###############################################################
#  Generated by:      Cadence Innovus 20.13-s083_1
#  OS:                Linux x86_64(Host ID caddy15)
#  Generated on:      Mon Jun 14 11:36:20 2021
#  Design:            user_proj_example
#  Command:           write_lef_abstract -specifyTopLayer 6 -PGPinLayers {5 6} -noCutObs -stripePin results/user_proj_example.lef
###############################################################

VERSION 5.8 ;

BUSBITCHARS "[]" ;
DIVIDERCHAR "/" ;

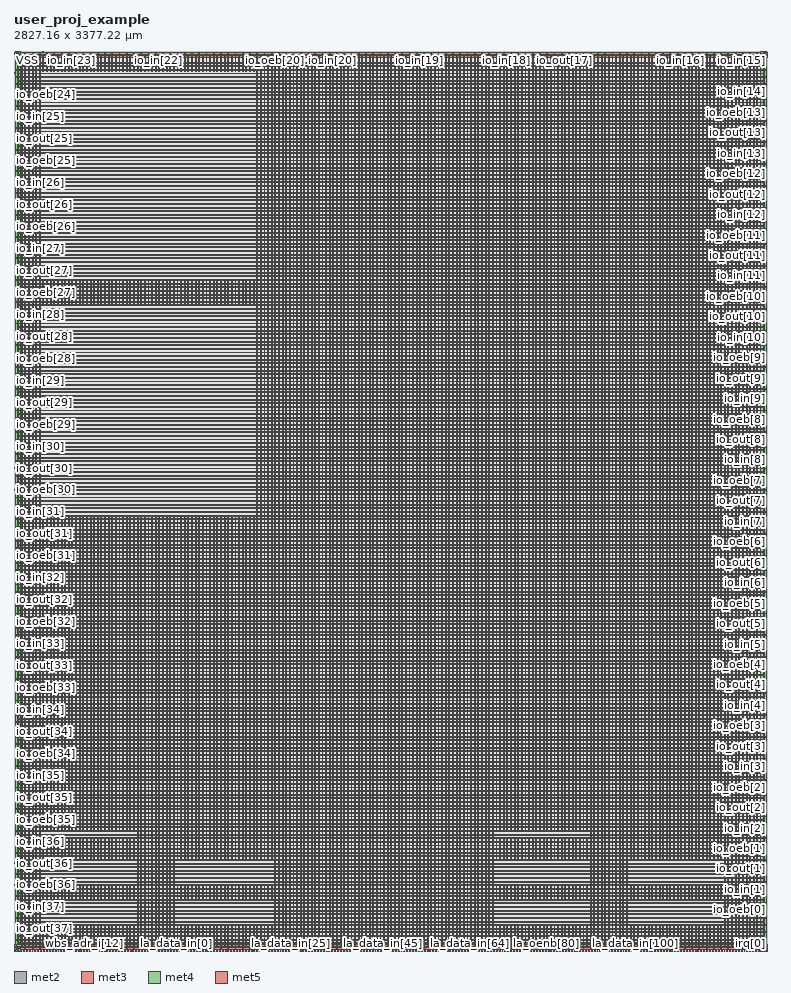
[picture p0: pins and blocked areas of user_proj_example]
MACRO user_proj_example
  CLASS BLOCK ;
  SIZE 2827.160000 BY 3377.220000 ;
  FOREIGN user_proj_example 0.000000 0.000000 ;
  ORIGIN 0 0 ;
  SYMMETRY X Y R90 ;
  PIN wb_clk_i
    DIRECTION INPUT ;
    USE SIGNAL ;
    ANTENNAPARTIALMETALAREA 4.2672 LAYER met2  ;
    ANTENNAPARTIALMETALSIDEAREA 21.175 LAYER met2  ;
    ANTENNAPARTIALCUTAREA 0.04 LAYER via2  ;
    ANTENNAPARTIALMETALAREA 9.3648 LAYER met3  ;
    ANTENNAPARTIALMETALSIDEAREA 50.416 LAYER met3  ;
    ANTENNAMODEL OXIDE1 ;
    ANTENNAGATEAREA 1.152 LAYER met3  ;
    ANTENNAMAXAREACAR 8.78331 LAYER met3  ;
    ANTENNAMAXSIDEAREACAR 45.1719 LAYER met3  ;
    ANTENNAMAXCUTCAR 0.0793403 LAYER via3  ;
    PORT
      LAYER met2 ;
        RECT 0.160000 0.000000 0.300000 0.485000 ;
    END
  END wb_clk_i
  PIN wb_rst_i
    DIRECTION INPUT ;
    USE SIGNAL ;
    ANTENNAPARTIALMETALAREA 4.4911 LAYER met2  ;
    ANTENNAPARTIALMETALSIDEAREA 22.3475 LAYER met2  ;
    ANTENNAMODEL OXIDE1 ;
    ANTENNAGATEAREA 1.33 LAYER met2  ;
    ANTENNAMAXAREACAR 6.34038 LAYER met2  ;
    ANTENNAMAXSIDEAREACAR 30.9594 LAYER met2  ;
    ANTENNAMAXCUTCAR 0.0386466 LAYER via2  ;
    PORT
      LAYER met2 ;
        RECT 6.140000 0.000000 6.280000 0.485000 ;
    END
  END wb_rst_i
  PIN wbs_stb_i
    DIRECTION INPUT ;
    USE SIGNAL ;
    PORT
      LAYER met2 ;
        RECT 23.160000 0.000000 23.300000 0.485000 ;
    END
  END wbs_stb_i
  PIN wbs_cyc_i
    DIRECTION INPUT ;
    USE SIGNAL ;
    PORT
      LAYER met2 ;
        RECT 17.640000 0.000000 17.780000 0.485000 ;
    END
  END wbs_cyc_i
  PIN wbs_we_i
    DIRECTION INPUT ;
    USE SIGNAL ;
    PORT
      LAYER met2 ;
        RECT 29.140000 0.000000 29.280000 0.485000 ;
    END
  END wbs_we_i
  PIN wbs_sel_i[3]
    DIRECTION INPUT ;
    USE SIGNAL ;
    PORT
      LAYER met2 ;
        RECT 121.140000 0.000000 121.280000 0.485000 ;
    END
  END wbs_sel_i[3]
  PIN wbs_sel_i[2]
    DIRECTION INPUT ;
    USE SIGNAL ;
    PORT
      LAYER met2 ;
        RECT 98.140000 0.000000 98.280000 0.485000 ;
    END
  END wbs_sel_i[2]
  PIN wbs_sel_i[1]
    DIRECTION INPUT ;
    USE SIGNAL ;
    PORT
      LAYER met2 ;
        RECT 75.140000 0.000000 75.280000 0.485000 ;
    END
  END wbs_sel_i[1]
  PIN wbs_sel_i[0]
    DIRECTION INPUT ;
    USE SIGNAL ;
    PORT
      LAYER met2 ;
        RECT 52.140000 0.000000 52.280000 0.485000 ;
    END
  END wbs_sel_i[0]
  PIN wbs_dat_i[31]
    DIRECTION INPUT ;
    USE SIGNAL ;
    PORT
      LAYER met2 ;
        RECT 597.700000 0.000000 597.840000 0.485000 ;
    END
  END wbs_dat_i[31]
  PIN wbs_dat_i[30]
    DIRECTION INPUT ;
    USE SIGNAL ;
    PORT
      LAYER met2 ;
        RECT 580.680000 0.000000 580.820000 0.485000 ;
    END
  END wbs_dat_i[30]
  PIN wbs_dat_i[29]
    DIRECTION INPUT ;
    USE SIGNAL ;
    PORT
      LAYER met2 ;
        RECT 563.660000 0.000000 563.800000 0.485000 ;
    END
  END wbs_dat_i[29]
  PIN wbs_dat_i[28]
    DIRECTION INPUT ;
    USE SIGNAL ;
    PORT
      LAYER met2 ;
        RECT 546.180000 0.000000 546.320000 0.485000 ;
    END
  END wbs_dat_i[28]
  PIN wbs_dat_i[27]
    DIRECTION INPUT ;
    USE SIGNAL ;
    PORT
      LAYER met2 ;
        RECT 529.160000 0.000000 529.300000 0.485000 ;
    END
  END wbs_dat_i[27]
  PIN wbs_dat_i[26]
    DIRECTION INPUT ;
    USE SIGNAL ;
    PORT
      LAYER met2 ;
        RECT 511.680000 0.000000 511.820000 0.485000 ;
    END
  END wbs_dat_i[26]
  PIN wbs_dat_i[25]
    DIRECTION INPUT ;
    USE SIGNAL ;
    PORT
      LAYER met2 ;
        RECT 494.660000 0.000000 494.800000 0.485000 ;
    END
  END wbs_dat_i[25]
  PIN wbs_dat_i[24]
    DIRECTION INPUT ;
    USE SIGNAL ;
    PORT
      LAYER met2 ;
        RECT 477.180000 0.000000 477.320000 0.485000 ;
    END
  END wbs_dat_i[24]
  PIN wbs_dat_i[23]
    DIRECTION INPUT ;
    USE SIGNAL ;
    PORT
      LAYER met2 ;
        RECT 460.160000 0.000000 460.300000 0.485000 ;
    END
  END wbs_dat_i[23]
  PIN wbs_dat_i[22]
    DIRECTION INPUT ;
    USE SIGNAL ;
    PORT
      LAYER met2 ;
        RECT 442.680000 0.000000 442.820000 0.485000 ;
    END
  END wbs_dat_i[22]
  PIN wbs_dat_i[21]
    DIRECTION INPUT ;
    USE SIGNAL ;
    PORT
      LAYER met2 ;
        RECT 425.660000 0.000000 425.800000 0.485000 ;
    END
  END wbs_dat_i[21]
  PIN wbs_dat_i[20]
    DIRECTION INPUT ;
    USE SIGNAL ;
    PORT
      LAYER met2 ;
        RECT 408.180000 0.000000 408.320000 0.485000 ;
    END
  END wbs_dat_i[20]
  PIN wbs_dat_i[19]
    DIRECTION INPUT ;
    USE SIGNAL ;
    PORT
      LAYER met2 ;
        RECT 391.160000 0.000000 391.300000 0.485000 ;
    END
  END wbs_dat_i[19]
  PIN wbs_dat_i[18]
    DIRECTION INPUT ;
    USE SIGNAL ;
    PORT
      LAYER met2 ;
        RECT 373.680000 0.000000 373.820000 0.485000 ;
    END
  END wbs_dat_i[18]
  PIN wbs_dat_i[17]
    DIRECTION INPUT ;
    USE SIGNAL ;
    PORT
      LAYER met2 ;
        RECT 356.660000 0.000000 356.800000 0.485000 ;
    END
  END wbs_dat_i[17]
  PIN wbs_dat_i[16]
    DIRECTION INPUT ;
    USE SIGNAL ;
    PORT
      LAYER met2 ;
        RECT 339.180000 0.000000 339.320000 0.485000 ;
    END
  END wbs_dat_i[16]
  PIN wbs_dat_i[15]
    DIRECTION INPUT ;
    USE SIGNAL ;
    PORT
      LAYER met2 ;
        RECT 322.160000 0.000000 322.300000 0.485000 ;
    END
  END wbs_dat_i[15]
  PIN wbs_dat_i[14]
    DIRECTION INPUT ;
    USE SIGNAL ;
    PORT
      LAYER met2 ;
        RECT 304.680000 0.000000 304.820000 0.485000 ;
    END
  END wbs_dat_i[14]
  PIN wbs_dat_i[13]
    DIRECTION INPUT ;
    USE SIGNAL ;
    PORT
      LAYER met2 ;
        RECT 287.660000 0.000000 287.800000 0.485000 ;
    END
  END wbs_dat_i[13]
  PIN wbs_dat_i[12]
    DIRECTION INPUT ;
    USE SIGNAL ;
    PORT
      LAYER met2 ;
        RECT 270.640000 0.000000 270.780000 0.485000 ;
    END
  END wbs_dat_i[12]
  PIN wbs_dat_i[11]
    DIRECTION INPUT ;
    USE SIGNAL ;
    PORT
      LAYER met2 ;
        RECT 253.160000 0.000000 253.300000 0.485000 ;
    END
  END wbs_dat_i[11]
  PIN wbs_dat_i[10]
    DIRECTION INPUT ;
    USE SIGNAL ;
    PORT
      LAYER met2 ;
        RECT 236.140000 0.000000 236.280000 0.485000 ;
    END
  END wbs_dat_i[10]
  PIN wbs_dat_i[9]
    DIRECTION INPUT ;
    USE SIGNAL ;
    PORT
      LAYER met2 ;
        RECT 218.660000 0.000000 218.800000 0.485000 ;
    END
  END wbs_dat_i[9]
  PIN wbs_dat_i[8]
    DIRECTION INPUT ;
    USE SIGNAL ;
    PORT
      LAYER met2 ;
        RECT 201.640000 0.000000 201.780000 0.485000 ;
    END
  END wbs_dat_i[8]
  PIN wbs_dat_i[7]
    DIRECTION INPUT ;
    USE SIGNAL ;
    PORT
      LAYER met2 ;
        RECT 184.160000 0.000000 184.300000 0.485000 ;
    END
  END wbs_dat_i[7]
  PIN wbs_dat_i[6]
    DIRECTION INPUT ;
    USE SIGNAL ;
    PORT
      LAYER met2 ;
        RECT 167.140000 0.000000 167.280000 0.485000 ;
    END
  END wbs_dat_i[6]
  PIN wbs_dat_i[5]
    DIRECTION INPUT ;
    USE SIGNAL ;
    PORT
      LAYER met2 ;
        RECT 149.660000 0.000000 149.800000 0.485000 ;
    END
  END wbs_dat_i[5]
  PIN wbs_dat_i[4]
    DIRECTION INPUT ;
    USE SIGNAL ;
    PORT
      LAYER met2 ;
        RECT 132.640000 0.000000 132.780000 0.485000 ;
    END
  END wbs_dat_i[4]
  PIN wbs_dat_i[3]
    DIRECTION INPUT ;
    USE SIGNAL ;
    PORT
      LAYER met2 ;
        RECT 109.640000 0.000000 109.780000 0.485000 ;
    END
  END wbs_dat_i[3]
  PIN wbs_dat_i[2]
    DIRECTION INPUT ;
    USE SIGNAL ;
    PORT
      LAYER met2 ;
        RECT 86.640000 0.000000 86.780000 0.485000 ;
    END
  END wbs_dat_i[2]
  PIN wbs_dat_i[1]
    DIRECTION INPUT ;
    USE SIGNAL ;
    PORT
      LAYER met2 ;
        RECT 63.640000 0.000000 63.780000 0.485000 ;
    END
  END wbs_dat_i[1]
  PIN wbs_dat_i[0]
    DIRECTION INPUT ;
    USE SIGNAL ;
    PORT
      LAYER met2 ;
        RECT 40.640000 0.000000 40.780000 0.485000 ;
    END
  END wbs_dat_i[0]
  PIN wbs_adr_i[31]
    DIRECTION INPUT ;
    USE SIGNAL ;
    PORT
      LAYER met2 ;
        RECT 592.180000 0.000000 592.320000 0.485000 ;
    END
  END wbs_adr_i[31]
  PIN wbs_adr_i[30]
    DIRECTION INPUT ;
    USE SIGNAL ;
    PORT
      LAYER met2 ;
        RECT 574.700000 0.000000 574.840000 0.485000 ;
    END
  END wbs_adr_i[30]
  PIN wbs_adr_i[29]
    DIRECTION INPUT ;
    USE SIGNAL ;
    PORT
      LAYER met2 ;
        RECT 557.680000 0.000000 557.820000 0.485000 ;
    END
  END wbs_adr_i[29]
  PIN wbs_adr_i[28]
    DIRECTION INPUT ;
    USE SIGNAL ;
    PORT
      LAYER met2 ;
        RECT 540.660000 0.000000 540.800000 0.485000 ;
    END
  END wbs_adr_i[28]
  PIN wbs_adr_i[27]
    DIRECTION INPUT ;
    USE SIGNAL ;
    PORT
      LAYER met2 ;
        RECT 523.180000 0.000000 523.320000 0.485000 ;
    END
  END wbs_adr_i[27]
  PIN wbs_adr_i[26]
    DIRECTION INPUT ;
    USE SIGNAL ;
    PORT
      LAYER met2 ;
        RECT 506.160000 0.000000 506.300000 0.485000 ;
    END
  END wbs_adr_i[26]
  PIN wbs_adr_i[25]
    DIRECTION INPUT ;
    USE SIGNAL ;
    PORT
      LAYER met2 ;
        RECT 488.680000 0.000000 488.820000 0.485000 ;
    END
  END wbs_adr_i[25]
  PIN wbs_adr_i[24]
    DIRECTION INPUT ;
    USE SIGNAL ;
    PORT
      LAYER met2 ;
        RECT 471.660000 0.000000 471.800000 0.485000 ;
    END
  END wbs_adr_i[24]
  PIN wbs_adr_i[23]
    DIRECTION INPUT ;
    USE SIGNAL ;
    PORT
      LAYER met2 ;
        RECT 454.180000 0.000000 454.320000 0.485000 ;
    END
  END wbs_adr_i[23]
  PIN wbs_adr_i[22]
    DIRECTION INPUT ;
    USE SIGNAL ;
    PORT
      LAYER met2 ;
        RECT 437.160000 0.000000 437.300000 0.485000 ;
    END
  END wbs_adr_i[22]
  PIN wbs_adr_i[21]
    DIRECTION INPUT ;
    USE SIGNAL ;
    PORT
      LAYER met2 ;
        RECT 419.680000 0.000000 419.820000 0.485000 ;
    END
  END wbs_adr_i[21]
  PIN wbs_adr_i[20]
    DIRECTION INPUT ;
    USE SIGNAL ;
    PORT
      LAYER met2 ;
        RECT 402.660000 0.000000 402.800000 0.485000 ;
    END
  END wbs_adr_i[20]
  PIN wbs_adr_i[19]
    DIRECTION INPUT ;
    USE SIGNAL ;
    PORT
      LAYER met2 ;
        RECT 385.180000 0.000000 385.320000 0.485000 ;
    END
  END wbs_adr_i[19]
  PIN wbs_adr_i[18]
    DIRECTION INPUT ;
    USE SIGNAL ;
    PORT
      LAYER met2 ;
        RECT 368.160000 0.000000 368.300000 0.485000 ;
    END
  END wbs_adr_i[18]
  PIN wbs_adr_i[17]
    DIRECTION INPUT ;
    USE SIGNAL ;
    PORT
      LAYER met2 ;
        RECT 350.680000 0.000000 350.820000 0.485000 ;
    END
  END wbs_adr_i[17]
  PIN wbs_adr_i[16]
    DIRECTION INPUT ;
    USE SIGNAL ;
    PORT
      LAYER met2 ;
        RECT 333.660000 0.000000 333.800000 0.485000 ;
    END
  END wbs_adr_i[16]
  PIN wbs_adr_i[15]
    DIRECTION INPUT ;
    USE SIGNAL ;
    PORT
      LAYER met2 ;
        RECT 316.180000 0.000000 316.320000 0.485000 ;
    END
  END wbs_adr_i[15]
  PIN wbs_adr_i[14]
    DIRECTION INPUT ;
    USE SIGNAL ;
    PORT
      LAYER met2 ;
        RECT 299.160000 0.000000 299.300000 0.485000 ;
    END
  END wbs_adr_i[14]
  PIN wbs_adr_i[13]
    DIRECTION INPUT ;
    USE SIGNAL ;
    PORT
      LAYER met2 ;
        RECT 282.140000 0.000000 282.280000 0.485000 ;
    END
  END wbs_adr_i[13]
  PIN wbs_adr_i[12]
    DIRECTION INPUT ;
    USE SIGNAL ;
    PORT
      LAYER met2 ;
        RECT 264.660000 0.000000 264.800000 0.485000 ;
    END
  END wbs_adr_i[12]
  PIN wbs_adr_i[11]
    DIRECTION INPUT ;
    USE SIGNAL ;
    PORT
      LAYER met2 ;
        RECT 247.640000 0.000000 247.780000 0.485000 ;
    END
  END wbs_adr_i[11]
  PIN wbs_adr_i[10]
    DIRECTION INPUT ;
    USE SIGNAL ;
    PORT
      LAYER met2 ;
        RECT 230.160000 0.000000 230.300000 0.485000 ;
    END
  END wbs_adr_i[10]
  PIN wbs_adr_i[9]
    DIRECTION INPUT ;
    USE SIGNAL ;
    PORT
      LAYER met2 ;
        RECT 213.140000 0.000000 213.280000 0.485000 ;
    END
  END wbs_adr_i[9]
  PIN wbs_adr_i[8]
    DIRECTION INPUT ;
    USE SIGNAL ;
    PORT
      LAYER met2 ;
        RECT 195.660000 0.000000 195.800000 0.485000 ;
    END
  END wbs_adr_i[8]
  PIN wbs_adr_i[7]
    DIRECTION INPUT ;
    USE SIGNAL ;
    PORT
      LAYER met2 ;
        RECT 178.640000 0.000000 178.780000 0.485000 ;
    END
  END wbs_adr_i[7]
  PIN wbs_adr_i[6]
    DIRECTION INPUT ;
    USE SIGNAL ;
    PORT
      LAYER met2 ;
        RECT 161.160000 0.000000 161.300000 0.485000 ;
    END
  END wbs_adr_i[6]
  PIN wbs_adr_i[5]
    DIRECTION INPUT ;
    USE SIGNAL ;
    PORT
      LAYER met2 ;
        RECT 144.140000 0.000000 144.280000 0.485000 ;
    END
  END wbs_adr_i[5]
  PIN wbs_adr_i[4]
    DIRECTION INPUT ;
    USE SIGNAL ;
    PORT
      LAYER met2 ;
        RECT 126.660000 0.000000 126.800000 0.485000 ;
    END
  END wbs_adr_i[4]
  PIN wbs_adr_i[3]
    DIRECTION INPUT ;
    USE SIGNAL ;
    PORT
      LAYER met2 ;
        RECT 103.660000 0.000000 103.800000 0.485000 ;
    END
  END wbs_adr_i[3]
  PIN wbs_adr_i[2]
    DIRECTION INPUT ;
    USE SIGNAL ;
    PORT
      LAYER met2 ;
        RECT 80.660000 0.000000 80.800000 0.485000 ;
    END
  END wbs_adr_i[2]
  PIN wbs_adr_i[1]
    DIRECTION INPUT ;
    USE SIGNAL ;
    PORT
      LAYER met2 ;
        RECT 57.660000 0.000000 57.800000 0.485000 ;
    END
  END wbs_adr_i[1]
  PIN wbs_adr_i[0]
    DIRECTION INPUT ;
    USE SIGNAL ;
    PORT
      LAYER met2 ;
        RECT 34.660000 0.000000 34.800000 0.485000 ;
    END
  END wbs_adr_i[0]
  PIN wbs_ack_o
    DIRECTION OUTPUT ;
    USE SIGNAL ;
    PORT
      LAYER met2 ;
        RECT 11.660000 0.000000 11.800000 0.485000 ;
    END
  END wbs_ack_o
  PIN wbs_dat_o[31]
    DIRECTION OUTPUT ;
    USE SIGNAL ;
    PORT
      LAYER met2 ;
        RECT 603.680000 0.000000 603.820000 0.485000 ;
    END
  END wbs_dat_o[31]
  PIN wbs_dat_o[30]
    DIRECTION OUTPUT ;
    USE SIGNAL ;
    PORT
      LAYER met2 ;
        RECT 586.200000 0.000000 586.340000 0.485000 ;
    END
  END wbs_dat_o[30]
  PIN wbs_dat_o[29]
    DIRECTION OUTPUT ;
    USE SIGNAL ;
    PORT
      LAYER met2 ;
        RECT 569.180000 0.000000 569.320000 0.485000 ;
    END
  END wbs_dat_o[29]
  PIN wbs_dat_o[28]
    DIRECTION OUTPUT ;
    USE SIGNAL ;
    PORT
      LAYER met2 ;
        RECT 552.160000 0.000000 552.300000 0.485000 ;
    END
  END wbs_dat_o[28]
  PIN wbs_dat_o[27]
    DIRECTION OUTPUT ;
    USE SIGNAL ;
    PORT
      LAYER met2 ;
        RECT 534.680000 0.000000 534.820000 0.485000 ;
    END
  END wbs_dat_o[27]
  PIN wbs_dat_o[26]
    DIRECTION OUTPUT ;
    USE SIGNAL ;
    PORT
      LAYER met2 ;
        RECT 517.660000 0.000000 517.800000 0.485000 ;
    END
  END wbs_dat_o[26]
  PIN wbs_dat_o[25]
    DIRECTION OUTPUT ;
    USE SIGNAL ;
    PORT
      LAYER met2 ;
        RECT 500.180000 0.000000 500.320000 0.485000 ;
    END
  END wbs_dat_o[25]
  PIN wbs_dat_o[24]
    DIRECTION OUTPUT ;
    USE SIGNAL ;
    PORT
      LAYER met2 ;
        RECT 483.160000 0.000000 483.300000 0.485000 ;
    END
  END wbs_dat_o[24]
  PIN wbs_dat_o[23]
    DIRECTION OUTPUT ;
    USE SIGNAL ;
    PORT
      LAYER met2 ;
        RECT 465.680000 0.000000 465.820000 0.485000 ;
    END
  END wbs_dat_o[23]
  PIN wbs_dat_o[22]
    DIRECTION OUTPUT ;
    USE SIGNAL ;
    PORT
      LAYER met2 ;
        RECT 448.660000 0.000000 448.800000 0.485000 ;
    END
  END wbs_dat_o[22]
  PIN wbs_dat_o[21]
    DIRECTION OUTPUT ;
    USE SIGNAL ;
    PORT
      LAYER met2 ;
        RECT 431.180000 0.000000 431.320000 0.485000 ;
    END
  END wbs_dat_o[21]
  PIN wbs_dat_o[20]
    DIRECTION OUTPUT ;
    USE SIGNAL ;
    PORT
      LAYER met2 ;
        RECT 414.160000 0.000000 414.300000 0.485000 ;
    END
  END wbs_dat_o[20]
  PIN wbs_dat_o[19]
    DIRECTION OUTPUT ;
    USE SIGNAL ;
    PORT
      LAYER met2 ;
        RECT 396.680000 0.000000 396.820000 0.485000 ;
    END
  END wbs_dat_o[19]
  PIN wbs_dat_o[18]
    DIRECTION OUTPUT ;
    USE SIGNAL ;
    PORT
      LAYER met2 ;
        RECT 379.660000 0.000000 379.800000 0.485000 ;
    END
  END wbs_dat_o[18]
  PIN wbs_dat_o[17]
    DIRECTION OUTPUT ;
    USE SIGNAL ;
    PORT
      LAYER met2 ;
        RECT 362.180000 0.000000 362.320000 0.485000 ;
    END
  END wbs_dat_o[17]
  PIN wbs_dat_o[16]
    DIRECTION OUTPUT ;
    USE SIGNAL ;
    PORT
      LAYER met2 ;
        RECT 345.160000 0.000000 345.300000 0.485000 ;
    END
  END wbs_dat_o[16]
  PIN wbs_dat_o[15]
    DIRECTION OUTPUT ;
    USE SIGNAL ;
    PORT
      LAYER met2 ;
        RECT 327.680000 0.000000 327.820000 0.485000 ;
    END
  END wbs_dat_o[15]
  PIN wbs_dat_o[14]
    DIRECTION OUTPUT ;
    USE SIGNAL ;
    PORT
      LAYER met2 ;
        RECT 310.660000 0.000000 310.800000 0.485000 ;
    END
  END wbs_dat_o[14]
  PIN wbs_dat_o[13]
    DIRECTION OUTPUT ;
    USE SIGNAL ;
    PORT
      LAYER met2 ;
        RECT 293.180000 0.000000 293.320000 0.485000 ;
    END
  END wbs_dat_o[13]
  PIN wbs_dat_o[12]
    DIRECTION OUTPUT ;
    USE SIGNAL ;
    PORT
      LAYER met2 ;
        RECT 276.160000 0.000000 276.300000 0.485000 ;
    END
  END wbs_dat_o[12]
  PIN wbs_dat_o[11]
    DIRECTION OUTPUT ;
    USE SIGNAL ;
    PORT
      LAYER met2 ;
        RECT 259.140000 0.000000 259.280000 0.485000 ;
    END
  END wbs_dat_o[11]
  PIN wbs_dat_o[10]
    DIRECTION OUTPUT ;
    USE SIGNAL ;
    PORT
      LAYER met2 ;
        RECT 241.660000 0.000000 241.800000 0.485000 ;
    END
  END wbs_dat_o[10]
  PIN wbs_dat_o[9]
    DIRECTION OUTPUT ;
    USE SIGNAL ;
    PORT
      LAYER met2 ;
        RECT 224.640000 0.000000 224.780000 0.485000 ;
    END
  END wbs_dat_o[9]
  PIN wbs_dat_o[8]
    DIRECTION OUTPUT ;
    USE SIGNAL ;
    PORT
      LAYER met2 ;
        RECT 207.160000 0.000000 207.300000 0.485000 ;
    END
  END wbs_dat_o[8]
  PIN wbs_dat_o[7]
    DIRECTION OUTPUT ;
    USE SIGNAL ;
    PORT
      LAYER met2 ;
        RECT 190.140000 0.000000 190.280000 0.485000 ;
    END
  END wbs_dat_o[7]
  PIN wbs_dat_o[6]
    DIRECTION OUTPUT ;
    USE SIGNAL ;
    PORT
      LAYER met2 ;
        RECT 172.660000 0.000000 172.800000 0.485000 ;
    END
  END wbs_dat_o[6]
  PIN wbs_dat_o[5]
    DIRECTION OUTPUT ;
    USE SIGNAL ;
    PORT
      LAYER met2 ;
        RECT 155.640000 0.000000 155.780000 0.485000 ;
    END
  END wbs_dat_o[5]
  PIN wbs_dat_o[4]
    DIRECTION OUTPUT ;
    USE SIGNAL ;
    PORT
      LAYER met2 ;
        RECT 138.160000 0.000000 138.300000 0.485000 ;
    END
  END wbs_dat_o[4]
  PIN wbs_dat_o[3]
    DIRECTION OUTPUT ;
    USE SIGNAL ;
    PORT
      LAYER met2 ;
        RECT 115.160000 0.000000 115.300000 0.485000 ;
    END
  END wbs_dat_o[3]
  PIN wbs_dat_o[2]
    DIRECTION OUTPUT ;
    USE SIGNAL ;
    PORT
      LAYER met2 ;
        RECT 92.160000 0.000000 92.300000 0.485000 ;
    END
  END wbs_dat_o[2]
  PIN wbs_dat_o[1]
    DIRECTION OUTPUT ;
    USE SIGNAL ;
    PORT
      LAYER met2 ;
        RECT 69.160000 0.000000 69.300000 0.485000 ;
    END
  END wbs_dat_o[1]
  PIN wbs_dat_o[0]
    DIRECTION OUTPUT ;
    USE SIGNAL ;
    PORT
      LAYER met2 ;
        RECT 46.160000 0.000000 46.300000 0.485000 ;
    END
  END wbs_dat_o[0]
  PIN la_data_in[127]
    DIRECTION INPUT ;
    USE SIGNAL ;
    PORT
      LAYER met2 ;
        RECT 2798.340000 0.000000 2798.480000 0.485000 ;
    END
  END la_data_in[127]
  PIN la_data_in[126]
    DIRECTION INPUT ;
    USE SIGNAL ;
    PORT
      LAYER met2 ;
        RECT 2781.320000 0.000000 2781.460000 0.485000 ;
    END
  END la_data_in[126]
  PIN la_data_in[125]
    DIRECTION INPUT ;
    USE SIGNAL ;
    PORT
      LAYER met2 ;
        RECT 2763.840000 0.000000 2763.980000 0.485000 ;
    END
  END la_data_in[125]
  PIN la_data_in[124]
    DIRECTION INPUT ;
    USE SIGNAL ;
    PORT
      LAYER met2 ;
        RECT 2746.820000 0.000000 2746.960000 0.485000 ;
    END
  END la_data_in[124]
  PIN la_data_in[123]
    DIRECTION INPUT ;
    USE SIGNAL ;
    PORT
      LAYER met2 ;
        RECT 2729.340000 0.000000 2729.480000 0.485000 ;
    END
  END la_data_in[123]
  PIN la_data_in[122]
    DIRECTION INPUT ;
    USE SIGNAL ;
    PORT
      LAYER met2 ;
        RECT 2712.320000 0.000000 2712.460000 0.485000 ;
    END
  END la_data_in[122]
  PIN la_data_in[121]
    DIRECTION INPUT ;
    USE SIGNAL ;
    PORT
      LAYER met2 ;
        RECT 2694.840000 0.000000 2694.980000 0.485000 ;
    END
  END la_data_in[121]
  PIN la_data_in[120]
    DIRECTION INPUT ;
    USE SIGNAL ;
    PORT
      LAYER met2 ;
        RECT 2677.820000 0.000000 2677.960000 0.485000 ;
    END
  END la_data_in[120]
  PIN la_data_in[119]
    DIRECTION INPUT ;
    USE SIGNAL ;
    PORT
      LAYER met2 ;
        RECT 2660.340000 0.000000 2660.480000 0.485000 ;
    END
  END la_data_in[119]
  PIN la_data_in[118]
    DIRECTION INPUT ;
    USE SIGNAL ;
    PORT
      LAYER met2 ;
        RECT 2643.320000 0.000000 2643.460000 0.485000 ;
    END
  END la_data_in[118]
  PIN la_data_in[117]
    DIRECTION INPUT ;
    USE SIGNAL ;
    PORT
      LAYER met2 ;
        RECT 2625.840000 0.000000 2625.980000 0.485000 ;
    END
  END la_data_in[117]
  PIN la_data_in[116]
    DIRECTION INPUT ;
    USE SIGNAL ;
    PORT
      LAYER met2 ;
        RECT 2608.820000 0.000000 2608.960000 0.485000 ;
    END
  END la_data_in[116]
  PIN la_data_in[115]
    DIRECTION INPUT ;
    USE SIGNAL ;
    PORT
      LAYER met2 ;
        RECT 2591.340000 0.000000 2591.480000 0.485000 ;
    END
  END la_data_in[115]
  PIN la_data_in[114]
    DIRECTION INPUT ;
    USE SIGNAL ;
    PORT
      LAYER met2 ;
        RECT 2574.320000 0.000000 2574.460000 0.485000 ;
    END
  END la_data_in[114]
  PIN la_data_in[113]
    DIRECTION INPUT ;
    USE SIGNAL ;
    PORT
      LAYER met2 ;
        RECT 2556.840000 0.000000 2556.980000 0.485000 ;
    END
  END la_data_in[113]
  PIN la_data_in[112]
    DIRECTION INPUT ;
    USE SIGNAL ;
    PORT
      LAYER met2 ;
        RECT 2539.820000 0.000000 2539.960000 0.485000 ;
    END
  END la_data_in[112]
  PIN la_data_in[111]
    DIRECTION INPUT ;
    USE SIGNAL ;
    PORT
      LAYER met2 ;
        RECT 2522.800000 0.000000 2522.940000 0.485000 ;
    END
  END la_data_in[111]
  PIN la_data_in[110]
    DIRECTION INPUT ;
    USE SIGNAL ;
    PORT
      LAYER met2 ;
        RECT 2505.320000 0.000000 2505.460000 0.485000 ;
    END
  END la_data_in[110]
  PIN la_data_in[109]
    DIRECTION INPUT ;
    USE SIGNAL ;
    PORT
      LAYER met2 ;
        RECT 2488.300000 0.000000 2488.440000 0.485000 ;
    END
  END la_data_in[109]
  PIN la_data_in[108]
    DIRECTION INPUT ;
    USE SIGNAL ;
    PORT
      LAYER met2 ;
        RECT 2470.820000 0.000000 2470.960000 0.485000 ;
    END
  END la_data_in[108]
  PIN la_data_in[107]
    DIRECTION INPUT ;
    USE SIGNAL ;
    PORT
      LAYER met2 ;
        RECT 2453.800000 0.000000 2453.940000 0.485000 ;
    END
  END la_data_in[107]
  PIN la_data_in[106]
    DIRECTION INPUT ;
    USE SIGNAL ;
    PORT
      LAYER met2 ;
        RECT 2436.320000 0.000000 2436.460000 0.485000 ;
    END
  END la_data_in[106]
  PIN la_data_in[105]
    DIRECTION INPUT ;
    USE SIGNAL ;
    PORT
      LAYER met2 ;
        RECT 2419.300000 0.000000 2419.440000 0.485000 ;
    END
  END la_data_in[105]
  PIN la_data_in[104]
    DIRECTION INPUT ;
    USE SIGNAL ;
    PORT
      LAYER met2 ;
        RECT 2401.820000 0.000000 2401.960000 0.485000 ;
    END
  END la_data_in[104]
  PIN la_data_in[103]
    DIRECTION INPUT ;
    USE SIGNAL ;
    PORT
      LAYER met2 ;
        RECT 2384.800000 0.000000 2384.940000 0.485000 ;
    END
  END la_data_in[103]
  PIN la_data_in[102]
    DIRECTION INPUT ;
    USE SIGNAL ;
    PORT
      LAYER met2 ;
        RECT 2367.320000 0.000000 2367.460000 0.485000 ;
    END
  END la_data_in[102]
  PIN la_data_in[101]
    DIRECTION INPUT ;
    USE SIGNAL ;
    PORT
      LAYER met2 ;
        RECT 2350.300000 0.000000 2350.440000 0.485000 ;
    END
  END la_data_in[101]
  PIN la_data_in[100]
    DIRECTION INPUT ;
    USE SIGNAL ;
    PORT
      LAYER met2 ;
        RECT 2332.820000 0.000000 2332.960000 0.485000 ;
    END
  END la_data_in[100]
  PIN la_data_in[99]
    DIRECTION INPUT ;
    USE SIGNAL ;
    PORT
      LAYER met2 ;
        RECT 2315.800000 0.000000 2315.940000 0.485000 ;
    END
  END la_data_in[99]
  PIN la_data_in[98]
    DIRECTION INPUT ;
    USE SIGNAL ;
    PORT
      LAYER met2 ;
        RECT 2298.320000 0.000000 2298.460000 0.485000 ;
    END
  END la_data_in[98]
  PIN la_data_in[97]
    DIRECTION INPUT ;
    USE SIGNAL ;
    PORT
      LAYER met2 ;
        RECT 2281.300000 0.000000 2281.440000 0.485000 ;
    END
  END la_data_in[97]
  PIN la_data_in[96]
    DIRECTION INPUT ;
    USE SIGNAL ;
    PORT
      LAYER met2 ;
        RECT 2263.820000 0.000000 2263.960000 0.485000 ;
    END
  END la_data_in[96]
  PIN la_data_in[95]
    DIRECTION INPUT ;
    USE SIGNAL ;
    PORT
      LAYER met2 ;
        RECT 2246.800000 0.000000 2246.940000 0.485000 ;
    END
  END la_data_in[95]
  PIN la_data_in[94]
    DIRECTION INPUT ;
    USE SIGNAL ;
    PORT
      LAYER met2 ;
        RECT 2229.780000 0.000000 2229.920000 0.485000 ;
    END
  END la_data_in[94]
  PIN la_data_in[93]
    DIRECTION INPUT ;
    USE SIGNAL ;
    PORT
      LAYER met2 ;
        RECT 2212.300000 0.000000 2212.440000 0.485000 ;
    END
  END la_data_in[93]
  PIN la_data_in[92]
    DIRECTION INPUT ;
    USE SIGNAL ;
    PORT
      LAYER met2 ;
        RECT 2195.280000 0.000000 2195.420000 0.485000 ;
    END
  END la_data_in[92]
  PIN la_data_in[91]
    DIRECTION INPUT ;
    USE SIGNAL ;
    PORT
      LAYER met2 ;
        RECT 2177.800000 0.000000 2177.940000 0.485000 ;
    END
  END la_data_in[91]
  PIN la_data_in[90]
    DIRECTION INPUT ;
    USE SIGNAL ;
    PORT
      LAYER met2 ;
        RECT 2160.780000 0.000000 2160.920000 0.485000 ;
    END
  END la_data_in[90]
  PIN la_data_in[89]
    DIRECTION INPUT ;
    USE SIGNAL ;
    PORT
      LAYER met2 ;
        RECT 2143.300000 0.000000 2143.440000 0.485000 ;
    END
  END la_data_in[89]
  PIN la_data_in[88]
    DIRECTION INPUT ;
    USE SIGNAL ;
    PORT
      LAYER met2 ;
        RECT 2126.280000 0.000000 2126.420000 0.485000 ;
    END
  END la_data_in[88]
  PIN la_data_in[87]
    DIRECTION INPUT ;
    USE SIGNAL ;
    PORT
      LAYER met2 ;
        RECT 2108.800000 0.000000 2108.940000 0.485000 ;
    END
  END la_data_in[87]
  PIN la_data_in[86]
    DIRECTION INPUT ;
    USE SIGNAL ;
    PORT
      LAYER met2 ;
        RECT 2091.780000 0.000000 2091.920000 0.485000 ;
    END
  END la_data_in[86]
  PIN la_data_in[85]
    DIRECTION INPUT ;
    USE SIGNAL ;
    PORT
      LAYER met2 ;
        RECT 2074.300000 0.000000 2074.440000 0.485000 ;
    END
  END la_data_in[85]
  PIN la_data_in[84]
    DIRECTION INPUT ;
    USE SIGNAL ;
    PORT
      LAYER met2 ;
        RECT 2057.280000 0.000000 2057.420000 0.485000 ;
    END
  END la_data_in[84]
  PIN la_data_in[83]
    DIRECTION INPUT ;
    USE SIGNAL ;
    PORT
      LAYER met2 ;
        RECT 2039.800000 0.000000 2039.940000 0.485000 ;
    END
  END la_data_in[83]
  PIN la_data_in[82]
    DIRECTION INPUT ;
    USE SIGNAL ;
    PORT
      LAYER met2 ;
        RECT 2022.780000 0.000000 2022.920000 0.485000 ;
    END
  END la_data_in[82]
  PIN la_data_in[81]
    DIRECTION INPUT ;
    USE SIGNAL ;
    PORT
      LAYER met2 ;
        RECT 2005.300000 0.000000 2005.440000 0.485000 ;
    END
  END la_data_in[81]
  PIN la_data_in[80]
    DIRECTION INPUT ;
    USE SIGNAL ;
    PORT
      LAYER met2 ;
        RECT 1988.280000 0.000000 1988.420000 0.485000 ;
    END
  END la_data_in[80]
  PIN la_data_in[79]
    DIRECTION INPUT ;
    USE SIGNAL ;
    PORT
      LAYER met2 ;
        RECT 1971.260000 0.000000 1971.400000 0.485000 ;
    END
  END la_data_in[79]
  PIN la_data_in[78]
    DIRECTION INPUT ;
    USE SIGNAL ;
    PORT
      LAYER met2 ;
        RECT 1953.780000 0.000000 1953.920000 0.485000 ;
    END
  END la_data_in[78]
  PIN la_data_in[77]
    DIRECTION INPUT ;
    USE SIGNAL ;
    PORT
      LAYER met2 ;
        RECT 1936.760000 0.000000 1936.900000 0.485000 ;
    END
  END la_data_in[77]
  PIN la_data_in[76]
    DIRECTION INPUT ;
    USE SIGNAL ;
    PORT
      LAYER met2 ;
        RECT 1919.280000 0.000000 1919.420000 0.485000 ;
    END
  END la_data_in[76]
  PIN la_data_in[75]
    DIRECTION INPUT ;
    USE SIGNAL ;
    PORT
      LAYER met2 ;
        RECT 1902.260000 0.000000 1902.400000 0.485000 ;
    END
  END la_data_in[75]
  PIN la_data_in[74]
    DIRECTION INPUT ;
    USE SIGNAL ;
    PORT
      LAYER met2 ;
        RECT 1884.780000 0.000000 1884.920000 0.485000 ;
    END
  END la_data_in[74]
  PIN la_data_in[73]
    DIRECTION INPUT ;
    USE SIGNAL ;
    PORT
      LAYER met2 ;
        RECT 1867.760000 0.000000 1867.900000 0.485000 ;
    END
  END la_data_in[73]
  PIN la_data_in[72]
    DIRECTION INPUT ;
    USE SIGNAL ;
    PORT
      LAYER met2 ;
        RECT 1850.280000 0.000000 1850.420000 0.485000 ;
    END
  END la_data_in[72]
  PIN la_data_in[71]
    DIRECTION INPUT ;
    USE SIGNAL ;
    PORT
      LAYER met2 ;
        RECT 1833.260000 0.000000 1833.400000 0.485000 ;
    END
  END la_data_in[71]
  PIN la_data_in[70]
    DIRECTION INPUT ;
    USE SIGNAL ;
    PORT
      LAYER met2 ;
        RECT 1815.780000 0.000000 1815.920000 0.485000 ;
    END
  END la_data_in[70]
  PIN la_data_in[69]
    DIRECTION INPUT ;
    USE SIGNAL ;
    PORT
      LAYER met2 ;
        RECT 1798.760000 0.000000 1798.900000 0.485000 ;
    END
  END la_data_in[69]
  PIN la_data_in[68]
    DIRECTION INPUT ;
    USE SIGNAL ;
    PORT
      LAYER met2 ;
        RECT 1781.280000 0.000000 1781.420000 0.485000 ;
    END
  END la_data_in[68]
  PIN la_data_in[67]
    DIRECTION INPUT ;
    USE SIGNAL ;
    PORT
      LAYER met2 ;
        RECT 1764.260000 0.000000 1764.400000 0.485000 ;
    END
  END la_data_in[67]
  PIN la_data_in[66]
    DIRECTION INPUT ;
    USE SIGNAL ;
    PORT
      LAYER met2 ;
        RECT 1746.780000 0.000000 1746.920000 0.485000 ;
    END
  END la_data_in[66]
  PIN la_data_in[65]
    DIRECTION INPUT ;
    USE SIGNAL ;
    PORT
      LAYER met2 ;
        RECT 1729.760000 0.000000 1729.900000 0.485000 ;
    END
  END la_data_in[65]
  PIN la_data_in[64]
    DIRECTION INPUT ;
    USE SIGNAL ;
    PORT
      LAYER met2 ;
        RECT 1712.280000 0.000000 1712.420000 0.485000 ;
    END
  END la_data_in[64]
  PIN la_data_in[63]
    DIRECTION INPUT ;
    USE SIGNAL ;
    PORT
      LAYER met2 ;
        RECT 1695.260000 0.000000 1695.400000 0.485000 ;
    END
  END la_data_in[63]
  PIN la_data_in[62]
    DIRECTION INPUT ;
    USE SIGNAL ;
    PORT
      LAYER met2 ;
        RECT 1678.240000 0.000000 1678.380000 0.485000 ;
    END
  END la_data_in[62]
  PIN la_data_in[61]
    DIRECTION INPUT ;
    USE SIGNAL ;
    PORT
      LAYER met2 ;
        RECT 1660.760000 0.000000 1660.900000 0.485000 ;
    END
  END la_data_in[61]
  PIN la_data_in[60]
    DIRECTION INPUT ;
    USE SIGNAL ;
    PORT
      LAYER met2 ;
        RECT 1643.740000 0.000000 1643.880000 0.485000 ;
    END
  END la_data_in[60]
  PIN la_data_in[59]
    DIRECTION INPUT ;
    USE SIGNAL ;
    PORT
      LAYER met2 ;
        RECT 1626.260000 0.000000 1626.400000 0.485000 ;
    END
  END la_data_in[59]
  PIN la_data_in[58]
    DIRECTION INPUT ;
    USE SIGNAL ;
    PORT
      LAYER met2 ;
        RECT 1609.240000 0.000000 1609.380000 0.485000 ;
    END
  END la_data_in[58]
  PIN la_data_in[57]
    DIRECTION INPUT ;
    USE SIGNAL ;
    PORT
      LAYER met2 ;
        RECT 1591.760000 0.000000 1591.900000 0.485000 ;
    END
  END la_data_in[57]
  PIN la_data_in[56]
    DIRECTION INPUT ;
    USE SIGNAL ;
    PORT
      LAYER met2 ;
        RECT 1574.740000 0.000000 1574.880000 0.485000 ;
    END
  END la_data_in[56]
  PIN la_data_in[55]
    DIRECTION INPUT ;
    USE SIGNAL ;
    PORT
      LAYER met2 ;
        RECT 1557.260000 0.000000 1557.400000 0.485000 ;
    END
  END la_data_in[55]
  PIN la_data_in[54]
    DIRECTION INPUT ;
    USE SIGNAL ;
    PORT
      LAYER met2 ;
        RECT 1540.240000 0.000000 1540.380000 0.485000 ;
    END
  END la_data_in[54]
  PIN la_data_in[53]
    DIRECTION INPUT ;
    USE SIGNAL ;
    PORT
      LAYER met2 ;
        RECT 1522.760000 0.000000 1522.900000 0.485000 ;
    END
  END la_data_in[53]
  PIN la_data_in[52]
    DIRECTION INPUT ;
    USE SIGNAL ;
    PORT
      LAYER met2 ;
        RECT 1505.740000 0.000000 1505.880000 0.485000 ;
    END
  END la_data_in[52]
  PIN la_data_in[51]
    DIRECTION INPUT ;
    USE SIGNAL ;
    PORT
      LAYER met2 ;
        RECT 1488.260000 0.000000 1488.400000 0.485000 ;
    END
  END la_data_in[51]
  PIN la_data_in[50]
    DIRECTION INPUT ;
    USE SIGNAL ;
    PORT
      LAYER met2 ;
        RECT 1471.240000 0.000000 1471.380000 0.485000 ;
    END
  END la_data_in[50]
  PIN la_data_in[49]
    DIRECTION INPUT ;
    USE SIGNAL ;
    PORT
      LAYER met2 ;
        RECT 1453.760000 0.000000 1453.900000 0.485000 ;
    END
  END la_data_in[49]
  PIN la_data_in[48]
    DIRECTION INPUT ;
    USE SIGNAL ;
    PORT
      LAYER met2 ;
        RECT 1436.740000 0.000000 1436.880000 0.485000 ;
    END
  END la_data_in[48]
  PIN la_data_in[47]
    DIRECTION INPUT ;
    USE SIGNAL ;
    PORT
      LAYER met2 ;
        RECT 1419.260000 0.000000 1419.400000 0.485000 ;
    END
  END la_data_in[47]
  PIN la_data_in[46]
    DIRECTION INPUT ;
    USE SIGNAL ;
    PORT
      LAYER met2 ;
        RECT 1402.240000 0.000000 1402.380000 0.485000 ;
    END
  END la_data_in[46]
  PIN la_data_in[45]
    DIRECTION INPUT ;
    USE SIGNAL ;
    PORT
      LAYER met2 ;
        RECT 1385.220000 0.000000 1385.360000 0.485000 ;
    END
  END la_data_in[45]
  PIN la_data_in[44]
    DIRECTION INPUT ;
    USE SIGNAL ;
    PORT
      LAYER met2 ;
        RECT 1367.740000 0.000000 1367.880000 0.485000 ;
    END
  END la_data_in[44]
  PIN la_data_in[43]
    DIRECTION INPUT ;
    USE SIGNAL ;
    PORT
      LAYER met2 ;
        RECT 1350.720000 0.000000 1350.860000 0.485000 ;
    END
  END la_data_in[43]
  PIN la_data_in[42]
    DIRECTION INPUT ;
    USE SIGNAL ;
    PORT
      LAYER met2 ;
        RECT 1333.240000 0.000000 1333.380000 0.485000 ;
    END
  END la_data_in[42]
  PIN la_data_in[41]
    DIRECTION INPUT ;
    USE SIGNAL ;
    PORT
      LAYER met2 ;
        RECT 1316.220000 0.000000 1316.360000 0.485000 ;
    END
  END la_data_in[41]
  PIN la_data_in[40]
    DIRECTION INPUT ;
    USE SIGNAL ;
    PORT
      LAYER met2 ;
        RECT 1298.740000 0.000000 1298.880000 0.485000 ;
    END
  END la_data_in[40]
  PIN la_data_in[39]
    DIRECTION INPUT ;
    USE SIGNAL ;
    PORT
      LAYER met2 ;
        RECT 1281.720000 0.000000 1281.860000 0.485000 ;
    END
  END la_data_in[39]
  PIN la_data_in[38]
    DIRECTION INPUT ;
    USE SIGNAL ;
    PORT
      LAYER met2 ;
        RECT 1264.240000 0.000000 1264.380000 0.485000 ;
    END
  END la_data_in[38]
  PIN la_data_in[37]
    DIRECTION INPUT ;
    USE SIGNAL ;
    PORT
      LAYER met2 ;
        RECT 1247.220000 0.000000 1247.360000 0.485000 ;
    END
  END la_data_in[37]
  PIN la_data_in[36]
    DIRECTION INPUT ;
    USE SIGNAL ;
    PORT
      LAYER met2 ;
        RECT 1229.740000 0.000000 1229.880000 0.485000 ;
    END
  END la_data_in[36]
  PIN la_data_in[35]
    DIRECTION INPUT ;
    USE SIGNAL ;
    PORT
      LAYER met2 ;
        RECT 1212.720000 0.000000 1212.860000 0.485000 ;
    END
  END la_data_in[35]
  PIN la_data_in[34]
    DIRECTION INPUT ;
    USE SIGNAL ;
    PORT
      LAYER met2 ;
        RECT 1195.240000 0.000000 1195.380000 0.485000 ;
    END
  END la_data_in[34]
  PIN la_data_in[33]
    DIRECTION INPUT ;
    USE SIGNAL ;
    PORT
      LAYER met2 ;
        RECT 1178.220000 0.000000 1178.360000 0.485000 ;
    END
  END la_data_in[33]
  PIN la_data_in[32]
    DIRECTION INPUT ;
    USE SIGNAL ;
    PORT
      LAYER met2 ;
        RECT 1160.740000 0.000000 1160.880000 0.485000 ;
    END
  END la_data_in[32]
  PIN la_data_in[31]
    DIRECTION INPUT ;
    USE SIGNAL ;
    PORT
      LAYER met2 ;
        RECT 1143.720000 0.000000 1143.860000 0.485000 ;
    END
  END la_data_in[31]
  PIN la_data_in[30]
    DIRECTION INPUT ;
    USE SIGNAL ;
    PORT
      LAYER met2 ;
        RECT 1126.700000 0.000000 1126.840000 0.485000 ;
    END
  END la_data_in[30]
  PIN la_data_in[29]
    DIRECTION INPUT ;
    USE SIGNAL ;
    PORT
      LAYER met2 ;
        RECT 1109.220000 0.000000 1109.360000 0.485000 ;
    END
  END la_data_in[29]
  PIN la_data_in[28]
    DIRECTION INPUT ;
    USE SIGNAL ;
    PORT
      LAYER met2 ;
        RECT 1092.200000 0.000000 1092.340000 0.485000 ;
    END
  END la_data_in[28]
  PIN la_data_in[27]
    DIRECTION INPUT ;
    USE SIGNAL ;
    PORT
      LAYER met2 ;
        RECT 1074.720000 0.000000 1074.860000 0.485000 ;
    END
  END la_data_in[27]
  PIN la_data_in[26]
    DIRECTION INPUT ;
    USE SIGNAL ;
    PORT
      LAYER met2 ;
        RECT 1057.700000 0.000000 1057.840000 0.485000 ;
    END
  END la_data_in[26]
  PIN la_data_in[25]
    DIRECTION INPUT ;
    USE SIGNAL ;
    PORT
      LAYER met2 ;
        RECT 1040.220000 0.000000 1040.360000 0.485000 ;
    END
  END la_data_in[25]
  PIN la_data_in[24]
    DIRECTION INPUT ;
    USE SIGNAL ;
    PORT
      LAYER met2 ;
        RECT 1023.200000 0.000000 1023.340000 0.485000 ;
    END
  END la_data_in[24]
  PIN la_data_in[23]
    DIRECTION INPUT ;
    USE SIGNAL ;
    PORT
      LAYER met2 ;
        RECT 1005.720000 0.000000 1005.860000 0.485000 ;
    END
  END la_data_in[23]
  PIN la_data_in[22]
    DIRECTION INPUT ;
    USE SIGNAL ;
    PORT
      LAYER met2 ;
        RECT 988.700000 0.000000 988.840000 0.485000 ;
    END
  END la_data_in[22]
  PIN la_data_in[21]
    DIRECTION INPUT ;
    USE SIGNAL ;
    PORT
      LAYER met2 ;
        RECT 971.220000 0.000000 971.360000 0.485000 ;
    END
  END la_data_in[21]
  PIN la_data_in[20]
    DIRECTION INPUT ;
    USE SIGNAL ;
    PORT
      LAYER met2 ;
        RECT 954.200000 0.000000 954.340000 0.485000 ;
    END
  END la_data_in[20]
  PIN la_data_in[19]
    DIRECTION INPUT ;
    USE SIGNAL ;
    PORT
      LAYER met2 ;
        RECT 936.720000 0.000000 936.860000 0.485000 ;
    END
  END la_data_in[19]
  PIN la_data_in[18]
    DIRECTION INPUT ;
    USE SIGNAL ;
    PORT
      LAYER met2 ;
        RECT 919.700000 0.000000 919.840000 0.485000 ;
    END
  END la_data_in[18]
  PIN la_data_in[17]
    DIRECTION INPUT ;
    USE SIGNAL ;
    PORT
      LAYER met2 ;
        RECT 902.220000 0.000000 902.360000 0.485000 ;
    END
  END la_data_in[17]
  PIN la_data_in[16]
    DIRECTION INPUT ;
    USE SIGNAL ;
    PORT
      LAYER met2 ;
        RECT 885.200000 0.000000 885.340000 0.485000 ;
    END
  END la_data_in[16]
  PIN la_data_in[15]
    DIRECTION INPUT ;
    USE SIGNAL ;
    PORT
      LAYER met2 ;
        RECT 867.720000 0.000000 867.860000 0.485000 ;
    END
  END la_data_in[15]
  PIN la_data_in[14]
    DIRECTION INPUT ;
    USE SIGNAL ;
    PORT
      LAYER met2 ;
        RECT 850.700000 0.000000 850.840000 0.485000 ;
    END
  END la_data_in[14]
  PIN la_data_in[13]
    DIRECTION INPUT ;
    USE SIGNAL ;
    PORT
      LAYER met2 ;
        RECT 833.680000 0.000000 833.820000 0.485000 ;
    END
  END la_data_in[13]
  PIN la_data_in[12]
    DIRECTION INPUT ;
    USE SIGNAL ;
    PORT
      LAYER met2 ;
        RECT 816.200000 0.000000 816.340000 0.485000 ;
    END
  END la_data_in[12]
  PIN la_data_in[11]
    DIRECTION INPUT ;
    USE SIGNAL ;
    PORT
      LAYER met2 ;
        RECT 799.180000 0.000000 799.320000 0.485000 ;
    END
  END la_data_in[11]
  PIN la_data_in[10]
    DIRECTION INPUT ;
    USE SIGNAL ;
    PORT
      LAYER met2 ;
        RECT 781.700000 0.000000 781.840000 0.485000 ;
    END
  END la_data_in[10]
  PIN la_data_in[9]
    DIRECTION INPUT ;
    USE SIGNAL ;
    PORT
      LAYER met2 ;
        RECT 764.680000 0.000000 764.820000 0.485000 ;
    END
  END la_data_in[9]
  PIN la_data_in[8]
    DIRECTION INPUT ;
    USE SIGNAL ;
    PORT
      LAYER met2 ;
        RECT 747.200000 0.000000 747.340000 0.485000 ;
    END
  END la_data_in[8]
  PIN la_data_in[7]
    DIRECTION INPUT ;
    USE SIGNAL ;
    PORT
      LAYER met2 ;
        RECT 730.180000 0.000000 730.320000 0.485000 ;
    END
  END la_data_in[7]
  PIN la_data_in[6]
    DIRECTION INPUT ;
    USE SIGNAL ;
    PORT
      LAYER met2 ;
        RECT 712.700000 0.000000 712.840000 0.485000 ;
    END
  END la_data_in[6]
  PIN la_data_in[5]
    DIRECTION INPUT ;
    USE SIGNAL ;
    PORT
      LAYER met2 ;
        RECT 695.680000 0.000000 695.820000 0.485000 ;
    END
  END la_data_in[5]
  PIN la_data_in[4]
    DIRECTION INPUT ;
    USE SIGNAL ;
    PORT
      LAYER met2 ;
        RECT 678.200000 0.000000 678.340000 0.485000 ;
    END
  END la_data_in[4]
  PIN la_data_in[3]
    DIRECTION INPUT ;
    USE SIGNAL ;
    PORT
      LAYER met2 ;
        RECT 661.180000 0.000000 661.320000 0.485000 ;
    END
  END la_data_in[3]
  PIN la_data_in[2]
    DIRECTION INPUT ;
    USE SIGNAL ;
    PORT
      LAYER met2 ;
        RECT 643.700000 0.000000 643.840000 0.485000 ;
    END
  END la_data_in[2]
  PIN la_data_in[1]
    DIRECTION INPUT ;
    USE SIGNAL ;
    PORT
      LAYER met2 ;
        RECT 626.680000 0.000000 626.820000 0.485000 ;
    END
  END la_data_in[1]
  PIN la_data_in[0]
    DIRECTION INPUT ;
    USE SIGNAL ;
    PORT
      LAYER met2 ;
        RECT 609.200000 0.000000 609.340000 0.485000 ;
    END
  END la_data_in[0]
  PIN la_data_out[127]
    DIRECTION OUTPUT ;
    USE SIGNAL ;
    PORT
      LAYER met2 ;
        RECT 2804.320000 0.000000 2804.460000 0.485000 ;
    END
  END la_data_out[127]
  PIN la_data_out[126]
    DIRECTION OUTPUT ;
    USE SIGNAL ;
    PORT
      LAYER met2 ;
        RECT 2786.840000 0.000000 2786.980000 0.485000 ;
    END
  END la_data_out[126]
  PIN la_data_out[125]
    DIRECTION OUTPUT ;
    USE SIGNAL ;
    PORT
      LAYER met2 ;
        RECT 2769.820000 0.000000 2769.960000 0.485000 ;
    END
  END la_data_out[125]
  PIN la_data_out[124]
    DIRECTION OUTPUT ;
    USE SIGNAL ;
    PORT
      LAYER met2 ;
        RECT 2752.340000 0.000000 2752.480000 0.485000 ;
    END
  END la_data_out[124]
  PIN la_data_out[123]
    DIRECTION OUTPUT ;
    USE SIGNAL ;
    PORT
      LAYER met2 ;
        RECT 2735.320000 0.000000 2735.460000 0.485000 ;
    END
  END la_data_out[123]
  PIN la_data_out[122]
    DIRECTION OUTPUT ;
    USE SIGNAL ;
    PORT
      LAYER met2 ;
        RECT 2717.840000 0.000000 2717.980000 0.485000 ;
    END
  END la_data_out[122]
  PIN la_data_out[121]
    DIRECTION OUTPUT ;
    USE SIGNAL ;
    PORT
      LAYER met2 ;
        RECT 2700.820000 0.000000 2700.960000 0.485000 ;
    END
  END la_data_out[121]
  PIN la_data_out[120]
    DIRECTION OUTPUT ;
    USE SIGNAL ;
    PORT
      LAYER met2 ;
        RECT 2683.340000 0.000000 2683.480000 0.485000 ;
    END
  END la_data_out[120]
  PIN la_data_out[119]
    DIRECTION OUTPUT ;
    USE SIGNAL ;
    PORT
      LAYER met2 ;
        RECT 2666.320000 0.000000 2666.460000 0.485000 ;
    END
  END la_data_out[119]
  PIN la_data_out[118]
    DIRECTION OUTPUT ;
    USE SIGNAL ;
    PORT
      LAYER met2 ;
        RECT 2648.840000 0.000000 2648.980000 0.485000 ;
    END
  END la_data_out[118]
  PIN la_data_out[117]
    DIRECTION OUTPUT ;
    USE SIGNAL ;
    PORT
      LAYER met2 ;
        RECT 2631.820000 0.000000 2631.960000 0.485000 ;
    END
  END la_data_out[117]
  PIN la_data_out[116]
    DIRECTION OUTPUT ;
    USE SIGNAL ;
    PORT
      LAYER met2 ;
        RECT 2614.340000 0.000000 2614.480000 0.485000 ;
    END
  END la_data_out[116]
  PIN la_data_out[115]
    DIRECTION OUTPUT ;
    USE SIGNAL ;
    PORT
      LAYER met2 ;
        RECT 2597.320000 0.000000 2597.460000 0.485000 ;
    END
  END la_data_out[115]
  PIN la_data_out[114]
    DIRECTION OUTPUT ;
    USE SIGNAL ;
    PORT
      LAYER met2 ;
        RECT 2579.840000 0.000000 2579.980000 0.485000 ;
    END
  END la_data_out[114]
  PIN la_data_out[113]
    DIRECTION OUTPUT ;
    USE SIGNAL ;
    PORT
      LAYER met2 ;
        RECT 2562.820000 0.000000 2562.960000 0.485000 ;
    END
  END la_data_out[113]
  PIN la_data_out[112]
    DIRECTION OUTPUT ;
    USE SIGNAL ;
    PORT
      LAYER met2 ;
        RECT 2545.340000 0.000000 2545.480000 0.485000 ;
    END
  END la_data_out[112]
  PIN la_data_out[111]
    DIRECTION OUTPUT ;
    USE SIGNAL ;
    PORT
      LAYER met2 ;
        RECT 2528.320000 0.000000 2528.460000 0.485000 ;
    END
  END la_data_out[111]
  PIN la_data_out[110]
    DIRECTION OUTPUT ;
    USE SIGNAL ;
    PORT
      LAYER met2 ;
        RECT 2511.300000 0.000000 2511.440000 0.485000 ;
    END
  END la_data_out[110]
  PIN la_data_out[109]
    DIRECTION OUTPUT ;
    USE SIGNAL ;
    PORT
      LAYER met2 ;
        RECT 2493.820000 0.000000 2493.960000 0.485000 ;
    END
  END la_data_out[109]
  PIN la_data_out[108]
    DIRECTION OUTPUT ;
    USE SIGNAL ;
    PORT
      LAYER met2 ;
        RECT 2476.800000 0.000000 2476.940000 0.485000 ;
    END
  END la_data_out[108]
  PIN la_data_out[107]
    DIRECTION OUTPUT ;
    USE SIGNAL ;
    PORT
      LAYER met2 ;
        RECT 2459.320000 0.000000 2459.460000 0.485000 ;
    END
  END la_data_out[107]
  PIN la_data_out[106]
    DIRECTION OUTPUT ;
    USE SIGNAL ;
    PORT
      LAYER met2 ;
        RECT 2442.300000 0.000000 2442.440000 0.485000 ;
    END
  END la_data_out[106]
  PIN la_data_out[105]
    DIRECTION OUTPUT ;
    USE SIGNAL ;
    PORT
      LAYER met2 ;
        RECT 2424.820000 0.000000 2424.960000 0.485000 ;
    END
  END la_data_out[105]
  PIN la_data_out[104]
    DIRECTION OUTPUT ;
    USE SIGNAL ;
    PORT
      LAYER met2 ;
        RECT 2407.800000 0.000000 2407.940000 0.485000 ;
    END
  END la_data_out[104]
  PIN la_data_out[103]
    DIRECTION OUTPUT ;
    USE SIGNAL ;
    PORT
      LAYER met2 ;
        RECT 2390.320000 0.000000 2390.460000 0.485000 ;
    END
  END la_data_out[103]
  PIN la_data_out[102]
    DIRECTION OUTPUT ;
    USE SIGNAL ;
    PORT
      LAYER met2 ;
        RECT 2373.300000 0.000000 2373.440000 0.485000 ;
    END
  END la_data_out[102]
  PIN la_data_out[101]
    DIRECTION OUTPUT ;
    USE SIGNAL ;
    PORT
      LAYER met2 ;
        RECT 2355.820000 0.000000 2355.960000 0.485000 ;
    END
  END la_data_out[101]
  PIN la_data_out[100]
    DIRECTION OUTPUT ;
    USE SIGNAL ;
    PORT
      LAYER met2 ;
        RECT 2338.800000 0.000000 2338.940000 0.485000 ;
    END
  END la_data_out[100]
  PIN la_data_out[99]
    DIRECTION OUTPUT ;
    USE SIGNAL ;
    PORT
      LAYER met2 ;
        RECT 2321.320000 0.000000 2321.460000 0.485000 ;
    END
  END la_data_out[99]
  PIN la_data_out[98]
    DIRECTION OUTPUT ;
    USE SIGNAL ;
    PORT
      LAYER met2 ;
        RECT 2304.300000 0.000000 2304.440000 0.485000 ;
    END
  END la_data_out[98]
  PIN la_data_out[97]
    DIRECTION OUTPUT ;
    USE SIGNAL ;
    PORT
      LAYER met2 ;
        RECT 2286.820000 0.000000 2286.960000 0.485000 ;
    END
  END la_data_out[97]
  PIN la_data_out[96]
    DIRECTION OUTPUT ;
    USE SIGNAL ;
    PORT
      LAYER met2 ;
        RECT 2269.800000 0.000000 2269.940000 0.485000 ;
    END
  END la_data_out[96]
  PIN la_data_out[95]
    DIRECTION OUTPUT ;
    USE SIGNAL ;
    PORT
      LAYER met2 ;
        RECT 2252.780000 0.000000 2252.920000 0.485000 ;
    END
  END la_data_out[95]
  PIN la_data_out[94]
    DIRECTION OUTPUT ;
    USE SIGNAL ;
    PORT
      LAYER met2 ;
        RECT 2235.300000 0.000000 2235.440000 0.485000 ;
    END
  END la_data_out[94]
  PIN la_data_out[93]
    DIRECTION OUTPUT ;
    USE SIGNAL ;
    PORT
      LAYER met2 ;
        RECT 2218.280000 0.000000 2218.420000 0.485000 ;
    END
  END la_data_out[93]
  PIN la_data_out[92]
    DIRECTION OUTPUT ;
    USE SIGNAL ;
    PORT
      LAYER met2 ;
        RECT 2200.800000 0.000000 2200.940000 0.485000 ;
    END
  END la_data_out[92]
  PIN la_data_out[91]
    DIRECTION OUTPUT ;
    USE SIGNAL ;
    PORT
      LAYER met2 ;
        RECT 2183.780000 0.000000 2183.920000 0.485000 ;
    END
  END la_data_out[91]
  PIN la_data_out[90]
    DIRECTION OUTPUT ;
    USE SIGNAL ;
    PORT
      LAYER met2 ;
        RECT 2166.300000 0.000000 2166.440000 0.485000 ;
    END
  END la_data_out[90]
  PIN la_data_out[89]
    DIRECTION OUTPUT ;
    USE SIGNAL ;
    PORT
      LAYER met2 ;
        RECT 2149.280000 0.000000 2149.420000 0.485000 ;
    END
  END la_data_out[89]
  PIN la_data_out[88]
    DIRECTION OUTPUT ;
    USE SIGNAL ;
    PORT
      LAYER met2 ;
        RECT 2131.800000 0.000000 2131.940000 0.485000 ;
    END
  END la_data_out[88]
  PIN la_data_out[87]
    DIRECTION OUTPUT ;
    USE SIGNAL ;
    PORT
      LAYER met2 ;
        RECT 2114.780000 0.000000 2114.920000 0.485000 ;
    END
  END la_data_out[87]
  PIN la_data_out[86]
    DIRECTION OUTPUT ;
    USE SIGNAL ;
    PORT
      LAYER met2 ;
        RECT 2097.300000 0.000000 2097.440000 0.485000 ;
    END
  END la_data_out[86]
  PIN la_data_out[85]
    DIRECTION OUTPUT ;
    USE SIGNAL ;
    PORT
      LAYER met2 ;
        RECT 2080.280000 0.000000 2080.420000 0.485000 ;
    END
  END la_data_out[85]
  PIN la_data_out[84]
    DIRECTION OUTPUT ;
    USE SIGNAL ;
    PORT
      LAYER met2 ;
        RECT 2062.800000 0.000000 2062.940000 0.485000 ;
    END
  END la_data_out[84]
  PIN la_data_out[83]
    DIRECTION OUTPUT ;
    USE SIGNAL ;
    PORT
      LAYER met2 ;
        RECT 2045.780000 0.000000 2045.920000 0.485000 ;
    END
  END la_data_out[83]
  PIN la_data_out[82]
    DIRECTION OUTPUT ;
    USE SIGNAL ;
    PORT
      LAYER met2 ;
        RECT 2028.300000 0.000000 2028.440000 0.485000 ;
    END
  END la_data_out[82]
  PIN la_data_out[81]
    DIRECTION OUTPUT ;
    USE SIGNAL ;
    PORT
      LAYER met2 ;
        RECT 2011.280000 0.000000 2011.420000 0.485000 ;
    END
  END la_data_out[81]
  PIN la_data_out[80]
    DIRECTION OUTPUT ;
    USE SIGNAL ;
    PORT
      LAYER met2 ;
        RECT 1993.800000 0.000000 1993.940000 0.485000 ;
    END
  END la_data_out[80]
  PIN la_data_out[79]
    DIRECTION OUTPUT ;
    USE SIGNAL ;
    PORT
      LAYER met2 ;
        RECT 1976.780000 0.000000 1976.920000 0.485000 ;
    END
  END la_data_out[79]
  PIN la_data_out[78]
    DIRECTION OUTPUT ;
    USE SIGNAL ;
    PORT
      LAYER met2 ;
        RECT 1959.760000 0.000000 1959.900000 0.485000 ;
    END
  END la_data_out[78]
  PIN la_data_out[77]
    DIRECTION OUTPUT ;
    USE SIGNAL ;
    PORT
      LAYER met2 ;
        RECT 1942.280000 0.000000 1942.420000 0.485000 ;
    END
  END la_data_out[77]
  PIN la_data_out[76]
    DIRECTION OUTPUT ;
    USE SIGNAL ;
    PORT
      LAYER met2 ;
        RECT 1925.260000 0.000000 1925.400000 0.485000 ;
    END
  END la_data_out[76]
  PIN la_data_out[75]
    DIRECTION OUTPUT ;
    USE SIGNAL ;
    PORT
      LAYER met2 ;
        RECT 1907.780000 0.000000 1907.920000 0.485000 ;
    END
  END la_data_out[75]
  PIN la_data_out[74]
    DIRECTION OUTPUT ;
    USE SIGNAL ;
    PORT
      LAYER met2 ;
        RECT 1890.760000 0.000000 1890.900000 0.485000 ;
    END
  END la_data_out[74]
  PIN la_data_out[73]
    DIRECTION OUTPUT ;
    USE SIGNAL ;
    PORT
      LAYER met2 ;
        RECT 1873.280000 0.000000 1873.420000 0.485000 ;
    END
  END la_data_out[73]
  PIN la_data_out[72]
    DIRECTION OUTPUT ;
    USE SIGNAL ;
    PORT
      LAYER met2 ;
        RECT 1856.260000 0.000000 1856.400000 0.485000 ;
    END
  END la_data_out[72]
  PIN la_data_out[71]
    DIRECTION OUTPUT ;
    USE SIGNAL ;
    PORT
      LAYER met2 ;
        RECT 1838.780000 0.000000 1838.920000 0.485000 ;
    END
  END la_data_out[71]
  PIN la_data_out[70]
    DIRECTION OUTPUT ;
    USE SIGNAL ;
    PORT
      LAYER met2 ;
        RECT 1821.760000 0.000000 1821.900000 0.485000 ;
    END
  END la_data_out[70]
  PIN la_data_out[69]
    DIRECTION OUTPUT ;
    USE SIGNAL ;
    PORT
      LAYER met2 ;
        RECT 1804.280000 0.000000 1804.420000 0.485000 ;
    END
  END la_data_out[69]
  PIN la_data_out[68]
    DIRECTION OUTPUT ;
    USE SIGNAL ;
    PORT
      LAYER met2 ;
        RECT 1787.260000 0.000000 1787.400000 0.485000 ;
    END
  END la_data_out[68]
  PIN la_data_out[67]
    DIRECTION OUTPUT ;
    USE SIGNAL ;
    PORT
      LAYER met2 ;
        RECT 1769.780000 0.000000 1769.920000 0.485000 ;
    END
  END la_data_out[67]
  PIN la_data_out[66]
    DIRECTION OUTPUT ;
    USE SIGNAL ;
    PORT
      LAYER met2 ;
        RECT 1752.760000 0.000000 1752.900000 0.485000 ;
    END
  END la_data_out[66]
  PIN la_data_out[65]
    DIRECTION OUTPUT ;
    USE SIGNAL ;
    PORT
      LAYER met2 ;
        RECT 1735.280000 0.000000 1735.420000 0.485000 ;
    END
  END la_data_out[65]
  PIN la_data_out[64]
    DIRECTION OUTPUT ;
    USE SIGNAL ;
    PORT
      LAYER met2 ;
        RECT 1718.260000 0.000000 1718.400000 0.485000 ;
    END
  END la_data_out[64]
  PIN la_data_out[63]
    DIRECTION OUTPUT ;
    USE SIGNAL ;
    PORT
      LAYER met2 ;
        RECT 1700.780000 0.000000 1700.920000 0.485000 ;
    END
  END la_data_out[63]
  PIN la_data_out[62]
    DIRECTION OUTPUT ;
    USE SIGNAL ;
    PORT
      LAYER met2 ;
        RECT 1683.760000 0.000000 1683.900000 0.485000 ;
    END
  END la_data_out[62]
  PIN la_data_out[61]
    DIRECTION OUTPUT ;
    USE SIGNAL ;
    PORT
      LAYER met2 ;
        RECT 1666.740000 0.000000 1666.880000 0.485000 ;
    END
  END la_data_out[61]
  PIN la_data_out[60]
    DIRECTION OUTPUT ;
    USE SIGNAL ;
    PORT
      LAYER met2 ;
        RECT 1649.260000 0.000000 1649.400000 0.485000 ;
    END
  END la_data_out[60]
  PIN la_data_out[59]
    DIRECTION OUTPUT ;
    USE SIGNAL ;
    PORT
      LAYER met2 ;
        RECT 1632.240000 0.000000 1632.380000 0.485000 ;
    END
  END la_data_out[59]
  PIN la_data_out[58]
    DIRECTION OUTPUT ;
    USE SIGNAL ;
    PORT
      LAYER met2 ;
        RECT 1614.760000 0.000000 1614.900000 0.485000 ;
    END
  END la_data_out[58]
  PIN la_data_out[57]
    DIRECTION OUTPUT ;
    USE SIGNAL ;
    PORT
      LAYER met2 ;
        RECT 1597.740000 0.000000 1597.880000 0.485000 ;
    END
  END la_data_out[57]
  PIN la_data_out[56]
    DIRECTION OUTPUT ;
    USE SIGNAL ;
    PORT
      LAYER met2 ;
        RECT 1580.260000 0.000000 1580.400000 0.485000 ;
    END
  END la_data_out[56]
  PIN la_data_out[55]
    DIRECTION OUTPUT ;
    USE SIGNAL ;
    PORT
      LAYER met2 ;
        RECT 1563.240000 0.000000 1563.380000 0.485000 ;
    END
  END la_data_out[55]
  PIN la_data_out[54]
    DIRECTION OUTPUT ;
    USE SIGNAL ;
    PORT
      LAYER met2 ;
        RECT 1545.760000 0.000000 1545.900000 0.485000 ;
    END
  END la_data_out[54]
  PIN la_data_out[53]
    DIRECTION OUTPUT ;
    USE SIGNAL ;
    PORT
      LAYER met2 ;
        RECT 1528.740000 0.000000 1528.880000 0.485000 ;
    END
  END la_data_out[53]
  PIN la_data_out[52]
    DIRECTION OUTPUT ;
    USE SIGNAL ;
    PORT
      LAYER met2 ;
        RECT 1511.260000 0.000000 1511.400000 0.485000 ;
    END
  END la_data_out[52]
  PIN la_data_out[51]
    DIRECTION OUTPUT ;
    USE SIGNAL ;
    PORT
      LAYER met2 ;
        RECT 1494.240000 0.000000 1494.380000 0.485000 ;
    END
  END la_data_out[51]
  PIN la_data_out[50]
    DIRECTION OUTPUT ;
    USE SIGNAL ;
    PORT
      LAYER met2 ;
        RECT 1476.760000 0.000000 1476.900000 0.485000 ;
    END
  END la_data_out[50]
  PIN la_data_out[49]
    DIRECTION OUTPUT ;
    USE SIGNAL ;
    PORT
      LAYER met2 ;
        RECT 1459.740000 0.000000 1459.880000 0.485000 ;
    END
  END la_data_out[49]
  PIN la_data_out[48]
    DIRECTION OUTPUT ;
    USE SIGNAL ;
    PORT
      LAYER met2 ;
        RECT 1442.260000 0.000000 1442.400000 0.485000 ;
    END
  END la_data_out[48]
  PIN la_data_out[47]
    DIRECTION OUTPUT ;
    USE SIGNAL ;
    PORT
      LAYER met2 ;
        RECT 1425.240000 0.000000 1425.380000 0.485000 ;
    END
  END la_data_out[47]
  PIN la_data_out[46]
    DIRECTION OUTPUT ;
    USE SIGNAL ;
    PORT
      LAYER met2 ;
        RECT 1408.220000 0.000000 1408.360000 0.485000 ;
    END
  END la_data_out[46]
  PIN la_data_out[45]
    DIRECTION OUTPUT ;
    USE SIGNAL ;
    PORT
      LAYER met2 ;
        RECT 1390.740000 0.000000 1390.880000 0.485000 ;
    END
  END la_data_out[45]
  PIN la_data_out[44]
    DIRECTION OUTPUT ;
    USE SIGNAL ;
    PORT
      LAYER met2 ;
        RECT 1373.720000 0.000000 1373.860000 0.485000 ;
    END
  END la_data_out[44]
  PIN la_data_out[43]
    DIRECTION OUTPUT ;
    USE SIGNAL ;
    PORT
      LAYER met2 ;
        RECT 1356.240000 0.000000 1356.380000 0.485000 ;
    END
  END la_data_out[43]
  PIN la_data_out[42]
    DIRECTION OUTPUT ;
    USE SIGNAL ;
    PORT
      LAYER met2 ;
        RECT 1339.220000 0.000000 1339.360000 0.485000 ;
    END
  END la_data_out[42]
  PIN la_data_out[41]
    DIRECTION OUTPUT ;
    USE SIGNAL ;
    PORT
      LAYER met2 ;
        RECT 1321.740000 0.000000 1321.880000 0.485000 ;
    END
  END la_data_out[41]
  PIN la_data_out[40]
    DIRECTION OUTPUT ;
    USE SIGNAL ;
    PORT
      LAYER met2 ;
        RECT 1304.720000 0.000000 1304.860000 0.485000 ;
    END
  END la_data_out[40]
  PIN la_data_out[39]
    DIRECTION OUTPUT ;
    USE SIGNAL ;
    PORT
      LAYER met2 ;
        RECT 1287.240000 0.000000 1287.380000 0.485000 ;
    END
  END la_data_out[39]
  PIN la_data_out[38]
    DIRECTION OUTPUT ;
    USE SIGNAL ;
    PORT
      LAYER met2 ;
        RECT 1270.220000 0.000000 1270.360000 0.485000 ;
    END
  END la_data_out[38]
  PIN la_data_out[37]
    DIRECTION OUTPUT ;
    USE SIGNAL ;
    PORT
      LAYER met2 ;
        RECT 1252.740000 0.000000 1252.880000 0.485000 ;
    END
  END la_data_out[37]
  PIN la_data_out[36]
    DIRECTION OUTPUT ;
    USE SIGNAL ;
    PORT
      LAYER met2 ;
        RECT 1235.720000 0.000000 1235.860000 0.485000 ;
    END
  END la_data_out[36]
  PIN la_data_out[35]
    DIRECTION OUTPUT ;
    USE SIGNAL ;
    PORT
      LAYER met2 ;
        RECT 1218.240000 0.000000 1218.380000 0.485000 ;
    END
  END la_data_out[35]
  PIN la_data_out[34]
    DIRECTION OUTPUT ;
    USE SIGNAL ;
    PORT
      LAYER met2 ;
        RECT 1201.220000 0.000000 1201.360000 0.485000 ;
    END
  END la_data_out[34]
  PIN la_data_out[33]
    DIRECTION OUTPUT ;
    USE SIGNAL ;
    PORT
      LAYER met2 ;
        RECT 1183.740000 0.000000 1183.880000 0.485000 ;
    END
  END la_data_out[33]
  PIN la_data_out[32]
    DIRECTION OUTPUT ;
    USE SIGNAL ;
    PORT
      LAYER met2 ;
        RECT 1166.720000 0.000000 1166.860000 0.485000 ;
    END
  END la_data_out[32]
  PIN la_data_out[31]
    DIRECTION OUTPUT ;
    USE SIGNAL ;
    PORT
      LAYER met2 ;
        RECT 1149.240000 0.000000 1149.380000 0.485000 ;
    END
  END la_data_out[31]
  PIN la_data_out[30]
    DIRECTION OUTPUT ;
    USE SIGNAL ;
    PORT
      LAYER met2 ;
        RECT 1132.220000 0.000000 1132.360000 0.485000 ;
    END
  END la_data_out[30]
  PIN la_data_out[29]
    DIRECTION OUTPUT ;
    USE SIGNAL ;
    PORT
      LAYER met2 ;
        RECT 1115.200000 0.000000 1115.340000 0.485000 ;
    END
  END la_data_out[29]
  PIN la_data_out[28]
    DIRECTION OUTPUT ;
    USE SIGNAL ;
    PORT
      LAYER met2 ;
        RECT 1097.720000 0.000000 1097.860000 0.485000 ;
    END
  END la_data_out[28]
  PIN la_data_out[27]
    DIRECTION OUTPUT ;
    USE SIGNAL ;
    PORT
      LAYER met2 ;
        RECT 1080.700000 0.000000 1080.840000 0.485000 ;
    END
  END la_data_out[27]
  PIN la_data_out[26]
    DIRECTION OUTPUT ;
    USE SIGNAL ;
    PORT
      LAYER met2 ;
        RECT 1063.220000 0.000000 1063.360000 0.485000 ;
    END
  END la_data_out[26]
  PIN la_data_out[25]
    DIRECTION OUTPUT ;
    USE SIGNAL ;
    PORT
      LAYER met2 ;
        RECT 1046.200000 0.000000 1046.340000 0.485000 ;
    END
  END la_data_out[25]
  PIN la_data_out[24]
    DIRECTION OUTPUT ;
    USE SIGNAL ;
    PORT
      LAYER met2 ;
        RECT 1028.720000 0.000000 1028.860000 0.485000 ;
    END
  END la_data_out[24]
  PIN la_data_out[23]
    DIRECTION OUTPUT ;
    USE SIGNAL ;
    PORT
      LAYER met2 ;
        RECT 1011.700000 0.000000 1011.840000 0.485000 ;
    END
  END la_data_out[23]
  PIN la_data_out[22]
    DIRECTION OUTPUT ;
    USE SIGNAL ;
    PORT
      LAYER met2 ;
        RECT 994.220000 0.000000 994.360000 0.485000 ;
    END
  END la_data_out[22]
  PIN la_data_out[21]
    DIRECTION OUTPUT ;
    USE SIGNAL ;
    PORT
      LAYER met2 ;
        RECT 977.200000 0.000000 977.340000 0.485000 ;
    END
  END la_data_out[21]
  PIN la_data_out[20]
    DIRECTION OUTPUT ;
    USE SIGNAL ;
    PORT
      LAYER met2 ;
        RECT 959.720000 0.000000 959.860000 0.485000 ;
    END
  END la_data_out[20]
  PIN la_data_out[19]
    DIRECTION OUTPUT ;
    USE SIGNAL ;
    PORT
      LAYER met2 ;
        RECT 942.700000 0.000000 942.840000 0.485000 ;
    END
  END la_data_out[19]
  PIN la_data_out[18]
    DIRECTION OUTPUT ;
    USE SIGNAL ;
    PORT
      LAYER met2 ;
        RECT 925.220000 0.000000 925.360000 0.485000 ;
    END
  END la_data_out[18]
  PIN la_data_out[17]
    DIRECTION OUTPUT ;
    USE SIGNAL ;
    PORT
      LAYER met2 ;
        RECT 908.200000 0.000000 908.340000 0.485000 ;
    END
  END la_data_out[17]
  PIN la_data_out[16]
    DIRECTION OUTPUT ;
    USE SIGNAL ;
    PORT
      LAYER met2 ;
        RECT 890.720000 0.000000 890.860000 0.485000 ;
    END
  END la_data_out[16]
  PIN la_data_out[15]
    DIRECTION OUTPUT ;
    USE SIGNAL ;
    PORT
      LAYER met2 ;
        RECT 873.700000 0.000000 873.840000 0.485000 ;
    END
  END la_data_out[15]
  PIN la_data_out[14]
    DIRECTION OUTPUT ;
    USE SIGNAL ;
    PORT
      LAYER met2 ;
        RECT 856.220000 0.000000 856.360000 0.485000 ;
    END
  END la_data_out[14]
  PIN la_data_out[13]
    DIRECTION OUTPUT ;
    USE SIGNAL ;
    PORT
      LAYER met2 ;
        RECT 839.200000 0.000000 839.340000 0.485000 ;
    END
  END la_data_out[13]
  PIN la_data_out[12]
    DIRECTION OUTPUT ;
    USE SIGNAL ;
    PORT
      LAYER met2 ;
        RECT 822.180000 0.000000 822.320000 0.485000 ;
    END
  END la_data_out[12]
  PIN la_data_out[11]
    DIRECTION OUTPUT ;
    USE SIGNAL ;
    PORT
      LAYER met2 ;
        RECT 804.700000 0.000000 804.840000 0.485000 ;
    END
  END la_data_out[11]
  PIN la_data_out[10]
    DIRECTION OUTPUT ;
    USE SIGNAL ;
    PORT
      LAYER met2 ;
        RECT 787.680000 0.000000 787.820000 0.485000 ;
    END
  END la_data_out[10]
  PIN la_data_out[9]
    DIRECTION OUTPUT ;
    USE SIGNAL ;
    PORT
      LAYER met2 ;
        RECT 770.200000 0.000000 770.340000 0.485000 ;
    END
  END la_data_out[9]
  PIN la_data_out[8]
    DIRECTION OUTPUT ;
    USE SIGNAL ;
    PORT
      LAYER met2 ;
        RECT 753.180000 0.000000 753.320000 0.485000 ;
    END
  END la_data_out[8]
  PIN la_data_out[7]
    DIRECTION OUTPUT ;
    USE SIGNAL ;
    PORT
      LAYER met2 ;
        RECT 735.700000 0.000000 735.840000 0.485000 ;
    END
  END la_data_out[7]
  PIN la_data_out[6]
    DIRECTION OUTPUT ;
    USE SIGNAL ;
    PORT
      LAYER met2 ;
        RECT 718.680000 0.000000 718.820000 0.485000 ;
    END
  END la_data_out[6]
  PIN la_data_out[5]
    DIRECTION OUTPUT ;
    USE SIGNAL ;
    PORT
      LAYER met2 ;
        RECT 701.200000 0.000000 701.340000 0.485000 ;
    END
  END la_data_out[5]
  PIN la_data_out[4]
    DIRECTION OUTPUT ;
    USE SIGNAL ;
    PORT
      LAYER met2 ;
        RECT 684.180000 0.000000 684.320000 0.485000 ;
    END
  END la_data_out[4]
  PIN la_data_out[3]
    DIRECTION OUTPUT ;
    USE SIGNAL ;
    PORT
      LAYER met2 ;
        RECT 666.700000 0.000000 666.840000 0.485000 ;
    END
  END la_data_out[3]
  PIN la_data_out[2]
    DIRECTION OUTPUT ;
    USE SIGNAL ;
    PORT
      LAYER met2 ;
        RECT 649.680000 0.000000 649.820000 0.485000 ;
    END
  END la_data_out[2]
  PIN la_data_out[1]
    DIRECTION OUTPUT ;
    USE SIGNAL ;
    PORT
      LAYER met2 ;
        RECT 632.200000 0.000000 632.340000 0.485000 ;
    END
  END la_data_out[1]
  PIN la_data_out[0]
    DIRECTION OUTPUT ;
    USE SIGNAL ;
    PORT
      LAYER met2 ;
        RECT 615.180000 0.000000 615.320000 0.485000 ;
    END
  END la_data_out[0]
  PIN la_oenb[127]
    DIRECTION INPUT ;
    USE SIGNAL ;
    PORT
      LAYER met2 ;
        RECT 2809.840000 0.000000 2809.980000 0.485000 ;
    END
  END la_oenb[127]
  PIN la_oenb[126]
    DIRECTION INPUT ;
    USE SIGNAL ;
    PORT
      LAYER met2 ;
        RECT 2792.820000 0.000000 2792.960000 0.485000 ;
    END
  END la_oenb[126]
  PIN la_oenb[125]
    DIRECTION INPUT ;
    USE SIGNAL ;
    PORT
      LAYER met2 ;
        RECT 2775.340000 0.000000 2775.480000 0.485000 ;
    END
  END la_oenb[125]
  PIN la_oenb[124]
    DIRECTION INPUT ;
    USE SIGNAL ;
    PORT
      LAYER met2 ;
        RECT 2758.320000 0.000000 2758.460000 0.485000 ;
    END
  END la_oenb[124]
  PIN la_oenb[123]
    DIRECTION INPUT ;
    USE SIGNAL ;
    PORT
      LAYER met2 ;
        RECT 2740.840000 0.000000 2740.980000 0.485000 ;
    END
  END la_oenb[123]
  PIN la_oenb[122]
    DIRECTION INPUT ;
    USE SIGNAL ;
    PORT
      LAYER met2 ;
        RECT 2723.820000 0.000000 2723.960000 0.485000 ;
    END
  END la_oenb[122]
  PIN la_oenb[121]
    DIRECTION INPUT ;
    USE SIGNAL ;
    PORT
      LAYER met2 ;
        RECT 2706.340000 0.000000 2706.480000 0.485000 ;
    END
  END la_oenb[121]
  PIN la_oenb[120]
    DIRECTION INPUT ;
    USE SIGNAL ;
    PORT
      LAYER met2 ;
        RECT 2689.320000 0.000000 2689.460000 0.485000 ;
    END
  END la_oenb[120]
  PIN la_oenb[119]
    DIRECTION INPUT ;
    USE SIGNAL ;
    PORT
      LAYER met2 ;
        RECT 2671.840000 0.000000 2671.980000 0.485000 ;
    END
  END la_oenb[119]
  PIN la_oenb[118]
    DIRECTION INPUT ;
    USE SIGNAL ;
    PORT
      LAYER met2 ;
        RECT 2654.820000 0.000000 2654.960000 0.485000 ;
    END
  END la_oenb[118]
  PIN la_oenb[117]
    DIRECTION INPUT ;
    USE SIGNAL ;
    PORT
      LAYER met2 ;
        RECT 2637.340000 0.000000 2637.480000 0.485000 ;
    END
  END la_oenb[117]
  PIN la_oenb[116]
    DIRECTION INPUT ;
    USE SIGNAL ;
    PORT
      LAYER met2 ;
        RECT 2620.320000 0.000000 2620.460000 0.485000 ;
    END
  END la_oenb[116]
  PIN la_oenb[115]
    DIRECTION INPUT ;
    USE SIGNAL ;
    PORT
      LAYER met2 ;
        RECT 2602.840000 0.000000 2602.980000 0.485000 ;
    END
  END la_oenb[115]
  PIN la_oenb[114]
    DIRECTION INPUT ;
    USE SIGNAL ;
    PORT
      LAYER met2 ;
        RECT 2585.820000 0.000000 2585.960000 0.485000 ;
    END
  END la_oenb[114]
  PIN la_oenb[113]
    DIRECTION INPUT ;
    USE SIGNAL ;
    PORT
      LAYER met2 ;
        RECT 2568.340000 0.000000 2568.480000 0.485000 ;
    END
  END la_oenb[113]
  PIN la_oenb[112]
    DIRECTION INPUT ;
    USE SIGNAL ;
    PORT
      LAYER met2 ;
        RECT 2551.320000 0.000000 2551.460000 0.485000 ;
    END
  END la_oenb[112]
  PIN la_oenb[111]
    DIRECTION INPUT ;
    USE SIGNAL ;
    PORT
      LAYER met2 ;
        RECT 2534.300000 0.000000 2534.440000 0.485000 ;
    END
  END la_oenb[111]
  PIN la_oenb[110]
    DIRECTION INPUT ;
    USE SIGNAL ;
    PORT
      LAYER met2 ;
        RECT 2516.820000 0.000000 2516.960000 0.485000 ;
    END
  END la_oenb[110]
  PIN la_oenb[109]
    DIRECTION INPUT ;
    USE SIGNAL ;
    PORT
      LAYER met2 ;
        RECT 2499.800000 0.000000 2499.940000 0.485000 ;
    END
  END la_oenb[109]
  PIN la_oenb[108]
    DIRECTION INPUT ;
    USE SIGNAL ;
    PORT
      LAYER met2 ;
        RECT 2482.320000 0.000000 2482.460000 0.485000 ;
    END
  END la_oenb[108]
  PIN la_oenb[107]
    DIRECTION INPUT ;
    USE SIGNAL ;
    PORT
      LAYER met2 ;
        RECT 2465.300000 0.000000 2465.440000 0.485000 ;
    END
  END la_oenb[107]
  PIN la_oenb[106]
    DIRECTION INPUT ;
    USE SIGNAL ;
    PORT
      LAYER met2 ;
        RECT 2447.820000 0.000000 2447.960000 0.485000 ;
    END
  END la_oenb[106]
  PIN la_oenb[105]
    DIRECTION INPUT ;
    USE SIGNAL ;
    PORT
      LAYER met2 ;
        RECT 2430.800000 0.000000 2430.940000 0.485000 ;
    END
  END la_oenb[105]
  PIN la_oenb[104]
    DIRECTION INPUT ;
    USE SIGNAL ;
    PORT
      LAYER met2 ;
        RECT 2413.320000 0.000000 2413.460000 0.485000 ;
    END
  END la_oenb[104]
  PIN la_oenb[103]
    DIRECTION INPUT ;
    USE SIGNAL ;
    PORT
      LAYER met2 ;
        RECT 2396.300000 0.000000 2396.440000 0.485000 ;
    END
  END la_oenb[103]
  PIN la_oenb[102]
    DIRECTION INPUT ;
    USE SIGNAL ;
    PORT
      LAYER met2 ;
        RECT 2378.820000 0.000000 2378.960000 0.485000 ;
    END
  END la_oenb[102]
  PIN la_oenb[101]
    DIRECTION INPUT ;
    USE SIGNAL ;
    PORT
      LAYER met2 ;
        RECT 2361.800000 0.000000 2361.940000 0.485000 ;
    END
  END la_oenb[101]
  PIN la_oenb[100]
    DIRECTION INPUT ;
    USE SIGNAL ;
    PORT
      LAYER met2 ;
        RECT 2344.320000 0.000000 2344.460000 0.485000 ;
    END
  END la_oenb[100]
  PIN la_oenb[99]
    DIRECTION INPUT ;
    USE SIGNAL ;
    PORT
      LAYER met2 ;
        RECT 2327.300000 0.000000 2327.440000 0.485000 ;
    END
  END la_oenb[99]
  PIN la_oenb[98]
    DIRECTION INPUT ;
    USE SIGNAL ;
    PORT
      LAYER met2 ;
        RECT 2309.820000 0.000000 2309.960000 0.485000 ;
    END
  END la_oenb[98]
  PIN la_oenb[97]
    DIRECTION INPUT ;
    USE SIGNAL ;
    PORT
      LAYER met2 ;
        RECT 2292.800000 0.000000 2292.940000 0.485000 ;
    END
  END la_oenb[97]
  PIN la_oenb[96]
    DIRECTION INPUT ;
    USE SIGNAL ;
    PORT
      LAYER met2 ;
        RECT 2275.320000 0.000000 2275.460000 0.485000 ;
    END
  END la_oenb[96]
  PIN la_oenb[95]
    DIRECTION INPUT ;
    USE SIGNAL ;
    PORT
      LAYER met2 ;
        RECT 2258.300000 0.000000 2258.440000 0.485000 ;
    END
  END la_oenb[95]
  PIN la_oenb[94]
    DIRECTION INPUT ;
    USE SIGNAL ;
    PORT
      LAYER met2 ;
        RECT 2241.280000 0.000000 2241.420000 0.485000 ;
    END
  END la_oenb[94]
  PIN la_oenb[93]
    DIRECTION INPUT ;
    USE SIGNAL ;
    PORT
      LAYER met2 ;
        RECT 2223.800000 0.000000 2223.940000 0.485000 ;
    END
  END la_oenb[93]
  PIN la_oenb[92]
    DIRECTION INPUT ;
    USE SIGNAL ;
    PORT
      LAYER met2 ;
        RECT 2206.780000 0.000000 2206.920000 0.485000 ;
    END
  END la_oenb[92]
  PIN la_oenb[91]
    DIRECTION INPUT ;
    USE SIGNAL ;
    PORT
      LAYER met2 ;
        RECT 2189.300000 0.000000 2189.440000 0.485000 ;
    END
  END la_oenb[91]
  PIN la_oenb[90]
    DIRECTION INPUT ;
    USE SIGNAL ;
    PORT
      LAYER met2 ;
        RECT 2172.280000 0.000000 2172.420000 0.485000 ;
    END
  END la_oenb[90]
  PIN la_oenb[89]
    DIRECTION INPUT ;
    USE SIGNAL ;
    PORT
      LAYER met2 ;
        RECT 2154.800000 0.000000 2154.940000 0.485000 ;
    END
  END la_oenb[89]
  PIN la_oenb[88]
    DIRECTION INPUT ;
    USE SIGNAL ;
    PORT
      LAYER met2 ;
        RECT 2137.780000 0.000000 2137.920000 0.485000 ;
    END
  END la_oenb[88]
  PIN la_oenb[87]
    DIRECTION INPUT ;
    USE SIGNAL ;
    PORT
      LAYER met2 ;
        RECT 2120.300000 0.000000 2120.440000 0.485000 ;
    END
  END la_oenb[87]
  PIN la_oenb[86]
    DIRECTION INPUT ;
    USE SIGNAL ;
    PORT
      LAYER met2 ;
        RECT 2103.280000 0.000000 2103.420000 0.485000 ;
    END
  END la_oenb[86]
  PIN la_oenb[85]
    DIRECTION INPUT ;
    USE SIGNAL ;
    PORT
      LAYER met2 ;
        RECT 2085.800000 0.000000 2085.940000 0.485000 ;
    END
  END la_oenb[85]
  PIN la_oenb[84]
    DIRECTION INPUT ;
    USE SIGNAL ;
    PORT
      LAYER met2 ;
        RECT 2068.780000 0.000000 2068.920000 0.485000 ;
    END
  END la_oenb[84]
  PIN la_oenb[83]
    DIRECTION INPUT ;
    USE SIGNAL ;
    PORT
      LAYER met2 ;
        RECT 2051.300000 0.000000 2051.440000 0.485000 ;
    END
  END la_oenb[83]
  PIN la_oenb[82]
    DIRECTION INPUT ;
    USE SIGNAL ;
    PORT
      LAYER met2 ;
        RECT 2034.280000 0.000000 2034.420000 0.485000 ;
    END
  END la_oenb[82]
  PIN la_oenb[81]
    DIRECTION INPUT ;
    USE SIGNAL ;
    PORT
      LAYER met2 ;
        RECT 2016.800000 0.000000 2016.940000 0.485000 ;
    END
  END la_oenb[81]
  PIN la_oenb[80]
    DIRECTION INPUT ;
    USE SIGNAL ;
    PORT
      LAYER met2 ;
        RECT 1999.780000 0.000000 1999.920000 0.485000 ;
    END
  END la_oenb[80]
  PIN la_oenb[79]
    DIRECTION INPUT ;
    USE SIGNAL ;
    PORT
      LAYER met2 ;
        RECT 1982.300000 0.000000 1982.440000 0.485000 ;
    END
  END la_oenb[79]
  PIN la_oenb[78]
    DIRECTION INPUT ;
    USE SIGNAL ;
    PORT
      LAYER met2 ;
        RECT 1965.280000 0.000000 1965.420000 0.485000 ;
    END
  END la_oenb[78]
  PIN la_oenb[77]
    DIRECTION INPUT ;
    USE SIGNAL ;
    PORT
      LAYER met2 ;
        RECT 1948.260000 0.000000 1948.400000 0.485000 ;
    END
  END la_oenb[77]
  PIN la_oenb[76]
    DIRECTION INPUT ;
    USE SIGNAL ;
    PORT
      LAYER met2 ;
        RECT 1930.780000 0.000000 1930.920000 0.485000 ;
    END
  END la_oenb[76]
  PIN la_oenb[75]
    DIRECTION INPUT ;
    USE SIGNAL ;
    PORT
      LAYER met2 ;
        RECT 1913.760000 0.000000 1913.900000 0.485000 ;
    END
  END la_oenb[75]
  PIN la_oenb[74]
    DIRECTION INPUT ;
    USE SIGNAL ;
    PORT
      LAYER met2 ;
        RECT 1896.280000 0.000000 1896.420000 0.485000 ;
    END
  END la_oenb[74]
  PIN la_oenb[73]
    DIRECTION INPUT ;
    USE SIGNAL ;
    PORT
      LAYER met2 ;
        RECT 1879.260000 0.000000 1879.400000 0.485000 ;
    END
  END la_oenb[73]
  PIN la_oenb[72]
    DIRECTION INPUT ;
    USE SIGNAL ;
    PORT
      LAYER met2 ;
        RECT 1861.780000 0.000000 1861.920000 0.485000 ;
    END
  END la_oenb[72]
  PIN la_oenb[71]
    DIRECTION INPUT ;
    USE SIGNAL ;
    PORT
      LAYER met2 ;
        RECT 1844.760000 0.000000 1844.900000 0.485000 ;
    END
  END la_oenb[71]
  PIN la_oenb[70]
    DIRECTION INPUT ;
    USE SIGNAL ;
    PORT
      LAYER met2 ;
        RECT 1827.280000 0.000000 1827.420000 0.485000 ;
    END
  END la_oenb[70]
  PIN la_oenb[69]
    DIRECTION INPUT ;
    USE SIGNAL ;
    PORT
      LAYER met2 ;
        RECT 1810.260000 0.000000 1810.400000 0.485000 ;
    END
  END la_oenb[69]
  PIN la_oenb[68]
    DIRECTION INPUT ;
    USE SIGNAL ;
    PORT
      LAYER met2 ;
        RECT 1792.780000 0.000000 1792.920000 0.485000 ;
    END
  END la_oenb[68]
  PIN la_oenb[67]
    DIRECTION INPUT ;
    USE SIGNAL ;
    PORT
      LAYER met2 ;
        RECT 1775.760000 0.000000 1775.900000 0.485000 ;
    END
  END la_oenb[67]
  PIN la_oenb[66]
    DIRECTION INPUT ;
    USE SIGNAL ;
    PORT
      LAYER met2 ;
        RECT 1758.280000 0.000000 1758.420000 0.485000 ;
    END
  END la_oenb[66]
  PIN la_oenb[65]
    DIRECTION INPUT ;
    USE SIGNAL ;
    PORT
      LAYER met2 ;
        RECT 1741.260000 0.000000 1741.400000 0.485000 ;
    END
  END la_oenb[65]
  PIN la_oenb[64]
    DIRECTION INPUT ;
    USE SIGNAL ;
    PORT
      LAYER met2 ;
        RECT 1723.780000 0.000000 1723.920000 0.485000 ;
    END
  END la_oenb[64]
  PIN la_oenb[63]
    DIRECTION INPUT ;
    USE SIGNAL ;
    PORT
      LAYER met2 ;
        RECT 1706.760000 0.000000 1706.900000 0.485000 ;
    END
  END la_oenb[63]
  PIN la_oenb[62]
    DIRECTION INPUT ;
    USE SIGNAL ;
    PORT
      LAYER met2 ;
        RECT 1689.740000 0.000000 1689.880000 0.485000 ;
    END
  END la_oenb[62]
  PIN la_oenb[61]
    DIRECTION INPUT ;
    USE SIGNAL ;
    PORT
      LAYER met2 ;
        RECT 1672.260000 0.000000 1672.400000 0.485000 ;
    END
  END la_oenb[61]
  PIN la_oenb[60]
    DIRECTION INPUT ;
    USE SIGNAL ;
    PORT
      LAYER met2 ;
        RECT 1655.240000 0.000000 1655.380000 0.485000 ;
    END
  END la_oenb[60]
  PIN la_oenb[59]
    DIRECTION INPUT ;
    USE SIGNAL ;
    PORT
      LAYER met2 ;
        RECT 1637.760000 0.000000 1637.900000 0.485000 ;
    END
  END la_oenb[59]
  PIN la_oenb[58]
    DIRECTION INPUT ;
    USE SIGNAL ;
    PORT
      LAYER met2 ;
        RECT 1620.740000 0.000000 1620.880000 0.485000 ;
    END
  END la_oenb[58]
  PIN la_oenb[57]
    DIRECTION INPUT ;
    USE SIGNAL ;
    PORT
      LAYER met2 ;
        RECT 1603.260000 0.000000 1603.400000 0.485000 ;
    END
  END la_oenb[57]
  PIN la_oenb[56]
    DIRECTION INPUT ;
    USE SIGNAL ;
    PORT
      LAYER met2 ;
        RECT 1586.240000 0.000000 1586.380000 0.485000 ;
    END
  END la_oenb[56]
  PIN la_oenb[55]
    DIRECTION INPUT ;
    USE SIGNAL ;
    PORT
      LAYER met2 ;
        RECT 1568.760000 0.000000 1568.900000 0.485000 ;
    END
  END la_oenb[55]
  PIN la_oenb[54]
    DIRECTION INPUT ;
    USE SIGNAL ;
    PORT
      LAYER met2 ;
        RECT 1551.740000 0.000000 1551.880000 0.485000 ;
    END
  END la_oenb[54]
  PIN la_oenb[53]
    DIRECTION INPUT ;
    USE SIGNAL ;
    PORT
      LAYER met2 ;
        RECT 1534.260000 0.000000 1534.400000 0.485000 ;
    END
  END la_oenb[53]
  PIN la_oenb[52]
    DIRECTION INPUT ;
    USE SIGNAL ;
    PORT
      LAYER met2 ;
        RECT 1517.240000 0.000000 1517.380000 0.485000 ;
    END
  END la_oenb[52]
  PIN la_oenb[51]
    DIRECTION INPUT ;
    USE SIGNAL ;
    PORT
      LAYER met2 ;
        RECT 1499.760000 0.000000 1499.900000 0.485000 ;
    END
  END la_oenb[51]
  PIN la_oenb[50]
    DIRECTION INPUT ;
    USE SIGNAL ;
    PORT
      LAYER met2 ;
        RECT 1482.740000 0.000000 1482.880000 0.485000 ;
    END
  END la_oenb[50]
  PIN la_oenb[49]
    DIRECTION INPUT ;
    USE SIGNAL ;
    PORT
      LAYER met2 ;
        RECT 1465.260000 0.000000 1465.400000 0.485000 ;
    END
  END la_oenb[49]
  PIN la_oenb[48]
    DIRECTION INPUT ;
    USE SIGNAL ;
    PORT
      LAYER met2 ;
        RECT 1448.240000 0.000000 1448.380000 0.485000 ;
    END
  END la_oenb[48]
  PIN la_oenb[47]
    DIRECTION INPUT ;
    USE SIGNAL ;
    PORT
      LAYER met2 ;
        RECT 1430.760000 0.000000 1430.900000 0.485000 ;
    END
  END la_oenb[47]
  PIN la_oenb[46]
    DIRECTION INPUT ;
    USE SIGNAL ;
    PORT
      LAYER met2 ;
        RECT 1413.740000 0.000000 1413.880000 0.485000 ;
    END
  END la_oenb[46]
  PIN la_oenb[45]
    DIRECTION INPUT ;
    USE SIGNAL ;
    PORT
      LAYER met2 ;
        RECT 1396.720000 0.000000 1396.860000 0.485000 ;
    END
  END la_oenb[45]
  PIN la_oenb[44]
    DIRECTION INPUT ;
    USE SIGNAL ;
    PORT
      LAYER met2 ;
        RECT 1379.240000 0.000000 1379.380000 0.485000 ;
    END
  END la_oenb[44]
  PIN la_oenb[43]
    DIRECTION INPUT ;
    USE SIGNAL ;
    PORT
      LAYER met2 ;
        RECT 1362.220000 0.000000 1362.360000 0.485000 ;
    END
  END la_oenb[43]
  PIN la_oenb[42]
    DIRECTION INPUT ;
    USE SIGNAL ;
    PORT
      LAYER met2 ;
        RECT 1344.740000 0.000000 1344.880000 0.485000 ;
    END
  END la_oenb[42]
  PIN la_oenb[41]
    DIRECTION INPUT ;
    USE SIGNAL ;
    PORT
      LAYER met2 ;
        RECT 1327.720000 0.000000 1327.860000 0.485000 ;
    END
  END la_oenb[41]
  PIN la_oenb[40]
    DIRECTION INPUT ;
    USE SIGNAL ;
    PORT
      LAYER met2 ;
        RECT 1310.240000 0.000000 1310.380000 0.485000 ;
    END
  END la_oenb[40]
  PIN la_oenb[39]
    DIRECTION INPUT ;
    USE SIGNAL ;
    PORT
      LAYER met2 ;
        RECT 1293.220000 0.000000 1293.360000 0.485000 ;
    END
  END la_oenb[39]
  PIN la_oenb[38]
    DIRECTION INPUT ;
    USE SIGNAL ;
    PORT
      LAYER met2 ;
        RECT 1275.740000 0.000000 1275.880000 0.485000 ;
    END
  END la_oenb[38]
  PIN la_oenb[37]
    DIRECTION INPUT ;
    USE SIGNAL ;
    PORT
      LAYER met2 ;
        RECT 1258.720000 0.000000 1258.860000 0.485000 ;
    END
  END la_oenb[37]
  PIN la_oenb[36]
    DIRECTION INPUT ;
    USE SIGNAL ;
    PORT
      LAYER met2 ;
        RECT 1241.240000 0.000000 1241.380000 0.485000 ;
    END
  END la_oenb[36]
  PIN la_oenb[35]
    DIRECTION INPUT ;
    USE SIGNAL ;
    PORT
      LAYER met2 ;
        RECT 1224.220000 0.000000 1224.360000 0.485000 ;
    END
  END la_oenb[35]
  PIN la_oenb[34]
    DIRECTION INPUT ;
    USE SIGNAL ;
    PORT
      LAYER met2 ;
        RECT 1206.740000 0.000000 1206.880000 0.485000 ;
    END
  END la_oenb[34]
  PIN la_oenb[33]
    DIRECTION INPUT ;
    USE SIGNAL ;
    PORT
      LAYER met2 ;
        RECT 1189.720000 0.000000 1189.860000 0.485000 ;
    END
  END la_oenb[33]
  PIN la_oenb[32]
    DIRECTION INPUT ;
    USE SIGNAL ;
    PORT
      LAYER met2 ;
        RECT 1172.240000 0.000000 1172.380000 0.485000 ;
    END
  END la_oenb[32]
  PIN la_oenb[31]
    DIRECTION INPUT ;
    USE SIGNAL ;
    PORT
      LAYER met2 ;
        RECT 1155.220000 0.000000 1155.360000 0.485000 ;
    END
  END la_oenb[31]
  PIN la_oenb[30]
    DIRECTION INPUT ;
    USE SIGNAL ;
    PORT
      LAYER met2 ;
        RECT 1137.740000 0.000000 1137.880000 0.485000 ;
    END
  END la_oenb[30]
  PIN la_oenb[29]
    DIRECTION INPUT ;
    USE SIGNAL ;
    PORT
      LAYER met2 ;
        RECT 1120.720000 0.000000 1120.860000 0.485000 ;
    END
  END la_oenb[29]
  PIN la_oenb[28]
    DIRECTION INPUT ;
    USE SIGNAL ;
    PORT
      LAYER met2 ;
        RECT 1103.700000 0.000000 1103.840000 0.485000 ;
    END
  END la_oenb[28]
  PIN la_oenb[27]
    DIRECTION INPUT ;
    USE SIGNAL ;
    PORT
      LAYER met2 ;
        RECT 1086.220000 0.000000 1086.360000 0.485000 ;
    END
  END la_oenb[27]
  PIN la_oenb[26]
    DIRECTION INPUT ;
    USE SIGNAL ;
    PORT
      LAYER met2 ;
        RECT 1069.200000 0.000000 1069.340000 0.485000 ;
    END
  END la_oenb[26]
  PIN la_oenb[25]
    DIRECTION INPUT ;
    USE SIGNAL ;
    PORT
      LAYER met2 ;
        RECT 1051.720000 0.000000 1051.860000 0.485000 ;
    END
  END la_oenb[25]
  PIN la_oenb[24]
    DIRECTION INPUT ;
    USE SIGNAL ;
    PORT
      LAYER met2 ;
        RECT 1034.700000 0.000000 1034.840000 0.485000 ;
    END
  END la_oenb[24]
  PIN la_oenb[23]
    DIRECTION INPUT ;
    USE SIGNAL ;
    PORT
      LAYER met2 ;
        RECT 1017.220000 0.000000 1017.360000 0.485000 ;
    END
  END la_oenb[23]
  PIN la_oenb[22]
    DIRECTION INPUT ;
    USE SIGNAL ;
    PORT
      LAYER met2 ;
        RECT 1000.200000 0.000000 1000.340000 0.485000 ;
    END
  END la_oenb[22]
  PIN la_oenb[21]
    DIRECTION INPUT ;
    USE SIGNAL ;
    PORT
      LAYER met2 ;
        RECT 982.720000 0.000000 982.860000 0.485000 ;
    END
  END la_oenb[21]
  PIN la_oenb[20]
    DIRECTION INPUT ;
    USE SIGNAL ;
    PORT
      LAYER met2 ;
        RECT 965.700000 0.000000 965.840000 0.485000 ;
    END
  END la_oenb[20]
  PIN la_oenb[19]
    DIRECTION INPUT ;
    USE SIGNAL ;
    PORT
      LAYER met2 ;
        RECT 948.220000 0.000000 948.360000 0.485000 ;
    END
  END la_oenb[19]
  PIN la_oenb[18]
    DIRECTION INPUT ;
    USE SIGNAL ;
    PORT
      LAYER met2 ;
        RECT 931.200000 0.000000 931.340000 0.485000 ;
    END
  END la_oenb[18]
  PIN la_oenb[17]
    DIRECTION INPUT ;
    USE SIGNAL ;
    PORT
      LAYER met2 ;
        RECT 913.720000 0.000000 913.860000 0.485000 ;
    END
  END la_oenb[17]
  PIN la_oenb[16]
    DIRECTION INPUT ;
    USE SIGNAL ;
    PORT
      LAYER met2 ;
        RECT 896.700000 0.000000 896.840000 0.485000 ;
    END
  END la_oenb[16]
  PIN la_oenb[15]
    DIRECTION INPUT ;
    USE SIGNAL ;
    PORT
      LAYER met2 ;
        RECT 879.220000 0.000000 879.360000 0.485000 ;
    END
  END la_oenb[15]
  PIN la_oenb[14]
    DIRECTION INPUT ;
    USE SIGNAL ;
    PORT
      LAYER met2 ;
        RECT 862.200000 0.000000 862.340000 0.485000 ;
    END
  END la_oenb[14]
  PIN la_oenb[13]
    DIRECTION INPUT ;
    USE SIGNAL ;
    PORT
      LAYER met2 ;
        RECT 845.180000 0.000000 845.320000 0.485000 ;
    END
  END la_oenb[13]
  PIN la_oenb[12]
    DIRECTION INPUT ;
    USE SIGNAL ;
    PORT
      LAYER met2 ;
        RECT 827.700000 0.000000 827.840000 0.485000 ;
    END
  END la_oenb[12]
  PIN la_oenb[11]
    DIRECTION INPUT ;
    USE SIGNAL ;
    PORT
      LAYER met2 ;
        RECT 810.680000 0.000000 810.820000 0.485000 ;
    END
  END la_oenb[11]
  PIN la_oenb[10]
    DIRECTION INPUT ;
    USE SIGNAL ;
    PORT
      LAYER met2 ;
        RECT 793.200000 0.000000 793.340000 0.485000 ;
    END
  END la_oenb[10]
  PIN la_oenb[9]
    DIRECTION INPUT ;
    USE SIGNAL ;
    PORT
      LAYER met2 ;
        RECT 776.180000 0.000000 776.320000 0.485000 ;
    END
  END la_oenb[9]
  PIN la_oenb[8]
    DIRECTION INPUT ;
    USE SIGNAL ;
    PORT
      LAYER met2 ;
        RECT 758.700000 0.000000 758.840000 0.485000 ;
    END
  END la_oenb[8]
  PIN la_oenb[7]
    DIRECTION INPUT ;
    USE SIGNAL ;
    PORT
      LAYER met2 ;
        RECT 741.680000 0.000000 741.820000 0.485000 ;
    END
  END la_oenb[7]
  PIN la_oenb[6]
    DIRECTION INPUT ;
    USE SIGNAL ;
    PORT
      LAYER met2 ;
        RECT 724.200000 0.000000 724.340000 0.485000 ;
    END
  END la_oenb[6]
  PIN la_oenb[5]
    DIRECTION INPUT ;
    USE SIGNAL ;
    PORT
      LAYER met2 ;
        RECT 707.180000 0.000000 707.320000 0.485000 ;
    END
  END la_oenb[5]
  PIN la_oenb[4]
    DIRECTION INPUT ;
    USE SIGNAL ;
    PORT
      LAYER met2 ;
        RECT 689.700000 0.000000 689.840000 0.485000 ;
    END
  END la_oenb[4]
  PIN la_oenb[3]
    DIRECTION INPUT ;
    USE SIGNAL ;
    PORT
      LAYER met2 ;
        RECT 672.680000 0.000000 672.820000 0.485000 ;
    END
  END la_oenb[3]
  PIN la_oenb[2]
    DIRECTION INPUT ;
    USE SIGNAL ;
    PORT
      LAYER met2 ;
        RECT 655.200000 0.000000 655.340000 0.485000 ;
    END
  END la_oenb[2]
  PIN la_oenb[1]
    DIRECTION INPUT ;
    USE SIGNAL ;
    PORT
      LAYER met2 ;
        RECT 638.180000 0.000000 638.320000 0.485000 ;
    END
  END la_oenb[1]
  PIN la_oenb[0]
    DIRECTION INPUT ;
    USE SIGNAL ;
    PORT
      LAYER met2 ;
        RECT 620.700000 0.000000 620.840000 0.485000 ;
    END
  END la_oenb[0]
  PIN io_in[37]
    DIRECTION INPUT ;
    USE SIGNAL ;
    PORT
      LAYER met3 ;
        RECT 0.000000 165.220000 0.800000 165.520000 ;
    END
  END io_in[37]
  PIN io_in[36]
    DIRECTION INPUT ;
    USE SIGNAL ;
    PORT
      LAYER met3 ;
        RECT 0.000000 412.270000 0.800000 412.570000 ;
    END
  END io_in[36]
  PIN io_in[35]
    DIRECTION INPUT ;
    USE SIGNAL ;
    PORT
      LAYER met3 ;
        RECT 0.000000 659.320000 0.800000 659.620000 ;
    END
  END io_in[35]
  PIN io_in[34]
    DIRECTION INPUT ;
    USE SIGNAL ;
    PORT
      LAYER met3 ;
        RECT 0.000000 906.370000 0.800000 906.670000 ;
    END
  END io_in[34]
  PIN io_in[33]
    DIRECTION INPUT ;
    USE SIGNAL ;
    ANTENNAPARTIALMETALAREA 56.3854 LAYER met3  ;
    ANTENNAPARTIALMETALSIDEAREA 301.184 LAYER met3  ;
    ANTENNAPARTIALCUTAREA 0.04 LAYER via3  ;
    ANTENNAPARTIALMETALAREA 0.3258 LAYER met4  ;
    ANTENNAPARTIALMETALSIDEAREA 2.208 LAYER met4  ;
    ANTENNAMODEL OXIDE1 ;
    ANTENNAGATEAREA 0.665 LAYER met4  ;
    ANTENNAMAXAREACAR 9.72083 LAYER met4  ;
    ANTENNAMAXSIDEAREACAR 50.4977 LAYER met4  ;
    ANTENNAMAXCUTCAR 0.197594 LAYER via4  ;
    PORT
      LAYER met3 ;
        RECT 0.000000 1153.420000 0.800000 1153.720000 ;
    END
  END io_in[33]
  PIN io_in[32]
    DIRECTION INPUT ;
    USE SIGNAL ;
    ANTENNAPARTIALMETALAREA 30.5104 LAYER met3  ;
    ANTENNAPARTIALMETALSIDEAREA 163.184 LAYER met3  ;
    ANTENNAPARTIALCUTAREA 0.04 LAYER via3  ;
    ANTENNAPARTIALMETALAREA 9.6348 LAYER met4  ;
    ANTENNAPARTIALMETALSIDEAREA 51.856 LAYER met4  ;
    ANTENNAMODEL OXIDE1 ;
    ANTENNAGATEAREA 0.665 LAYER met4  ;
    ANTENNAMAXAREACAR 25.7449 LAYER met4  ;
    ANTENNAMAXSIDEAREACAR 133.716 LAYER met4  ;
    ANTENNAMAXCUTCAR 0.197594 LAYER via4  ;
    PORT
      LAYER met3 ;
        RECT 0.000000 1400.470000 0.800000 1400.770000 ;
    END
  END io_in[32]
  PIN io_in[31]
    DIRECTION INPUT ;
    USE SIGNAL ;
    ANTENNAPARTIALMETALAREA 0.1644 LAYER met3  ;
    ANTENNAPARTIALMETALSIDEAREA 0.872 LAYER met3  ;
    ANTENNAMODEL OXIDE1 ;
    ANTENNAGATEAREA 0.665 LAYER met3  ;
    ANTENNAMAXAREACAR 9.38925 LAYER met3  ;
    ANTENNAMAXSIDEAREACAR 44.618 LAYER met3  ;
    ANTENNAMAXCUTCAR 0.137444 LAYER via3  ;
    PORT
      LAYER met3 ;
        RECT 0.000000 1647.520000 0.800000 1647.820000 ;
    END
  END io_in[31]
  PIN io_in[30]
    DIRECTION INPUT ;
    USE SIGNAL ;
    ANTENNAPARTIALMETALAREA 3.8904 LAYER met3  ;
    ANTENNAPARTIALMETALSIDEAREA 20.744 LAYER met3  ;
    ANTENNAMODEL OXIDE1 ;
    ANTENNAGATEAREA 0.665 LAYER met3  ;
    ANTENNAMAXAREACAR 70.4998 LAYER met3  ;
    ANTENNAMAXSIDEAREACAR 350.823 LAYER met3  ;
    ANTENNAMAXCUTCAR 0.137444 LAYER via3  ;
    PORT
      LAYER met3 ;
        RECT 0.000000 1894.570000 0.800000 1894.870000 ;
    END
  END io_in[30]
  PIN io_in[29]
    DIRECTION INPUT ;
    USE SIGNAL ;
    ANTENNAPARTIALMETALAREA 35.5474 LAYER met3  ;
    ANTENNAPARTIALMETALSIDEAREA 190.048 LAYER met3  ;
    ANTENNAPARTIALCUTAREA 0.04 LAYER via3  ;
    ANTENNAPARTIALMETALAREA 0.6516 LAYER met4  ;
    ANTENNAPARTIALMETALSIDEAREA 4.416 LAYER met4  ;
    ANTENNAMODEL OXIDE1 ;
    ANTENNAGATEAREA 0.1965 LAYER met4  ;
    ANTENNAMAXAREACAR 59.2377 LAYER met4  ;
    ANTENNAMAXSIDEAREACAR 311.791 LAYER met4  ;
    ANTENNAMAXCUTCAR 0.668702 LAYER via4  ;
    PORT
      LAYER met3 ;
        RECT 0.000000 2141.620000 0.800000 2141.920000 ;
    END
  END io_in[29]
  PIN io_in[28]
    DIRECTION INPUT ;
    USE SIGNAL ;
    ANTENNAPARTIALMETALAREA 18.5926 LAYER met3  ;
    ANTENNAPARTIALMETALSIDEAREA 99.152 LAYER met3  ;
    ANTENNAPARTIALCUTAREA 0.04 LAYER via3  ;
    ANTENNAPARTIALMETALAREA 63.5506 LAYER met4  ;
    ANTENNAPARTIALMETALSIDEAREA 335.752 LAYER met4  ;
    ANTENNAPARTIALCUTAREA 0.64 LAYER via4  ;
    ANTENNAPARTIALMETALAREA 18.352 LAYER met5  ;
    ANTENNAPARTIALMETALSIDEAREA 31.368 LAYER met5  ;
    ANTENNAMODEL OXIDE1 ;
    ANTENNAGATEAREA 0.1965 LAYER met5  ;
    ANTENNAMAXAREACAR 222.163 LAYER met5  ;
    ANTENNAMAXSIDEAREACAR 824.321 LAYER met5  ;
    PORT
      LAYER met3 ;
        RECT 0.000000 2388.670000 0.800000 2388.970000 ;
    END
  END io_in[28]
  PIN io_in[27]
    DIRECTION INPUT ;
    USE SIGNAL ;
    ANTENNAPARTIALMETALAREA 6.0984 LAYER met3  ;
    ANTENNAPARTIALMETALSIDEAREA 32.52 LAYER met3  ;
    ANTENNAMODEL OXIDE1 ;
    ANTENNAGATEAREA 0.665 LAYER met3  ;
    ANTENNAMAXAREACAR 48.6715 LAYER met3  ;
    ANTENNAMAXSIDEAREACAR 243.725 LAYER met3  ;
    ANTENNAMAXCUTCAR 0.137444 LAYER via3  ;
    PORT
      LAYER met3 ;
        RECT 0.000000 2635.720000 0.800000 2636.020000 ;
    END
  END io_in[27]
  PIN io_in[26]
    DIRECTION INPUT ;
    USE SIGNAL ;
    ANTENNAPARTIALMETALAREA 0.6954 LAYER met3  ;
    ANTENNAPARTIALMETALSIDEAREA 4.152 LAYER met3  ;
    ANTENNAPARTIALCUTAREA 0.04 LAYER via3  ;
    ANTENNAPARTIALMETALAREA 5.9748 LAYER met4  ;
    ANTENNAPARTIALMETALSIDEAREA 32.336 LAYER met4  ;
    ANTENNAMODEL OXIDE1 ;
    ANTENNAGATEAREA 0.665 LAYER met4  ;
    ANTENNAMAXAREACAR 11.8817 LAYER met4  ;
    ANTENNAMAXSIDEAREACAR 61.2301 LAYER met4  ;
    ANTENNAMAXCUTCAR 0.197594 LAYER via4  ;
    PORT
      LAYER met3 ;
        RECT 0.000000 2882.770000 0.800000 2883.070000 ;
    END
  END io_in[26]
  PIN io_in[25]
    DIRECTION INPUT ;
    USE SIGNAL ;
    ANTENNAPARTIALMETALAREA 0.4194 LAYER met3  ;
    ANTENNAPARTIALMETALSIDEAREA 2.68 LAYER met3  ;
    ANTENNAPARTIALCUTAREA 0.04 LAYER via3  ;
    ANTENNAPARTIALMETALAREA 3.9618 LAYER met4  ;
    ANTENNAPARTIALMETALSIDEAREA 21.6 LAYER met4  ;
    ANTENNAMODEL OXIDE1 ;
    ANTENNAGATEAREA 0.665 LAYER met4  ;
    ANTENNAMAXAREACAR 21.9816 LAYER met4  ;
    ANTENNAMAXSIDEAREACAR 111.075 LAYER met4  ;
    ANTENNAMAXCUTCAR 0.197594 LAYER via4  ;
    PORT
      LAYER met3 ;
        RECT 0.000000 3129.820000 0.800000 3130.120000 ;
    END
  END io_in[25]
  PIN io_in[24]
    DIRECTION INPUT ;
    USE SIGNAL ;
    ANTENNAPARTIALMETALAREA 0.1644 LAYER met3  ;
    ANTENNAPARTIALMETALSIDEAREA 0.872 LAYER met3  ;
    ANTENNAMODEL OXIDE1 ;
    ANTENNAGATEAREA 0.665 LAYER met3  ;
    ANTENNAMAXAREACAR 19.3049 LAYER met3  ;
    ANTENNAMAXSIDEAREACAR 92.803 LAYER met3  ;
    ANTENNAMAXCUTCAR 0.137444 LAYER via3  ;
    PORT
      LAYER met3 ;
        RECT 0.000000 3376.870000 0.800000 3377.170000 ;
    END
  END io_in[24]
  PIN io_in[23]
    DIRECTION INPUT ;
    USE SIGNAL ;
    PORT
      LAYER met2 ;
        RECT 217.280000 3376.735000 217.420000 3377.220000 ;
    END
  END io_in[23]
  PIN io_in[22]
    DIRECTION INPUT ;
    USE SIGNAL ;
    PORT
      LAYER met2 ;
        RECT 543.420000 3376.735000 543.560000 3377.220000 ;
    END
  END io_in[22]
  PIN io_in[21]
    DIRECTION INPUT ;
    USE SIGNAL ;
    PORT
      LAYER met2 ;
        RECT 869.560000 3376.735000 869.700000 3377.220000 ;
    END
  END io_in[21]
  PIN io_in[20]
    DIRECTION INPUT ;
    USE SIGNAL ;
    PORT
      LAYER met2 ;
        RECT 1195.700000 3376.735000 1195.840000 3377.220000 ;
    END
  END io_in[20]
  PIN io_in[19]
    DIRECTION INPUT ;
    USE SIGNAL ;
    PORT
      LAYER met2 ;
        RECT 1521.840000 3376.735000 1521.980000 3377.220000 ;
    END
  END io_in[19]
  PIN io_in[18]
    DIRECTION INPUT ;
    USE SIGNAL ;
    PORT
      LAYER met2 ;
        RECT 1847.980000 3376.735000 1848.120000 3377.220000 ;
    END
  END io_in[18]
  PIN io_in[17]
    DIRECTION INPUT ;
    USE SIGNAL ;
    PORT
      LAYER met2 ;
        RECT 2174.120000 3376.735000 2174.260000 3377.220000 ;
    END
  END io_in[17]
  PIN io_in[16]
    DIRECTION INPUT ;
    USE SIGNAL ;
    PORT
      LAYER met2 ;
        RECT 2500.260000 3376.735000 2500.400000 3377.220000 ;
    END
  END io_in[16]
  PIN io_in[15]
    DIRECTION INPUT ;
    USE SIGNAL ;
    PORT
      LAYER met2 ;
        RECT 2826.860000 3376.735000 2827.000000 3377.220000 ;
    END
  END io_in[15]
  PIN io_in[14]
    DIRECTION INPUT ;
    USE SIGNAL ;
    PORT
      LAYER met3 ;
        RECT 2826.360000 3223.760000 2827.160000 3224.060000 ;
    END
  END io_in[14]
  PIN io_in[13]
    DIRECTION INPUT ;
    USE SIGNAL ;
    PORT
      LAYER met3 ;
        RECT 2826.360000 2993.790000 2827.160000 2994.090000 ;
    END
  END io_in[13]
  PIN io_in[12]
    DIRECTION INPUT ;
    USE SIGNAL ;
    PORT
      LAYER met3 ;
        RECT 2826.360000 2763.210000 2827.160000 2763.510000 ;
    END
  END io_in[12]
  PIN io_in[11]
    DIRECTION INPUT ;
    USE SIGNAL ;
    PORT
      LAYER met3 ;
        RECT 2826.360000 2533.240000 2827.160000 2533.540000 ;
    END
  END io_in[11]
  PIN io_in[10]
    DIRECTION INPUT ;
    USE SIGNAL ;
    PORT
      LAYER met3 ;
        RECT 2826.360000 2302.660000 2827.160000 2302.960000 ;
    END
  END io_in[10]
  PIN io_in[9]
    DIRECTION INPUT ;
    USE SIGNAL ;
    PORT
      LAYER met3 ;
        RECT 2826.360000 2072.690000 2827.160000 2072.990000 ;
    END
  END io_in[9]
  PIN io_in[8]
    DIRECTION INPUT ;
    USE SIGNAL ;
    ANTENNAPARTIALMETALAREA 37.9546 LAYER met3  ;
    ANTENNAPARTIALMETALSIDEAREA 202.416 LAYER met3  ;
    ANTENNAPARTIALCUTAREA 0.04 LAYER via3  ;
    ANTENNAPARTIALMETALAREA 13.7668 LAYER met4  ;
    ANTENNAPARTIALMETALSIDEAREA 69.768 LAYER met4  ;
    ANTENNAPARTIALCUTAREA 0.64 LAYER via4  ;
    ANTENNADIFFAREA 0.4347 LAYER met5  ;
    ANTENNAPARTIALMETALAREA 835.664 LAYER met5  ;
    ANTENNAPARTIALMETALSIDEAREA 1261.18 LAYER met5  ;
    ANTENNAMODEL OXIDE1 ;
    ANTENNAGATEAREA 1.0997 LAYER met5  ;
    ANTENNAMAXAREACAR 807.839 LAYER met5  ;
    ANTENNAMAXSIDEAREACAR 1389.36 LAYER met5  ;
    PORT
      LAYER met3 ;
        RECT 2826.360000 1842.720000 2827.160000 1843.020000 ;
    END
  END io_in[8]
  PIN io_in[7]
    DIRECTION INPUT ;
    USE SIGNAL ;
    PORT
      LAYER met3 ;
        RECT 2826.360000 1612.140000 2827.160000 1612.440000 ;
    END
  END io_in[7]
  PIN io_in[6]
    DIRECTION INPUT ;
    USE SIGNAL ;
    ANTENNAPARTIALMETALAREA 0.5926 LAYER met3  ;
    ANTENNAPARTIALMETALSIDEAREA 3.152 LAYER met3  ;
    ANTENNAPARTIALCUTAREA 0.04 LAYER via3  ;
    ANTENNAPARTIALMETALAREA 70.7986 LAYER met4  ;
    ANTENNAPARTIALMETALSIDEAREA 374.408 LAYER met4  ;
    ANTENNAPARTIALCUTAREA 0.64 LAYER via4  ;
    ANTENNADIFFAREA 0.4347 LAYER met5  ;
    ANTENNAPARTIALMETALAREA 450.032 LAYER met5  ;
    ANTENNAPARTIALMETALSIDEAREA 682.728 LAYER met5  ;
    ANTENNAMODEL OXIDE1 ;
    ANTENNAGATEAREA 1.0997 LAYER met5  ;
    ANTENNAMAXAREACAR 425.361 LAYER met5  ;
    ANTENNAMAXSIDEAREACAR 692.634 LAYER met5  ;
    PORT
      LAYER met3 ;
        RECT 2826.360000 1382.170000 2827.160000 1382.470000 ;
    END
  END io_in[6]
  PIN io_in[5]
    DIRECTION INPUT ;
    USE SIGNAL ;
    ANTENNAPARTIALMETALAREA 58.4764 LAYER met3  ;
    ANTENNAPARTIALMETALSIDEAREA 312.336 LAYER met3  ;
    ANTENNAPARTIALCUTAREA 0.04 LAYER via3  ;
    ANTENNAPARTIALMETALAREA 21.8964 LAYER met4  ;
    ANTENNAPARTIALMETALSIDEAREA 118.192 LAYER met4  ;
    ANTENNAMODEL OXIDE1 ;
    ANTENNAGATEAREA 0.665 LAYER met4  ;
    ANTENNAMAXAREACAR 48.578 LAYER met4  ;
    ANTENNAMAXSIDEAREACAR 257.26 LAYER met4  ;
    ANTENNAMAXCUTCAR 0.197594 LAYER via4  ;
    PORT
      LAYER met3 ;
        RECT 2826.360000 1151.590000 2827.160000 1151.890000 ;
    END
  END io_in[5]
  PIN io_in[4]
    DIRECTION INPUT ;
    USE SIGNAL ;
    ANTENNAPARTIALMETALAREA 0.8334 LAYER met3  ;
    ANTENNAPARTIALMETALSIDEAREA 4.888 LAYER met3  ;
    ANTENNAPARTIALCUTAREA 0.04 LAYER via3  ;
    ANTENNAPARTIALMETALAREA 3.9618 LAYER met4  ;
    ANTENNAPARTIALMETALSIDEAREA 21.6 LAYER met4  ;
    ANTENNAMODEL OXIDE1 ;
    ANTENNAGATEAREA 0.665 LAYER met4  ;
    ANTENNAMAXAREACAR 39.8258 LAYER met4  ;
    ANTENNAMAXSIDEAREACAR 200.296 LAYER met4  ;
    ANTENNAMAXCUTCAR 0.197594 LAYER via4  ;
    PORT
      LAYER met3 ;
        RECT 2826.360000 921.620000 2827.160000 921.920000 ;
    END
  END io_in[4]
  PIN io_in[3]
    DIRECTION INPUT ;
    USE SIGNAL ;
    ANTENNAPARTIALMETALAREA 0.3946 LAYER met3  ;
    ANTENNAPARTIALMETALSIDEAREA 2.096 LAYER met3  ;
    ANTENNAPARTIALCUTAREA 0.04 LAYER via3  ;
    ANTENNAPARTIALMETALAREA 246.257 LAYER met4  ;
    ANTENNAPARTIALMETALSIDEAREA 1310.18 LAYER met4  ;
    ANTENNAPARTIALCUTAREA 0.64 LAYER via4  ;
    ANTENNADIFFAREA 0.4347 LAYER met5  ;
    ANTENNAPARTIALMETALAREA 130.624 LAYER met5  ;
    ANTENNAPARTIALMETALSIDEAREA 199.776 LAYER met5  ;
    ANTENNAMODEL OXIDE1 ;
    ANTENNAGATEAREA 0.5607 LAYER met5  ;
    ANTENNAMAXAREACAR 251.457 LAYER met5  ;
    ANTENNAMAXSIDEAREACAR 430.304 LAYER met5  ;
    PORT
      LAYER met3 ;
        RECT 2826.360000 691.650000 2827.160000 691.950000 ;
    END
  END io_in[3]
  PIN io_in[2]
    DIRECTION INPUT ;
    USE SIGNAL ;
    ANTENNAPARTIALMETALAREA 24.9904 LAYER met3  ;
    ANTENNAPARTIALMETALSIDEAREA 133.744 LAYER met3  ;
    ANTENNAPARTIALCUTAREA 0.04 LAYER via3  ;
    ANTENNAPARTIALMETALAREA 14.9998 LAYER met4  ;
    ANTENNAPARTIALMETALSIDEAREA 76.344 LAYER met4  ;
    ANTENNAPARTIALCUTAREA 0.64 LAYER via4  ;
    ANTENNADIFFAREA 0.4347 LAYER met5  ;
    ANTENNAPARTIALMETALAREA 252.4 LAYER met5  ;
    ANTENNAPARTIALMETALSIDEAREA 382.44 LAYER met5  ;
    ANTENNAMODEL OXIDE1 ;
    ANTENNAGATEAREA 1.0997 LAYER met5  ;
    ANTENNAMAXAREACAR 256.638 LAYER met5  ;
    ANTENNAMAXSIDEAREACAR 479.166 LAYER met5  ;
    PORT
      LAYER met3 ;
        RECT 2826.360000 461.070000 2827.160000 461.370000 ;
    END
  END io_in[2]
  PIN io_in[1]
    DIRECTION INPUT ;
    USE SIGNAL ;
    ANTENNAPARTIALMETALAREA 0.4404 LAYER met3  ;
    ANTENNAPARTIALMETALSIDEAREA 2.344 LAYER met3  ;
    ANTENNAMODEL OXIDE1 ;
    ANTENNAGATEAREA 1.33 LAYER met3  ;
    ANTENNAMAXAREACAR 49.1781 LAYER met3  ;
    ANTENNAMAXSIDEAREACAR 245.18 LAYER met3  ;
    ANTENNAMAXCUTCAR 0.0687218 LAYER via3  ;
    PORT
      LAYER met3 ;
        RECT 2826.360000 231.100000 2827.160000 231.400000 ;
    END
  END io_in[1]
  PIN io_in[0]
    DIRECTION INPUT ;
    USE SIGNAL ;
    ANTENNAPARTIALMETALAREA 8.8584 LAYER met3  ;
    ANTENNAPARTIALMETALSIDEAREA 47.24 LAYER met3  ;
    ANTENNAMODEL OXIDE1 ;
    ANTENNAGATEAREA 1.152 LAYER met3  ;
    ANTENNAMAXAREACAR 13.9067 LAYER met3  ;
    ANTENNAMAXSIDEAREACAR 70.1962 LAYER met3  ;
    ANTENNAMAXCUTCAR 0.0793403 LAYER via3  ;
    PORT
      LAYER met3 ;
        RECT 2826.360000 0.520000 2827.160000 0.820000 ;
    END
  END io_in[0]
  PIN io_out[37]
    DIRECTION OUTPUT ;
    USE SIGNAL ;
    PORT
      LAYER met3 ;
        RECT 0.000000 82.870000 0.800000 83.170000 ;
    END
  END io_out[37]
  PIN io_out[36]
    DIRECTION OUTPUT ;
    USE SIGNAL ;
    PORT
      LAYER met3 ;
        RECT 0.000000 329.920000 0.800000 330.220000 ;
    END
  END io_out[36]
  PIN io_out[35]
    DIRECTION OUTPUT ;
    USE SIGNAL ;
    PORT
      LAYER met3 ;
        RECT 0.000000 576.970000 0.800000 577.270000 ;
    END
  END io_out[35]
  PIN io_out[34]
    DIRECTION OUTPUT ;
    USE SIGNAL ;
    PORT
      LAYER met3 ;
        RECT 0.000000 824.020000 0.800000 824.320000 ;
    END
  END io_out[34]
  PIN io_out[33]
    DIRECTION OUTPUT ;
    USE SIGNAL ;
    ANTENNADIFFAREA 0.714 LAYER met3  ;
    ANTENNAPARTIALMETALAREA 66.7002 LAYER met3  ;
    ANTENNAPARTIALMETALSIDEAREA 356.2 LAYER met3  ;
    PORT
      LAYER met3 ;
        RECT 0.000000 1071.070000 0.800000 1071.370000 ;
    END
  END io_out[33]
  PIN io_out[32]
    DIRECTION OUTPUT ;
    USE SIGNAL ;
    ANTENNAPARTIALMETALAREA 77.9314 LAYER met3  ;
    ANTENNAPARTIALMETALSIDEAREA 416.096 LAYER met3  ;
    ANTENNAPARTIALCUTAREA 0.04 LAYER via3  ;
    ANTENNADIFFAREA 0.714 LAYER met4  ;
    ANTENNAPARTIALMETALAREA 2.1318 LAYER met4  ;
    ANTENNAPARTIALMETALSIDEAREA 11.84 LAYER met4  ;
    PORT
      LAYER met3 ;
        RECT 0.000000 1318.120000 0.800000 1318.420000 ;
    END
  END io_out[32]
  PIN io_out[31]
    DIRECTION OUTPUT ;
    USE SIGNAL ;
    ANTENNADIFFAREA 0.714 LAYER met3  ;
    ANTENNAPARTIALMETALAREA 11.8944 LAYER met3  ;
    ANTENNAPARTIALMETALSIDEAREA 63.432 LAYER met3  ;
    PORT
      LAYER met3 ;
        RECT 0.000000 1565.170000 0.800000 1565.470000 ;
    END
  END io_out[31]
  PIN io_out[30]
    DIRECTION OUTPUT ;
    USE SIGNAL ;
    ANTENNADIFFAREA 0.714 LAYER met3  ;
    ANTENNAPARTIALMETALAREA 4.7184 LAYER met3  ;
    ANTENNAPARTIALMETALSIDEAREA 25.16 LAYER met3  ;
    PORT
      LAYER met3 ;
        RECT 0.000000 1812.220000 0.800000 1812.520000 ;
    END
  END io_out[30]
  PIN io_out[29]
    DIRECTION OUTPUT ;
    USE SIGNAL ;
    PORT
      LAYER met3 ;
        RECT 0.000000 2059.270000 0.800000 2059.570000 ;
    END
  END io_out[29]
  PIN io_out[28]
    DIRECTION OUTPUT ;
    USE SIGNAL ;
    PORT
      LAYER met3 ;
        RECT 0.000000 2306.320000 0.800000 2306.620000 ;
    END
  END io_out[28]
  PIN io_out[27]
    DIRECTION OUTPUT ;
    USE SIGNAL ;
    PORT
      LAYER met3 ;
        RECT 0.000000 2553.370000 0.800000 2553.670000 ;
    END
  END io_out[27]
  PIN io_out[26]
    DIRECTION OUTPUT ;
    USE SIGNAL ;
    ANTENNADIFFAREA 0.714 LAYER met3  ;
    ANTENNAPARTIALMETALAREA 0.9924 LAYER met3  ;
    ANTENNAPARTIALMETALSIDEAREA 5.288 LAYER met3  ;
    PORT
      LAYER met3 ;
        RECT 0.000000 2800.420000 0.800000 2800.720000 ;
    END
  END io_out[26]
  PIN io_out[25]
    DIRECTION OUTPUT ;
    USE SIGNAL ;
    ANTENNADIFFAREA 0.43675 LAYER met3  ;
    ANTENNAPARTIALMETALAREA 8.1684 LAYER met3  ;
    ANTENNAPARTIALMETALSIDEAREA 43.56 LAYER met3  ;
    PORT
      LAYER met3 ;
        RECT 0.000000 3047.470000 0.800000 3047.770000 ;
    END
  END io_out[25]
  PIN io_out[24]
    DIRECTION OUTPUT ;
    USE SIGNAL ;
    ANTENNADIFFAREA 0.43675 LAYER met3  ;
    ANTENNAPARTIALMETALAREA 9.1344 LAYER met3  ;
    ANTENNAPARTIALMETALSIDEAREA 48.712 LAYER met3  ;
    PORT
      LAYER met3 ;
        RECT 0.000000 3294.520000 0.800000 3294.820000 ;
    END
  END io_out[24]
  PIN io_out[23]
    DIRECTION OUTPUT ;
    USE SIGNAL ;
    ANTENNADIFFAREA 0.714 LAYER met2  ;
    ANTENNAPARTIALMETALAREA 10.8959 LAYER met2  ;
    ANTENNAPARTIALMETALSIDEAREA 54.2535 LAYER met2  ;
    PORT
      LAYER met2 ;
        RECT 108.720000 3376.735000 108.860000 3377.220000 ;
    END
  END io_out[23]
  PIN io_out[22]
    DIRECTION OUTPUT ;
    USE SIGNAL ;
    ANTENNADIFFAREA 0.714 LAYER met2  ;
    ANTENNAPARTIALMETALAREA 60.7331 LAYER met2  ;
    ANTENNAPARTIALMETALSIDEAREA 303.439 LAYER met2  ;
    PORT
      LAYER met2 ;
        RECT 434.860000 3376.735000 435.000000 3377.220000 ;
    END
  END io_out[22]
  PIN io_out[21]
    DIRECTION OUTPUT ;
    USE SIGNAL ;
    ANTENNADIFFAREA 0.714 LAYER met2  ;
    ANTENNAPARTIALMETALAREA 133.295 LAYER met2  ;
    ANTENNAPARTIALMETALSIDEAREA 666.249 LAYER met2  ;
    PORT
      LAYER met2 ;
        RECT 761.000000 3376.735000 761.140000 3377.220000 ;
    END
  END io_out[21]
  PIN io_out[20]
    DIRECTION OUTPUT ;
    USE SIGNAL ;
    ANTENNAPARTIALMETALAREA 130.785 LAYER met2  ;
    ANTENNAPARTIALMETALSIDEAREA 653.765 LAYER met2  ;
    ANTENNAPARTIALCUTAREA 0.04 LAYER via2  ;
    ANTENNAPARTIALMETALAREA 13.165 LAYER met3  ;
    ANTENNAPARTIALMETALSIDEAREA 70.68 LAYER met3  ;
    ANTENNAPARTIALCUTAREA 0.04 LAYER via3  ;
    ANTENNADIFFAREA 0.714 LAYER met4  ;
    ANTENNAPARTIALMETALAREA 68.6808 LAYER met4  ;
    ANTENNAPARTIALMETALSIDEAREA 366.768 LAYER met4  ;
    PORT
      LAYER met2 ;
        RECT 1087.140000 3376.735000 1087.280000 3377.220000 ;
    END
  END io_out[20]
  PIN io_out[19]
    DIRECTION OUTPUT ;
    USE SIGNAL ;
    ANTENNAPARTIALMETALAREA 61.2696 LAYER met2  ;
    ANTENNAPARTIALMETALSIDEAREA 306.187 LAYER met2  ;
    ANTENNAPARTIALCUTAREA 0.04 LAYER via2  ;
    ANTENNAPARTIALMETALAREA 5.851 LAYER met3  ;
    ANTENNAPARTIALMETALSIDEAREA 31.672 LAYER met3  ;
    ANTENNAPARTIALCUTAREA 0.04 LAYER via3  ;
    ANTENNADIFFAREA 0.714 LAYER met4  ;
    ANTENNAPARTIALMETALAREA 225.496 LAYER met4  ;
    ANTENNAPARTIALMETALSIDEAREA 1203.58 LAYER met4  ;
    PORT
      LAYER met2 ;
        RECT 1413.280000 3376.735000 1413.420000 3377.220000 ;
    END
  END io_out[19]
  PIN io_out[18]
    DIRECTION OUTPUT ;
    USE SIGNAL ;
    ANTENNAPARTIALMETALAREA 48.8276 LAYER met2  ;
    ANTENNAPARTIALMETALSIDEAREA 243.859 LAYER met2  ;
    ANTENNAPARTIALCUTAREA 0.04 LAYER via2  ;
    ANTENNAPARTIALMETALAREA 0.952 LAYER met3  ;
    ANTENNAPARTIALMETALSIDEAREA 5.544 LAYER met3  ;
    ANTENNAPARTIALCUTAREA 0.04 LAYER via3  ;
    ANTENNADIFFAREA 0.714 LAYER met4  ;
    ANTENNAPARTIALMETALAREA 201.162 LAYER met4  ;
    ANTENNAPARTIALMETALSIDEAREA 1075.22 LAYER met4  ;
    PORT
      LAYER met2 ;
        RECT 1739.420000 3376.735000 1739.560000 3377.220000 ;
    END
  END io_out[18]
  PIN io_out[17]
    DIRECTION OUTPUT ;
    USE SIGNAL ;
    ANTENNADIFFAREA 0.714 LAYER met2  ;
    ANTENNAPARTIALMETALAREA 32.1943 LAYER met2  ;
    ANTENNAPARTIALMETALSIDEAREA 160.864 LAYER met2  ;
    PORT
      LAYER met2 ;
        RECT 2065.560000 3376.735000 2065.700000 3377.220000 ;
    END
  END io_out[17]
  PIN io_out[16]
    DIRECTION OUTPUT ;
    USE SIGNAL ;
    ANTENNAPARTIALMETALAREA 145.368 LAYER met2  ;
    ANTENNAPARTIALMETALSIDEAREA 726.677 LAYER met2  ;
    ANTENNAPARTIALCUTAREA 0.04 LAYER via2  ;
    ANTENNAPARTIALMETALAREA 18.478 LAYER met3  ;
    ANTENNAPARTIALMETALSIDEAREA 99.016 LAYER met3  ;
    ANTENNAPARTIALCUTAREA 0.04 LAYER via3  ;
    ANTENNADIFFAREA 0.891 LAYER met4  ;
    ANTENNAPARTIALMETALAREA 148.834 LAYER met4  ;
    ANTENNAPARTIALMETALSIDEAREA 795.664 LAYER met4  ;
    PORT
      LAYER met2 ;
        RECT 2391.700000 3376.735000 2391.840000 3377.220000 ;
    END
  END io_out[16]
  PIN io_out[15]
    DIRECTION OUTPUT ;
    USE SIGNAL ;
    ANTENNADIFFAREA 0.714 LAYER met2  ;
    ANTENNAPARTIALMETALAREA 206.627 LAYER met2  ;
    ANTENNAPARTIALMETALSIDEAREA 1032.91 LAYER met2  ;
    PORT
      LAYER met2 ;
        RECT 2717.840000 3376.735000 2717.980000 3377.220000 ;
    END
  END io_out[15]
  PIN io_out[14]
    DIRECTION OUTPUT ;
    USE SIGNAL ;
    ANTENNADIFFAREA 0.891 LAYER met3  ;
    ANTENNAPARTIALMETALAREA 22.3344 LAYER met3  ;
    ANTENNAPARTIALMETALSIDEAREA 119.112 LAYER met3  ;
    PORT
      LAYER met3 ;
        RECT 2826.360000 3300.620000 2827.160000 3300.920000 ;
    END
  END io_out[14]
  PIN io_out[13]
    DIRECTION OUTPUT ;
    USE SIGNAL ;
    ANTENNADIFFAREA 0.714 LAYER met3  ;
    ANTENNAPARTIALMETALAREA 8.8584 LAYER met3  ;
    ANTENNAPARTIALMETALSIDEAREA 47.24 LAYER met3  ;
    PORT
      LAYER met3 ;
        RECT 2826.360000 3070.040000 2827.160000 3070.340000 ;
    END
  END io_out[13]
  PIN io_out[12]
    DIRECTION OUTPUT ;
    USE SIGNAL ;
    ANTENNADIFFAREA 0.714 LAYER met3  ;
    ANTENNAPARTIALMETALAREA 11.7564 LAYER met3  ;
    ANTENNAPARTIALMETALSIDEAREA 62.696 LAYER met3  ;
    PORT
      LAYER met3 ;
        RECT 2826.360000 2840.070000 2827.160000 2840.370000 ;
    END
  END io_out[12]
  PIN io_out[11]
    DIRECTION OUTPUT ;
    USE SIGNAL ;
    ANTENNADIFFAREA 0.714 LAYER met3  ;
    ANTENNAPARTIALMETALAREA 0.7464 LAYER met3  ;
    ANTENNAPARTIALMETALSIDEAREA 3.976 LAYER met3  ;
    PORT
      LAYER met3 ;
        RECT 2826.360000 2610.100000 2827.160000 2610.400000 ;
    END
  END io_out[11]
  PIN io_out[10]
    DIRECTION OUTPUT ;
    USE SIGNAL ;
    ANTENNADIFFAREA 0.714 LAYER met3  ;
    ANTENNAPARTIALMETALAREA 0.9924 LAYER met3  ;
    ANTENNAPARTIALMETALSIDEAREA 5.288 LAYER met3  ;
    PORT
      LAYER met3 ;
        RECT 2826.360000 2379.520000 2827.160000 2379.820000 ;
    END
  END io_out[10]
  PIN io_out[9]
    DIRECTION OUTPUT ;
    USE SIGNAL ;
    ANTENNAPARTIALMETALAREA 74.7832 LAYER met3  ;
    ANTENNAPARTIALMETALSIDEAREA 399.776 LAYER met3  ;
    ANTENNAPARTIALCUTAREA 0.04 LAYER via3  ;
    ANTENNAPARTIALMETALAREA 14.3398 LAYER met4  ;
    ANTENNAPARTIALMETALSIDEAREA 72.824 LAYER met4  ;
    ANTENNAPARTIALCUTAREA 0.64 LAYER via4  ;
    ANTENNADIFFAREA 0.4455 LAYER met5  ;
    ANTENNAPARTIALMETALAREA 46.72 LAYER met5  ;
    ANTENNAPARTIALMETALSIDEAREA 73.92 LAYER met5  ;
    PORT
      LAYER met3 ;
        RECT 2826.360000 2149.550000 2827.160000 2149.850000 ;
    END
  END io_out[9]
  PIN io_out[8]
    DIRECTION OUTPUT ;
    USE SIGNAL ;
    PORT
      LAYER met3 ;
        RECT 2826.360000 1918.970000 2827.160000 1919.270000 ;
    END
  END io_out[8]
  PIN io_out[7]
    DIRECTION OUTPUT ;
    USE SIGNAL ;
    PORT
      LAYER met3 ;
        RECT 2826.360000 1689.000000 2827.160000 1689.300000 ;
    END
  END io_out[7]
  PIN io_out[6]
    DIRECTION OUTPUT ;
    USE SIGNAL ;
    PORT
      LAYER met3 ;
        RECT 2826.360000 1459.030000 2827.160000 1459.330000 ;
    END
  END io_out[6]
  PIN io_out[5]
    DIRECTION OUTPUT ;
    USE SIGNAL ;
    PORT
      LAYER met3 ;
        RECT 2826.360000 1228.450000 2827.160000 1228.750000 ;
    END
  END io_out[5]
  PIN io_out[4]
    DIRECTION OUTPUT ;
    USE SIGNAL ;
    PORT
      LAYER met3 ;
        RECT 2826.360000 998.480000 2827.160000 998.780000 ;
    END
  END io_out[4]
  PIN io_out[3]
    DIRECTION OUTPUT ;
    USE SIGNAL ;
    PORT
      LAYER met3 ;
        RECT 2826.360000 767.900000 2827.160000 768.200000 ;
    END
  END io_out[3]
  PIN io_out[2]
    DIRECTION OUTPUT ;
    USE SIGNAL ;
    PORT
      LAYER met3 ;
        RECT 2826.360000 537.930000 2827.160000 538.230000 ;
    END
  END io_out[2]
  PIN io_out[1]
    DIRECTION OUTPUT ;
    USE SIGNAL ;
    PORT
      LAYER met3 ;
        RECT 2826.360000 307.960000 2827.160000 308.260000 ;
    END
  END io_out[1]
  PIN io_out[0]
    DIRECTION OUTPUT ;
    USE SIGNAL ;
    PORT
      LAYER met3 ;
        RECT 2826.360000 77.380000 2827.160000 77.680000 ;
    END
  END io_out[0]
  PIN io_oeb[37]
    DIRECTION OUTPUT ;
    USE SIGNAL ;
    PORT
      LAYER met3 ;
        RECT 0.000000 0.520000 0.800000 0.820000 ;
    END
  END io_oeb[37]
  PIN io_oeb[36]
    DIRECTION OUTPUT ;
    USE SIGNAL ;
    PORT
      LAYER met3 ;
        RECT 0.000000 247.570000 0.800000 247.870000 ;
    END
  END io_oeb[36]
  PIN io_oeb[35]
    DIRECTION OUTPUT ;
    USE SIGNAL ;
    PORT
      LAYER met3 ;
        RECT 0.000000 494.620000 0.800000 494.920000 ;
    END
  END io_oeb[35]
  PIN io_oeb[34]
    DIRECTION OUTPUT ;
    USE SIGNAL ;
    PORT
      LAYER met3 ;
        RECT 0.000000 741.670000 0.800000 741.970000 ;
    END
  END io_oeb[34]
  PIN io_oeb[33]
    DIRECTION OUTPUT ;
    USE SIGNAL ;
    ANTENNADIFFAREA 0.714 LAYER met3  ;
    ANTENNAPARTIALMETALAREA 35.5776 LAYER met3  ;
    ANTENNAPARTIALMETALSIDEAREA 191.168 LAYER met3  ;
    PORT
      LAYER met3 ;
        RECT 0.000000 988.720000 0.800000 989.020000 ;
    END
  END io_oeb[33]
  PIN io_oeb[32]
    DIRECTION OUTPUT ;
    USE SIGNAL ;
    ANTENNADIFFAREA 0.714 LAYER met3  ;
    ANTENNAPARTIALMETALAREA 35.6526 LAYER met3  ;
    ANTENNAPARTIALMETALSIDEAREA 191.568 LAYER met3  ;
    PORT
      LAYER met3 ;
        RECT 0.000000 1235.770000 0.800000 1236.070000 ;
    END
  END io_oeb[32]
  PIN io_oeb[31]
    DIRECTION OUTPUT ;
    USE SIGNAL ;
    ANTENNAPARTIALMETALAREA 0.9784 LAYER met3  ;
    ANTENNAPARTIALMETALSIDEAREA 5.68 LAYER met3  ;
    ANTENNAPARTIALCUTAREA 0.04 LAYER via3  ;
    ANTENNAPARTIALMETALAREA 4.2028 LAYER met4  ;
    ANTENNAPARTIALMETALSIDEAREA 18.76 LAYER met4  ;
    ANTENNAPARTIALCUTAREA 0.64 LAYER via4  ;
    ANTENNADIFFAREA 0.714 LAYER met5  ;
    ANTENNAPARTIALMETALAREA 251.296 LAYER met5  ;
    ANTENNAPARTIALMETALSIDEAREA 380.784 LAYER met5  ;
    PORT
      LAYER met3 ;
        RECT 0.000000 1482.820000 0.800000 1483.120000 ;
    END
  END io_oeb[31]
  PIN io_oeb[30]
    DIRECTION OUTPUT ;
    USE SIGNAL ;
    ANTENNADIFFAREA 0.714 LAYER met3  ;
    ANTENNAPARTIALMETALAREA 15.3444 LAYER met3  ;
    ANTENNAPARTIALMETALSIDEAREA 81.832 LAYER met3  ;
    PORT
      LAYER met3 ;
        RECT 0.000000 1729.870000 0.800000 1730.170000 ;
    END
  END io_oeb[30]
  PIN io_oeb[29]
    DIRECTION OUTPUT ;
    USE SIGNAL ;
    ANTENNADIFFAREA 0.714 LAYER met3  ;
    ANTENNAPARTIALMETALAREA 1.4868 LAYER met3  ;
    ANTENNAPARTIALMETALSIDEAREA 8.4 LAYER met3  ;
    PORT
      LAYER met3 ;
        RECT 0.000000 1976.920000 0.800000 1977.220000 ;
    END
  END io_oeb[29]
  PIN io_oeb[28]
    DIRECTION OUTPUT ;
    USE SIGNAL ;
    ANTENNADIFFAREA 0.714 LAYER met3  ;
    ANTENNAPARTIALMETALAREA 1.5888 LAYER met3  ;
    ANTENNAPARTIALMETALSIDEAREA 9.424 LAYER met3  ;
    PORT
      LAYER met3 ;
        RECT 0.000000 2223.970000 0.800000 2224.270000 ;
    END
  END io_oeb[28]
  PIN io_oeb[27]
    DIRECTION OUTPUT ;
    USE SIGNAL ;
    ANTENNADIFFAREA 0.714 LAYER met3  ;
    ANTENNAPARTIALMETALAREA 8.1684 LAYER met3  ;
    ANTENNAPARTIALMETALSIDEAREA 43.56 LAYER met3  ;
    PORT
      LAYER met3 ;
        RECT 0.000000 2471.020000 0.800000 2471.320000 ;
    END
  END io_oeb[27]
  PIN io_oeb[26]
    DIRECTION OUTPUT ;
    USE SIGNAL ;
    ANTENNADIFFAREA 0.43675 LAYER met3  ;
    ANTENNAPARTIALMETALAREA 1.9104 LAYER met3  ;
    ANTENNAPARTIALMETALSIDEAREA 10.184 LAYER met3  ;
    PORT
      LAYER met3 ;
        RECT 0.000000 2718.070000 0.800000 2718.370000 ;
    END
  END io_oeb[26]
  PIN io_oeb[25]
    DIRECTION OUTPUT ;
    USE SIGNAL ;
    PORT
      LAYER met3 ;
        RECT 0.000000 2965.120000 0.800000 2965.420000 ;
    END
  END io_oeb[25]
  PIN io_oeb[24]
    DIRECTION OUTPUT ;
    USE SIGNAL ;
    PORT
      LAYER met3 ;
        RECT 0.000000 3212.170000 0.800000 3212.470000 ;
    END
  END io_oeb[24]
  PIN io_oeb[23]
    DIRECTION OUTPUT ;
    USE SIGNAL ;
    ANTENNADIFFAREA 0.43675 LAYER met2  ;
    ANTENNAPARTIALMETALAREA 0.6831 LAYER met2  ;
    ANTENNAPARTIALMETALSIDEAREA 3.3075 LAYER met2  ;
    PORT
      LAYER met2 ;
        RECT 0.160000 3376.735000 0.300000 3377.220000 ;
    END
  END io_oeb[23]
  PIN io_oeb[22]
    DIRECTION OUTPUT ;
    USE SIGNAL ;
    ANTENNADIFFAREA 0.43675 LAYER met2  ;
    ANTENNAPARTIALMETALAREA 4.3651 LAYER met2  ;
    ANTENNAPARTIALMETALSIDEAREA 21.7175 LAYER met2  ;
    PORT
      LAYER met2 ;
        RECT 326.300000 3376.735000 326.440000 3377.220000 ;
    END
  END io_oeb[22]
  PIN io_oeb[21]
    DIRECTION OUTPUT ;
    USE SIGNAL ;
    ANTENNADIFFAREA 0.43675 LAYER met2  ;
    ANTENNAPARTIALMETALAREA 4.3007 LAYER met2  ;
    ANTENNAPARTIALMETALSIDEAREA 21.3955 LAYER met2  ;
    PORT
      LAYER met2 ;
        RECT 652.440000 3376.735000 652.580000 3377.220000 ;
    END
  END io_oeb[21]
  PIN io_oeb[20]
    DIRECTION OUTPUT ;
    USE SIGNAL ;
    ANTENNADIFFAREA 0.43675 LAYER met2  ;
    ANTENNAPARTIALMETALAREA 4.3007 LAYER met2  ;
    ANTENNAPARTIALMETALSIDEAREA 21.3955 LAYER met2  ;
    PORT
      LAYER met2 ;
        RECT 978.580000 3376.735000 978.720000 3377.220000 ;
    END
  END io_oeb[20]
  PIN io_oeb[19]
    DIRECTION OUTPUT ;
    USE SIGNAL ;
    ANTENNADIFFAREA 0.43675 LAYER met2  ;
    ANTENNAPARTIALMETALAREA 4.3007 LAYER met2  ;
    ANTENNAPARTIALMETALSIDEAREA 21.3955 LAYER met2  ;
    PORT
      LAYER met2 ;
        RECT 1304.720000 3376.735000 1304.860000 3377.220000 ;
    END
  END io_oeb[19]
  PIN io_oeb[18]
    DIRECTION OUTPUT ;
    USE SIGNAL ;
    ANTENNADIFFAREA 0.43675 LAYER met2  ;
    ANTENNAPARTIALMETALAREA 4.3007 LAYER met2  ;
    ANTENNAPARTIALMETALSIDEAREA 21.3955 LAYER met2  ;
    PORT
      LAYER met2 ;
        RECT 1630.860000 3376.735000 1631.000000 3377.220000 ;
    END
  END io_oeb[18]
  PIN io_oeb[17]
    DIRECTION OUTPUT ;
    USE SIGNAL ;
    ANTENNADIFFAREA 0.43675 LAYER met2  ;
    ANTENNAPARTIALMETALAREA 4.3007 LAYER met2  ;
    ANTENNAPARTIALMETALSIDEAREA 21.3955 LAYER met2  ;
    PORT
      LAYER met2 ;
        RECT 1957.000000 3376.735000 1957.140000 3377.220000 ;
    END
  END io_oeb[17]
  PIN io_oeb[16]
    DIRECTION OUTPUT ;
    USE SIGNAL ;
    ANTENNADIFFAREA 0.43675 LAYER met2  ;
    ANTENNAPARTIALMETALAREA 4.3007 LAYER met2  ;
    ANTENNAPARTIALMETALSIDEAREA 21.3955 LAYER met2  ;
    PORT
      LAYER met2 ;
        RECT 2283.140000 3376.735000 2283.280000 3377.220000 ;
    END
  END io_oeb[16]
  PIN io_oeb[15]
    DIRECTION OUTPUT ;
    USE SIGNAL ;
    ANTENNADIFFAREA 0.43675 LAYER met2  ;
    ANTENNAPARTIALMETALAREA 4.3007 LAYER met2  ;
    ANTENNAPARTIALMETALSIDEAREA 21.3955 LAYER met2  ;
    PORT
      LAYER met2 ;
        RECT 2609.280000 3376.735000 2609.420000 3377.220000 ;
    END
  END io_oeb[15]
  PIN io_oeb[14]
    DIRECTION OUTPUT ;
    USE SIGNAL ;
    ANTENNADIFFAREA 0.43675 LAYER met3  ;
    ANTENNAPARTIALMETALAREA 9.1344 LAYER met3  ;
    ANTENNAPARTIALMETALSIDEAREA 48.712 LAYER met3  ;
    PORT
      LAYER met3 ;
        RECT 2826.360000 3376.870000 2827.160000 3377.170000 ;
    END
  END io_oeb[14]
  PIN io_oeb[13]
    DIRECTION OUTPUT ;
    USE SIGNAL ;
    ANTENNADIFFAREA 0.43675 LAYER met3  ;
    ANTENNAPARTIALMETALAREA 8.9964 LAYER met3  ;
    ANTENNAPARTIALMETALSIDEAREA 47.976 LAYER met3  ;
    PORT
      LAYER met3 ;
        RECT 2826.360000 3146.900000 2827.160000 3147.200000 ;
    END
  END io_oeb[13]
  PIN io_oeb[12]
    DIRECTION OUTPUT ;
    USE SIGNAL ;
    ANTENNADIFFAREA 0.43675 LAYER met3  ;
    ANTENNAPARTIALMETALAREA 9.1344 LAYER met3  ;
    ANTENNAPARTIALMETALSIDEAREA 48.712 LAYER met3  ;
    PORT
      LAYER met3 ;
        RECT 2826.360000 2916.930000 2827.160000 2917.230000 ;
    END
  END io_oeb[12]
  PIN io_oeb[11]
    DIRECTION OUTPUT ;
    USE SIGNAL ;
    ANTENNADIFFAREA 0.43675 LAYER met3  ;
    ANTENNAPARTIALMETALAREA 0.1644 LAYER met3  ;
    ANTENNAPARTIALMETALSIDEAREA 0.872 LAYER met3  ;
    PORT
      LAYER met3 ;
        RECT 2826.360000 2686.350000 2827.160000 2686.650000 ;
    END
  END io_oeb[11]
  PIN io_oeb[10]
    DIRECTION OUTPUT ;
    USE SIGNAL ;
    ANTENNADIFFAREA 0.43675 LAYER met3  ;
    ANTENNAPARTIALMETALAREA 8.9964 LAYER met3  ;
    ANTENNAPARTIALMETALSIDEAREA 47.976 LAYER met3  ;
    PORT
      LAYER met3 ;
        RECT 2826.360000 2456.380000 2827.160000 2456.680000 ;
    END
  END io_oeb[10]
  PIN io_oeb[9]
    DIRECTION OUTPUT ;
    USE SIGNAL ;
    ANTENNADIFFAREA 0.43675 LAYER met3  ;
    ANTENNAPARTIALMETALAREA 0.1644 LAYER met3  ;
    ANTENNAPARTIALMETALSIDEAREA 0.872 LAYER met3  ;
    PORT
      LAYER met3 ;
        RECT 2826.360000 2226.410000 2827.160000 2226.710000 ;
    END
  END io_oeb[9]
  PIN io_oeb[8]
    DIRECTION OUTPUT ;
    USE SIGNAL ;
    ANTENNADIFFAREA 0.43675 LAYER met3  ;
    ANTENNAPARTIALMETALAREA 0.1644 LAYER met3  ;
    ANTENNAPARTIALMETALSIDEAREA 0.872 LAYER met3  ;
    PORT
      LAYER met3 ;
        RECT 2826.360000 1995.830000 2827.160000 1996.130000 ;
    END
  END io_oeb[8]
  PIN io_oeb[7]
    DIRECTION OUTPUT ;
    USE SIGNAL ;
    ANTENNADIFFAREA 0.43675 LAYER met3  ;
    ANTENNAPARTIALMETALAREA 0.1644 LAYER met3  ;
    ANTENNAPARTIALMETALSIDEAREA 0.872 LAYER met3  ;
    PORT
      LAYER met3 ;
        RECT 2826.360000 1765.860000 2827.160000 1766.160000 ;
    END
  END io_oeb[7]
  PIN io_oeb[6]
    DIRECTION OUTPUT ;
    USE SIGNAL ;
    ANTENNADIFFAREA 0.43675 LAYER met3  ;
    ANTENNAPARTIALMETALAREA 0.1644 LAYER met3  ;
    ANTENNAPARTIALMETALSIDEAREA 0.872 LAYER met3  ;
    PORT
      LAYER met3 ;
        RECT 2826.360000 1535.280000 2827.160000 1535.580000 ;
    END
  END io_oeb[6]
  PIN io_oeb[5]
    DIRECTION OUTPUT ;
    USE SIGNAL ;
    ANTENNADIFFAREA 0.43675 LAYER met3  ;
    ANTENNAPARTIALMETALAREA 0.1644 LAYER met3  ;
    ANTENNAPARTIALMETALSIDEAREA 0.872 LAYER met3  ;
    PORT
      LAYER met3 ;
        RECT 2826.360000 1305.310000 2827.160000 1305.610000 ;
    END
  END io_oeb[5]
  PIN io_oeb[4]
    DIRECTION OUTPUT ;
    USE SIGNAL ;
    ANTENNADIFFAREA 0.43675 LAYER met3  ;
    ANTENNAPARTIALMETALAREA 0.1644 LAYER met3  ;
    ANTENNAPARTIALMETALSIDEAREA 0.872 LAYER met3  ;
    PORT
      LAYER met3 ;
        RECT 2826.360000 1075.340000 2827.160000 1075.640000 ;
    END
  END io_oeb[4]
  PIN io_oeb[3]
    DIRECTION OUTPUT ;
    USE SIGNAL ;
    ANTENNADIFFAREA 0.43675 LAYER met3  ;
    ANTENNAPARTIALMETALAREA 8.7204 LAYER met3  ;
    ANTENNAPARTIALMETALSIDEAREA 46.504 LAYER met3  ;
    PORT
      LAYER met3 ;
        RECT 2826.360000 844.760000 2827.160000 845.060000 ;
    END
  END io_oeb[3]
  PIN io_oeb[2]
    DIRECTION OUTPUT ;
    USE SIGNAL ;
    ANTENNADIFFAREA 0.43675 LAYER met3  ;
    ANTENNAPARTIALMETALAREA 0.1644 LAYER met3  ;
    ANTENNAPARTIALMETALSIDEAREA 0.872 LAYER met3  ;
    PORT
      LAYER met3 ;
        RECT 2826.360000 614.790000 2827.160000 615.090000 ;
    END
  END io_oeb[2]
  PIN io_oeb[1]
    DIRECTION OUTPUT ;
    USE SIGNAL ;
    ANTENNADIFFAREA 0.43675 LAYER met3  ;
    ANTENNAPARTIALMETALAREA 8.9964 LAYER met3  ;
    ANTENNAPARTIALMETALSIDEAREA 47.976 LAYER met3  ;
    PORT
      LAYER met3 ;
        RECT 2826.360000 384.210000 2827.160000 384.510000 ;
    END
  END io_oeb[1]
  PIN io_oeb[0]
    DIRECTION OUTPUT ;
    USE SIGNAL ;
    ANTENNADIFFAREA 0.43675 LAYER met3  ;
    ANTENNAPARTIALMETALAREA 0.1644 LAYER met3  ;
    ANTENNAPARTIALMETALSIDEAREA 0.872 LAYER met3  ;
    PORT
      LAYER met3 ;
        RECT 2826.360000 154.240000 2827.160000 154.540000 ;
    END
  END io_oeb[0]
  PIN irq[2]
    DIRECTION OUTPUT ;
    USE SIGNAL ;
    PORT
      LAYER met2 ;
        RECT 2826.860000 0.000000 2827.000000 0.485000 ;
    END
  END irq[2]
  PIN irq[1]
    DIRECTION OUTPUT ;
    USE SIGNAL ;
    PORT
      LAYER met2 ;
        RECT 2821.340000 0.000000 2821.480000 0.485000 ;
    END
  END irq[1]
  PIN irq[0]
    DIRECTION OUTPUT ;
    USE SIGNAL ;
    PORT
      LAYER met2 ;
        RECT 2815.820000 0.000000 2815.960000 0.485000 ;
    END
  END irq[0]
  PIN VSS
    DIRECTION INOUT ;
    USE GROUND ;
    PORT
      LAYER met4 ;
        RECT 2814.960000 3369.060000 2823.120000 3377.220000 ;
    END
    PORT
      LAYER met4 ;
        RECT 2814.960000 0.000000 2823.120000 8.160000 ;
    END
    PORT
      LAYER met4 ;
        RECT 4.040000 3369.060000 12.200000 3377.220000 ;
    END
    PORT
      LAYER met4 ;
        RECT 4.040000 0.000000 12.200000 8.160000 ;
    END
    PORT
      LAYER met5 ;
        RECT 2819.000000 3363.280000 2827.160000 3371.440000 ;
    END
    PORT
      LAYER met5 ;
        RECT 0.000000 3363.280000 8.160000 3371.440000 ;
    END
    PORT
      LAYER met5 ;
        RECT 2819.000000 4.080000 2827.160000 12.240000 ;
    END
    PORT
      LAYER met5 ;
        RECT 0.000000 4.080000 8.160000 12.240000 ;
    END

# P/G power stripe data as pin
    PORT
      LAYER met4 ;
        RECT 4.040000 0.000000 12.200000 3377.220000 ;
        RECT 40.800000 4.080000 44.160000 3371.440000 ;
        RECT 68.000000 4.080000 71.360000 3371.440000 ;
        RECT 95.200000 4.080000 98.560000 3371.440000 ;
        RECT 965.600000 347.125000 968.960000 3371.440000 ;
        RECT 911.200000 347.525000 914.560000 3371.440000 ;
        RECT 938.400000 347.205000 941.760000 3371.440000 ;
        RECT 992.800000 4.080000 996.160000 3371.440000 ;
        RECT 1020.000000 4.080000 1023.360000 3371.440000 ;
        RECT 1047.200000 4.080000 1050.560000 3371.440000 ;
        RECT 1074.400000 4.080000 1077.760000 3371.440000 ;
        RECT 1101.600000 4.080000 1104.960000 3371.440000 ;
        RECT 1128.800000 4.080000 1132.160000 3371.440000 ;
        RECT 1156.000000 4.080000 1159.360000 3371.440000 ;
        RECT 1183.200000 4.080000 1186.560000 3371.440000 ;
        RECT 1210.400000 4.080000 1213.760000 3371.440000 ;
        RECT 1237.600000 4.080000 1240.960000 3371.440000 ;
        RECT 1264.800000 4.080000 1268.160000 3371.440000 ;
        RECT 1292.000000 4.080000 1295.360000 3371.440000 ;
        RECT 1319.200000 4.080000 1322.560000 3371.440000 ;
        RECT 1346.400000 4.080000 1349.760000 3371.440000 ;
        RECT 1373.600000 4.080000 1376.960000 3371.440000 ;
        RECT 1400.800000 4.080000 1404.160000 3371.440000 ;
        RECT 1618.400000 4.080000 1621.760000 3371.440000 ;
        RECT 1591.200000 4.080000 1594.560000 3371.440000 ;
        RECT 1564.000000 4.080000 1567.360000 3371.440000 ;
        RECT 1536.800000 4.080000 1540.160000 3371.440000 ;
        RECT 1509.600000 4.080000 1512.960000 3371.440000 ;
        RECT 1428.000000 4.080000 1431.360000 3371.440000 ;
        RECT 1455.200000 4.080000 1458.560000 3371.440000 ;
        RECT 1482.400000 4.080000 1485.760000 3371.440000 ;
        RECT 1781.600000 4.080000 1784.960000 3371.440000 ;
        RECT 1754.400000 4.080000 1757.760000 3371.440000 ;
        RECT 1727.200000 4.080000 1730.560000 3371.440000 ;
        RECT 1700.000000 4.080000 1703.360000 3371.440000 ;
        RECT 1672.800000 4.080000 1676.160000 3371.440000 ;
        RECT 1645.600000 4.080000 1648.960000 3371.440000 ;
        RECT 1808.800000 448.765000 1812.160000 3371.440000 ;
        RECT 2026.400000 448.765000 2029.760000 3371.440000 ;
        RECT 1999.200000 448.765000 2002.560000 3371.440000 ;
        RECT 1972.000000 448.765000 1975.360000 3371.440000 ;
        RECT 1944.800000 448.765000 1948.160000 3371.440000 ;
        RECT 1917.600000 448.765000 1920.960000 3371.440000 ;
        RECT 1890.400000 448.765000 1893.760000 3371.440000 ;
        RECT 1863.200000 448.765000 1866.560000 3371.440000 ;
        RECT 1836.000000 448.765000 1839.360000 3371.440000 ;
        RECT 2216.800000 4.080000 2220.160000 3371.440000 ;
        RECT 2189.600000 4.080000 2192.960000 3371.440000 ;
        RECT 2162.400000 4.080000 2165.760000 3371.440000 ;
        RECT 2135.200000 448.765000 2138.560000 3371.440000 ;
        RECT 2108.000000 448.765000 2111.360000 3371.440000 ;
        RECT 2080.800000 448.765000 2084.160000 3371.440000 ;
        RECT 2053.600000 448.765000 2056.960000 3371.440000 ;
        RECT 2244.000000 4.080000 2247.360000 3371.440000 ;
        RECT 2679.200000 4.080000 2682.560000 3371.440000 ;
        RECT 2298.400000 4.080000 2301.760000 3371.440000 ;
        RECT 2271.200000 4.080000 2274.560000 3371.440000 ;
        RECT 2461.600000 347.205000 2464.960000 3371.440000 ;
        RECT 2434.400000 347.205000 2437.760000 3371.440000 ;
        RECT 2407.200000 347.205000 2410.560000 3371.440000 ;
        RECT 2380.000000 347.205000 2383.360000 3371.440000 ;
        RECT 2352.800000 347.205000 2356.160000 3371.440000 ;
        RECT 2325.600000 347.205000 2328.960000 3371.440000 ;
        RECT 2652.000000 347.205000 2655.360000 3371.440000 ;
        RECT 2624.800000 347.205000 2628.160000 3371.440000 ;
        RECT 2597.600000 347.205000 2600.960000 3371.440000 ;
        RECT 2570.400000 347.205000 2573.760000 3371.440000 ;
        RECT 2543.200000 347.205000 2546.560000 3371.440000 ;
        RECT 2516.000000 347.205000 2519.360000 3371.440000 ;
        RECT 2488.800000 347.205000 2492.160000 3371.440000 ;
        RECT 2814.960000 0.000000 2823.120000 3377.220000 ;
        RECT 2706.400000 4.080000 2709.760000 3371.440000 ;
        RECT 2733.600000 4.080000 2736.960000 3371.440000 ;
        RECT 2760.800000 4.080000 2764.160000 3371.440000 ;
        RECT 2788.000000 4.080000 2791.360000 3371.440000 ;
        RECT 122.400000 448.765000 125.760000 1635.875000 ;
        RECT 149.600000 448.765000 152.960000 1635.875000 ;
        RECT 176.800000 448.765000 180.160000 1635.875000 ;
        RECT 204.000000 448.765000 207.360000 1635.875000 ;
        RECT 231.200000 448.765000 234.560000 1635.875000 ;
        RECT 258.400000 448.765000 261.760000 1635.875000 ;
        RECT 285.600000 448.765000 288.960000 1635.875000 ;
        RECT 312.800000 448.765000 316.160000 1635.875000 ;
        RECT 340.000000 448.765000 343.360000 1635.875000 ;
        RECT 367.200000 448.765000 370.560000 1635.875000 ;
        RECT 394.400000 448.765000 397.760000 1635.875000 ;
        RECT 421.600000 448.765000 424.960000 1635.875000 ;
        RECT 448.800000 448.765000 452.160000 1635.875000 ;
        RECT 476.000000 4.080000 479.360000 1635.875000 ;
        RECT 503.200000 4.080000 506.560000 1635.875000 ;
        RECT 530.400000 4.080000 533.760000 1635.875000 ;
        RECT 557.600000 4.080000 560.960000 1635.875000 ;
        RECT 775.200000 347.205000 778.560000 1635.475000 ;
        RECT 639.200000 347.205000 642.560000 1635.875000 ;
        RECT 666.400000 347.205000 669.760000 1635.875000 ;
        RECT 693.600000 347.205000 696.960000 1635.875000 ;
        RECT 720.800000 347.205000 724.160000 1635.875000 ;
        RECT 748.000000 347.205000 751.360000 1635.875000 ;
        RECT 612.000000 347.125000 615.360000 1635.875000 ;
        RECT 584.800000 4.080000 588.160000 1635.875000 ;
        RECT 802.400000 347.205000 805.760000 1635.875000 ;
        RECT 829.600000 347.205000 832.960000 1635.875000 ;
        RECT 856.800000 347.205000 860.160000 1635.875000 ;
        RECT 884.000000 347.205000 887.360000 1635.875000 ;
        RECT 122.400000 191.205000 125.760000 246.875000 ;
        RECT 122.400000 4.080000 125.760000 90.875000 ;
        RECT 122.400000 347.205000 125.760000 421.875000 ;
        RECT 448.800000 191.205000 452.160000 246.875000 ;
        RECT 421.600000 191.205000 424.960000 246.875000 ;
        RECT 394.400000 191.205000 397.760000 246.875000 ;
        RECT 367.200000 191.205000 370.560000 246.875000 ;
        RECT 340.000000 191.205000 343.360000 246.875000 ;
        RECT 312.800000 191.205000 316.160000 246.875000 ;
        RECT 285.600000 191.205000 288.960000 246.875000 ;
        RECT 258.400000 191.205000 261.760000 246.875000 ;
        RECT 231.200000 191.205000 234.560000 246.875000 ;
        RECT 204.000000 191.205000 207.360000 246.875000 ;
        RECT 176.800000 191.205000 180.160000 246.875000 ;
        RECT 149.600000 191.205000 152.960000 246.875000 ;
        RECT 204.000000 4.080000 207.360000 90.875000 ;
        RECT 176.800000 4.080000 180.160000 90.875000 ;
        RECT 149.600000 4.080000 152.960000 90.875000 ;
        RECT 231.200000 4.080000 234.560000 90.875000 ;
        RECT 285.600000 4.080000 288.960000 90.875000 ;
        RECT 258.400000 4.080000 261.760000 90.875000 ;
        RECT 312.800000 4.080000 316.160000 90.875000 ;
        RECT 340.000000 4.080000 343.360000 90.875000 ;
        RECT 367.200000 4.080000 370.560000 90.875000 ;
        RECT 394.400000 4.080000 397.760000 90.875000 ;
        RECT 421.600000 4.080000 424.960000 90.875000 ;
        RECT 448.800000 4.080000 452.160000 90.875000 ;
        RECT 231.200000 347.205000 234.560000 421.875000 ;
        RECT 176.800000 347.205000 180.160000 421.875000 ;
        RECT 149.600000 347.205000 152.960000 421.875000 ;
        RECT 204.000000 347.205000 207.360000 421.875000 ;
        RECT 340.000000 347.205000 343.360000 421.875000 ;
        RECT 312.800000 347.205000 316.160000 421.875000 ;
        RECT 285.600000 347.205000 288.960000 421.875000 ;
        RECT 258.400000 347.205000 261.760000 421.875000 ;
        RECT 448.800000 347.205000 452.160000 421.875000 ;
        RECT 421.600000 347.205000 424.960000 421.875000 ;
        RECT 394.400000 347.205000 397.760000 421.875000 ;
        RECT 367.200000 347.205000 370.560000 421.875000 ;
        RECT 965.600000 191.125000 968.960000 246.955000 ;
        RECT 612.000000 191.125000 615.360000 246.955000 ;
        RECT 938.400000 191.205000 941.760000 246.875000 ;
        RECT 884.000000 191.205000 887.360000 246.875000 ;
        RECT 856.800000 191.205000 860.160000 246.875000 ;
        RECT 829.600000 191.205000 832.960000 246.875000 ;
        RECT 802.400000 191.205000 805.760000 246.875000 ;
        RECT 775.200000 191.205000 778.560000 246.875000 ;
        RECT 748.000000 191.205000 751.360000 246.875000 ;
        RECT 720.800000 191.205000 724.160000 246.875000 ;
        RECT 693.600000 191.205000 696.960000 246.875000 ;
        RECT 666.400000 191.205000 669.760000 246.875000 ;
        RECT 639.200000 191.205000 642.560000 246.875000 ;
        RECT 911.200000 191.525000 914.560000 246.555000 ;
        RECT 612.000000 4.080000 615.360000 90.955000 ;
        RECT 666.400000 4.080000 669.760000 90.875000 ;
        RECT 639.200000 4.080000 642.560000 90.875000 ;
        RECT 775.200000 4.080000 778.560000 90.875000 ;
        RECT 748.000000 4.080000 751.360000 90.875000 ;
        RECT 720.800000 4.080000 724.160000 90.875000 ;
        RECT 693.600000 4.080000 696.960000 90.875000 ;
        RECT 884.000000 4.080000 887.360000 90.875000 ;
        RECT 856.800000 4.080000 860.160000 90.875000 ;
        RECT 829.600000 4.080000 832.960000 90.875000 ;
        RECT 802.400000 4.080000 805.760000 90.875000 ;
        RECT 965.600000 4.080000 968.960000 90.955000 ;
        RECT 938.400000 4.080000 941.760000 90.875000 ;
        RECT 911.200000 4.080000 914.560000 90.555000 ;
        RECT 1808.800000 191.205000 1812.160000 246.875000 ;
        RECT 1808.800000 4.080000 1812.160000 90.875000 ;
        RECT 1808.800000 347.205000 1812.160000 421.875000 ;
        RECT 2135.200000 191.205000 2138.560000 246.875000 ;
        RECT 2108.000000 191.205000 2111.360000 246.875000 ;
        RECT 2080.800000 191.205000 2084.160000 246.875000 ;
        RECT 2053.600000 191.205000 2056.960000 246.875000 ;
        RECT 2026.400000 191.205000 2029.760000 246.875000 ;
        RECT 1999.200000 191.205000 2002.560000 246.875000 ;
        RECT 1972.000000 191.205000 1975.360000 246.875000 ;
        RECT 1944.800000 191.205000 1948.160000 246.875000 ;
        RECT 1917.600000 191.205000 1920.960000 246.875000 ;
        RECT 1890.400000 191.205000 1893.760000 246.875000 ;
        RECT 1863.200000 191.205000 1866.560000 246.875000 ;
        RECT 1836.000000 191.205000 1839.360000 246.875000 ;
        RECT 1890.400000 4.080000 1893.760000 90.875000 ;
        RECT 1863.200000 4.080000 1866.560000 90.875000 ;
        RECT 1836.000000 4.080000 1839.360000 90.875000 ;
        RECT 1917.600000 4.080000 1920.960000 90.875000 ;
        RECT 1972.000000 4.080000 1975.360000 90.875000 ;
        RECT 1944.800000 4.080000 1948.160000 90.875000 ;
        RECT 1999.200000 4.080000 2002.560000 90.875000 ;
        RECT 2026.400000 4.080000 2029.760000 90.875000 ;
        RECT 2053.600000 4.080000 2056.960000 90.875000 ;
        RECT 2080.800000 4.080000 2084.160000 90.875000 ;
        RECT 2108.000000 4.080000 2111.360000 90.875000 ;
        RECT 2135.200000 4.080000 2138.560000 90.875000 ;
        RECT 1890.400000 347.205000 1893.760000 421.875000 ;
        RECT 1863.200000 347.205000 1866.560000 421.875000 ;
        RECT 1836.000000 347.205000 1839.360000 421.875000 ;
        RECT 1917.600000 347.205000 1920.960000 421.875000 ;
        RECT 2026.400000 347.205000 2029.760000 421.875000 ;
        RECT 1999.200000 347.205000 2002.560000 421.875000 ;
        RECT 1972.000000 347.205000 1975.360000 421.875000 ;
        RECT 1944.800000 347.205000 1948.160000 421.875000 ;
        RECT 2135.200000 347.205000 2138.560000 421.875000 ;
        RECT 2108.000000 347.205000 2111.360000 421.875000 ;
        RECT 2080.800000 347.205000 2084.160000 421.875000 ;
        RECT 2053.600000 347.205000 2056.960000 421.875000 ;
        RECT 2652.000000 191.205000 2655.360000 246.875000 ;
        RECT 2624.800000 191.205000 2628.160000 246.875000 ;
        RECT 2597.600000 191.205000 2600.960000 246.875000 ;
        RECT 2570.400000 191.205000 2573.760000 246.875000 ;
        RECT 2543.200000 191.205000 2546.560000 246.875000 ;
        RECT 2516.000000 191.205000 2519.360000 246.875000 ;
        RECT 2488.800000 191.205000 2492.160000 246.875000 ;
        RECT 2461.600000 191.205000 2464.960000 246.875000 ;
        RECT 2434.400000 191.205000 2437.760000 246.875000 ;
        RECT 2407.200000 191.205000 2410.560000 246.875000 ;
        RECT 2380.000000 191.205000 2383.360000 246.875000 ;
        RECT 2352.800000 191.205000 2356.160000 246.875000 ;
        RECT 2325.600000 191.205000 2328.960000 246.875000 ;
        RECT 2352.800000 4.080000 2356.160000 90.875000 ;
        RECT 2325.600000 4.080000 2328.960000 90.875000 ;
        RECT 2461.600000 4.080000 2464.960000 90.875000 ;
        RECT 2434.400000 4.080000 2437.760000 90.875000 ;
        RECT 2407.200000 4.080000 2410.560000 90.875000 ;
        RECT 2380.000000 4.080000 2383.360000 90.875000 ;
        RECT 2570.400000 4.080000 2573.760000 90.875000 ;
        RECT 2543.200000 4.080000 2546.560000 90.875000 ;
        RECT 2516.000000 4.080000 2519.360000 90.875000 ;
        RECT 2488.800000 4.080000 2492.160000 90.875000 ;
        RECT 2652.000000 4.080000 2655.360000 90.875000 ;
        RECT 2624.800000 4.080000 2628.160000 90.875000 ;
        RECT 2597.600000 4.080000 2600.960000 90.875000 ;
        RECT 122.400000 2424.365000 125.760000 2510.875000 ;
        RECT 149.600000 2424.365000 152.960000 2510.875000 ;
        RECT 176.800000 2424.365000 180.160000 2510.875000 ;
        RECT 204.000000 2424.365000 207.360000 2510.875000 ;
        RECT 231.200000 2424.365000 234.560000 2510.875000 ;
        RECT 258.400000 2424.365000 261.760000 2510.875000 ;
        RECT 285.600000 2424.365000 288.960000 2510.875000 ;
        RECT 312.800000 2424.365000 316.160000 2510.875000 ;
        RECT 340.000000 2424.365000 343.360000 2510.875000 ;
        RECT 367.200000 2424.365000 370.560000 2510.875000 ;
        RECT 394.400000 2424.365000 397.760000 2510.875000 ;
        RECT 421.600000 2424.365000 424.960000 2510.875000 ;
        RECT 448.800000 2424.365000 452.160000 2510.875000 ;
        RECT 476.000000 2424.365000 479.360000 2510.875000 ;
        RECT 503.200000 2424.365000 506.560000 2510.875000 ;
        RECT 530.400000 2424.365000 533.760000 2510.875000 ;
        RECT 557.600000 2424.365000 560.960000 2510.875000 ;
        RECT 775.200000 2424.765000 778.560000 2510.475000 ;
        RECT 584.800000 2424.365000 588.160000 2510.875000 ;
        RECT 612.000000 2424.365000 615.360000 2510.875000 ;
        RECT 639.200000 2424.365000 642.560000 2510.875000 ;
        RECT 666.400000 2424.365000 669.760000 2510.875000 ;
        RECT 693.600000 2424.365000 696.960000 2510.875000 ;
        RECT 720.800000 2424.365000 724.160000 2510.875000 ;
        RECT 748.000000 2424.365000 751.360000 2510.875000 ;
        RECT 802.400000 2424.365000 805.760000 2510.875000 ;
        RECT 829.600000 2424.365000 832.960000 2510.875000 ;
        RECT 856.800000 2424.365000 860.160000 2510.875000 ;
        RECT 884.000000 2424.365000 887.360000 2510.875000 ;
        RECT 122.400000 3299.365000 125.760000 3371.440000 ;
        RECT 231.200000 3299.365000 234.560000 3371.440000 ;
        RECT 204.000000 3299.365000 207.360000 3371.440000 ;
        RECT 176.800000 3299.365000 180.160000 3371.440000 ;
        RECT 149.600000 3299.365000 152.960000 3371.440000 ;
        RECT 340.000000 3299.365000 343.360000 3371.440000 ;
        RECT 312.800000 3299.365000 316.160000 3371.440000 ;
        RECT 285.600000 3299.365000 288.960000 3371.440000 ;
        RECT 258.400000 3299.365000 261.760000 3371.440000 ;
        RECT 448.800000 3299.365000 452.160000 3371.440000 ;
        RECT 421.600000 3299.365000 424.960000 3371.440000 ;
        RECT 394.400000 3299.365000 397.760000 3371.440000 ;
        RECT 367.200000 3299.365000 370.560000 3371.440000 ;
        RECT 557.600000 3299.365000 560.960000 3371.440000 ;
        RECT 530.400000 3299.365000 533.760000 3371.440000 ;
        RECT 503.200000 3299.365000 506.560000 3371.440000 ;
        RECT 476.000000 3299.365000 479.360000 3371.440000 ;
        RECT 666.400000 3299.365000 669.760000 3371.440000 ;
        RECT 639.200000 3299.365000 642.560000 3371.440000 ;
        RECT 612.000000 3299.365000 615.360000 3371.440000 ;
        RECT 584.800000 3299.365000 588.160000 3371.440000 ;
        RECT 748.000000 3299.365000 751.360000 3371.440000 ;
        RECT 720.800000 3299.365000 724.160000 3371.440000 ;
        RECT 693.600000 3299.365000 696.960000 3371.440000 ;
        RECT 775.200000 3299.765000 778.560000 3371.440000 ;
        RECT 884.000000 3299.365000 887.360000 3371.440000 ;
        RECT 856.800000 3299.365000 860.160000 3371.440000 ;
        RECT 829.600000 3299.365000 832.960000 3371.440000 ;
        RECT 802.400000 3299.365000 805.760000 3371.440000 ;
        RECT 448.800000 421.600000 452.160000 423.020000 ;
        RECT 421.600000 421.600000 424.960000 423.020000 ;
        RECT 394.400000 421.600000 397.760000 423.020000 ;
        RECT 367.200000 421.600000 370.560000 423.020000 ;
        RECT 340.000000 421.600000 343.360000 423.020000 ;
        RECT 312.800000 421.600000 316.160000 423.020000 ;
        RECT 285.600000 421.600000 288.960000 423.020000 ;
        RECT 258.400000 421.600000 261.760000 423.020000 ;
        RECT 231.200000 421.600000 234.560000 423.020000 ;
        RECT 204.000000 421.600000 207.360000 423.020000 ;
        RECT 176.800000 421.600000 180.160000 423.020000 ;
        RECT 149.600000 421.600000 152.960000 423.020000 ;
        RECT 122.400000 421.600000 125.760000 423.020000 ;
        RECT 133.560000 95.200000 135.160000 98.560000 ;
        RECT 133.560000 149.600000 135.160000 152.960000 ;
        RECT 133.560000 122.400000 135.160000 125.760000 ;
        RECT 133.560000 176.800000 135.160000 180.160000 ;
        RECT 133.560000 258.400000 135.160000 261.760000 ;
        RECT 133.560000 312.800000 135.160000 316.160000 ;
        RECT 133.560000 285.600000 135.160000 288.960000 ;
        RECT 133.560000 340.000000 135.160000 343.360000 ;
        RECT 183.560000 95.200000 185.160000 98.560000 ;
        RECT 233.560000 95.200000 235.160000 98.560000 ;
        RECT 283.560000 95.200000 285.160000 98.560000 ;
        RECT 333.560000 95.200000 335.160000 98.560000 ;
        RECT 183.560000 122.400000 185.160000 125.760000 ;
        RECT 183.560000 149.600000 185.160000 152.960000 ;
        RECT 183.560000 176.800000 185.160000 180.160000 ;
        RECT 233.560000 122.400000 235.160000 125.760000 ;
        RECT 233.560000 149.600000 235.160000 152.960000 ;
        RECT 233.560000 176.800000 235.160000 180.160000 ;
        RECT 283.560000 122.400000 285.160000 125.760000 ;
        RECT 283.560000 149.600000 285.160000 152.960000 ;
        RECT 283.560000 176.800000 285.160000 180.160000 ;
        RECT 333.560000 122.400000 335.160000 125.760000 ;
        RECT 333.560000 149.600000 335.160000 152.960000 ;
        RECT 333.560000 176.800000 335.160000 180.160000 ;
        RECT 383.560000 95.200000 385.160000 98.560000 ;
        RECT 433.560000 95.200000 435.160000 98.560000 ;
        RECT 433.560000 176.800000 435.160000 180.160000 ;
        RECT 433.560000 149.600000 435.160000 152.960000 ;
        RECT 433.560000 122.400000 435.160000 125.760000 ;
        RECT 383.560000 176.800000 385.160000 180.160000 ;
        RECT 383.560000 149.600000 385.160000 152.960000 ;
        RECT 383.560000 122.400000 385.160000 125.760000 ;
        RECT 183.560000 258.400000 185.160000 261.760000 ;
        RECT 233.560000 258.400000 235.160000 261.760000 ;
        RECT 233.560000 312.800000 235.160000 316.160000 ;
        RECT 233.560000 285.600000 235.160000 288.960000 ;
        RECT 183.560000 312.800000 185.160000 316.160000 ;
        RECT 183.560000 285.600000 185.160000 288.960000 ;
        RECT 283.560000 258.400000 285.160000 261.760000 ;
        RECT 333.560000 258.400000 335.160000 261.760000 ;
        RECT 333.560000 312.800000 335.160000 316.160000 ;
        RECT 333.560000 285.600000 335.160000 288.960000 ;
        RECT 283.560000 312.800000 285.160000 316.160000 ;
        RECT 283.560000 285.600000 285.160000 288.960000 ;
        RECT 233.560000 340.000000 235.160000 343.360000 ;
        RECT 183.560000 340.000000 185.160000 343.360000 ;
        RECT 333.560000 340.000000 335.160000 343.360000 ;
        RECT 283.560000 340.000000 285.160000 343.360000 ;
        RECT 383.560000 258.400000 385.160000 261.760000 ;
        RECT 433.560000 258.400000 435.160000 261.760000 ;
        RECT 433.560000 312.800000 435.160000 316.160000 ;
        RECT 433.560000 285.600000 435.160000 288.960000 ;
        RECT 383.560000 312.800000 385.160000 316.160000 ;
        RECT 383.560000 285.600000 385.160000 288.960000 ;
        RECT 433.560000 340.000000 435.160000 343.360000 ;
        RECT 383.560000 340.000000 385.160000 343.360000 ;
        RECT 126.560000 423.950000 128.160000 425.370000 ;
        RECT 176.560000 423.950000 178.160000 425.370000 ;
        RECT 226.560000 423.950000 228.160000 425.370000 ;
        RECT 276.560000 423.950000 278.160000 425.370000 ;
        RECT 326.560000 423.950000 328.160000 425.370000 ;
        RECT 376.560000 423.950000 378.160000 425.370000 ;
        RECT 426.560000 423.950000 428.160000 425.370000 ;
        RECT 639.560000 95.200000 641.160000 98.560000 ;
        RECT 689.560000 95.200000 691.160000 98.560000 ;
        RECT 739.560000 95.200000 741.160000 98.560000 ;
        RECT 639.560000 122.400000 641.160000 125.760000 ;
        RECT 639.560000 149.600000 641.160000 152.960000 ;
        RECT 639.560000 176.800000 641.160000 180.160000 ;
        RECT 689.560000 122.400000 691.160000 125.760000 ;
        RECT 689.560000 149.600000 691.160000 152.960000 ;
        RECT 689.560000 176.800000 691.160000 180.160000 ;
        RECT 739.560000 122.400000 741.160000 125.760000 ;
        RECT 739.560000 149.600000 741.160000 152.960000 ;
        RECT 739.560000 176.800000 741.160000 180.160000 ;
        RECT 789.560000 95.200000 791.160000 98.560000 ;
        RECT 839.560000 95.200000 841.160000 98.560000 ;
        RECT 889.560000 95.200000 891.160000 98.560000 ;
        RECT 939.560000 95.200000 941.160000 98.560000 ;
        RECT 789.560000 122.400000 791.160000 125.760000 ;
        RECT 789.560000 149.600000 791.160000 152.960000 ;
        RECT 789.560000 176.800000 791.160000 180.160000 ;
        RECT 839.560000 122.400000 841.160000 125.760000 ;
        RECT 839.560000 149.600000 841.160000 152.960000 ;
        RECT 839.560000 176.800000 841.160000 180.160000 ;
        RECT 889.560000 122.400000 891.160000 125.760000 ;
        RECT 889.560000 149.600000 891.160000 152.960000 ;
        RECT 889.560000 176.800000 891.160000 180.160000 ;
        RECT 939.560000 122.400000 941.160000 125.760000 ;
        RECT 939.560000 149.600000 941.160000 152.960000 ;
        RECT 939.560000 176.800000 941.160000 180.160000 ;
        RECT 639.560000 258.400000 641.160000 261.760000 ;
        RECT 639.560000 312.800000 641.160000 316.160000 ;
        RECT 639.560000 285.600000 641.160000 288.960000 ;
        RECT 689.560000 258.400000 691.160000 261.760000 ;
        RECT 739.560000 258.400000 741.160000 261.760000 ;
        RECT 739.560000 312.800000 741.160000 316.160000 ;
        RECT 739.560000 285.600000 741.160000 288.960000 ;
        RECT 689.560000 312.800000 691.160000 316.160000 ;
        RECT 689.560000 285.600000 691.160000 288.960000 ;
        RECT 639.560000 340.000000 641.160000 343.360000 ;
        RECT 739.560000 340.000000 741.160000 343.360000 ;
        RECT 689.560000 340.000000 691.160000 343.360000 ;
        RECT 789.560000 258.400000 791.160000 261.760000 ;
        RECT 839.560000 258.400000 841.160000 261.760000 ;
        RECT 789.560000 285.600000 791.160000 288.960000 ;
        RECT 789.560000 312.800000 791.160000 316.160000 ;
        RECT 839.560000 285.600000 841.160000 288.960000 ;
        RECT 839.560000 312.800000 841.160000 316.160000 ;
        RECT 889.560000 258.400000 891.160000 261.760000 ;
        RECT 939.560000 258.400000 941.160000 261.760000 ;
        RECT 889.560000 285.600000 891.160000 288.960000 ;
        RECT 889.560000 312.800000 891.160000 316.160000 ;
        RECT 939.560000 285.600000 941.160000 288.960000 ;
        RECT 939.560000 312.800000 941.160000 316.160000 ;
        RECT 839.560000 340.000000 841.160000 343.360000 ;
        RECT 789.560000 340.000000 791.160000 343.360000 ;
        RECT 939.560000 340.000000 941.160000 343.360000 ;
        RECT 889.560000 340.000000 891.160000 343.360000 ;
        RECT 126.560000 1672.800000 128.160000 1676.160000 ;
        RECT 126.560000 1645.600000 128.160000 1648.960000 ;
        RECT 226.560000 1672.800000 228.160000 1676.160000 ;
        RECT 226.560000 1645.600000 228.160000 1648.960000 ;
        RECT 176.560000 1672.800000 178.160000 1676.160000 ;
        RECT 176.560000 1645.600000 178.160000 1648.960000 ;
        RECT 326.560000 1672.800000 328.160000 1676.160000 ;
        RECT 326.560000 1645.600000 328.160000 1648.960000 ;
        RECT 276.560000 1672.800000 278.160000 1676.160000 ;
        RECT 276.560000 1645.600000 278.160000 1648.960000 ;
        RECT 426.560000 1672.800000 428.160000 1676.160000 ;
        RECT 426.560000 1645.600000 428.160000 1648.960000 ;
        RECT 376.560000 1672.800000 378.160000 1676.160000 ;
        RECT 376.560000 1645.600000 378.160000 1648.960000 ;
        RECT 526.560000 1672.800000 528.160000 1676.160000 ;
        RECT 526.560000 1645.600000 528.160000 1648.960000 ;
        RECT 476.560000 1672.800000 478.160000 1676.160000 ;
        RECT 476.560000 1645.600000 478.160000 1648.960000 ;
        RECT 626.560000 1672.800000 628.160000 1676.160000 ;
        RECT 626.560000 1645.600000 628.160000 1648.960000 ;
        RECT 576.560000 1672.800000 578.160000 1676.160000 ;
        RECT 576.560000 1645.600000 578.160000 1648.960000 ;
        RECT 776.560000 1672.800000 778.160000 1676.160000 ;
        RECT 776.560000 1645.600000 778.160000 1648.960000 ;
        RECT 726.560000 1672.800000 728.160000 1676.160000 ;
        RECT 726.560000 1645.600000 728.160000 1648.960000 ;
        RECT 676.560000 1672.800000 678.160000 1676.160000 ;
        RECT 676.560000 1645.600000 678.160000 1648.960000 ;
        RECT 876.560000 1672.800000 878.160000 1676.160000 ;
        RECT 876.560000 1645.600000 878.160000 1648.960000 ;
        RECT 826.560000 1672.800000 828.160000 1676.160000 ;
        RECT 826.560000 1645.600000 828.160000 1648.960000 ;
        RECT 1808.800000 421.600000 1812.160000 423.020000 ;
        RECT 2135.200000 421.600000 2138.560000 423.020000 ;
        RECT 1836.000000 421.600000 1839.360000 423.020000 ;
        RECT 1863.200000 421.600000 1866.560000 423.020000 ;
        RECT 1890.400000 421.600000 1893.760000 423.020000 ;
        RECT 1917.600000 421.600000 1920.960000 423.020000 ;
        RECT 1944.800000 421.600000 1948.160000 423.020000 ;
        RECT 1972.000000 421.600000 1975.360000 423.020000 ;
        RECT 1999.200000 421.600000 2002.560000 423.020000 ;
        RECT 2026.400000 421.600000 2029.760000 423.020000 ;
        RECT 2053.600000 421.600000 2056.960000 423.020000 ;
        RECT 2080.800000 421.600000 2084.160000 423.020000 ;
        RECT 2108.000000 421.600000 2111.360000 423.020000 ;
        RECT 1824.560000 95.200000 1826.160000 98.560000 ;
        RECT 1824.560000 149.600000 1826.160000 152.960000 ;
        RECT 1824.560000 122.400000 1826.160000 125.760000 ;
        RECT 1824.560000 176.800000 1826.160000 180.160000 ;
        RECT 1824.560000 258.400000 1826.160000 261.760000 ;
        RECT 1824.560000 312.800000 1826.160000 316.160000 ;
        RECT 1824.560000 285.600000 1826.160000 288.960000 ;
        RECT 1824.560000 340.000000 1826.160000 343.360000 ;
        RECT 1874.560000 95.200000 1876.160000 98.560000 ;
        RECT 1924.560000 95.200000 1926.160000 98.560000 ;
        RECT 1974.560000 95.200000 1976.160000 98.560000 ;
        RECT 2024.560000 95.200000 2026.160000 98.560000 ;
        RECT 1874.560000 122.400000 1876.160000 125.760000 ;
        RECT 1874.560000 149.600000 1876.160000 152.960000 ;
        RECT 1874.560000 176.800000 1876.160000 180.160000 ;
        RECT 1924.560000 122.400000 1926.160000 125.760000 ;
        RECT 1924.560000 149.600000 1926.160000 152.960000 ;
        RECT 1924.560000 176.800000 1926.160000 180.160000 ;
        RECT 1974.560000 122.400000 1976.160000 125.760000 ;
        RECT 1974.560000 149.600000 1976.160000 152.960000 ;
        RECT 1974.560000 176.800000 1976.160000 180.160000 ;
        RECT 2024.560000 122.400000 2026.160000 125.760000 ;
        RECT 2024.560000 149.600000 2026.160000 152.960000 ;
        RECT 2024.560000 176.800000 2026.160000 180.160000 ;
        RECT 2074.560000 95.200000 2076.160000 98.560000 ;
        RECT 2124.560000 95.200000 2126.160000 98.560000 ;
        RECT 2124.560000 176.800000 2126.160000 180.160000 ;
        RECT 2124.560000 149.600000 2126.160000 152.960000 ;
        RECT 2124.560000 122.400000 2126.160000 125.760000 ;
        RECT 2074.560000 176.800000 2076.160000 180.160000 ;
        RECT 2074.560000 149.600000 2076.160000 152.960000 ;
        RECT 2074.560000 122.400000 2076.160000 125.760000 ;
        RECT 1874.560000 258.400000 1876.160000 261.760000 ;
        RECT 1924.560000 258.400000 1926.160000 261.760000 ;
        RECT 1924.560000 312.800000 1926.160000 316.160000 ;
        RECT 1924.560000 285.600000 1926.160000 288.960000 ;
        RECT 1874.560000 312.800000 1876.160000 316.160000 ;
        RECT 1874.560000 285.600000 1876.160000 288.960000 ;
        RECT 1974.560000 258.400000 1976.160000 261.760000 ;
        RECT 2024.560000 258.400000 2026.160000 261.760000 ;
        RECT 2024.560000 312.800000 2026.160000 316.160000 ;
        RECT 2024.560000 285.600000 2026.160000 288.960000 ;
        RECT 1974.560000 312.800000 1976.160000 316.160000 ;
        RECT 1974.560000 285.600000 1976.160000 288.960000 ;
        RECT 1924.560000 340.000000 1926.160000 343.360000 ;
        RECT 1874.560000 340.000000 1876.160000 343.360000 ;
        RECT 2024.560000 340.000000 2026.160000 343.360000 ;
        RECT 1974.560000 340.000000 1976.160000 343.360000 ;
        RECT 2074.560000 258.400000 2076.160000 261.760000 ;
        RECT 2124.560000 258.400000 2126.160000 261.760000 ;
        RECT 2124.560000 312.800000 2126.160000 316.160000 ;
        RECT 2124.560000 285.600000 2126.160000 288.960000 ;
        RECT 2074.560000 312.800000 2076.160000 316.160000 ;
        RECT 2074.560000 285.600000 2076.160000 288.960000 ;
        RECT 2124.560000 340.000000 2126.160000 343.360000 ;
        RECT 2074.560000 340.000000 2076.160000 343.360000 ;
        RECT 1824.560000 423.950000 1826.160000 425.370000 ;
        RECT 1874.560000 423.950000 1876.160000 425.370000 ;
        RECT 1924.560000 423.950000 1926.160000 425.370000 ;
        RECT 1974.560000 423.950000 1976.160000 425.370000 ;
        RECT 2024.560000 423.950000 2026.160000 425.370000 ;
        RECT 2074.560000 423.950000 2076.160000 425.370000 ;
        RECT 2124.560000 423.950000 2126.160000 425.370000 ;
        RECT 2330.560000 95.200000 2332.160000 98.560000 ;
        RECT 2380.560000 95.200000 2382.160000 98.560000 ;
        RECT 2430.560000 95.200000 2432.160000 98.560000 ;
        RECT 2330.560000 122.400000 2332.160000 125.760000 ;
        RECT 2330.560000 149.600000 2332.160000 152.960000 ;
        RECT 2330.560000 176.800000 2332.160000 180.160000 ;
        RECT 2380.560000 122.400000 2382.160000 125.760000 ;
        RECT 2380.560000 149.600000 2382.160000 152.960000 ;
        RECT 2380.560000 176.800000 2382.160000 180.160000 ;
        RECT 2430.560000 122.400000 2432.160000 125.760000 ;
        RECT 2430.560000 149.600000 2432.160000 152.960000 ;
        RECT 2430.560000 176.800000 2432.160000 180.160000 ;
        RECT 2480.560000 95.200000 2482.160000 98.560000 ;
        RECT 2530.560000 95.200000 2532.160000 98.560000 ;
        RECT 2580.560000 95.200000 2582.160000 98.560000 ;
        RECT 2630.560000 95.200000 2632.160000 98.560000 ;
        RECT 2480.560000 122.400000 2482.160000 125.760000 ;
        RECT 2480.560000 149.600000 2482.160000 152.960000 ;
        RECT 2480.560000 176.800000 2482.160000 180.160000 ;
        RECT 2530.560000 122.400000 2532.160000 125.760000 ;
        RECT 2530.560000 149.600000 2532.160000 152.960000 ;
        RECT 2530.560000 176.800000 2532.160000 180.160000 ;
        RECT 2580.560000 122.400000 2582.160000 125.760000 ;
        RECT 2580.560000 149.600000 2582.160000 152.960000 ;
        RECT 2580.560000 176.800000 2582.160000 180.160000 ;
        RECT 2630.560000 122.400000 2632.160000 125.760000 ;
        RECT 2630.560000 149.600000 2632.160000 152.960000 ;
        RECT 2630.560000 176.800000 2632.160000 180.160000 ;
        RECT 2330.560000 258.400000 2332.160000 261.760000 ;
        RECT 2330.560000 312.800000 2332.160000 316.160000 ;
        RECT 2330.560000 285.600000 2332.160000 288.960000 ;
        RECT 2380.560000 258.400000 2382.160000 261.760000 ;
        RECT 2430.560000 258.400000 2432.160000 261.760000 ;
        RECT 2430.560000 312.800000 2432.160000 316.160000 ;
        RECT 2430.560000 285.600000 2432.160000 288.960000 ;
        RECT 2380.560000 312.800000 2382.160000 316.160000 ;
        RECT 2380.560000 285.600000 2382.160000 288.960000 ;
        RECT 2330.560000 340.000000 2332.160000 343.360000 ;
        RECT 2430.560000 340.000000 2432.160000 343.360000 ;
        RECT 2380.560000 340.000000 2382.160000 343.360000 ;
        RECT 2480.560000 258.400000 2482.160000 261.760000 ;
        RECT 2530.560000 258.400000 2532.160000 261.760000 ;
        RECT 2530.560000 312.800000 2532.160000 316.160000 ;
        RECT 2530.560000 285.600000 2532.160000 288.960000 ;
        RECT 2480.560000 312.800000 2482.160000 316.160000 ;
        RECT 2480.560000 285.600000 2482.160000 288.960000 ;
        RECT 2580.560000 258.400000 2582.160000 261.760000 ;
        RECT 2630.560000 258.400000 2632.160000 261.760000 ;
        RECT 2580.560000 285.600000 2582.160000 288.960000 ;
        RECT 2580.560000 312.800000 2582.160000 316.160000 ;
        RECT 2630.560000 285.600000 2632.160000 288.960000 ;
        RECT 2630.560000 312.800000 2632.160000 316.160000 ;
        RECT 2530.560000 340.000000 2532.160000 343.360000 ;
        RECT 2480.560000 340.000000 2482.160000 343.360000 ;
        RECT 2630.560000 340.000000 2632.160000 343.360000 ;
        RECT 2580.560000 340.000000 2582.160000 343.360000 ;
        RECT 526.560000 2108.000000 528.160000 2111.360000 ;
        RECT 476.560000 2108.000000 478.160000 2111.360000 ;
        RECT 426.560000 2108.000000 428.160000 2111.360000 ;
        RECT 376.560000 2108.000000 378.160000 2111.360000 ;
        RECT 326.560000 2108.000000 328.160000 2111.360000 ;
        RECT 276.560000 2108.000000 278.160000 2111.360000 ;
        RECT 226.560000 2108.000000 228.160000 2111.360000 ;
        RECT 176.560000 2108.000000 178.160000 2111.360000 ;
        RECT 126.560000 2108.000000 128.160000 2111.360000 ;
        RECT 126.560000 1781.600000 128.160000 1784.960000 ;
        RECT 126.560000 1754.400000 128.160000 1757.760000 ;
        RECT 126.560000 1727.200000 128.160000 1730.560000 ;
        RECT 126.560000 1700.000000 128.160000 1703.360000 ;
        RECT 126.560000 1890.400000 128.160000 1893.760000 ;
        RECT 126.560000 1863.200000 128.160000 1866.560000 ;
        RECT 126.560000 1836.000000 128.160000 1839.360000 ;
        RECT 126.560000 1808.800000 128.160000 1812.160000 ;
        RECT 126.560000 1999.200000 128.160000 2002.560000 ;
        RECT 126.560000 1972.000000 128.160000 1975.360000 ;
        RECT 126.560000 1944.800000 128.160000 1948.160000 ;
        RECT 126.560000 1917.600000 128.160000 1920.960000 ;
        RECT 126.560000 2080.800000 128.160000 2084.160000 ;
        RECT 126.560000 2053.600000 128.160000 2056.960000 ;
        RECT 126.560000 2026.400000 128.160000 2029.760000 ;
        RECT 226.560000 1781.600000 228.160000 1784.960000 ;
        RECT 226.560000 1754.400000 228.160000 1757.760000 ;
        RECT 226.560000 1727.200000 228.160000 1730.560000 ;
        RECT 226.560000 1700.000000 228.160000 1703.360000 ;
        RECT 176.560000 1781.600000 178.160000 1784.960000 ;
        RECT 176.560000 1754.400000 178.160000 1757.760000 ;
        RECT 176.560000 1727.200000 178.160000 1730.560000 ;
        RECT 176.560000 1700.000000 178.160000 1703.360000 ;
        RECT 276.560000 1700.000000 278.160000 1703.360000 ;
        RECT 276.560000 1727.200000 278.160000 1730.560000 ;
        RECT 276.560000 1754.400000 278.160000 1757.760000 ;
        RECT 276.560000 1781.600000 278.160000 1784.960000 ;
        RECT 326.560000 1700.000000 328.160000 1703.360000 ;
        RECT 326.560000 1727.200000 328.160000 1730.560000 ;
        RECT 326.560000 1754.400000 328.160000 1757.760000 ;
        RECT 326.560000 1781.600000 328.160000 1784.960000 ;
        RECT 226.560000 1890.400000 228.160000 1893.760000 ;
        RECT 226.560000 1863.200000 228.160000 1866.560000 ;
        RECT 226.560000 1836.000000 228.160000 1839.360000 ;
        RECT 226.560000 1808.800000 228.160000 1812.160000 ;
        RECT 176.560000 1890.400000 178.160000 1893.760000 ;
        RECT 176.560000 1863.200000 178.160000 1866.560000 ;
        RECT 176.560000 1836.000000 178.160000 1839.360000 ;
        RECT 176.560000 1808.800000 178.160000 1812.160000 ;
        RECT 326.560000 1863.200000 328.160000 1866.560000 ;
        RECT 276.560000 1808.800000 278.160000 1812.160000 ;
        RECT 276.560000 1836.000000 278.160000 1839.360000 ;
        RECT 276.560000 1863.200000 278.160000 1866.560000 ;
        RECT 276.560000 1890.400000 278.160000 1893.760000 ;
        RECT 326.560000 1808.800000 328.160000 1812.160000 ;
        RECT 326.560000 1836.000000 328.160000 1839.360000 ;
        RECT 326.560000 1890.400000 328.160000 1893.760000 ;
        RECT 376.560000 1700.000000 378.160000 1703.360000 ;
        RECT 376.560000 1727.200000 378.160000 1730.560000 ;
        RECT 376.560000 1754.400000 378.160000 1757.760000 ;
        RECT 376.560000 1781.600000 378.160000 1784.960000 ;
        RECT 426.560000 1700.000000 428.160000 1703.360000 ;
        RECT 426.560000 1727.200000 428.160000 1730.560000 ;
        RECT 426.560000 1754.400000 428.160000 1757.760000 ;
        RECT 426.560000 1781.600000 428.160000 1784.960000 ;
        RECT 476.560000 1700.000000 478.160000 1703.360000 ;
        RECT 476.560000 1727.200000 478.160000 1730.560000 ;
        RECT 476.560000 1754.400000 478.160000 1757.760000 ;
        RECT 476.560000 1781.600000 478.160000 1784.960000 ;
        RECT 526.560000 1700.000000 528.160000 1703.360000 ;
        RECT 526.560000 1727.200000 528.160000 1730.560000 ;
        RECT 526.560000 1754.400000 528.160000 1757.760000 ;
        RECT 526.560000 1781.600000 528.160000 1784.960000 ;
        RECT 426.560000 1890.400000 428.160000 1893.760000 ;
        RECT 426.560000 1863.200000 428.160000 1866.560000 ;
        RECT 426.560000 1836.000000 428.160000 1839.360000 ;
        RECT 426.560000 1808.800000 428.160000 1812.160000 ;
        RECT 376.560000 1890.400000 378.160000 1893.760000 ;
        RECT 376.560000 1863.200000 378.160000 1866.560000 ;
        RECT 376.560000 1836.000000 378.160000 1839.360000 ;
        RECT 376.560000 1808.800000 378.160000 1812.160000 ;
        RECT 526.560000 1836.000000 528.160000 1839.360000 ;
        RECT 526.560000 1808.800000 528.160000 1812.160000 ;
        RECT 476.560000 1890.400000 478.160000 1893.760000 ;
        RECT 476.560000 1863.200000 478.160000 1866.560000 ;
        RECT 476.560000 1836.000000 478.160000 1839.360000 ;
        RECT 476.560000 1808.800000 478.160000 1812.160000 ;
        RECT 526.560000 1863.200000 528.160000 1866.560000 ;
        RECT 526.560000 1890.400000 528.160000 1893.760000 ;
        RECT 226.560000 1999.200000 228.160000 2002.560000 ;
        RECT 226.560000 1972.000000 228.160000 1975.360000 ;
        RECT 226.560000 1944.800000 228.160000 1948.160000 ;
        RECT 226.560000 1917.600000 228.160000 1920.960000 ;
        RECT 176.560000 1999.200000 178.160000 2002.560000 ;
        RECT 176.560000 1972.000000 178.160000 1975.360000 ;
        RECT 176.560000 1944.800000 178.160000 1948.160000 ;
        RECT 176.560000 1917.600000 178.160000 1920.960000 ;
        RECT 276.560000 1917.600000 278.160000 1920.960000 ;
        RECT 276.560000 1944.800000 278.160000 1948.160000 ;
        RECT 276.560000 1972.000000 278.160000 1975.360000 ;
        RECT 276.560000 1999.200000 278.160000 2002.560000 ;
        RECT 326.560000 1917.600000 328.160000 1920.960000 ;
        RECT 326.560000 1944.800000 328.160000 1948.160000 ;
        RECT 326.560000 1972.000000 328.160000 1975.360000 ;
        RECT 326.560000 1999.200000 328.160000 2002.560000 ;
        RECT 226.560000 2080.800000 228.160000 2084.160000 ;
        RECT 226.560000 2053.600000 228.160000 2056.960000 ;
        RECT 226.560000 2026.400000 228.160000 2029.760000 ;
        RECT 176.560000 2080.800000 178.160000 2084.160000 ;
        RECT 176.560000 2053.600000 178.160000 2056.960000 ;
        RECT 176.560000 2026.400000 178.160000 2029.760000 ;
        RECT 276.560000 2026.400000 278.160000 2029.760000 ;
        RECT 276.560000 2053.600000 278.160000 2056.960000 ;
        RECT 276.560000 2080.800000 278.160000 2084.160000 ;
        RECT 326.560000 2026.400000 328.160000 2029.760000 ;
        RECT 326.560000 2053.600000 328.160000 2056.960000 ;
        RECT 326.560000 2080.800000 328.160000 2084.160000 ;
        RECT 426.560000 1999.200000 428.160000 2002.560000 ;
        RECT 426.560000 1972.000000 428.160000 1975.360000 ;
        RECT 426.560000 1944.800000 428.160000 1948.160000 ;
        RECT 426.560000 1917.600000 428.160000 1920.960000 ;
        RECT 376.560000 1999.200000 378.160000 2002.560000 ;
        RECT 376.560000 1972.000000 378.160000 1975.360000 ;
        RECT 376.560000 1917.600000 378.160000 1920.960000 ;
        RECT 376.560000 1944.800000 378.160000 1948.160000 ;
        RECT 526.560000 1999.200000 528.160000 2002.560000 ;
        RECT 526.560000 1972.000000 528.160000 1975.360000 ;
        RECT 526.560000 1944.800000 528.160000 1948.160000 ;
        RECT 526.560000 1917.600000 528.160000 1920.960000 ;
        RECT 476.560000 1999.200000 478.160000 2002.560000 ;
        RECT 476.560000 1972.000000 478.160000 1975.360000 ;
        RECT 476.560000 1944.800000 478.160000 1948.160000 ;
        RECT 476.560000 1917.600000 478.160000 1920.960000 ;
        RECT 376.560000 2026.400000 378.160000 2029.760000 ;
        RECT 376.560000 2053.600000 378.160000 2056.960000 ;
        RECT 376.560000 2080.800000 378.160000 2084.160000 ;
        RECT 426.560000 2026.400000 428.160000 2029.760000 ;
        RECT 426.560000 2053.600000 428.160000 2056.960000 ;
        RECT 426.560000 2080.800000 428.160000 2084.160000 ;
        RECT 476.560000 2026.400000 478.160000 2029.760000 ;
        RECT 476.560000 2053.600000 478.160000 2056.960000 ;
        RECT 476.560000 2080.800000 478.160000 2084.160000 ;
        RECT 526.560000 2026.400000 528.160000 2029.760000 ;
        RECT 526.560000 2053.600000 528.160000 2056.960000 ;
        RECT 526.560000 2080.800000 528.160000 2084.160000 ;
        RECT 126.560000 2189.600000 128.160000 2192.960000 ;
        RECT 126.560000 2162.400000 128.160000 2165.760000 ;
        RECT 126.560000 2135.200000 128.160000 2138.560000 ;
        RECT 126.560000 2298.400000 128.160000 2301.760000 ;
        RECT 126.560000 2271.200000 128.160000 2274.560000 ;
        RECT 126.560000 2244.000000 128.160000 2247.360000 ;
        RECT 126.560000 2216.800000 128.160000 2220.160000 ;
        RECT 126.560000 2407.200000 128.160000 2410.560000 ;
        RECT 126.560000 2380.000000 128.160000 2383.360000 ;
        RECT 126.560000 2352.800000 128.160000 2356.160000 ;
        RECT 126.560000 2325.600000 128.160000 2328.960000 ;
        RECT 126.560000 2516.000000 128.160000 2519.360000 ;
        RECT 176.560000 2135.200000 178.160000 2138.560000 ;
        RECT 176.560000 2162.400000 178.160000 2165.760000 ;
        RECT 176.560000 2189.600000 178.160000 2192.960000 ;
        RECT 226.560000 2135.200000 228.160000 2138.560000 ;
        RECT 226.560000 2162.400000 228.160000 2165.760000 ;
        RECT 226.560000 2189.600000 228.160000 2192.960000 ;
        RECT 276.560000 2135.200000 278.160000 2138.560000 ;
        RECT 276.560000 2162.400000 278.160000 2165.760000 ;
        RECT 276.560000 2189.600000 278.160000 2192.960000 ;
        RECT 326.560000 2135.200000 328.160000 2138.560000 ;
        RECT 326.560000 2162.400000 328.160000 2165.760000 ;
        RECT 326.560000 2189.600000 328.160000 2192.960000 ;
        RECT 176.560000 2216.800000 178.160000 2220.160000 ;
        RECT 176.560000 2244.000000 178.160000 2247.360000 ;
        RECT 176.560000 2271.200000 178.160000 2274.560000 ;
        RECT 176.560000 2298.400000 178.160000 2301.760000 ;
        RECT 226.560000 2216.800000 228.160000 2220.160000 ;
        RECT 226.560000 2244.000000 228.160000 2247.360000 ;
        RECT 226.560000 2271.200000 228.160000 2274.560000 ;
        RECT 226.560000 2298.400000 228.160000 2301.760000 ;
        RECT 276.560000 2216.800000 278.160000 2220.160000 ;
        RECT 276.560000 2244.000000 278.160000 2247.360000 ;
        RECT 276.560000 2271.200000 278.160000 2274.560000 ;
        RECT 276.560000 2298.400000 278.160000 2301.760000 ;
        RECT 326.560000 2216.800000 328.160000 2220.160000 ;
        RECT 326.560000 2244.000000 328.160000 2247.360000 ;
        RECT 326.560000 2271.200000 328.160000 2274.560000 ;
        RECT 326.560000 2298.400000 328.160000 2301.760000 ;
        RECT 376.560000 2162.400000 378.160000 2165.760000 ;
        RECT 376.560000 2135.200000 378.160000 2138.560000 ;
        RECT 376.560000 2189.600000 378.160000 2192.960000 ;
        RECT 426.560000 2135.200000 428.160000 2138.560000 ;
        RECT 426.560000 2162.400000 428.160000 2165.760000 ;
        RECT 426.560000 2189.600000 428.160000 2192.960000 ;
        RECT 476.560000 2135.200000 478.160000 2138.560000 ;
        RECT 476.560000 2162.400000 478.160000 2165.760000 ;
        RECT 476.560000 2189.600000 478.160000 2192.960000 ;
        RECT 526.560000 2135.200000 528.160000 2138.560000 ;
        RECT 526.560000 2162.400000 528.160000 2165.760000 ;
        RECT 526.560000 2189.600000 528.160000 2192.960000 ;
        RECT 426.560000 2298.400000 428.160000 2301.760000 ;
        RECT 426.560000 2271.200000 428.160000 2274.560000 ;
        RECT 426.560000 2244.000000 428.160000 2247.360000 ;
        RECT 426.560000 2216.800000 428.160000 2220.160000 ;
        RECT 376.560000 2298.400000 378.160000 2301.760000 ;
        RECT 376.560000 2271.200000 378.160000 2274.560000 ;
        RECT 376.560000 2244.000000 378.160000 2247.360000 ;
        RECT 376.560000 2216.800000 378.160000 2220.160000 ;
        RECT 526.560000 2298.400000 528.160000 2301.760000 ;
        RECT 526.560000 2271.200000 528.160000 2274.560000 ;
        RECT 526.560000 2244.000000 528.160000 2247.360000 ;
        RECT 526.560000 2216.800000 528.160000 2220.160000 ;
        RECT 476.560000 2298.400000 478.160000 2301.760000 ;
        RECT 476.560000 2271.200000 478.160000 2274.560000 ;
        RECT 476.560000 2244.000000 478.160000 2247.360000 ;
        RECT 476.560000 2216.800000 478.160000 2220.160000 ;
        RECT 176.560000 2325.600000 178.160000 2328.960000 ;
        RECT 176.560000 2352.800000 178.160000 2356.160000 ;
        RECT 176.560000 2380.000000 178.160000 2383.360000 ;
        RECT 176.560000 2407.200000 178.160000 2410.560000 ;
        RECT 226.560000 2325.600000 228.160000 2328.960000 ;
        RECT 226.560000 2352.800000 228.160000 2356.160000 ;
        RECT 226.560000 2380.000000 228.160000 2383.360000 ;
        RECT 226.560000 2407.200000 228.160000 2410.560000 ;
        RECT 276.560000 2325.600000 278.160000 2328.960000 ;
        RECT 276.560000 2352.800000 278.160000 2356.160000 ;
        RECT 276.560000 2380.000000 278.160000 2383.360000 ;
        RECT 276.560000 2407.200000 278.160000 2410.560000 ;
        RECT 326.560000 2325.600000 328.160000 2328.960000 ;
        RECT 326.560000 2352.800000 328.160000 2356.160000 ;
        RECT 326.560000 2380.000000 328.160000 2383.360000 ;
        RECT 326.560000 2407.200000 328.160000 2410.560000 ;
        RECT 176.560000 2516.000000 178.160000 2519.360000 ;
        RECT 226.560000 2516.000000 228.160000 2519.360000 ;
        RECT 276.560000 2516.000000 278.160000 2519.360000 ;
        RECT 326.560000 2516.000000 328.160000 2519.360000 ;
        RECT 376.560000 2325.600000 378.160000 2328.960000 ;
        RECT 376.560000 2352.800000 378.160000 2356.160000 ;
        RECT 376.560000 2380.000000 378.160000 2383.360000 ;
        RECT 376.560000 2407.200000 378.160000 2410.560000 ;
        RECT 426.560000 2325.600000 428.160000 2328.960000 ;
        RECT 426.560000 2352.800000 428.160000 2356.160000 ;
        RECT 426.560000 2380.000000 428.160000 2383.360000 ;
        RECT 426.560000 2407.200000 428.160000 2410.560000 ;
        RECT 476.560000 2325.600000 478.160000 2328.960000 ;
        RECT 476.560000 2352.800000 478.160000 2356.160000 ;
        RECT 476.560000 2380.000000 478.160000 2383.360000 ;
        RECT 476.560000 2407.200000 478.160000 2410.560000 ;
        RECT 526.560000 2325.600000 528.160000 2328.960000 ;
        RECT 526.560000 2352.800000 528.160000 2356.160000 ;
        RECT 526.560000 2380.000000 528.160000 2383.360000 ;
        RECT 526.560000 2407.200000 528.160000 2410.560000 ;
        RECT 376.560000 2516.000000 378.160000 2519.360000 ;
        RECT 426.560000 2516.000000 428.160000 2519.360000 ;
        RECT 476.560000 2516.000000 478.160000 2519.360000 ;
        RECT 526.560000 2516.000000 528.160000 2519.360000 ;
        RECT 876.560000 2108.000000 878.160000 2111.360000 ;
        RECT 826.560000 2108.000000 828.160000 2111.360000 ;
        RECT 776.560000 2108.000000 778.160000 2111.360000 ;
        RECT 726.560000 2108.000000 728.160000 2111.360000 ;
        RECT 676.560000 2108.000000 678.160000 2111.360000 ;
        RECT 626.560000 2108.000000 628.160000 2111.360000 ;
        RECT 576.560000 2108.000000 578.160000 2111.360000 ;
        RECT 626.560000 1781.600000 628.160000 1784.960000 ;
        RECT 626.560000 1754.400000 628.160000 1757.760000 ;
        RECT 626.560000 1727.200000 628.160000 1730.560000 ;
        RECT 626.560000 1700.000000 628.160000 1703.360000 ;
        RECT 576.560000 1781.600000 578.160000 1784.960000 ;
        RECT 576.560000 1754.400000 578.160000 1757.760000 ;
        RECT 576.560000 1727.200000 578.160000 1730.560000 ;
        RECT 576.560000 1700.000000 578.160000 1703.360000 ;
        RECT 726.560000 1781.600000 728.160000 1784.960000 ;
        RECT 726.560000 1754.400000 728.160000 1757.760000 ;
        RECT 726.560000 1727.200000 728.160000 1730.560000 ;
        RECT 726.560000 1700.000000 728.160000 1703.360000 ;
        RECT 676.560000 1781.600000 678.160000 1784.960000 ;
        RECT 676.560000 1754.400000 678.160000 1757.760000 ;
        RECT 676.560000 1727.200000 678.160000 1730.560000 ;
        RECT 676.560000 1700.000000 678.160000 1703.360000 ;
        RECT 776.560000 1700.000000 778.160000 1703.360000 ;
        RECT 776.560000 1727.200000 778.160000 1730.560000 ;
        RECT 776.560000 1754.400000 778.160000 1757.760000 ;
        RECT 776.560000 1781.600000 778.160000 1784.960000 ;
        RECT 626.560000 1890.400000 628.160000 1893.760000 ;
        RECT 626.560000 1863.200000 628.160000 1866.560000 ;
        RECT 626.560000 1836.000000 628.160000 1839.360000 ;
        RECT 626.560000 1808.800000 628.160000 1812.160000 ;
        RECT 576.560000 1890.400000 578.160000 1893.760000 ;
        RECT 576.560000 1863.200000 578.160000 1866.560000 ;
        RECT 576.560000 1836.000000 578.160000 1839.360000 ;
        RECT 576.560000 1808.800000 578.160000 1812.160000 ;
        RECT 726.560000 1836.000000 728.160000 1839.360000 ;
        RECT 726.560000 1808.800000 728.160000 1812.160000 ;
        RECT 676.560000 1890.400000 678.160000 1893.760000 ;
        RECT 676.560000 1863.200000 678.160000 1866.560000 ;
        RECT 676.560000 1836.000000 678.160000 1839.360000 ;
        RECT 676.560000 1808.800000 678.160000 1812.160000 ;
        RECT 726.560000 1863.200000 728.160000 1866.560000 ;
        RECT 726.560000 1890.400000 728.160000 1893.760000 ;
        RECT 776.560000 1808.800000 778.160000 1812.160000 ;
        RECT 776.560000 1836.000000 778.160000 1839.360000 ;
        RECT 776.560000 1863.200000 778.160000 1866.560000 ;
        RECT 776.560000 1890.400000 778.160000 1893.760000 ;
        RECT 876.560000 1781.600000 878.160000 1784.960000 ;
        RECT 876.560000 1754.400000 878.160000 1757.760000 ;
        RECT 876.560000 1727.200000 878.160000 1730.560000 ;
        RECT 876.560000 1700.000000 878.160000 1703.360000 ;
        RECT 826.560000 1781.600000 828.160000 1784.960000 ;
        RECT 826.560000 1754.400000 828.160000 1757.760000 ;
        RECT 826.560000 1727.200000 828.160000 1730.560000 ;
        RECT 826.560000 1700.000000 828.160000 1703.360000 ;
        RECT 876.560000 1890.400000 878.160000 1893.760000 ;
        RECT 876.560000 1863.200000 878.160000 1866.560000 ;
        RECT 876.560000 1836.000000 878.160000 1839.360000 ;
        RECT 876.560000 1808.800000 878.160000 1812.160000 ;
        RECT 826.560000 1890.400000 828.160000 1893.760000 ;
        RECT 826.560000 1863.200000 828.160000 1866.560000 ;
        RECT 826.560000 1836.000000 828.160000 1839.360000 ;
        RECT 826.560000 1808.800000 828.160000 1812.160000 ;
        RECT 626.560000 1999.200000 628.160000 2002.560000 ;
        RECT 626.560000 1972.000000 628.160000 1975.360000 ;
        RECT 626.560000 1944.800000 628.160000 1948.160000 ;
        RECT 626.560000 1917.600000 628.160000 1920.960000 ;
        RECT 576.560000 1999.200000 578.160000 2002.560000 ;
        RECT 576.560000 1972.000000 578.160000 1975.360000 ;
        RECT 576.560000 1944.800000 578.160000 1948.160000 ;
        RECT 576.560000 1917.600000 578.160000 1920.960000 ;
        RECT 776.560000 1944.800000 778.160000 1948.160000 ;
        RECT 776.560000 1917.600000 778.160000 1920.960000 ;
        RECT 726.560000 1999.200000 728.160000 2002.560000 ;
        RECT 726.560000 1972.000000 728.160000 1975.360000 ;
        RECT 726.560000 1944.800000 728.160000 1948.160000 ;
        RECT 726.560000 1917.600000 728.160000 1920.960000 ;
        RECT 676.560000 1999.200000 678.160000 2002.560000 ;
        RECT 676.560000 1972.000000 678.160000 1975.360000 ;
        RECT 676.560000 1944.800000 678.160000 1948.160000 ;
        RECT 676.560000 1917.600000 678.160000 1920.960000 ;
        RECT 776.560000 1972.000000 778.160000 1975.360000 ;
        RECT 776.560000 1999.200000 778.160000 2002.560000 ;
        RECT 626.560000 2080.800000 628.160000 2084.160000 ;
        RECT 626.560000 2053.600000 628.160000 2056.960000 ;
        RECT 626.560000 2026.400000 628.160000 2029.760000 ;
        RECT 576.560000 2080.800000 578.160000 2084.160000 ;
        RECT 576.560000 2053.600000 578.160000 2056.960000 ;
        RECT 576.560000 2026.400000 578.160000 2029.760000 ;
        RECT 726.560000 2080.800000 728.160000 2084.160000 ;
        RECT 726.560000 2053.600000 728.160000 2056.960000 ;
        RECT 726.560000 2026.400000 728.160000 2029.760000 ;
        RECT 676.560000 2080.800000 678.160000 2084.160000 ;
        RECT 676.560000 2053.600000 678.160000 2056.960000 ;
        RECT 676.560000 2026.400000 678.160000 2029.760000 ;
        RECT 776.560000 2026.400000 778.160000 2029.760000 ;
        RECT 776.560000 2053.600000 778.160000 2056.960000 ;
        RECT 776.560000 2080.800000 778.160000 2084.160000 ;
        RECT 876.560000 1999.200000 878.160000 2002.560000 ;
        RECT 876.560000 1972.000000 878.160000 1975.360000 ;
        RECT 876.560000 1944.800000 878.160000 1948.160000 ;
        RECT 876.560000 1917.600000 878.160000 1920.960000 ;
        RECT 826.560000 1999.200000 828.160000 2002.560000 ;
        RECT 826.560000 1972.000000 828.160000 1975.360000 ;
        RECT 826.560000 1944.800000 828.160000 1948.160000 ;
        RECT 826.560000 1917.600000 828.160000 1920.960000 ;
        RECT 876.560000 2080.800000 878.160000 2084.160000 ;
        RECT 876.560000 2053.600000 878.160000 2056.960000 ;
        RECT 876.560000 2026.400000 878.160000 2029.760000 ;
        RECT 826.560000 2080.800000 828.160000 2084.160000 ;
        RECT 826.560000 2053.600000 828.160000 2056.960000 ;
        RECT 826.560000 2026.400000 828.160000 2029.760000 ;
        RECT 626.560000 2189.600000 628.160000 2192.960000 ;
        RECT 626.560000 2162.400000 628.160000 2165.760000 ;
        RECT 626.560000 2135.200000 628.160000 2138.560000 ;
        RECT 576.560000 2189.600000 578.160000 2192.960000 ;
        RECT 576.560000 2162.400000 578.160000 2165.760000 ;
        RECT 576.560000 2135.200000 578.160000 2138.560000 ;
        RECT 776.560000 2162.400000 778.160000 2165.760000 ;
        RECT 776.560000 2135.200000 778.160000 2138.560000 ;
        RECT 726.560000 2189.600000 728.160000 2192.960000 ;
        RECT 726.560000 2162.400000 728.160000 2165.760000 ;
        RECT 726.560000 2135.200000 728.160000 2138.560000 ;
        RECT 676.560000 2189.600000 678.160000 2192.960000 ;
        RECT 676.560000 2162.400000 678.160000 2165.760000 ;
        RECT 676.560000 2135.200000 678.160000 2138.560000 ;
        RECT 776.560000 2189.600000 778.160000 2192.960000 ;
        RECT 626.560000 2298.400000 628.160000 2301.760000 ;
        RECT 626.560000 2271.200000 628.160000 2274.560000 ;
        RECT 626.560000 2244.000000 628.160000 2247.360000 ;
        RECT 626.560000 2216.800000 628.160000 2220.160000 ;
        RECT 576.560000 2298.400000 578.160000 2301.760000 ;
        RECT 576.560000 2271.200000 578.160000 2274.560000 ;
        RECT 576.560000 2244.000000 578.160000 2247.360000 ;
        RECT 576.560000 2216.800000 578.160000 2220.160000 ;
        RECT 726.560000 2298.400000 728.160000 2301.760000 ;
        RECT 726.560000 2271.200000 728.160000 2274.560000 ;
        RECT 726.560000 2244.000000 728.160000 2247.360000 ;
        RECT 726.560000 2216.800000 728.160000 2220.160000 ;
        RECT 676.560000 2298.400000 678.160000 2301.760000 ;
        RECT 676.560000 2271.200000 678.160000 2274.560000 ;
        RECT 676.560000 2244.000000 678.160000 2247.360000 ;
        RECT 676.560000 2216.800000 678.160000 2220.160000 ;
        RECT 776.560000 2216.800000 778.160000 2220.160000 ;
        RECT 776.560000 2244.000000 778.160000 2247.360000 ;
        RECT 776.560000 2271.200000 778.160000 2274.560000 ;
        RECT 776.560000 2298.400000 778.160000 2301.760000 ;
        RECT 876.560000 2189.600000 878.160000 2192.960000 ;
        RECT 876.560000 2162.400000 878.160000 2165.760000 ;
        RECT 876.560000 2135.200000 878.160000 2138.560000 ;
        RECT 826.560000 2189.600000 828.160000 2192.960000 ;
        RECT 826.560000 2162.400000 828.160000 2165.760000 ;
        RECT 826.560000 2135.200000 828.160000 2138.560000 ;
        RECT 876.560000 2298.400000 878.160000 2301.760000 ;
        RECT 876.560000 2271.200000 878.160000 2274.560000 ;
        RECT 876.560000 2244.000000 878.160000 2247.360000 ;
        RECT 876.560000 2216.800000 878.160000 2220.160000 ;
        RECT 826.560000 2298.400000 828.160000 2301.760000 ;
        RECT 826.560000 2271.200000 828.160000 2274.560000 ;
        RECT 826.560000 2244.000000 828.160000 2247.360000 ;
        RECT 826.560000 2216.800000 828.160000 2220.160000 ;
        RECT 576.560000 2325.600000 578.160000 2328.960000 ;
        RECT 576.560000 2352.800000 578.160000 2356.160000 ;
        RECT 576.560000 2380.000000 578.160000 2383.360000 ;
        RECT 576.560000 2407.200000 578.160000 2410.560000 ;
        RECT 626.560000 2325.600000 628.160000 2328.960000 ;
        RECT 626.560000 2352.800000 628.160000 2356.160000 ;
        RECT 626.560000 2380.000000 628.160000 2383.360000 ;
        RECT 626.560000 2407.200000 628.160000 2410.560000 ;
        RECT 676.560000 2325.600000 678.160000 2328.960000 ;
        RECT 676.560000 2352.800000 678.160000 2356.160000 ;
        RECT 676.560000 2380.000000 678.160000 2383.360000 ;
        RECT 676.560000 2407.200000 678.160000 2410.560000 ;
        RECT 726.560000 2325.600000 728.160000 2328.960000 ;
        RECT 726.560000 2352.800000 728.160000 2356.160000 ;
        RECT 726.560000 2380.000000 728.160000 2383.360000 ;
        RECT 726.560000 2407.200000 728.160000 2410.560000 ;
        RECT 776.560000 2325.600000 778.160000 2328.960000 ;
        RECT 776.560000 2352.800000 778.160000 2356.160000 ;
        RECT 776.560000 2380.000000 778.160000 2383.360000 ;
        RECT 776.560000 2407.200000 778.160000 2410.560000 ;
        RECT 576.560000 2516.000000 578.160000 2519.360000 ;
        RECT 626.560000 2516.000000 628.160000 2519.360000 ;
        RECT 726.560000 2516.000000 728.160000 2519.360000 ;
        RECT 676.560000 2516.000000 678.160000 2519.360000 ;
        RECT 776.560000 2516.000000 778.160000 2519.360000 ;
        RECT 876.560000 2407.200000 878.160000 2410.560000 ;
        RECT 876.560000 2380.000000 878.160000 2383.360000 ;
        RECT 876.560000 2352.800000 878.160000 2356.160000 ;
        RECT 876.560000 2325.600000 878.160000 2328.960000 ;
        RECT 826.560000 2407.200000 828.160000 2410.560000 ;
        RECT 826.560000 2380.000000 828.160000 2383.360000 ;
        RECT 826.560000 2352.800000 828.160000 2356.160000 ;
        RECT 826.560000 2325.600000 828.160000 2328.960000 ;
        RECT 826.560000 2516.000000 828.160000 2519.360000 ;
        RECT 876.560000 2516.000000 878.160000 2519.360000 ;
        RECT 126.560000 2624.800000 128.160000 2628.160000 ;
        RECT 126.560000 2597.600000 128.160000 2600.960000 ;
        RECT 126.560000 2570.400000 128.160000 2573.760000 ;
        RECT 126.560000 2543.200000 128.160000 2546.560000 ;
        RECT 126.560000 2733.600000 128.160000 2736.960000 ;
        RECT 126.560000 2706.400000 128.160000 2709.760000 ;
        RECT 126.560000 2679.200000 128.160000 2682.560000 ;
        RECT 126.560000 2652.000000 128.160000 2655.360000 ;
        RECT 126.560000 2842.400000 128.160000 2845.760000 ;
        RECT 126.560000 2815.200000 128.160000 2818.560000 ;
        RECT 126.560000 2788.000000 128.160000 2791.360000 ;
        RECT 126.560000 2760.800000 128.160000 2764.160000 ;
        RECT 126.560000 2951.200000 128.160000 2954.560000 ;
        RECT 126.560000 2924.000000 128.160000 2927.360000 ;
        RECT 126.560000 2896.800000 128.160000 2900.160000 ;
        RECT 126.560000 2869.600000 128.160000 2872.960000 ;
        RECT 226.560000 2624.800000 228.160000 2628.160000 ;
        RECT 226.560000 2597.600000 228.160000 2600.960000 ;
        RECT 226.560000 2570.400000 228.160000 2573.760000 ;
        RECT 226.560000 2543.200000 228.160000 2546.560000 ;
        RECT 176.560000 2624.800000 178.160000 2628.160000 ;
        RECT 176.560000 2597.600000 178.160000 2600.960000 ;
        RECT 176.560000 2570.400000 178.160000 2573.760000 ;
        RECT 176.560000 2543.200000 178.160000 2546.560000 ;
        RECT 276.560000 2543.200000 278.160000 2546.560000 ;
        RECT 276.560000 2570.400000 278.160000 2573.760000 ;
        RECT 276.560000 2597.600000 278.160000 2600.960000 ;
        RECT 276.560000 2624.800000 278.160000 2628.160000 ;
        RECT 326.560000 2543.200000 328.160000 2546.560000 ;
        RECT 326.560000 2570.400000 328.160000 2573.760000 ;
        RECT 326.560000 2597.600000 328.160000 2600.960000 ;
        RECT 326.560000 2624.800000 328.160000 2628.160000 ;
        RECT 226.560000 2733.600000 228.160000 2736.960000 ;
        RECT 226.560000 2706.400000 228.160000 2709.760000 ;
        RECT 226.560000 2679.200000 228.160000 2682.560000 ;
        RECT 226.560000 2652.000000 228.160000 2655.360000 ;
        RECT 176.560000 2733.600000 178.160000 2736.960000 ;
        RECT 176.560000 2706.400000 178.160000 2709.760000 ;
        RECT 176.560000 2679.200000 178.160000 2682.560000 ;
        RECT 176.560000 2652.000000 178.160000 2655.360000 ;
        RECT 326.560000 2706.400000 328.160000 2709.760000 ;
        RECT 276.560000 2652.000000 278.160000 2655.360000 ;
        RECT 276.560000 2679.200000 278.160000 2682.560000 ;
        RECT 276.560000 2706.400000 278.160000 2709.760000 ;
        RECT 276.560000 2733.600000 278.160000 2736.960000 ;
        RECT 326.560000 2652.000000 328.160000 2655.360000 ;
        RECT 326.560000 2679.200000 328.160000 2682.560000 ;
        RECT 326.560000 2733.600000 328.160000 2736.960000 ;
        RECT 376.560000 2543.200000 378.160000 2546.560000 ;
        RECT 376.560000 2570.400000 378.160000 2573.760000 ;
        RECT 376.560000 2597.600000 378.160000 2600.960000 ;
        RECT 376.560000 2624.800000 378.160000 2628.160000 ;
        RECT 426.560000 2543.200000 428.160000 2546.560000 ;
        RECT 426.560000 2570.400000 428.160000 2573.760000 ;
        RECT 426.560000 2597.600000 428.160000 2600.960000 ;
        RECT 426.560000 2624.800000 428.160000 2628.160000 ;
        RECT 476.560000 2543.200000 478.160000 2546.560000 ;
        RECT 476.560000 2570.400000 478.160000 2573.760000 ;
        RECT 476.560000 2597.600000 478.160000 2600.960000 ;
        RECT 476.560000 2624.800000 478.160000 2628.160000 ;
        RECT 526.560000 2543.200000 528.160000 2546.560000 ;
        RECT 526.560000 2570.400000 528.160000 2573.760000 ;
        RECT 526.560000 2597.600000 528.160000 2600.960000 ;
        RECT 526.560000 2624.800000 528.160000 2628.160000 ;
        RECT 526.560000 2733.600000 528.160000 2736.960000 ;
        RECT 526.560000 2706.400000 528.160000 2709.760000 ;
        RECT 376.560000 2652.000000 378.160000 2655.360000 ;
        RECT 376.560000 2679.200000 378.160000 2682.560000 ;
        RECT 376.560000 2706.400000 378.160000 2709.760000 ;
        RECT 376.560000 2733.600000 378.160000 2736.960000 ;
        RECT 426.560000 2652.000000 428.160000 2655.360000 ;
        RECT 426.560000 2679.200000 428.160000 2682.560000 ;
        RECT 426.560000 2706.400000 428.160000 2709.760000 ;
        RECT 426.560000 2733.600000 428.160000 2736.960000 ;
        RECT 476.560000 2652.000000 478.160000 2655.360000 ;
        RECT 476.560000 2679.200000 478.160000 2682.560000 ;
        RECT 476.560000 2706.400000 478.160000 2709.760000 ;
        RECT 476.560000 2733.600000 478.160000 2736.960000 ;
        RECT 526.560000 2652.000000 528.160000 2655.360000 ;
        RECT 526.560000 2679.200000 528.160000 2682.560000 ;
        RECT 226.560000 2842.400000 228.160000 2845.760000 ;
        RECT 226.560000 2815.200000 228.160000 2818.560000 ;
        RECT 226.560000 2788.000000 228.160000 2791.360000 ;
        RECT 226.560000 2760.800000 228.160000 2764.160000 ;
        RECT 176.560000 2842.400000 178.160000 2845.760000 ;
        RECT 176.560000 2815.200000 178.160000 2818.560000 ;
        RECT 176.560000 2788.000000 178.160000 2791.360000 ;
        RECT 176.560000 2760.800000 178.160000 2764.160000 ;
        RECT 276.560000 2760.800000 278.160000 2764.160000 ;
        RECT 276.560000 2788.000000 278.160000 2791.360000 ;
        RECT 276.560000 2815.200000 278.160000 2818.560000 ;
        RECT 276.560000 2842.400000 278.160000 2845.760000 ;
        RECT 326.560000 2760.800000 328.160000 2764.160000 ;
        RECT 326.560000 2788.000000 328.160000 2791.360000 ;
        RECT 326.560000 2815.200000 328.160000 2818.560000 ;
        RECT 326.560000 2842.400000 328.160000 2845.760000 ;
        RECT 226.560000 2896.800000 228.160000 2900.160000 ;
        RECT 226.560000 2869.600000 228.160000 2872.960000 ;
        RECT 176.560000 2951.200000 178.160000 2954.560000 ;
        RECT 176.560000 2924.000000 178.160000 2927.360000 ;
        RECT 176.560000 2896.800000 178.160000 2900.160000 ;
        RECT 176.560000 2869.600000 178.160000 2872.960000 ;
        RECT 226.560000 2924.000000 228.160000 2927.360000 ;
        RECT 226.560000 2951.200000 228.160000 2954.560000 ;
        RECT 326.560000 2924.000000 328.160000 2927.360000 ;
        RECT 276.560000 2869.600000 278.160000 2872.960000 ;
        RECT 276.560000 2896.800000 278.160000 2900.160000 ;
        RECT 276.560000 2924.000000 278.160000 2927.360000 ;
        RECT 276.560000 2951.200000 278.160000 2954.560000 ;
        RECT 326.560000 2869.600000 328.160000 2872.960000 ;
        RECT 326.560000 2896.800000 328.160000 2900.160000 ;
        RECT 326.560000 2951.200000 328.160000 2954.560000 ;
        RECT 426.560000 2842.400000 428.160000 2845.760000 ;
        RECT 426.560000 2815.200000 428.160000 2818.560000 ;
        RECT 426.560000 2788.000000 428.160000 2791.360000 ;
        RECT 426.560000 2760.800000 428.160000 2764.160000 ;
        RECT 376.560000 2842.400000 378.160000 2845.760000 ;
        RECT 376.560000 2815.200000 378.160000 2818.560000 ;
        RECT 376.560000 2788.000000 378.160000 2791.360000 ;
        RECT 376.560000 2760.800000 378.160000 2764.160000 ;
        RECT 526.560000 2842.400000 528.160000 2845.760000 ;
        RECT 526.560000 2815.200000 528.160000 2818.560000 ;
        RECT 526.560000 2788.000000 528.160000 2791.360000 ;
        RECT 526.560000 2760.800000 528.160000 2764.160000 ;
        RECT 476.560000 2842.400000 478.160000 2845.760000 ;
        RECT 476.560000 2815.200000 478.160000 2818.560000 ;
        RECT 476.560000 2788.000000 478.160000 2791.360000 ;
        RECT 476.560000 2760.800000 478.160000 2764.160000 ;
        RECT 426.560000 2951.200000 428.160000 2954.560000 ;
        RECT 426.560000 2924.000000 428.160000 2927.360000 ;
        RECT 426.560000 2896.800000 428.160000 2900.160000 ;
        RECT 426.560000 2869.600000 428.160000 2872.960000 ;
        RECT 376.560000 2951.200000 378.160000 2954.560000 ;
        RECT 376.560000 2924.000000 378.160000 2927.360000 ;
        RECT 376.560000 2896.800000 378.160000 2900.160000 ;
        RECT 376.560000 2869.600000 378.160000 2872.960000 ;
        RECT 526.560000 2896.800000 528.160000 2900.160000 ;
        RECT 526.560000 2869.600000 528.160000 2872.960000 ;
        RECT 476.560000 2951.200000 478.160000 2954.560000 ;
        RECT 476.560000 2924.000000 478.160000 2927.360000 ;
        RECT 476.560000 2896.800000 478.160000 2900.160000 ;
        RECT 476.560000 2869.600000 478.160000 2872.960000 ;
        RECT 526.560000 2924.000000 528.160000 2927.360000 ;
        RECT 526.560000 2951.200000 528.160000 2954.560000 ;
        RECT 126.560000 3060.000000 128.160000 3063.360000 ;
        RECT 126.560000 3032.800000 128.160000 3036.160000 ;
        RECT 126.560000 3005.600000 128.160000 3008.960000 ;
        RECT 126.560000 2978.400000 128.160000 2981.760000 ;
        RECT 126.560000 3141.600000 128.160000 3144.960000 ;
        RECT 126.560000 3114.400000 128.160000 3117.760000 ;
        RECT 126.560000 3087.200000 128.160000 3090.560000 ;
        RECT 126.560000 3250.400000 128.160000 3253.760000 ;
        RECT 126.560000 3223.200000 128.160000 3226.560000 ;
        RECT 126.560000 3196.000000 128.160000 3199.360000 ;
        RECT 126.560000 3168.800000 128.160000 3172.160000 ;
        RECT 126.560000 3277.600000 128.160000 3280.960000 ;
        RECT 176.560000 3060.000000 178.160000 3063.360000 ;
        RECT 226.560000 3060.000000 228.160000 3063.360000 ;
        RECT 276.560000 3060.000000 278.160000 3063.360000 ;
        RECT 326.560000 3060.000000 328.160000 3063.360000 ;
        RECT 176.560000 2978.400000 178.160000 2981.760000 ;
        RECT 176.560000 3005.600000 178.160000 3008.960000 ;
        RECT 176.560000 3032.800000 178.160000 3036.160000 ;
        RECT 226.560000 2978.400000 228.160000 2981.760000 ;
        RECT 226.560000 3005.600000 228.160000 3008.960000 ;
        RECT 226.560000 3032.800000 228.160000 3036.160000 ;
        RECT 276.560000 2978.400000 278.160000 2981.760000 ;
        RECT 276.560000 3005.600000 278.160000 3008.960000 ;
        RECT 276.560000 3032.800000 278.160000 3036.160000 ;
        RECT 326.560000 2978.400000 328.160000 2981.760000 ;
        RECT 326.560000 3005.600000 328.160000 3008.960000 ;
        RECT 326.560000 3032.800000 328.160000 3036.160000 ;
        RECT 176.560000 3087.200000 178.160000 3090.560000 ;
        RECT 176.560000 3114.400000 178.160000 3117.760000 ;
        RECT 176.560000 3141.600000 178.160000 3144.960000 ;
        RECT 226.560000 3087.200000 228.160000 3090.560000 ;
        RECT 226.560000 3114.400000 228.160000 3117.760000 ;
        RECT 226.560000 3141.600000 228.160000 3144.960000 ;
        RECT 276.560000 3087.200000 278.160000 3090.560000 ;
        RECT 276.560000 3114.400000 278.160000 3117.760000 ;
        RECT 276.560000 3141.600000 278.160000 3144.960000 ;
        RECT 326.560000 3087.200000 328.160000 3090.560000 ;
        RECT 326.560000 3114.400000 328.160000 3117.760000 ;
        RECT 326.560000 3141.600000 328.160000 3144.960000 ;
        RECT 526.560000 3060.000000 528.160000 3063.360000 ;
        RECT 476.560000 3060.000000 478.160000 3063.360000 ;
        RECT 426.560000 3060.000000 428.160000 3063.360000 ;
        RECT 376.560000 3060.000000 378.160000 3063.360000 ;
        RECT 376.560000 3005.600000 378.160000 3008.960000 ;
        RECT 376.560000 2978.400000 378.160000 2981.760000 ;
        RECT 376.560000 3032.800000 378.160000 3036.160000 ;
        RECT 426.560000 2978.400000 428.160000 2981.760000 ;
        RECT 426.560000 3005.600000 428.160000 3008.960000 ;
        RECT 426.560000 3032.800000 428.160000 3036.160000 ;
        RECT 476.560000 2978.400000 478.160000 2981.760000 ;
        RECT 476.560000 3005.600000 478.160000 3008.960000 ;
        RECT 476.560000 3032.800000 478.160000 3036.160000 ;
        RECT 526.560000 2978.400000 528.160000 2981.760000 ;
        RECT 526.560000 3005.600000 528.160000 3008.960000 ;
        RECT 526.560000 3032.800000 528.160000 3036.160000 ;
        RECT 376.560000 3087.200000 378.160000 3090.560000 ;
        RECT 376.560000 3114.400000 378.160000 3117.760000 ;
        RECT 376.560000 3141.600000 378.160000 3144.960000 ;
        RECT 426.560000 3087.200000 428.160000 3090.560000 ;
        RECT 426.560000 3114.400000 428.160000 3117.760000 ;
        RECT 426.560000 3141.600000 428.160000 3144.960000 ;
        RECT 476.560000 3087.200000 478.160000 3090.560000 ;
        RECT 476.560000 3114.400000 478.160000 3117.760000 ;
        RECT 476.560000 3141.600000 478.160000 3144.960000 ;
        RECT 526.560000 3087.200000 528.160000 3090.560000 ;
        RECT 526.560000 3114.400000 528.160000 3117.760000 ;
        RECT 526.560000 3141.600000 528.160000 3144.960000 ;
        RECT 176.560000 3168.800000 178.160000 3172.160000 ;
        RECT 176.560000 3196.000000 178.160000 3199.360000 ;
        RECT 176.560000 3223.200000 178.160000 3226.560000 ;
        RECT 176.560000 3250.400000 178.160000 3253.760000 ;
        RECT 226.560000 3168.800000 228.160000 3172.160000 ;
        RECT 226.560000 3196.000000 228.160000 3199.360000 ;
        RECT 226.560000 3223.200000 228.160000 3226.560000 ;
        RECT 226.560000 3250.400000 228.160000 3253.760000 ;
        RECT 276.560000 3168.800000 278.160000 3172.160000 ;
        RECT 276.560000 3196.000000 278.160000 3199.360000 ;
        RECT 276.560000 3223.200000 278.160000 3226.560000 ;
        RECT 276.560000 3250.400000 278.160000 3253.760000 ;
        RECT 326.560000 3168.800000 328.160000 3172.160000 ;
        RECT 326.560000 3196.000000 328.160000 3199.360000 ;
        RECT 326.560000 3223.200000 328.160000 3226.560000 ;
        RECT 326.560000 3250.400000 328.160000 3253.760000 ;
        RECT 226.560000 3277.600000 228.160000 3280.960000 ;
        RECT 176.560000 3277.600000 178.160000 3280.960000 ;
        RECT 326.560000 3277.600000 328.160000 3280.960000 ;
        RECT 276.560000 3277.600000 278.160000 3280.960000 ;
        RECT 376.560000 3168.800000 378.160000 3172.160000 ;
        RECT 376.560000 3196.000000 378.160000 3199.360000 ;
        RECT 376.560000 3223.200000 378.160000 3226.560000 ;
        RECT 376.560000 3250.400000 378.160000 3253.760000 ;
        RECT 426.560000 3168.800000 428.160000 3172.160000 ;
        RECT 426.560000 3196.000000 428.160000 3199.360000 ;
        RECT 426.560000 3223.200000 428.160000 3226.560000 ;
        RECT 426.560000 3250.400000 428.160000 3253.760000 ;
        RECT 476.560000 3168.800000 478.160000 3172.160000 ;
        RECT 476.560000 3196.000000 478.160000 3199.360000 ;
        RECT 476.560000 3223.200000 478.160000 3226.560000 ;
        RECT 476.560000 3250.400000 478.160000 3253.760000 ;
        RECT 526.560000 3168.800000 528.160000 3172.160000 ;
        RECT 526.560000 3196.000000 528.160000 3199.360000 ;
        RECT 526.560000 3223.200000 528.160000 3226.560000 ;
        RECT 526.560000 3250.400000 528.160000 3253.760000 ;
        RECT 426.560000 3277.600000 428.160000 3280.960000 ;
        RECT 376.560000 3277.600000 378.160000 3280.960000 ;
        RECT 526.560000 3277.600000 528.160000 3280.960000 ;
        RECT 476.560000 3277.600000 478.160000 3280.960000 ;
        RECT 626.560000 2624.800000 628.160000 2628.160000 ;
        RECT 626.560000 2597.600000 628.160000 2600.960000 ;
        RECT 626.560000 2570.400000 628.160000 2573.760000 ;
        RECT 626.560000 2543.200000 628.160000 2546.560000 ;
        RECT 576.560000 2624.800000 578.160000 2628.160000 ;
        RECT 576.560000 2597.600000 578.160000 2600.960000 ;
        RECT 576.560000 2570.400000 578.160000 2573.760000 ;
        RECT 576.560000 2543.200000 578.160000 2546.560000 ;
        RECT 726.560000 2624.800000 728.160000 2628.160000 ;
        RECT 726.560000 2597.600000 728.160000 2600.960000 ;
        RECT 726.560000 2570.400000 728.160000 2573.760000 ;
        RECT 726.560000 2543.200000 728.160000 2546.560000 ;
        RECT 676.560000 2624.800000 678.160000 2628.160000 ;
        RECT 676.560000 2597.600000 678.160000 2600.960000 ;
        RECT 676.560000 2570.400000 678.160000 2573.760000 ;
        RECT 676.560000 2543.200000 678.160000 2546.560000 ;
        RECT 776.560000 2543.200000 778.160000 2546.560000 ;
        RECT 776.560000 2570.400000 778.160000 2573.760000 ;
        RECT 776.560000 2597.600000 778.160000 2600.960000 ;
        RECT 776.560000 2624.800000 778.160000 2628.160000 ;
        RECT 626.560000 2733.600000 628.160000 2736.960000 ;
        RECT 626.560000 2706.400000 628.160000 2709.760000 ;
        RECT 626.560000 2679.200000 628.160000 2682.560000 ;
        RECT 626.560000 2652.000000 628.160000 2655.360000 ;
        RECT 576.560000 2733.600000 578.160000 2736.960000 ;
        RECT 576.560000 2706.400000 578.160000 2709.760000 ;
        RECT 576.560000 2679.200000 578.160000 2682.560000 ;
        RECT 576.560000 2652.000000 578.160000 2655.360000 ;
        RECT 726.560000 2679.200000 728.160000 2682.560000 ;
        RECT 726.560000 2652.000000 728.160000 2655.360000 ;
        RECT 676.560000 2733.600000 678.160000 2736.960000 ;
        RECT 676.560000 2706.400000 678.160000 2709.760000 ;
        RECT 676.560000 2679.200000 678.160000 2682.560000 ;
        RECT 676.560000 2652.000000 678.160000 2655.360000 ;
        RECT 726.560000 2706.400000 728.160000 2709.760000 ;
        RECT 726.560000 2733.600000 728.160000 2736.960000 ;
        RECT 776.560000 2652.000000 778.160000 2655.360000 ;
        RECT 776.560000 2679.200000 778.160000 2682.560000 ;
        RECT 776.560000 2706.400000 778.160000 2709.760000 ;
        RECT 776.560000 2733.600000 778.160000 2736.960000 ;
        RECT 876.560000 2624.800000 878.160000 2628.160000 ;
        RECT 876.560000 2597.600000 878.160000 2600.960000 ;
        RECT 876.560000 2570.400000 878.160000 2573.760000 ;
        RECT 876.560000 2543.200000 878.160000 2546.560000 ;
        RECT 826.560000 2624.800000 828.160000 2628.160000 ;
        RECT 826.560000 2597.600000 828.160000 2600.960000 ;
        RECT 826.560000 2570.400000 828.160000 2573.760000 ;
        RECT 826.560000 2543.200000 828.160000 2546.560000 ;
        RECT 876.560000 2733.600000 878.160000 2736.960000 ;
        RECT 876.560000 2706.400000 878.160000 2709.760000 ;
        RECT 876.560000 2679.200000 878.160000 2682.560000 ;
        RECT 876.560000 2652.000000 878.160000 2655.360000 ;
        RECT 826.560000 2733.600000 828.160000 2736.960000 ;
        RECT 826.560000 2706.400000 828.160000 2709.760000 ;
        RECT 826.560000 2679.200000 828.160000 2682.560000 ;
        RECT 826.560000 2652.000000 828.160000 2655.360000 ;
        RECT 626.560000 2842.400000 628.160000 2845.760000 ;
        RECT 626.560000 2815.200000 628.160000 2818.560000 ;
        RECT 626.560000 2788.000000 628.160000 2791.360000 ;
        RECT 626.560000 2760.800000 628.160000 2764.160000 ;
        RECT 576.560000 2842.400000 578.160000 2845.760000 ;
        RECT 576.560000 2815.200000 578.160000 2818.560000 ;
        RECT 576.560000 2788.000000 578.160000 2791.360000 ;
        RECT 576.560000 2760.800000 578.160000 2764.160000 ;
        RECT 726.560000 2842.400000 728.160000 2845.760000 ;
        RECT 726.560000 2815.200000 728.160000 2818.560000 ;
        RECT 726.560000 2788.000000 728.160000 2791.360000 ;
        RECT 726.560000 2760.800000 728.160000 2764.160000 ;
        RECT 676.560000 2842.400000 678.160000 2845.760000 ;
        RECT 676.560000 2815.200000 678.160000 2818.560000 ;
        RECT 676.560000 2788.000000 678.160000 2791.360000 ;
        RECT 676.560000 2760.800000 678.160000 2764.160000 ;
        RECT 776.560000 2760.800000 778.160000 2764.160000 ;
        RECT 776.560000 2788.000000 778.160000 2791.360000 ;
        RECT 776.560000 2815.200000 778.160000 2818.560000 ;
        RECT 776.560000 2842.400000 778.160000 2845.760000 ;
        RECT 626.560000 2951.200000 628.160000 2954.560000 ;
        RECT 626.560000 2924.000000 628.160000 2927.360000 ;
        RECT 626.560000 2896.800000 628.160000 2900.160000 ;
        RECT 626.560000 2869.600000 628.160000 2872.960000 ;
        RECT 576.560000 2951.200000 578.160000 2954.560000 ;
        RECT 576.560000 2924.000000 578.160000 2927.360000 ;
        RECT 576.560000 2896.800000 578.160000 2900.160000 ;
        RECT 576.560000 2869.600000 578.160000 2872.960000 ;
        RECT 726.560000 2896.800000 728.160000 2900.160000 ;
        RECT 726.560000 2869.600000 728.160000 2872.960000 ;
        RECT 676.560000 2951.200000 678.160000 2954.560000 ;
        RECT 676.560000 2924.000000 678.160000 2927.360000 ;
        RECT 676.560000 2896.800000 678.160000 2900.160000 ;
        RECT 676.560000 2869.600000 678.160000 2872.960000 ;
        RECT 726.560000 2924.000000 728.160000 2927.360000 ;
        RECT 726.560000 2951.200000 728.160000 2954.560000 ;
        RECT 776.560000 2869.600000 778.160000 2872.960000 ;
        RECT 776.560000 2896.800000 778.160000 2900.160000 ;
        RECT 776.560000 2924.000000 778.160000 2927.360000 ;
        RECT 776.560000 2951.200000 778.160000 2954.560000 ;
        RECT 876.560000 2842.400000 878.160000 2845.760000 ;
        RECT 876.560000 2815.200000 878.160000 2818.560000 ;
        RECT 876.560000 2788.000000 878.160000 2791.360000 ;
        RECT 876.560000 2760.800000 878.160000 2764.160000 ;
        RECT 826.560000 2842.400000 828.160000 2845.760000 ;
        RECT 826.560000 2815.200000 828.160000 2818.560000 ;
        RECT 826.560000 2788.000000 828.160000 2791.360000 ;
        RECT 826.560000 2760.800000 828.160000 2764.160000 ;
        RECT 876.560000 2951.200000 878.160000 2954.560000 ;
        RECT 876.560000 2924.000000 878.160000 2927.360000 ;
        RECT 876.560000 2896.800000 878.160000 2900.160000 ;
        RECT 876.560000 2869.600000 878.160000 2872.960000 ;
        RECT 826.560000 2951.200000 828.160000 2954.560000 ;
        RECT 826.560000 2924.000000 828.160000 2927.360000 ;
        RECT 826.560000 2896.800000 828.160000 2900.160000 ;
        RECT 826.560000 2869.600000 828.160000 2872.960000 ;
        RECT 776.560000 3060.000000 778.160000 3063.360000 ;
        RECT 726.560000 3060.000000 728.160000 3063.360000 ;
        RECT 676.560000 3060.000000 678.160000 3063.360000 ;
        RECT 626.560000 3060.000000 628.160000 3063.360000 ;
        RECT 576.560000 3060.000000 578.160000 3063.360000 ;
        RECT 626.560000 3032.800000 628.160000 3036.160000 ;
        RECT 626.560000 3005.600000 628.160000 3008.960000 ;
        RECT 626.560000 2978.400000 628.160000 2981.760000 ;
        RECT 576.560000 3032.800000 578.160000 3036.160000 ;
        RECT 576.560000 3005.600000 578.160000 3008.960000 ;
        RECT 576.560000 2978.400000 578.160000 2981.760000 ;
        RECT 776.560000 3005.600000 778.160000 3008.960000 ;
        RECT 776.560000 2978.400000 778.160000 2981.760000 ;
        RECT 726.560000 3032.800000 728.160000 3036.160000 ;
        RECT 726.560000 3005.600000 728.160000 3008.960000 ;
        RECT 726.560000 2978.400000 728.160000 2981.760000 ;
        RECT 676.560000 3032.800000 678.160000 3036.160000 ;
        RECT 676.560000 3005.600000 678.160000 3008.960000 ;
        RECT 676.560000 2978.400000 678.160000 2981.760000 ;
        RECT 776.560000 3032.800000 778.160000 3036.160000 ;
        RECT 626.560000 3141.600000 628.160000 3144.960000 ;
        RECT 626.560000 3114.400000 628.160000 3117.760000 ;
        RECT 626.560000 3087.200000 628.160000 3090.560000 ;
        RECT 576.560000 3141.600000 578.160000 3144.960000 ;
        RECT 576.560000 3114.400000 578.160000 3117.760000 ;
        RECT 576.560000 3087.200000 578.160000 3090.560000 ;
        RECT 726.560000 3141.600000 728.160000 3144.960000 ;
        RECT 726.560000 3114.400000 728.160000 3117.760000 ;
        RECT 726.560000 3087.200000 728.160000 3090.560000 ;
        RECT 676.560000 3141.600000 678.160000 3144.960000 ;
        RECT 676.560000 3114.400000 678.160000 3117.760000 ;
        RECT 676.560000 3087.200000 678.160000 3090.560000 ;
        RECT 776.560000 3087.200000 778.160000 3090.560000 ;
        RECT 776.560000 3114.400000 778.160000 3117.760000 ;
        RECT 776.560000 3141.600000 778.160000 3144.960000 ;
        RECT 876.560000 3060.000000 878.160000 3063.360000 ;
        RECT 826.560000 3060.000000 828.160000 3063.360000 ;
        RECT 876.560000 3032.800000 878.160000 3036.160000 ;
        RECT 876.560000 3005.600000 878.160000 3008.960000 ;
        RECT 876.560000 2978.400000 878.160000 2981.760000 ;
        RECT 826.560000 3032.800000 828.160000 3036.160000 ;
        RECT 826.560000 3005.600000 828.160000 3008.960000 ;
        RECT 826.560000 2978.400000 828.160000 2981.760000 ;
        RECT 876.560000 3141.600000 878.160000 3144.960000 ;
        RECT 876.560000 3114.400000 878.160000 3117.760000 ;
        RECT 876.560000 3087.200000 878.160000 3090.560000 ;
        RECT 826.560000 3141.600000 828.160000 3144.960000 ;
        RECT 826.560000 3114.400000 828.160000 3117.760000 ;
        RECT 826.560000 3087.200000 828.160000 3090.560000 ;
        RECT 576.560000 3168.800000 578.160000 3172.160000 ;
        RECT 576.560000 3196.000000 578.160000 3199.360000 ;
        RECT 576.560000 3223.200000 578.160000 3226.560000 ;
        RECT 576.560000 3250.400000 578.160000 3253.760000 ;
        RECT 626.560000 3168.800000 628.160000 3172.160000 ;
        RECT 626.560000 3196.000000 628.160000 3199.360000 ;
        RECT 626.560000 3223.200000 628.160000 3226.560000 ;
        RECT 626.560000 3250.400000 628.160000 3253.760000 ;
        RECT 676.560000 3168.800000 678.160000 3172.160000 ;
        RECT 676.560000 3196.000000 678.160000 3199.360000 ;
        RECT 676.560000 3223.200000 678.160000 3226.560000 ;
        RECT 676.560000 3250.400000 678.160000 3253.760000 ;
        RECT 726.560000 3168.800000 728.160000 3172.160000 ;
        RECT 726.560000 3196.000000 728.160000 3199.360000 ;
        RECT 726.560000 3223.200000 728.160000 3226.560000 ;
        RECT 726.560000 3250.400000 728.160000 3253.760000 ;
        RECT 776.560000 3168.800000 778.160000 3172.160000 ;
        RECT 776.560000 3196.000000 778.160000 3199.360000 ;
        RECT 776.560000 3223.200000 778.160000 3226.560000 ;
        RECT 776.560000 3250.400000 778.160000 3253.760000 ;
        RECT 626.560000 3277.600000 628.160000 3280.960000 ;
        RECT 576.560000 3277.600000 578.160000 3280.960000 ;
        RECT 776.560000 3277.600000 778.160000 3280.960000 ;
        RECT 726.560000 3277.600000 728.160000 3280.960000 ;
        RECT 676.560000 3277.600000 678.160000 3280.960000 ;
        RECT 876.560000 3250.400000 878.160000 3253.760000 ;
        RECT 876.560000 3223.200000 878.160000 3226.560000 ;
        RECT 876.560000 3196.000000 878.160000 3199.360000 ;
        RECT 876.560000 3168.800000 878.160000 3172.160000 ;
        RECT 826.560000 3250.400000 828.160000 3253.760000 ;
        RECT 826.560000 3223.200000 828.160000 3226.560000 ;
        RECT 826.560000 3196.000000 828.160000 3199.360000 ;
        RECT 826.560000 3168.800000 828.160000 3172.160000 ;
        RECT 876.560000 3277.600000 878.160000 3280.960000 ;
        RECT 826.560000 3277.600000 828.160000 3280.960000 ;
      LAYER met5 ;
        RECT 4.040000 421.600000 2823.120000 424.960000 ;
        RECT 4.040000 40.800000 2823.120000 44.160000 ;
        RECT 0.000000 4.080000 2827.160000 12.240000 ;
        RECT 4.040000 95.200000 2823.120000 98.560000 ;
        RECT 4.040000 68.000000 2823.120000 71.360000 ;
        RECT 4.040000 149.600000 2823.120000 152.960000 ;
        RECT 4.040000 122.400000 2823.120000 125.760000 ;
        RECT 4.040000 204.000000 2823.120000 207.360000 ;
        RECT 4.040000 176.800000 2823.120000 180.160000 ;
        RECT 4.040000 258.400000 2823.120000 261.760000 ;
        RECT 4.040000 231.200000 2823.120000 234.560000 ;
        RECT 4.040000 312.800000 2823.120000 316.160000 ;
        RECT 4.040000 285.600000 2823.120000 288.960000 ;
        RECT 4.040000 367.200000 2823.120000 370.560000 ;
        RECT 4.040000 340.000000 2823.120000 343.360000 ;
        RECT 4.040000 394.400000 2823.120000 397.760000 ;
        RECT 4.040000 448.800000 2823.120000 452.160000 ;
        RECT 4.040000 503.200000 2823.120000 506.560000 ;
        RECT 4.040000 476.000000 2823.120000 479.360000 ;
        RECT 4.040000 557.600000 2823.120000 560.960000 ;
        RECT 4.040000 530.400000 2823.120000 533.760000 ;
        RECT 4.040000 612.000000 2823.120000 615.360000 ;
        RECT 4.040000 584.800000 2823.120000 588.160000 ;
        RECT 4.040000 666.400000 2823.120000 669.760000 ;
        RECT 4.040000 639.200000 2823.120000 642.560000 ;
        RECT 4.040000 720.800000 2823.120000 724.160000 ;
        RECT 4.040000 693.600000 2823.120000 696.960000 ;
        RECT 4.040000 748.000000 2823.120000 751.360000 ;
        RECT 4.040000 775.200000 2823.120000 778.560000 ;
        RECT 4.040000 802.400000 2823.120000 805.760000 ;
        RECT 4.040000 829.600000 2823.120000 832.960000 ;
        RECT 4.040000 1264.800000 2823.120000 1268.160000 ;
        RECT 4.040000 884.000000 2823.120000 887.360000 ;
        RECT 4.040000 856.800000 2823.120000 860.160000 ;
        RECT 4.040000 938.400000 2823.120000 941.760000 ;
        RECT 4.040000 911.200000 2823.120000 914.560000 ;
        RECT 4.040000 992.800000 2823.120000 996.160000 ;
        RECT 4.040000 965.600000 2823.120000 968.960000 ;
        RECT 4.040000 1047.200000 2823.120000 1050.560000 ;
        RECT 4.040000 1020.000000 2823.120000 1023.360000 ;
        RECT 4.040000 1101.600000 2823.120000 1104.960000 ;
        RECT 4.040000 1074.400000 2823.120000 1077.760000 ;
        RECT 4.040000 1156.000000 2823.120000 1159.360000 ;
        RECT 4.040000 1128.800000 2823.120000 1132.160000 ;
        RECT 4.040000 1210.400000 2823.120000 1213.760000 ;
        RECT 4.040000 1183.200000 2823.120000 1186.560000 ;
        RECT 4.040000 1237.600000 2823.120000 1240.960000 ;
        RECT 4.040000 1319.200000 2823.120000 1322.560000 ;
        RECT 4.040000 1292.000000 2823.120000 1295.360000 ;
        RECT 4.040000 1346.400000 2823.120000 1349.760000 ;
        RECT 4.040000 1400.800000 2823.120000 1404.160000 ;
        RECT 4.040000 1373.600000 2823.120000 1376.960000 ;
        RECT 4.040000 1455.200000 2823.120000 1458.560000 ;
        RECT 4.040000 1428.000000 2823.120000 1431.360000 ;
        RECT 4.040000 1509.600000 2823.120000 1512.960000 ;
        RECT 4.040000 1482.400000 2823.120000 1485.760000 ;
        RECT 4.040000 1564.000000 2823.120000 1567.360000 ;
        RECT 4.040000 1536.800000 2823.120000 1540.160000 ;
        RECT 4.040000 1618.400000 2823.120000 1621.760000 ;
        RECT 4.040000 1591.200000 2823.120000 1594.560000 ;
        RECT 4.040000 1645.600000 2823.120000 1648.960000 ;
        RECT 4.040000 1672.800000 2823.120000 1676.160000 ;
        RECT 4.040000 2108.000000 2823.120000 2111.360000 ;
        RECT 4.040000 1700.000000 2823.120000 1703.360000 ;
        RECT 4.040000 1727.200000 2823.120000 1730.560000 ;
        RECT 4.040000 1754.400000 2823.120000 1757.760000 ;
        RECT 4.040000 1781.600000 2823.120000 1784.960000 ;
        RECT 4.040000 1808.800000 2823.120000 1812.160000 ;
        RECT 4.040000 1836.000000 2823.120000 1839.360000 ;
        RECT 4.040000 1863.200000 2823.120000 1866.560000 ;
        RECT 4.040000 1890.400000 2823.120000 1893.760000 ;
        RECT 4.040000 1917.600000 2823.120000 1920.960000 ;
        RECT 4.040000 1944.800000 2823.120000 1948.160000 ;
        RECT 4.040000 1972.000000 2823.120000 1975.360000 ;
        RECT 4.040000 1999.200000 2823.120000 2002.560000 ;
        RECT 4.040000 2026.400000 2823.120000 2029.760000 ;
        RECT 4.040000 2053.600000 2823.120000 2056.960000 ;
        RECT 4.040000 2080.800000 2823.120000 2084.160000 ;
        RECT 4.040000 2162.400000 2823.120000 2165.760000 ;
        RECT 4.040000 2135.200000 2823.120000 2138.560000 ;
        RECT 4.040000 2189.600000 2823.120000 2192.960000 ;
        RECT 4.040000 2216.800000 2823.120000 2220.160000 ;
        RECT 4.040000 2244.000000 2823.120000 2247.360000 ;
        RECT 4.040000 2271.200000 2823.120000 2274.560000 ;
        RECT 4.040000 2298.400000 2823.120000 2301.760000 ;
        RECT 4.040000 2325.600000 2823.120000 2328.960000 ;
        RECT 4.040000 2352.800000 2823.120000 2356.160000 ;
        RECT 4.040000 2380.000000 2823.120000 2383.360000 ;
        RECT 4.040000 2407.200000 2823.120000 2410.560000 ;
        RECT 4.040000 2434.400000 2823.120000 2437.760000 ;
        RECT 4.040000 2461.600000 2823.120000 2464.960000 ;
        RECT 4.040000 2516.000000 2823.120000 2519.360000 ;
        RECT 4.040000 2488.800000 2823.120000 2492.160000 ;
        RECT 4.040000 2570.400000 2823.120000 2573.760000 ;
        RECT 4.040000 2543.200000 2823.120000 2546.560000 ;
        RECT 4.040000 2624.800000 2823.120000 2628.160000 ;
        RECT 4.040000 2597.600000 2823.120000 2600.960000 ;
        RECT 4.040000 2679.200000 2823.120000 2682.560000 ;
        RECT 4.040000 2652.000000 2823.120000 2655.360000 ;
        RECT 4.040000 2733.600000 2823.120000 2736.960000 ;
        RECT 4.040000 2706.400000 2823.120000 2709.760000 ;
        RECT 4.040000 2788.000000 2823.120000 2791.360000 ;
        RECT 4.040000 2760.800000 2823.120000 2764.160000 ;
        RECT 4.040000 2842.400000 2823.120000 2845.760000 ;
        RECT 4.040000 2815.200000 2823.120000 2818.560000 ;
        RECT 4.040000 2896.800000 2823.120000 2900.160000 ;
        RECT 4.040000 2869.600000 2823.120000 2872.960000 ;
        RECT 4.040000 2951.200000 2823.120000 2954.560000 ;
        RECT 4.040000 2924.000000 2823.120000 2927.360000 ;
        RECT 4.040000 3060.000000 2823.120000 3063.360000 ;
        RECT 4.040000 3005.600000 2823.120000 3008.960000 ;
        RECT 4.040000 2978.400000 2823.120000 2981.760000 ;
        RECT 4.040000 3032.800000 2823.120000 3036.160000 ;
        RECT 4.040000 3087.200000 2823.120000 3090.560000 ;
        RECT 4.040000 3141.600000 2823.120000 3144.960000 ;
        RECT 4.040000 3114.400000 2823.120000 3117.760000 ;
        RECT 4.040000 3196.000000 2823.120000 3199.360000 ;
        RECT 4.040000 3168.800000 2823.120000 3172.160000 ;
        RECT 4.040000 3250.400000 2823.120000 3253.760000 ;
        RECT 4.040000 3223.200000 2823.120000 3226.560000 ;
        RECT 4.040000 3304.800000 2823.120000 3308.160000 ;
        RECT 4.040000 3277.600000 2823.120000 3280.960000 ;
        RECT 0.000000 3363.280000 2827.160000 3371.440000 ;
        RECT 4.040000 3332.000000 2823.120000 3335.360000 ;
        RECT 126.560000 423.950000 128.160000 425.370000 ;
        RECT 176.560000 423.950000 178.160000 425.370000 ;
        RECT 226.560000 423.950000 228.160000 425.370000 ;
        RECT 276.560000 423.950000 278.160000 425.370000 ;
        RECT 326.560000 423.950000 328.160000 425.370000 ;
        RECT 376.560000 423.950000 378.160000 425.370000 ;
        RECT 426.560000 423.950000 428.160000 425.370000 ;
        RECT 1824.560000 423.950000 1826.160000 425.370000 ;
        RECT 1874.560000 423.950000 1876.160000 425.370000 ;
        RECT 1924.560000 423.950000 1926.160000 425.370000 ;
        RECT 1974.560000 423.950000 1976.160000 425.370000 ;
        RECT 2024.560000 423.950000 2026.160000 425.370000 ;
        RECT 2074.560000 423.950000 2076.160000 425.370000 ;
        RECT 2124.560000 423.950000 2126.160000 425.370000 ;
    END
# end of P/G power stripe data as pin

  END VSS
  PIN VDD
    DIRECTION INOUT ;
    USE POWER ;
    PORT
      LAYER met4 ;
        RECT 2802.720000 3369.060000 2810.880000 3377.220000 ;
    END
    PORT
      LAYER met4 ;
        RECT 2802.720000 0.000000 2810.880000 8.160000 ;
    END
    PORT
      LAYER met4 ;
        RECT 16.280000 3369.060000 24.440000 3377.220000 ;
    END
    PORT
      LAYER met4 ;
        RECT 16.280000 0.000000 24.440000 8.160000 ;
    END
    PORT
      LAYER met5 ;
        RECT 2819.000000 3351.040000 2827.160000 3359.200000 ;
    END
    PORT
      LAYER met5 ;
        RECT 0.000000 3351.040000 8.160000 3359.200000 ;
    END
    PORT
      LAYER met5 ;
        RECT 2819.000000 16.320000 2827.160000 24.480000 ;
    END
    PORT
      LAYER met5 ;
        RECT 0.000000 16.320000 8.160000 24.480000 ;
    END

# P/G power stripe data as pin
    PORT
      LAYER met4 ;
        RECT 16.280000 0.000000 24.440000 3377.220000 ;
        RECT 27.200000 16.320000 30.560000 3359.200000 ;
        RECT 54.400000 16.320000 57.760000 3359.200000 ;
        RECT 81.600000 16.320000 84.960000 3359.200000 ;
        RECT 979.200000 16.320000 982.560000 3359.200000 ;
        RECT 952.000000 347.205000 955.360000 3359.200000 ;
        RECT 924.800000 347.205000 928.160000 3359.200000 ;
        RECT 1196.800000 16.320000 1200.160000 3359.200000 ;
        RECT 1169.600000 16.320000 1172.960000 3359.200000 ;
        RECT 1142.400000 16.320000 1145.760000 3359.200000 ;
        RECT 1115.200000 16.320000 1118.560000 3359.200000 ;
        RECT 1088.000000 16.320000 1091.360000 3359.200000 ;
        RECT 1060.800000 16.320000 1064.160000 3359.200000 ;
        RECT 1033.600000 16.320000 1036.960000 3359.200000 ;
        RECT 1006.400000 16.320000 1009.760000 3359.200000 ;
        RECT 1387.200000 16.320000 1390.560000 3359.200000 ;
        RECT 1224.000000 16.320000 1227.360000 3359.200000 ;
        RECT 1251.200000 16.320000 1254.560000 3359.200000 ;
        RECT 1278.400000 16.320000 1281.760000 3359.200000 ;
        RECT 1305.600000 16.320000 1308.960000 3359.200000 ;
        RECT 1332.800000 16.320000 1336.160000 3359.200000 ;
        RECT 1360.000000 16.320000 1363.360000 3359.200000 ;
        RECT 2257.600000 16.320000 2260.960000 3359.200000 ;
        RECT 1414.400000 16.320000 1417.760000 3359.200000 ;
        RECT 1441.600000 16.320000 1444.960000 3359.200000 ;
        RECT 1468.800000 16.320000 1472.160000 3359.200000 ;
        RECT 1496.000000 16.320000 1499.360000 3359.200000 ;
        RECT 1523.200000 16.320000 1526.560000 3359.200000 ;
        RECT 1550.400000 16.320000 1553.760000 3359.200000 ;
        RECT 1577.600000 16.320000 1580.960000 3359.200000 ;
        RECT 1604.800000 16.320000 1608.160000 3359.200000 ;
        RECT 1795.200000 16.320000 1798.560000 3359.200000 ;
        RECT 1822.400000 448.765000 1825.760000 3359.200000 ;
        RECT 1632.000000 16.320000 1635.360000 3359.200000 ;
        RECT 1659.200000 16.320000 1662.560000 3359.200000 ;
        RECT 1686.400000 16.320000 1689.760000 3359.200000 ;
        RECT 1713.600000 16.320000 1716.960000 3359.200000 ;
        RECT 1740.800000 16.320000 1744.160000 3359.200000 ;
        RECT 1768.000000 16.320000 1771.360000 3359.200000 ;
        RECT 1849.600000 448.765000 1852.960000 3359.200000 ;
        RECT 1876.800000 448.765000 1880.160000 3359.200000 ;
        RECT 1904.000000 448.765000 1907.360000 3359.200000 ;
        RECT 1931.200000 448.765000 1934.560000 3359.200000 ;
        RECT 1958.400000 448.765000 1961.760000 3359.200000 ;
        RECT 1985.600000 448.765000 1988.960000 3359.200000 ;
        RECT 2012.800000 448.765000 2016.160000 3359.200000 ;
        RECT 2040.000000 448.765000 2043.360000 3359.200000 ;
        RECT 2230.400000 16.320000 2233.760000 3359.200000 ;
        RECT 2067.200000 448.765000 2070.560000 3359.200000 ;
        RECT 2094.400000 448.765000 2097.760000 3359.200000 ;
        RECT 2121.600000 448.765000 2124.960000 3359.200000 ;
        RECT 2148.800000 448.765000 2152.160000 3359.200000 ;
        RECT 2176.000000 16.320000 2179.360000 3359.200000 ;
        RECT 2203.200000 16.320000 2206.560000 3359.200000 ;
        RECT 2448.000000 347.205000 2451.360000 3359.200000 ;
        RECT 2420.800000 347.205000 2424.160000 3359.200000 ;
        RECT 2393.600000 347.205000 2396.960000 3359.200000 ;
        RECT 2366.400000 347.205000 2369.760000 3359.200000 ;
        RECT 2339.200000 347.205000 2342.560000 3359.200000 ;
        RECT 2312.000000 347.205000 2315.360000 3359.200000 ;
        RECT 2284.800000 16.320000 2288.160000 3359.200000 ;
        RECT 2502.400000 347.205000 2505.760000 3359.200000 ;
        RECT 2475.200000 347.205000 2478.560000 3359.200000 ;
        RECT 2529.600000 347.205000 2532.960000 3359.200000 ;
        RECT 2556.800000 347.205000 2560.160000 3359.200000 ;
        RECT 2584.000000 347.205000 2587.360000 3359.200000 ;
        RECT 2611.200000 347.205000 2614.560000 3359.200000 ;
        RECT 2638.400000 347.205000 2641.760000 3359.200000 ;
        RECT 2665.600000 16.320000 2668.960000 3359.200000 ;
        RECT 2774.400000 16.320000 2777.760000 3359.200000 ;
        RECT 2747.200000 16.320000 2750.560000 3359.200000 ;
        RECT 2720.000000 16.320000 2723.360000 3359.200000 ;
        RECT 2692.800000 16.320000 2696.160000 3359.200000 ;
        RECT 2802.720000 0.000000 2810.880000 3377.220000 ;
        RECT 108.800000 448.765000 112.160000 1635.875000 ;
        RECT 136.000000 448.765000 139.360000 1635.875000 ;
        RECT 353.600000 448.765000 356.960000 1635.875000 ;
        RECT 326.400000 448.765000 329.760000 1635.875000 ;
        RECT 299.200000 448.765000 302.560000 1635.875000 ;
        RECT 272.000000 448.765000 275.360000 1635.875000 ;
        RECT 244.800000 448.765000 248.160000 1635.875000 ;
        RECT 217.600000 448.765000 220.960000 1635.875000 ;
        RECT 190.400000 448.765000 193.760000 1635.875000 ;
        RECT 163.200000 448.765000 166.560000 1635.875000 ;
        RECT 544.000000 16.320000 547.360000 1635.875000 ;
        RECT 435.200000 448.765000 438.560000 1635.875000 ;
        RECT 408.000000 448.765000 411.360000 1635.875000 ;
        RECT 380.800000 448.765000 384.160000 1635.875000 ;
        RECT 462.400000 16.320000 465.760000 1635.875000 ;
        RECT 489.600000 16.320000 492.960000 1635.875000 ;
        RECT 516.800000 16.320000 520.160000 1635.875000 ;
        RECT 598.400000 16.320000 601.760000 1635.875000 ;
        RECT 571.200000 16.320000 574.560000 1635.875000 ;
        RECT 761.600000 347.205000 764.960000 1635.875000 ;
        RECT 734.400000 347.205000 737.760000 1635.875000 ;
        RECT 707.200000 347.205000 710.560000 1635.875000 ;
        RECT 680.000000 347.205000 683.360000 1635.875000 ;
        RECT 652.800000 347.205000 656.160000 1635.875000 ;
        RECT 625.600000 347.205000 628.960000 1635.875000 ;
        RECT 897.600000 347.205000 900.960000 1635.875000 ;
        RECT 870.400000 347.205000 873.760000 1635.875000 ;
        RECT 843.200000 347.205000 846.560000 1635.875000 ;
        RECT 816.000000 347.205000 819.360000 1635.875000 ;
        RECT 788.800000 347.205000 792.160000 1635.875000 ;
        RECT 136.000000 191.205000 139.360000 246.875000 ;
        RECT 108.800000 191.205000 112.160000 246.875000 ;
        RECT 136.000000 16.320000 139.360000 90.875000 ;
        RECT 108.800000 16.320000 112.160000 90.875000 ;
        RECT 136.000000 347.205000 139.360000 421.875000 ;
        RECT 108.800000 347.205000 112.160000 421.875000 ;
        RECT 435.200000 191.205000 438.560000 246.875000 ;
        RECT 408.000000 191.205000 411.360000 246.875000 ;
        RECT 380.800000 191.205000 384.160000 246.875000 ;
        RECT 353.600000 191.205000 356.960000 246.875000 ;
        RECT 326.400000 191.205000 329.760000 246.875000 ;
        RECT 299.200000 191.205000 302.560000 246.875000 ;
        RECT 272.000000 191.205000 275.360000 246.875000 ;
        RECT 244.800000 191.205000 248.160000 246.875000 ;
        RECT 217.600000 191.205000 220.960000 246.875000 ;
        RECT 190.400000 191.205000 193.760000 246.875000 ;
        RECT 163.200000 191.205000 166.560000 246.875000 ;
        RECT 244.800000 16.320000 248.160000 90.875000 ;
        RECT 217.600000 16.320000 220.960000 90.875000 ;
        RECT 190.400000 16.320000 193.760000 90.875000 ;
        RECT 163.200000 16.320000 166.560000 90.875000 ;
        RECT 353.600000 16.320000 356.960000 90.875000 ;
        RECT 326.400000 16.320000 329.760000 90.875000 ;
        RECT 299.200000 16.320000 302.560000 90.875000 ;
        RECT 272.000000 16.320000 275.360000 90.875000 ;
        RECT 435.200000 16.320000 438.560000 90.875000 ;
        RECT 408.000000 16.320000 411.360000 90.875000 ;
        RECT 380.800000 16.320000 384.160000 90.875000 ;
        RECT 244.800000 347.205000 248.160000 421.875000 ;
        RECT 217.600000 347.205000 220.960000 421.875000 ;
        RECT 190.400000 347.205000 193.760000 421.875000 ;
        RECT 163.200000 347.205000 166.560000 421.875000 ;
        RECT 353.600000 347.205000 356.960000 421.875000 ;
        RECT 326.400000 347.205000 329.760000 421.875000 ;
        RECT 299.200000 347.205000 302.560000 421.875000 ;
        RECT 272.000000 347.205000 275.360000 421.875000 ;
        RECT 435.200000 347.205000 438.560000 421.875000 ;
        RECT 408.000000 347.205000 411.360000 421.875000 ;
        RECT 380.800000 347.205000 384.160000 421.875000 ;
        RECT 952.000000 191.205000 955.360000 246.875000 ;
        RECT 924.800000 191.205000 928.160000 246.875000 ;
        RECT 897.600000 191.205000 900.960000 246.875000 ;
        RECT 870.400000 191.205000 873.760000 246.875000 ;
        RECT 843.200000 191.205000 846.560000 246.875000 ;
        RECT 816.000000 191.205000 819.360000 246.875000 ;
        RECT 788.800000 191.205000 792.160000 246.875000 ;
        RECT 761.600000 191.205000 764.960000 246.875000 ;
        RECT 734.400000 191.205000 737.760000 246.875000 ;
        RECT 707.200000 191.205000 710.560000 246.875000 ;
        RECT 680.000000 191.205000 683.360000 246.875000 ;
        RECT 652.800000 191.205000 656.160000 246.875000 ;
        RECT 625.600000 191.205000 628.960000 246.875000 ;
        RECT 652.800000 16.320000 656.160000 90.875000 ;
        RECT 625.600000 16.320000 628.960000 90.875000 ;
        RECT 761.600000 16.320000 764.960000 90.875000 ;
        RECT 734.400000 16.320000 737.760000 90.875000 ;
        RECT 707.200000 16.320000 710.560000 90.875000 ;
        RECT 680.000000 16.320000 683.360000 90.875000 ;
        RECT 870.400000 16.320000 873.760000 90.875000 ;
        RECT 843.200000 16.320000 846.560000 90.875000 ;
        RECT 816.000000 16.320000 819.360000 90.875000 ;
        RECT 788.800000 16.320000 792.160000 90.875000 ;
        RECT 952.000000 16.320000 955.360000 90.875000 ;
        RECT 924.800000 16.320000 928.160000 90.875000 ;
        RECT 897.600000 16.320000 900.960000 90.875000 ;
        RECT 1822.400000 191.205000 1825.760000 246.875000 ;
        RECT 1822.400000 16.320000 1825.760000 90.875000 ;
        RECT 1822.400000 347.205000 1825.760000 421.875000 ;
        RECT 2148.800000 191.205000 2152.160000 246.875000 ;
        RECT 2121.600000 191.205000 2124.960000 246.875000 ;
        RECT 2094.400000 191.205000 2097.760000 246.875000 ;
        RECT 2067.200000 191.205000 2070.560000 246.875000 ;
        RECT 2040.000000 191.205000 2043.360000 246.875000 ;
        RECT 2012.800000 191.205000 2016.160000 246.875000 ;
        RECT 1985.600000 191.205000 1988.960000 246.875000 ;
        RECT 1958.400000 191.205000 1961.760000 246.875000 ;
        RECT 1931.200000 191.205000 1934.560000 246.875000 ;
        RECT 1904.000000 191.205000 1907.360000 246.875000 ;
        RECT 1876.800000 191.205000 1880.160000 246.875000 ;
        RECT 1849.600000 191.205000 1852.960000 246.875000 ;
        RECT 1931.200000 16.320000 1934.560000 90.875000 ;
        RECT 1904.000000 16.320000 1907.360000 90.875000 ;
        RECT 1876.800000 16.320000 1880.160000 90.875000 ;
        RECT 1849.600000 16.320000 1852.960000 90.875000 ;
        RECT 2040.000000 16.320000 2043.360000 90.875000 ;
        RECT 2012.800000 16.320000 2016.160000 90.875000 ;
        RECT 1985.600000 16.320000 1988.960000 90.875000 ;
        RECT 1958.400000 16.320000 1961.760000 90.875000 ;
        RECT 2148.800000 16.320000 2152.160000 90.875000 ;
        RECT 2121.600000 16.320000 2124.960000 90.875000 ;
        RECT 2094.400000 16.320000 2097.760000 90.875000 ;
        RECT 2067.200000 16.320000 2070.560000 90.875000 ;
        RECT 1931.200000 347.205000 1934.560000 421.875000 ;
        RECT 1904.000000 347.205000 1907.360000 421.875000 ;
        RECT 1876.800000 347.205000 1880.160000 421.875000 ;
        RECT 1849.600000 347.205000 1852.960000 421.875000 ;
        RECT 2040.000000 347.205000 2043.360000 421.875000 ;
        RECT 2012.800000 347.205000 2016.160000 421.875000 ;
        RECT 1985.600000 347.205000 1988.960000 421.875000 ;
        RECT 1958.400000 347.205000 1961.760000 421.875000 ;
        RECT 2148.800000 347.205000 2152.160000 421.875000 ;
        RECT 2121.600000 347.205000 2124.960000 421.875000 ;
        RECT 2094.400000 347.205000 2097.760000 421.875000 ;
        RECT 2067.200000 347.205000 2070.560000 421.875000 ;
        RECT 2638.400000 191.205000 2641.760000 246.875000 ;
        RECT 2611.200000 191.205000 2614.560000 246.875000 ;
        RECT 2584.000000 191.205000 2587.360000 246.875000 ;
        RECT 2556.800000 191.205000 2560.160000 246.875000 ;
        RECT 2529.600000 191.205000 2532.960000 246.875000 ;
        RECT 2502.400000 191.205000 2505.760000 246.875000 ;
        RECT 2475.200000 191.205000 2478.560000 246.875000 ;
        RECT 2448.000000 191.205000 2451.360000 246.875000 ;
        RECT 2420.800000 191.205000 2424.160000 246.875000 ;
        RECT 2393.600000 191.205000 2396.960000 246.875000 ;
        RECT 2366.400000 191.205000 2369.760000 246.875000 ;
        RECT 2339.200000 191.205000 2342.560000 246.875000 ;
        RECT 2312.000000 191.205000 2315.360000 246.875000 ;
        RECT 2339.200000 16.320000 2342.560000 90.875000 ;
        RECT 2312.000000 16.320000 2315.360000 90.875000 ;
        RECT 2448.000000 16.320000 2451.360000 90.875000 ;
        RECT 2420.800000 16.320000 2424.160000 90.875000 ;
        RECT 2393.600000 16.320000 2396.960000 90.875000 ;
        RECT 2366.400000 16.320000 2369.760000 90.875000 ;
        RECT 2556.800000 16.320000 2560.160000 90.875000 ;
        RECT 2529.600000 16.320000 2532.960000 90.875000 ;
        RECT 2502.400000 16.320000 2505.760000 90.875000 ;
        RECT 2475.200000 16.320000 2478.560000 90.875000 ;
        RECT 2638.400000 16.320000 2641.760000 90.875000 ;
        RECT 2611.200000 16.320000 2614.560000 90.875000 ;
        RECT 2584.000000 16.320000 2587.360000 90.875000 ;
        RECT 136.000000 2424.365000 139.360000 2510.875000 ;
        RECT 108.800000 2424.365000 112.160000 2510.875000 ;
        RECT 353.600000 2424.365000 356.960000 2510.875000 ;
        RECT 326.400000 2424.365000 329.760000 2510.875000 ;
        RECT 299.200000 2424.365000 302.560000 2510.875000 ;
        RECT 272.000000 2424.365000 275.360000 2510.875000 ;
        RECT 244.800000 2424.365000 248.160000 2510.875000 ;
        RECT 217.600000 2424.365000 220.960000 2510.875000 ;
        RECT 190.400000 2424.365000 193.760000 2510.875000 ;
        RECT 163.200000 2424.365000 166.560000 2510.875000 ;
        RECT 544.000000 2424.365000 547.360000 2510.875000 ;
        RECT 516.800000 2424.365000 520.160000 2510.875000 ;
        RECT 489.600000 2424.365000 492.960000 2510.875000 ;
        RECT 462.400000 2424.365000 465.760000 2510.875000 ;
        RECT 435.200000 2424.365000 438.560000 2510.875000 ;
        RECT 408.000000 2424.365000 411.360000 2510.875000 ;
        RECT 380.800000 2424.365000 384.160000 2510.875000 ;
        RECT 761.600000 2424.365000 764.960000 2510.875000 ;
        RECT 734.400000 2424.365000 737.760000 2510.875000 ;
        RECT 707.200000 2424.365000 710.560000 2510.875000 ;
        RECT 680.000000 2424.365000 683.360000 2510.875000 ;
        RECT 652.800000 2424.365000 656.160000 2510.875000 ;
        RECT 625.600000 2424.365000 628.960000 2510.875000 ;
        RECT 598.400000 2424.365000 601.760000 2510.875000 ;
        RECT 571.200000 2424.365000 574.560000 2510.875000 ;
        RECT 897.600000 2424.365000 900.960000 2510.875000 ;
        RECT 870.400000 2424.365000 873.760000 2510.875000 ;
        RECT 843.200000 2424.365000 846.560000 2510.875000 ;
        RECT 816.000000 2424.365000 819.360000 2510.875000 ;
        RECT 788.800000 2424.365000 792.160000 2510.875000 ;
        RECT 136.000000 3299.365000 139.360000 3359.200000 ;
        RECT 108.800000 3299.365000 112.160000 3359.200000 ;
        RECT 244.800000 3299.365000 248.160000 3359.200000 ;
        RECT 217.600000 3299.365000 220.960000 3359.200000 ;
        RECT 190.400000 3299.365000 193.760000 3359.200000 ;
        RECT 163.200000 3299.365000 166.560000 3359.200000 ;
        RECT 353.600000 3299.365000 356.960000 3359.200000 ;
        RECT 326.400000 3299.365000 329.760000 3359.200000 ;
        RECT 299.200000 3299.365000 302.560000 3359.200000 ;
        RECT 272.000000 3299.365000 275.360000 3359.200000 ;
        RECT 462.400000 3299.365000 465.760000 3359.200000 ;
        RECT 435.200000 3299.365000 438.560000 3359.200000 ;
        RECT 408.000000 3299.365000 411.360000 3359.200000 ;
        RECT 380.800000 3299.365000 384.160000 3359.200000 ;
        RECT 544.000000 3299.365000 547.360000 3359.200000 ;
        RECT 516.800000 3299.365000 520.160000 3359.200000 ;
        RECT 489.600000 3299.365000 492.960000 3359.200000 ;
        RECT 652.800000 3299.365000 656.160000 3359.200000 ;
        RECT 625.600000 3299.365000 628.960000 3359.200000 ;
        RECT 598.400000 3299.365000 601.760000 3359.200000 ;
        RECT 571.200000 3299.365000 574.560000 3359.200000 ;
        RECT 761.600000 3299.365000 764.960000 3359.200000 ;
        RECT 734.400000 3299.365000 737.760000 3359.200000 ;
        RECT 707.200000 3299.365000 710.560000 3359.200000 ;
        RECT 680.000000 3299.365000 683.360000 3359.200000 ;
        RECT 870.400000 3299.365000 873.760000 3359.200000 ;
        RECT 843.200000 3299.365000 846.560000 3359.200000 ;
        RECT 816.000000 3299.365000 819.360000 3359.200000 ;
        RECT 788.800000 3299.365000 792.160000 3359.200000 ;
        RECT 897.600000 3299.365000 900.960000 3359.200000 ;
        RECT 551.560000 1686.400000 553.160000 1689.760000 ;
        RECT 501.560000 1686.400000 503.160000 1689.760000 ;
        RECT 451.560000 1686.400000 453.160000 1689.760000 ;
        RECT 401.560000 1686.400000 403.160000 1689.760000 ;
        RECT 351.560000 1686.400000 353.160000 1689.760000 ;
        RECT 301.560000 1686.400000 303.160000 1689.760000 ;
        RECT 251.560000 1686.400000 253.160000 1689.760000 ;
        RECT 201.560000 1686.400000 203.160000 1689.760000 ;
        RECT 151.560000 1686.400000 153.160000 1689.760000 ;
        RECT 101.560000 1686.400000 103.160000 1689.760000 ;
        RECT 901.560000 1686.400000 903.160000 1689.760000 ;
        RECT 851.560000 1686.400000 853.160000 1689.760000 ;
        RECT 801.560000 1686.400000 803.160000 1689.760000 ;
        RECT 751.560000 1686.400000 753.160000 1689.760000 ;
        RECT 701.560000 1686.400000 703.160000 1689.760000 ;
        RECT 651.560000 1686.400000 653.160000 1689.760000 ;
        RECT 601.560000 1686.400000 603.160000 1689.760000 ;
        RECT 108.560000 136.000000 110.160000 139.360000 ;
        RECT 108.560000 108.800000 110.160000 112.160000 ;
        RECT 108.560000 163.200000 110.160000 166.560000 ;
        RECT 108.560000 299.200000 110.160000 302.560000 ;
        RECT 108.560000 272.000000 110.160000 275.360000 ;
        RECT 108.560000 326.400000 110.160000 329.760000 ;
        RECT 158.560000 108.800000 160.160000 112.160000 ;
        RECT 158.560000 136.000000 160.160000 139.360000 ;
        RECT 158.560000 163.200000 160.160000 166.560000 ;
        RECT 208.560000 108.800000 210.160000 112.160000 ;
        RECT 208.560000 136.000000 210.160000 139.360000 ;
        RECT 208.560000 163.200000 210.160000 166.560000 ;
        RECT 308.560000 163.200000 310.160000 166.560000 ;
        RECT 308.560000 136.000000 310.160000 139.360000 ;
        RECT 258.560000 108.800000 260.160000 112.160000 ;
        RECT 258.560000 136.000000 260.160000 139.360000 ;
        RECT 258.560000 163.200000 260.160000 166.560000 ;
        RECT 308.560000 108.800000 310.160000 112.160000 ;
        RECT 458.560000 163.200000 460.160000 166.560000 ;
        RECT 458.560000 136.000000 460.160000 139.360000 ;
        RECT 458.560000 108.800000 460.160000 112.160000 ;
        RECT 408.560000 163.200000 410.160000 166.560000 ;
        RECT 408.560000 136.000000 410.160000 139.360000 ;
        RECT 408.560000 108.800000 410.160000 112.160000 ;
        RECT 358.560000 163.200000 360.160000 166.560000 ;
        RECT 358.560000 136.000000 360.160000 139.360000 ;
        RECT 358.560000 108.800000 360.160000 112.160000 ;
        RECT 208.560000 299.200000 210.160000 302.560000 ;
        RECT 208.560000 272.000000 210.160000 275.360000 ;
        RECT 158.560000 299.200000 160.160000 302.560000 ;
        RECT 158.560000 272.000000 160.160000 275.360000 ;
        RECT 308.560000 299.200000 310.160000 302.560000 ;
        RECT 308.560000 272.000000 310.160000 275.360000 ;
        RECT 258.560000 299.200000 260.160000 302.560000 ;
        RECT 258.560000 272.000000 260.160000 275.360000 ;
        RECT 208.560000 326.400000 210.160000 329.760000 ;
        RECT 158.560000 326.400000 160.160000 329.760000 ;
        RECT 308.560000 326.400000 310.160000 329.760000 ;
        RECT 258.560000 326.400000 260.160000 329.760000 ;
        RECT 458.560000 299.200000 460.160000 302.560000 ;
        RECT 458.560000 272.000000 460.160000 275.360000 ;
        RECT 408.560000 299.200000 410.160000 302.560000 ;
        RECT 408.560000 272.000000 410.160000 275.360000 ;
        RECT 358.560000 299.200000 360.160000 302.560000 ;
        RECT 358.560000 272.000000 360.160000 275.360000 ;
        RECT 458.560000 326.400000 460.160000 329.760000 ;
        RECT 408.560000 326.400000 410.160000 329.760000 ;
        RECT 358.560000 326.400000 360.160000 329.760000 ;
        RECT 101.560000 435.200000 103.160000 438.560000 ;
        RECT 251.560000 435.200000 253.160000 438.560000 ;
        RECT 151.560000 435.200000 153.160000 438.560000 ;
        RECT 201.560000 435.200000 203.160000 438.560000 ;
        RECT 301.560000 435.200000 303.160000 438.560000 ;
        RECT 351.560000 435.200000 353.160000 438.560000 ;
        RECT 401.560000 435.200000 403.160000 438.560000 ;
        RECT 451.560000 435.200000 453.160000 438.560000 ;
        RECT 664.560000 163.200000 666.160000 166.560000 ;
        RECT 664.560000 136.000000 666.160000 139.360000 ;
        RECT 664.560000 108.800000 666.160000 112.160000 ;
        RECT 614.560000 163.200000 616.160000 166.560000 ;
        RECT 614.560000 108.800000 616.160000 112.160000 ;
        RECT 614.560000 136.000000 616.160000 139.360000 ;
        RECT 764.560000 163.200000 766.160000 166.560000 ;
        RECT 764.560000 136.000000 766.160000 139.360000 ;
        RECT 764.560000 108.800000 766.160000 112.160000 ;
        RECT 714.560000 163.200000 716.160000 166.560000 ;
        RECT 714.560000 136.000000 716.160000 139.360000 ;
        RECT 714.560000 108.800000 716.160000 112.160000 ;
        RECT 814.560000 108.800000 816.160000 112.160000 ;
        RECT 814.560000 136.000000 816.160000 139.360000 ;
        RECT 814.560000 163.200000 816.160000 166.560000 ;
        RECT 864.560000 108.800000 866.160000 112.160000 ;
        RECT 864.560000 136.000000 866.160000 139.360000 ;
        RECT 864.560000 163.200000 866.160000 166.560000 ;
        RECT 964.560000 163.200000 966.160000 166.560000 ;
        RECT 964.560000 136.000000 966.160000 139.360000 ;
        RECT 964.560000 108.800000 966.160000 112.160000 ;
        RECT 914.560000 163.200000 916.160000 166.560000 ;
        RECT 914.560000 136.000000 916.160000 139.360000 ;
        RECT 914.560000 108.800000 916.160000 112.160000 ;
        RECT 664.560000 299.200000 666.160000 302.560000 ;
        RECT 664.560000 272.000000 666.160000 275.360000 ;
        RECT 614.560000 299.200000 616.160000 302.560000 ;
        RECT 614.560000 272.000000 616.160000 275.360000 ;
        RECT 764.560000 299.200000 766.160000 302.560000 ;
        RECT 764.560000 272.000000 766.160000 275.360000 ;
        RECT 714.560000 299.200000 716.160000 302.560000 ;
        RECT 714.560000 272.000000 716.160000 275.360000 ;
        RECT 664.560000 326.400000 666.160000 329.760000 ;
        RECT 614.560000 326.400000 616.160000 329.760000 ;
        RECT 764.560000 326.400000 766.160000 329.760000 ;
        RECT 714.560000 326.400000 716.160000 329.760000 ;
        RECT 864.560000 299.200000 866.160000 302.560000 ;
        RECT 864.560000 272.000000 866.160000 275.360000 ;
        RECT 814.560000 299.200000 816.160000 302.560000 ;
        RECT 814.560000 272.000000 816.160000 275.360000 ;
        RECT 964.560000 299.200000 966.160000 302.560000 ;
        RECT 964.560000 272.000000 966.160000 275.360000 ;
        RECT 914.560000 299.200000 916.160000 302.560000 ;
        RECT 914.560000 272.000000 916.160000 275.360000 ;
        RECT 864.560000 326.400000 866.160000 329.760000 ;
        RECT 814.560000 326.400000 816.160000 329.760000 ;
        RECT 964.560000 326.400000 966.160000 329.760000 ;
        RECT 914.560000 326.400000 916.160000 329.760000 ;
        RECT 101.560000 1659.200000 103.160000 1662.560000 ;
        RECT 251.560000 1659.200000 253.160000 1662.560000 ;
        RECT 201.560000 1659.200000 203.160000 1662.560000 ;
        RECT 151.560000 1659.200000 153.160000 1662.560000 ;
        RECT 351.560000 1659.200000 353.160000 1662.560000 ;
        RECT 301.560000 1659.200000 303.160000 1662.560000 ;
        RECT 451.560000 1659.200000 453.160000 1662.560000 ;
        RECT 401.560000 1659.200000 403.160000 1662.560000 ;
        RECT 551.560000 1659.200000 553.160000 1662.560000 ;
        RECT 501.560000 1659.200000 503.160000 1662.560000 ;
        RECT 651.560000 1659.200000 653.160000 1662.560000 ;
        RECT 601.560000 1659.200000 603.160000 1662.560000 ;
        RECT 751.560000 1659.200000 753.160000 1662.560000 ;
        RECT 701.560000 1659.200000 703.160000 1662.560000 ;
        RECT 851.560000 1659.200000 853.160000 1662.560000 ;
        RECT 801.560000 1659.200000 803.160000 1662.560000 ;
        RECT 901.560000 1659.200000 903.160000 1662.560000 ;
        RECT 1799.560000 136.000000 1801.160000 139.360000 ;
        RECT 1799.560000 108.800000 1801.160000 112.160000 ;
        RECT 1799.560000 163.200000 1801.160000 166.560000 ;
        RECT 1799.560000 299.200000 1801.160000 302.560000 ;
        RECT 1799.560000 272.000000 1801.160000 275.360000 ;
        RECT 1799.560000 326.400000 1801.160000 329.760000 ;
        RECT 1849.560000 108.800000 1851.160000 112.160000 ;
        RECT 1849.560000 136.000000 1851.160000 139.360000 ;
        RECT 1849.560000 163.200000 1851.160000 166.560000 ;
        RECT 1899.560000 108.800000 1901.160000 112.160000 ;
        RECT 1899.560000 136.000000 1901.160000 139.360000 ;
        RECT 1899.560000 163.200000 1901.160000 166.560000 ;
        RECT 1999.560000 163.200000 2001.160000 166.560000 ;
        RECT 1999.560000 136.000000 2001.160000 139.360000 ;
        RECT 1949.560000 108.800000 1951.160000 112.160000 ;
        RECT 1949.560000 136.000000 1951.160000 139.360000 ;
        RECT 1949.560000 163.200000 1951.160000 166.560000 ;
        RECT 1999.560000 108.800000 2001.160000 112.160000 ;
        RECT 2149.560000 163.200000 2151.160000 166.560000 ;
        RECT 2149.560000 136.000000 2151.160000 139.360000 ;
        RECT 2149.560000 108.800000 2151.160000 112.160000 ;
        RECT 2099.560000 163.200000 2101.160000 166.560000 ;
        RECT 2099.560000 136.000000 2101.160000 139.360000 ;
        RECT 2099.560000 108.800000 2101.160000 112.160000 ;
        RECT 2049.560000 163.200000 2051.160000 166.560000 ;
        RECT 2049.560000 136.000000 2051.160000 139.360000 ;
        RECT 2049.560000 108.800000 2051.160000 112.160000 ;
        RECT 1899.560000 299.200000 1901.160000 302.560000 ;
        RECT 1899.560000 272.000000 1901.160000 275.360000 ;
        RECT 1849.560000 299.200000 1851.160000 302.560000 ;
        RECT 1849.560000 272.000000 1851.160000 275.360000 ;
        RECT 1999.560000 299.200000 2001.160000 302.560000 ;
        RECT 1999.560000 272.000000 2001.160000 275.360000 ;
        RECT 1949.560000 299.200000 1951.160000 302.560000 ;
        RECT 1949.560000 272.000000 1951.160000 275.360000 ;
        RECT 1899.560000 326.400000 1901.160000 329.760000 ;
        RECT 1849.560000 326.400000 1851.160000 329.760000 ;
        RECT 1999.560000 326.400000 2001.160000 329.760000 ;
        RECT 1949.560000 326.400000 1951.160000 329.760000 ;
        RECT 2149.560000 299.200000 2151.160000 302.560000 ;
        RECT 2149.560000 272.000000 2151.160000 275.360000 ;
        RECT 2099.560000 299.200000 2101.160000 302.560000 ;
        RECT 2099.560000 272.000000 2101.160000 275.360000 ;
        RECT 2049.560000 299.200000 2051.160000 302.560000 ;
        RECT 2049.560000 272.000000 2051.160000 275.360000 ;
        RECT 2149.560000 326.400000 2151.160000 329.760000 ;
        RECT 2099.560000 326.400000 2101.160000 329.760000 ;
        RECT 2049.560000 326.400000 2051.160000 329.760000 ;
        RECT 1799.560000 435.200000 1801.160000 438.560000 ;
        RECT 1849.560000 435.200000 1851.160000 438.560000 ;
        RECT 1899.560000 435.200000 1901.160000 438.560000 ;
        RECT 1949.560000 435.200000 1951.160000 438.560000 ;
        RECT 1999.560000 435.200000 2001.160000 438.560000 ;
        RECT 2099.560000 435.200000 2101.160000 438.560000 ;
        RECT 2049.560000 435.200000 2051.160000 438.560000 ;
        RECT 2149.560000 435.200000 2151.160000 438.560000 ;
        RECT 2355.560000 163.200000 2357.160000 166.560000 ;
        RECT 2355.560000 136.000000 2357.160000 139.360000 ;
        RECT 2355.560000 108.800000 2357.160000 112.160000 ;
        RECT 2305.560000 108.800000 2307.160000 112.160000 ;
        RECT 2305.560000 136.000000 2307.160000 139.360000 ;
        RECT 2305.560000 163.200000 2307.160000 166.560000 ;
        RECT 2455.560000 163.200000 2457.160000 166.560000 ;
        RECT 2455.560000 136.000000 2457.160000 139.360000 ;
        RECT 2455.560000 108.800000 2457.160000 112.160000 ;
        RECT 2405.560000 163.200000 2407.160000 166.560000 ;
        RECT 2405.560000 136.000000 2407.160000 139.360000 ;
        RECT 2405.560000 108.800000 2407.160000 112.160000 ;
        RECT 2505.560000 108.800000 2507.160000 112.160000 ;
        RECT 2505.560000 136.000000 2507.160000 139.360000 ;
        RECT 2505.560000 163.200000 2507.160000 166.560000 ;
        RECT 2555.560000 108.800000 2557.160000 112.160000 ;
        RECT 2555.560000 136.000000 2557.160000 139.360000 ;
        RECT 2555.560000 163.200000 2557.160000 166.560000 ;
        RECT 2655.560000 163.200000 2657.160000 166.560000 ;
        RECT 2655.560000 136.000000 2657.160000 139.360000 ;
        RECT 2655.560000 108.800000 2657.160000 112.160000 ;
        RECT 2605.560000 163.200000 2607.160000 166.560000 ;
        RECT 2605.560000 136.000000 2607.160000 139.360000 ;
        RECT 2605.560000 108.800000 2607.160000 112.160000 ;
        RECT 2355.560000 299.200000 2357.160000 302.560000 ;
        RECT 2355.560000 272.000000 2357.160000 275.360000 ;
        RECT 2305.560000 299.200000 2307.160000 302.560000 ;
        RECT 2305.560000 272.000000 2307.160000 275.360000 ;
        RECT 2455.560000 299.200000 2457.160000 302.560000 ;
        RECT 2455.560000 272.000000 2457.160000 275.360000 ;
        RECT 2405.560000 299.200000 2407.160000 302.560000 ;
        RECT 2405.560000 272.000000 2407.160000 275.360000 ;
        RECT 2355.560000 326.400000 2357.160000 329.760000 ;
        RECT 2305.560000 326.400000 2307.160000 329.760000 ;
        RECT 2455.560000 326.400000 2457.160000 329.760000 ;
        RECT 2405.560000 326.400000 2407.160000 329.760000 ;
        RECT 2555.560000 299.200000 2557.160000 302.560000 ;
        RECT 2555.560000 272.000000 2557.160000 275.360000 ;
        RECT 2505.560000 299.200000 2507.160000 302.560000 ;
        RECT 2505.560000 272.000000 2507.160000 275.360000 ;
        RECT 2655.560000 299.200000 2657.160000 302.560000 ;
        RECT 2655.560000 272.000000 2657.160000 275.360000 ;
        RECT 2605.560000 299.200000 2607.160000 302.560000 ;
        RECT 2605.560000 272.000000 2607.160000 275.360000 ;
        RECT 2555.560000 326.400000 2557.160000 329.760000 ;
        RECT 2505.560000 326.400000 2507.160000 329.760000 ;
        RECT 2655.560000 326.400000 2657.160000 329.760000 ;
        RECT 2605.560000 326.400000 2607.160000 329.760000 ;
        RECT 551.560000 2529.600000 553.160000 2532.960000 ;
        RECT 501.560000 2529.600000 503.160000 2532.960000 ;
        RECT 101.560000 2529.600000 103.160000 2532.960000 ;
        RECT 151.560000 2529.600000 153.160000 2532.960000 ;
        RECT 201.560000 2529.600000 203.160000 2532.960000 ;
        RECT 251.560000 2529.600000 253.160000 2532.960000 ;
        RECT 301.560000 2529.600000 303.160000 2532.960000 ;
        RECT 351.560000 2529.600000 353.160000 2532.960000 ;
        RECT 401.560000 2529.600000 403.160000 2532.960000 ;
        RECT 451.560000 2529.600000 453.160000 2532.960000 ;
        RECT 901.560000 2529.600000 903.160000 2532.960000 ;
        RECT 851.560000 2529.600000 853.160000 2532.960000 ;
        RECT 801.560000 2529.600000 803.160000 2532.960000 ;
        RECT 751.560000 2529.600000 753.160000 2532.960000 ;
        RECT 701.560000 2529.600000 703.160000 2532.960000 ;
        RECT 651.560000 2529.600000 653.160000 2532.960000 ;
        RECT 601.560000 2529.600000 603.160000 2532.960000 ;
        RECT 101.560000 1768.000000 103.160000 1771.360000 ;
        RECT 101.560000 1740.800000 103.160000 1744.160000 ;
        RECT 101.560000 1713.600000 103.160000 1716.960000 ;
        RECT 101.560000 1876.800000 103.160000 1880.160000 ;
        RECT 101.560000 1849.600000 103.160000 1852.960000 ;
        RECT 101.560000 1822.400000 103.160000 1825.760000 ;
        RECT 101.560000 1795.200000 103.160000 1798.560000 ;
        RECT 101.560000 1985.600000 103.160000 1988.960000 ;
        RECT 101.560000 1958.400000 103.160000 1961.760000 ;
        RECT 101.560000 1931.200000 103.160000 1934.560000 ;
        RECT 101.560000 1904.000000 103.160000 1907.360000 ;
        RECT 101.560000 2094.400000 103.160000 2097.760000 ;
        RECT 101.560000 2067.200000 103.160000 2070.560000 ;
        RECT 101.560000 2040.000000 103.160000 2043.360000 ;
        RECT 101.560000 2012.800000 103.160000 2016.160000 ;
        RECT 251.560000 1768.000000 253.160000 1771.360000 ;
        RECT 251.560000 1740.800000 253.160000 1744.160000 ;
        RECT 251.560000 1713.600000 253.160000 1716.960000 ;
        RECT 151.560000 1713.600000 153.160000 1716.960000 ;
        RECT 151.560000 1740.800000 153.160000 1744.160000 ;
        RECT 151.560000 1768.000000 153.160000 1771.360000 ;
        RECT 201.560000 1713.600000 203.160000 1716.960000 ;
        RECT 201.560000 1740.800000 203.160000 1744.160000 ;
        RECT 201.560000 1768.000000 203.160000 1771.360000 ;
        RECT 351.560000 1768.000000 353.160000 1771.360000 ;
        RECT 301.560000 1713.600000 303.160000 1716.960000 ;
        RECT 301.560000 1740.800000 303.160000 1744.160000 ;
        RECT 301.560000 1768.000000 303.160000 1771.360000 ;
        RECT 351.560000 1713.600000 353.160000 1716.960000 ;
        RECT 351.560000 1740.800000 353.160000 1744.160000 ;
        RECT 251.560000 1876.800000 253.160000 1880.160000 ;
        RECT 251.560000 1849.600000 253.160000 1852.960000 ;
        RECT 251.560000 1822.400000 253.160000 1825.760000 ;
        RECT 251.560000 1795.200000 253.160000 1798.560000 ;
        RECT 151.560000 1795.200000 153.160000 1798.560000 ;
        RECT 151.560000 1822.400000 153.160000 1825.760000 ;
        RECT 151.560000 1849.600000 153.160000 1852.960000 ;
        RECT 151.560000 1876.800000 153.160000 1880.160000 ;
        RECT 201.560000 1795.200000 203.160000 1798.560000 ;
        RECT 201.560000 1822.400000 203.160000 1825.760000 ;
        RECT 201.560000 1849.600000 203.160000 1852.960000 ;
        RECT 201.560000 1876.800000 203.160000 1880.160000 ;
        RECT 351.560000 1876.800000 353.160000 1880.160000 ;
        RECT 351.560000 1849.600000 353.160000 1852.960000 ;
        RECT 351.560000 1822.400000 353.160000 1825.760000 ;
        RECT 351.560000 1795.200000 353.160000 1798.560000 ;
        RECT 301.560000 1876.800000 303.160000 1880.160000 ;
        RECT 301.560000 1849.600000 303.160000 1852.960000 ;
        RECT 301.560000 1795.200000 303.160000 1798.560000 ;
        RECT 301.560000 1822.400000 303.160000 1825.760000 ;
        RECT 551.560000 1768.000000 553.160000 1771.360000 ;
        RECT 551.560000 1740.800000 553.160000 1744.160000 ;
        RECT 551.560000 1713.600000 553.160000 1716.960000 ;
        RECT 501.560000 1768.000000 503.160000 1771.360000 ;
        RECT 501.560000 1740.800000 503.160000 1744.160000 ;
        RECT 501.560000 1713.600000 503.160000 1716.960000 ;
        RECT 451.560000 1768.000000 453.160000 1771.360000 ;
        RECT 451.560000 1740.800000 453.160000 1744.160000 ;
        RECT 451.560000 1713.600000 453.160000 1716.960000 ;
        RECT 401.560000 1768.000000 403.160000 1771.360000 ;
        RECT 401.560000 1740.800000 403.160000 1744.160000 ;
        RECT 401.560000 1713.600000 403.160000 1716.960000 ;
        RECT 401.560000 1795.200000 403.160000 1798.560000 ;
        RECT 401.560000 1822.400000 403.160000 1825.760000 ;
        RECT 401.560000 1849.600000 403.160000 1852.960000 ;
        RECT 401.560000 1876.800000 403.160000 1880.160000 ;
        RECT 451.560000 1795.200000 453.160000 1798.560000 ;
        RECT 451.560000 1822.400000 453.160000 1825.760000 ;
        RECT 451.560000 1849.600000 453.160000 1852.960000 ;
        RECT 451.560000 1876.800000 453.160000 1880.160000 ;
        RECT 551.560000 1876.800000 553.160000 1880.160000 ;
        RECT 551.560000 1849.600000 553.160000 1852.960000 ;
        RECT 501.560000 1795.200000 503.160000 1798.560000 ;
        RECT 501.560000 1822.400000 503.160000 1825.760000 ;
        RECT 501.560000 1849.600000 503.160000 1852.960000 ;
        RECT 501.560000 1876.800000 503.160000 1880.160000 ;
        RECT 551.560000 1795.200000 553.160000 1798.560000 ;
        RECT 551.560000 1822.400000 553.160000 1825.760000 ;
        RECT 251.560000 1985.600000 253.160000 1988.960000 ;
        RECT 251.560000 1958.400000 253.160000 1961.760000 ;
        RECT 251.560000 1931.200000 253.160000 1934.560000 ;
        RECT 251.560000 1904.000000 253.160000 1907.360000 ;
        RECT 151.560000 1931.200000 153.160000 1934.560000 ;
        RECT 151.560000 1904.000000 153.160000 1907.360000 ;
        RECT 151.560000 1958.400000 153.160000 1961.760000 ;
        RECT 151.560000 1985.600000 153.160000 1988.960000 ;
        RECT 201.560000 1904.000000 203.160000 1907.360000 ;
        RECT 201.560000 1931.200000 203.160000 1934.560000 ;
        RECT 201.560000 1958.400000 203.160000 1961.760000 ;
        RECT 201.560000 1985.600000 203.160000 1988.960000 ;
        RECT 351.560000 1985.600000 353.160000 1988.960000 ;
        RECT 351.560000 1958.400000 353.160000 1961.760000 ;
        RECT 351.560000 1931.200000 353.160000 1934.560000 ;
        RECT 351.560000 1904.000000 353.160000 1907.360000 ;
        RECT 301.560000 1985.600000 303.160000 1988.960000 ;
        RECT 301.560000 1958.400000 303.160000 1961.760000 ;
        RECT 301.560000 1904.000000 303.160000 1907.360000 ;
        RECT 301.560000 1931.200000 303.160000 1934.560000 ;
        RECT 251.560000 2094.400000 253.160000 2097.760000 ;
        RECT 251.560000 2067.200000 253.160000 2070.560000 ;
        RECT 251.560000 2040.000000 253.160000 2043.360000 ;
        RECT 251.560000 2012.800000 253.160000 2016.160000 ;
        RECT 151.560000 2012.800000 153.160000 2016.160000 ;
        RECT 151.560000 2040.000000 153.160000 2043.360000 ;
        RECT 151.560000 2067.200000 153.160000 2070.560000 ;
        RECT 151.560000 2094.400000 153.160000 2097.760000 ;
        RECT 201.560000 2012.800000 203.160000 2016.160000 ;
        RECT 201.560000 2040.000000 203.160000 2043.360000 ;
        RECT 201.560000 2067.200000 203.160000 2070.560000 ;
        RECT 201.560000 2094.400000 203.160000 2097.760000 ;
        RECT 351.560000 2094.400000 353.160000 2097.760000 ;
        RECT 351.560000 2067.200000 353.160000 2070.560000 ;
        RECT 301.560000 2012.800000 303.160000 2016.160000 ;
        RECT 301.560000 2040.000000 303.160000 2043.360000 ;
        RECT 301.560000 2067.200000 303.160000 2070.560000 ;
        RECT 301.560000 2094.400000 303.160000 2097.760000 ;
        RECT 351.560000 2012.800000 353.160000 2016.160000 ;
        RECT 351.560000 2040.000000 353.160000 2043.360000 ;
        RECT 401.560000 1931.200000 403.160000 1934.560000 ;
        RECT 401.560000 1904.000000 403.160000 1907.360000 ;
        RECT 401.560000 1958.400000 403.160000 1961.760000 ;
        RECT 401.560000 1985.600000 403.160000 1988.960000 ;
        RECT 451.560000 1904.000000 453.160000 1907.360000 ;
        RECT 451.560000 1931.200000 453.160000 1934.560000 ;
        RECT 451.560000 1958.400000 453.160000 1961.760000 ;
        RECT 451.560000 1985.600000 453.160000 1988.960000 ;
        RECT 551.560000 1985.600000 553.160000 1988.960000 ;
        RECT 551.560000 1958.400000 553.160000 1961.760000 ;
        RECT 501.560000 1904.000000 503.160000 1907.360000 ;
        RECT 501.560000 1931.200000 503.160000 1934.560000 ;
        RECT 501.560000 1958.400000 503.160000 1961.760000 ;
        RECT 501.560000 1985.600000 503.160000 1988.960000 ;
        RECT 551.560000 1904.000000 553.160000 1907.360000 ;
        RECT 551.560000 1931.200000 553.160000 1934.560000 ;
        RECT 551.560000 2094.400000 553.160000 2097.760000 ;
        RECT 551.560000 2067.200000 553.160000 2070.560000 ;
        RECT 551.560000 2040.000000 553.160000 2043.360000 ;
        RECT 551.560000 2012.800000 553.160000 2016.160000 ;
        RECT 501.560000 2094.400000 503.160000 2097.760000 ;
        RECT 501.560000 2067.200000 503.160000 2070.560000 ;
        RECT 501.560000 2040.000000 503.160000 2043.360000 ;
        RECT 501.560000 2012.800000 503.160000 2016.160000 ;
        RECT 451.560000 2094.400000 453.160000 2097.760000 ;
        RECT 451.560000 2067.200000 453.160000 2070.560000 ;
        RECT 451.560000 2040.000000 453.160000 2043.360000 ;
        RECT 451.560000 2012.800000 453.160000 2016.160000 ;
        RECT 401.560000 2094.400000 403.160000 2097.760000 ;
        RECT 401.560000 2067.200000 403.160000 2070.560000 ;
        RECT 401.560000 2040.000000 403.160000 2043.360000 ;
        RECT 401.560000 2012.800000 403.160000 2016.160000 ;
        RECT 101.560000 2203.200000 103.160000 2206.560000 ;
        RECT 101.560000 2176.000000 103.160000 2179.360000 ;
        RECT 101.560000 2148.800000 103.160000 2152.160000 ;
        RECT 101.560000 2121.600000 103.160000 2124.960000 ;
        RECT 101.560000 2312.000000 103.160000 2315.360000 ;
        RECT 101.560000 2284.800000 103.160000 2288.160000 ;
        RECT 101.560000 2257.600000 103.160000 2260.960000 ;
        RECT 101.560000 2230.400000 103.160000 2233.760000 ;
        RECT 101.560000 2420.630000 103.160000 2422.050000 ;
        RECT 101.560000 2393.600000 103.160000 2396.960000 ;
        RECT 101.560000 2366.400000 103.160000 2369.760000 ;
        RECT 101.560000 2339.200000 103.160000 2342.560000 ;
        RECT 251.560000 2203.200000 253.160000 2206.560000 ;
        RECT 251.560000 2176.000000 253.160000 2179.360000 ;
        RECT 251.560000 2148.800000 253.160000 2152.160000 ;
        RECT 251.560000 2121.600000 253.160000 2124.960000 ;
        RECT 151.560000 2148.800000 153.160000 2152.160000 ;
        RECT 151.560000 2121.600000 153.160000 2124.960000 ;
        RECT 151.560000 2176.000000 153.160000 2179.360000 ;
        RECT 151.560000 2203.200000 153.160000 2206.560000 ;
        RECT 201.560000 2121.600000 203.160000 2124.960000 ;
        RECT 201.560000 2148.800000 203.160000 2152.160000 ;
        RECT 201.560000 2176.000000 203.160000 2179.360000 ;
        RECT 201.560000 2203.200000 203.160000 2206.560000 ;
        RECT 351.560000 2203.200000 353.160000 2206.560000 ;
        RECT 351.560000 2176.000000 353.160000 2179.360000 ;
        RECT 301.560000 2121.600000 303.160000 2124.960000 ;
        RECT 301.560000 2148.800000 303.160000 2152.160000 ;
        RECT 301.560000 2176.000000 303.160000 2179.360000 ;
        RECT 301.560000 2203.200000 303.160000 2206.560000 ;
        RECT 351.560000 2121.600000 353.160000 2124.960000 ;
        RECT 351.560000 2148.800000 353.160000 2152.160000 ;
        RECT 251.560000 2312.000000 253.160000 2315.360000 ;
        RECT 251.560000 2284.800000 253.160000 2288.160000 ;
        RECT 251.560000 2257.600000 253.160000 2260.960000 ;
        RECT 251.560000 2230.400000 253.160000 2233.760000 ;
        RECT 151.560000 2230.400000 153.160000 2233.760000 ;
        RECT 151.560000 2257.600000 153.160000 2260.960000 ;
        RECT 151.560000 2284.800000 153.160000 2288.160000 ;
        RECT 151.560000 2312.000000 153.160000 2315.360000 ;
        RECT 201.560000 2230.400000 203.160000 2233.760000 ;
        RECT 201.560000 2257.600000 203.160000 2260.960000 ;
        RECT 201.560000 2284.800000 203.160000 2288.160000 ;
        RECT 201.560000 2312.000000 203.160000 2315.360000 ;
        RECT 351.560000 2312.000000 353.160000 2315.360000 ;
        RECT 351.560000 2284.800000 353.160000 2288.160000 ;
        RECT 351.560000 2257.600000 353.160000 2260.960000 ;
        RECT 351.560000 2230.400000 353.160000 2233.760000 ;
        RECT 301.560000 2312.000000 303.160000 2315.360000 ;
        RECT 301.560000 2284.800000 303.160000 2288.160000 ;
        RECT 301.560000 2230.400000 303.160000 2233.760000 ;
        RECT 301.560000 2257.600000 303.160000 2260.960000 ;
        RECT 551.560000 2203.200000 553.160000 2206.560000 ;
        RECT 551.560000 2176.000000 553.160000 2179.360000 ;
        RECT 551.560000 2148.800000 553.160000 2152.160000 ;
        RECT 551.560000 2121.600000 553.160000 2124.960000 ;
        RECT 501.560000 2203.200000 503.160000 2206.560000 ;
        RECT 501.560000 2176.000000 503.160000 2179.360000 ;
        RECT 501.560000 2148.800000 503.160000 2152.160000 ;
        RECT 501.560000 2121.600000 503.160000 2124.960000 ;
        RECT 451.560000 2203.200000 453.160000 2206.560000 ;
        RECT 451.560000 2176.000000 453.160000 2179.360000 ;
        RECT 451.560000 2148.800000 453.160000 2152.160000 ;
        RECT 451.560000 2121.600000 453.160000 2124.960000 ;
        RECT 401.560000 2203.200000 403.160000 2206.560000 ;
        RECT 401.560000 2176.000000 403.160000 2179.360000 ;
        RECT 401.560000 2121.600000 403.160000 2124.960000 ;
        RECT 401.560000 2148.800000 403.160000 2152.160000 ;
        RECT 401.560000 2230.400000 403.160000 2233.760000 ;
        RECT 401.560000 2257.600000 403.160000 2260.960000 ;
        RECT 401.560000 2284.800000 403.160000 2288.160000 ;
        RECT 401.560000 2312.000000 403.160000 2315.360000 ;
        RECT 451.560000 2230.400000 453.160000 2233.760000 ;
        RECT 451.560000 2257.600000 453.160000 2260.960000 ;
        RECT 451.560000 2284.800000 453.160000 2288.160000 ;
        RECT 451.560000 2312.000000 453.160000 2315.360000 ;
        RECT 551.560000 2312.000000 553.160000 2315.360000 ;
        RECT 551.560000 2284.800000 553.160000 2288.160000 ;
        RECT 501.560000 2230.400000 503.160000 2233.760000 ;
        RECT 501.560000 2257.600000 503.160000 2260.960000 ;
        RECT 501.560000 2284.800000 503.160000 2288.160000 ;
        RECT 501.560000 2312.000000 503.160000 2315.360000 ;
        RECT 551.560000 2230.400000 553.160000 2233.760000 ;
        RECT 551.560000 2257.600000 553.160000 2260.960000 ;
        RECT 251.560000 2420.630000 253.160000 2422.050000 ;
        RECT 251.560000 2393.600000 253.160000 2396.960000 ;
        RECT 251.560000 2366.400000 253.160000 2369.760000 ;
        RECT 251.560000 2339.200000 253.160000 2342.560000 ;
        RECT 201.560000 2420.630000 203.160000 2422.050000 ;
        RECT 151.560000 2420.630000 153.160000 2422.050000 ;
        RECT 151.560000 2339.200000 153.160000 2342.560000 ;
        RECT 151.560000 2366.400000 153.160000 2369.760000 ;
        RECT 151.560000 2393.600000 153.160000 2396.960000 ;
        RECT 201.560000 2339.200000 203.160000 2342.560000 ;
        RECT 201.560000 2366.400000 203.160000 2369.760000 ;
        RECT 201.560000 2393.600000 203.160000 2396.960000 ;
        RECT 351.560000 2420.630000 353.160000 2422.050000 ;
        RECT 301.560000 2420.630000 303.160000 2422.050000 ;
        RECT 351.560000 2393.600000 353.160000 2396.960000 ;
        RECT 301.560000 2339.200000 303.160000 2342.560000 ;
        RECT 301.560000 2366.400000 303.160000 2369.760000 ;
        RECT 301.560000 2393.600000 303.160000 2396.960000 ;
        RECT 351.560000 2339.200000 353.160000 2342.560000 ;
        RECT 351.560000 2366.400000 353.160000 2369.760000 ;
        RECT 401.560000 2339.200000 403.160000 2342.560000 ;
        RECT 401.560000 2366.400000 403.160000 2369.760000 ;
        RECT 401.560000 2393.600000 403.160000 2396.960000 ;
        RECT 451.560000 2339.200000 453.160000 2342.560000 ;
        RECT 451.560000 2366.400000 453.160000 2369.760000 ;
        RECT 451.560000 2393.600000 453.160000 2396.960000 ;
        RECT 401.560000 2420.630000 403.160000 2422.050000 ;
        RECT 451.560000 2420.630000 453.160000 2422.050000 ;
        RECT 551.560000 2420.630000 553.160000 2422.050000 ;
        RECT 501.560000 2420.630000 503.160000 2422.050000 ;
        RECT 501.560000 2339.200000 503.160000 2342.560000 ;
        RECT 501.560000 2366.400000 503.160000 2369.760000 ;
        RECT 501.560000 2393.600000 503.160000 2396.960000 ;
        RECT 551.560000 2339.200000 553.160000 2342.560000 ;
        RECT 551.560000 2366.400000 553.160000 2369.760000 ;
        RECT 551.560000 2393.600000 553.160000 2396.960000 ;
        RECT 601.560000 1713.600000 603.160000 1716.960000 ;
        RECT 601.560000 1740.800000 603.160000 1744.160000 ;
        RECT 601.560000 1768.000000 603.160000 1771.360000 ;
        RECT 651.560000 1713.600000 653.160000 1716.960000 ;
        RECT 651.560000 1740.800000 653.160000 1744.160000 ;
        RECT 651.560000 1768.000000 653.160000 1771.360000 ;
        RECT 751.560000 1768.000000 753.160000 1771.360000 ;
        RECT 751.560000 1740.800000 753.160000 1744.160000 ;
        RECT 701.560000 1713.600000 703.160000 1716.960000 ;
        RECT 701.560000 1740.800000 703.160000 1744.160000 ;
        RECT 701.560000 1768.000000 703.160000 1771.360000 ;
        RECT 751.560000 1713.600000 753.160000 1716.960000 ;
        RECT 601.560000 1795.200000 603.160000 1798.560000 ;
        RECT 601.560000 1822.400000 603.160000 1825.760000 ;
        RECT 601.560000 1849.600000 603.160000 1852.960000 ;
        RECT 601.560000 1876.800000 603.160000 1880.160000 ;
        RECT 651.560000 1795.200000 653.160000 1798.560000 ;
        RECT 651.560000 1822.400000 653.160000 1825.760000 ;
        RECT 651.560000 1849.600000 653.160000 1852.960000 ;
        RECT 651.560000 1876.800000 653.160000 1880.160000 ;
        RECT 751.560000 1876.800000 753.160000 1880.160000 ;
        RECT 751.560000 1849.600000 753.160000 1852.960000 ;
        RECT 751.560000 1822.400000 753.160000 1825.760000 ;
        RECT 751.560000 1795.200000 753.160000 1798.560000 ;
        RECT 701.560000 1876.800000 703.160000 1880.160000 ;
        RECT 701.560000 1849.600000 703.160000 1852.960000 ;
        RECT 701.560000 1795.200000 703.160000 1798.560000 ;
        RECT 701.560000 1822.400000 703.160000 1825.760000 ;
        RECT 851.560000 1768.000000 853.160000 1771.360000 ;
        RECT 851.560000 1740.800000 853.160000 1744.160000 ;
        RECT 851.560000 1713.600000 853.160000 1716.960000 ;
        RECT 801.560000 1768.000000 803.160000 1771.360000 ;
        RECT 801.560000 1740.800000 803.160000 1744.160000 ;
        RECT 801.560000 1713.600000 803.160000 1716.960000 ;
        RECT 901.560000 1740.800000 903.160000 1744.160000 ;
        RECT 901.560000 1713.600000 903.160000 1716.960000 ;
        RECT 901.560000 1768.000000 903.160000 1771.360000 ;
        RECT 851.560000 1876.800000 853.160000 1880.160000 ;
        RECT 851.560000 1849.600000 853.160000 1852.960000 ;
        RECT 851.560000 1822.400000 853.160000 1825.760000 ;
        RECT 851.560000 1795.200000 853.160000 1798.560000 ;
        RECT 801.560000 1876.800000 803.160000 1880.160000 ;
        RECT 801.560000 1849.600000 803.160000 1852.960000 ;
        RECT 801.560000 1822.400000 803.160000 1825.760000 ;
        RECT 801.560000 1795.200000 803.160000 1798.560000 ;
        RECT 901.560000 1822.400000 903.160000 1825.760000 ;
        RECT 901.560000 1795.200000 903.160000 1798.560000 ;
        RECT 901.560000 1876.800000 903.160000 1880.160000 ;
        RECT 901.560000 1849.600000 903.160000 1852.960000 ;
        RECT 601.560000 1904.000000 603.160000 1907.360000 ;
        RECT 601.560000 1931.200000 603.160000 1934.560000 ;
        RECT 601.560000 1958.400000 603.160000 1961.760000 ;
        RECT 601.560000 1985.600000 603.160000 1988.960000 ;
        RECT 651.560000 1904.000000 653.160000 1907.360000 ;
        RECT 651.560000 1931.200000 653.160000 1934.560000 ;
        RECT 651.560000 1958.400000 653.160000 1961.760000 ;
        RECT 651.560000 1985.600000 653.160000 1988.960000 ;
        RECT 751.560000 1985.600000 753.160000 1988.960000 ;
        RECT 751.560000 1958.400000 753.160000 1961.760000 ;
        RECT 751.560000 1931.200000 753.160000 1934.560000 ;
        RECT 751.560000 1904.000000 753.160000 1907.360000 ;
        RECT 701.560000 1985.600000 703.160000 1988.960000 ;
        RECT 701.560000 1958.400000 703.160000 1961.760000 ;
        RECT 701.560000 1904.000000 703.160000 1907.360000 ;
        RECT 701.560000 1931.200000 703.160000 1934.560000 ;
        RECT 601.560000 2012.800000 603.160000 2016.160000 ;
        RECT 601.560000 2040.000000 603.160000 2043.360000 ;
        RECT 601.560000 2067.200000 603.160000 2070.560000 ;
        RECT 601.560000 2094.400000 603.160000 2097.760000 ;
        RECT 651.560000 2012.800000 653.160000 2016.160000 ;
        RECT 651.560000 2040.000000 653.160000 2043.360000 ;
        RECT 651.560000 2067.200000 653.160000 2070.560000 ;
        RECT 651.560000 2094.400000 653.160000 2097.760000 ;
        RECT 751.560000 2094.400000 753.160000 2097.760000 ;
        RECT 701.560000 2012.800000 703.160000 2016.160000 ;
        RECT 701.560000 2040.000000 703.160000 2043.360000 ;
        RECT 701.560000 2067.200000 703.160000 2070.560000 ;
        RECT 701.560000 2094.400000 703.160000 2097.760000 ;
        RECT 751.560000 2012.800000 753.160000 2016.160000 ;
        RECT 751.560000 2040.000000 753.160000 2043.360000 ;
        RECT 751.560000 2067.200000 753.160000 2070.560000 ;
        RECT 851.560000 1985.600000 853.160000 1988.960000 ;
        RECT 851.560000 1958.400000 853.160000 1961.760000 ;
        RECT 851.560000 1931.200000 853.160000 1934.560000 ;
        RECT 851.560000 1904.000000 853.160000 1907.360000 ;
        RECT 801.560000 1985.600000 803.160000 1988.960000 ;
        RECT 801.560000 1958.400000 803.160000 1961.760000 ;
        RECT 801.560000 1931.200000 803.160000 1934.560000 ;
        RECT 801.560000 1904.000000 803.160000 1907.360000 ;
        RECT 901.560000 1931.200000 903.160000 1934.560000 ;
        RECT 901.560000 1904.000000 903.160000 1907.360000 ;
        RECT 901.560000 1985.600000 903.160000 1988.960000 ;
        RECT 901.560000 1958.400000 903.160000 1961.760000 ;
        RECT 851.560000 2094.400000 853.160000 2097.760000 ;
        RECT 851.560000 2067.200000 853.160000 2070.560000 ;
        RECT 851.560000 2040.000000 853.160000 2043.360000 ;
        RECT 851.560000 2012.800000 853.160000 2016.160000 ;
        RECT 801.560000 2094.400000 803.160000 2097.760000 ;
        RECT 801.560000 2067.200000 803.160000 2070.560000 ;
        RECT 801.560000 2040.000000 803.160000 2043.360000 ;
        RECT 801.560000 2012.800000 803.160000 2016.160000 ;
        RECT 901.560000 2040.000000 903.160000 2043.360000 ;
        RECT 901.560000 2012.800000 903.160000 2016.160000 ;
        RECT 901.560000 2094.400000 903.160000 2097.760000 ;
        RECT 901.560000 2067.200000 903.160000 2070.560000 ;
        RECT 601.560000 2121.600000 603.160000 2124.960000 ;
        RECT 601.560000 2148.800000 603.160000 2152.160000 ;
        RECT 601.560000 2176.000000 603.160000 2179.360000 ;
        RECT 601.560000 2203.200000 603.160000 2206.560000 ;
        RECT 651.560000 2121.600000 653.160000 2124.960000 ;
        RECT 651.560000 2148.800000 653.160000 2152.160000 ;
        RECT 651.560000 2176.000000 653.160000 2179.360000 ;
        RECT 651.560000 2203.200000 653.160000 2206.560000 ;
        RECT 751.560000 2203.200000 753.160000 2206.560000 ;
        RECT 701.560000 2121.600000 703.160000 2124.960000 ;
        RECT 701.560000 2148.800000 703.160000 2152.160000 ;
        RECT 701.560000 2176.000000 703.160000 2179.360000 ;
        RECT 701.560000 2203.200000 703.160000 2206.560000 ;
        RECT 751.560000 2121.600000 753.160000 2124.960000 ;
        RECT 751.560000 2148.800000 753.160000 2152.160000 ;
        RECT 751.560000 2176.000000 753.160000 2179.360000 ;
        RECT 601.560000 2230.400000 603.160000 2233.760000 ;
        RECT 601.560000 2257.600000 603.160000 2260.960000 ;
        RECT 601.560000 2284.800000 603.160000 2288.160000 ;
        RECT 601.560000 2312.000000 603.160000 2315.360000 ;
        RECT 651.560000 2230.400000 653.160000 2233.760000 ;
        RECT 651.560000 2257.600000 653.160000 2260.960000 ;
        RECT 651.560000 2284.800000 653.160000 2288.160000 ;
        RECT 651.560000 2312.000000 653.160000 2315.360000 ;
        RECT 751.560000 2312.000000 753.160000 2315.360000 ;
        RECT 751.560000 2284.800000 753.160000 2288.160000 ;
        RECT 751.560000 2257.600000 753.160000 2260.960000 ;
        RECT 751.560000 2230.400000 753.160000 2233.760000 ;
        RECT 701.560000 2312.000000 703.160000 2315.360000 ;
        RECT 701.560000 2284.800000 703.160000 2288.160000 ;
        RECT 701.560000 2230.400000 703.160000 2233.760000 ;
        RECT 701.560000 2257.600000 703.160000 2260.960000 ;
        RECT 851.560000 2203.200000 853.160000 2206.560000 ;
        RECT 851.560000 2176.000000 853.160000 2179.360000 ;
        RECT 851.560000 2148.800000 853.160000 2152.160000 ;
        RECT 851.560000 2121.600000 853.160000 2124.960000 ;
        RECT 801.560000 2203.200000 803.160000 2206.560000 ;
        RECT 801.560000 2176.000000 803.160000 2179.360000 ;
        RECT 801.560000 2148.800000 803.160000 2152.160000 ;
        RECT 801.560000 2121.600000 803.160000 2124.960000 ;
        RECT 901.560000 2148.800000 903.160000 2152.160000 ;
        RECT 901.560000 2121.600000 903.160000 2124.960000 ;
        RECT 901.560000 2203.200000 903.160000 2206.560000 ;
        RECT 901.560000 2176.000000 903.160000 2179.360000 ;
        RECT 851.560000 2312.000000 853.160000 2315.360000 ;
        RECT 851.560000 2284.800000 853.160000 2288.160000 ;
        RECT 851.560000 2257.600000 853.160000 2260.960000 ;
        RECT 851.560000 2230.400000 853.160000 2233.760000 ;
        RECT 801.560000 2312.000000 803.160000 2315.360000 ;
        RECT 801.560000 2284.800000 803.160000 2288.160000 ;
        RECT 801.560000 2257.600000 803.160000 2260.960000 ;
        RECT 801.560000 2230.400000 803.160000 2233.760000 ;
        RECT 901.560000 2257.600000 903.160000 2260.960000 ;
        RECT 901.560000 2230.400000 903.160000 2233.760000 ;
        RECT 901.560000 2312.000000 903.160000 2315.360000 ;
        RECT 901.560000 2284.800000 903.160000 2288.160000 ;
        RECT 651.560000 2420.630000 653.160000 2422.050000 ;
        RECT 601.560000 2420.630000 603.160000 2422.050000 ;
        RECT 601.560000 2339.200000 603.160000 2342.560000 ;
        RECT 601.560000 2366.400000 603.160000 2369.760000 ;
        RECT 601.560000 2393.600000 603.160000 2396.960000 ;
        RECT 651.560000 2339.200000 653.160000 2342.560000 ;
        RECT 651.560000 2366.400000 653.160000 2369.760000 ;
        RECT 651.560000 2393.600000 653.160000 2396.960000 ;
        RECT 751.560000 2420.630000 753.160000 2422.050000 ;
        RECT 701.560000 2420.630000 703.160000 2422.050000 ;
        RECT 751.560000 2393.600000 753.160000 2396.960000 ;
        RECT 751.560000 2366.400000 753.160000 2369.760000 ;
        RECT 701.560000 2339.200000 703.160000 2342.560000 ;
        RECT 701.560000 2366.400000 703.160000 2369.760000 ;
        RECT 701.560000 2393.600000 703.160000 2396.960000 ;
        RECT 751.560000 2339.200000 753.160000 2342.560000 ;
        RECT 851.560000 2420.630000 853.160000 2422.050000 ;
        RECT 801.560000 2420.630000 803.160000 2422.050000 ;
        RECT 851.560000 2393.600000 853.160000 2396.960000 ;
        RECT 851.560000 2366.400000 853.160000 2369.760000 ;
        RECT 851.560000 2339.200000 853.160000 2342.560000 ;
        RECT 801.560000 2393.600000 803.160000 2396.960000 ;
        RECT 801.560000 2366.400000 803.160000 2369.760000 ;
        RECT 801.560000 2339.200000 803.160000 2342.560000 ;
        RECT 901.560000 2366.400000 903.160000 2369.760000 ;
        RECT 901.560000 2339.200000 903.160000 2342.560000 ;
        RECT 901.560000 2420.630000 903.160000 2422.050000 ;
        RECT 901.560000 2393.600000 903.160000 2396.960000 ;
        RECT 101.560000 2638.400000 103.160000 2641.760000 ;
        RECT 101.560000 2611.200000 103.160000 2614.560000 ;
        RECT 101.560000 2584.000000 103.160000 2587.360000 ;
        RECT 101.560000 2556.800000 103.160000 2560.160000 ;
        RECT 101.560000 2720.000000 103.160000 2723.360000 ;
        RECT 101.560000 2692.800000 103.160000 2696.160000 ;
        RECT 101.560000 2665.600000 103.160000 2668.960000 ;
        RECT 101.560000 2828.800000 103.160000 2832.160000 ;
        RECT 101.560000 2801.600000 103.160000 2804.960000 ;
        RECT 101.560000 2774.400000 103.160000 2777.760000 ;
        RECT 101.560000 2747.200000 103.160000 2750.560000 ;
        RECT 101.560000 2937.600000 103.160000 2940.960000 ;
        RECT 101.560000 2910.400000 103.160000 2913.760000 ;
        RECT 101.560000 2883.200000 103.160000 2886.560000 ;
        RECT 101.560000 2856.000000 103.160000 2859.360000 ;
        RECT 351.560000 2638.400000 353.160000 2641.760000 ;
        RECT 301.560000 2638.400000 303.160000 2641.760000 ;
        RECT 251.560000 2638.400000 253.160000 2641.760000 ;
        RECT 201.560000 2638.400000 203.160000 2641.760000 ;
        RECT 151.560000 2638.400000 153.160000 2641.760000 ;
        RECT 251.560000 2611.200000 253.160000 2614.560000 ;
        RECT 251.560000 2584.000000 253.160000 2587.360000 ;
        RECT 251.560000 2556.800000 253.160000 2560.160000 ;
        RECT 151.560000 2556.800000 153.160000 2560.160000 ;
        RECT 151.560000 2584.000000 153.160000 2587.360000 ;
        RECT 151.560000 2611.200000 153.160000 2614.560000 ;
        RECT 201.560000 2556.800000 203.160000 2560.160000 ;
        RECT 201.560000 2584.000000 203.160000 2587.360000 ;
        RECT 201.560000 2611.200000 203.160000 2614.560000 ;
        RECT 351.560000 2611.200000 353.160000 2614.560000 ;
        RECT 301.560000 2556.800000 303.160000 2560.160000 ;
        RECT 301.560000 2584.000000 303.160000 2587.360000 ;
        RECT 301.560000 2611.200000 303.160000 2614.560000 ;
        RECT 351.560000 2556.800000 353.160000 2560.160000 ;
        RECT 351.560000 2584.000000 353.160000 2587.360000 ;
        RECT 251.560000 2720.000000 253.160000 2723.360000 ;
        RECT 251.560000 2692.800000 253.160000 2696.160000 ;
        RECT 251.560000 2665.600000 253.160000 2668.960000 ;
        RECT 151.560000 2665.600000 153.160000 2668.960000 ;
        RECT 151.560000 2692.800000 153.160000 2696.160000 ;
        RECT 151.560000 2720.000000 153.160000 2723.360000 ;
        RECT 201.560000 2665.600000 203.160000 2668.960000 ;
        RECT 201.560000 2692.800000 203.160000 2696.160000 ;
        RECT 201.560000 2720.000000 203.160000 2723.360000 ;
        RECT 351.560000 2720.000000 353.160000 2723.360000 ;
        RECT 301.560000 2665.600000 303.160000 2668.960000 ;
        RECT 301.560000 2692.800000 303.160000 2696.160000 ;
        RECT 301.560000 2720.000000 303.160000 2723.360000 ;
        RECT 351.560000 2665.600000 353.160000 2668.960000 ;
        RECT 351.560000 2692.800000 353.160000 2696.160000 ;
        RECT 551.560000 2638.400000 553.160000 2641.760000 ;
        RECT 501.560000 2638.400000 503.160000 2641.760000 ;
        RECT 451.560000 2638.400000 453.160000 2641.760000 ;
        RECT 401.560000 2638.400000 403.160000 2641.760000 ;
        RECT 551.560000 2611.200000 553.160000 2614.560000 ;
        RECT 551.560000 2584.000000 553.160000 2587.360000 ;
        RECT 551.560000 2556.800000 553.160000 2560.160000 ;
        RECT 501.560000 2611.200000 503.160000 2614.560000 ;
        RECT 501.560000 2584.000000 503.160000 2587.360000 ;
        RECT 501.560000 2556.800000 503.160000 2560.160000 ;
        RECT 451.560000 2611.200000 453.160000 2614.560000 ;
        RECT 451.560000 2584.000000 453.160000 2587.360000 ;
        RECT 451.560000 2556.800000 453.160000 2560.160000 ;
        RECT 401.560000 2611.200000 403.160000 2614.560000 ;
        RECT 401.560000 2584.000000 403.160000 2587.360000 ;
        RECT 401.560000 2556.800000 403.160000 2560.160000 ;
        RECT 551.560000 2720.000000 553.160000 2723.360000 ;
        RECT 551.560000 2692.800000 553.160000 2696.160000 ;
        RECT 551.560000 2665.600000 553.160000 2668.960000 ;
        RECT 501.560000 2720.000000 503.160000 2723.360000 ;
        RECT 501.560000 2692.800000 503.160000 2696.160000 ;
        RECT 501.560000 2665.600000 503.160000 2668.960000 ;
        RECT 451.560000 2720.000000 453.160000 2723.360000 ;
        RECT 451.560000 2692.800000 453.160000 2696.160000 ;
        RECT 451.560000 2665.600000 453.160000 2668.960000 ;
        RECT 401.560000 2720.000000 403.160000 2723.360000 ;
        RECT 401.560000 2692.800000 403.160000 2696.160000 ;
        RECT 401.560000 2665.600000 403.160000 2668.960000 ;
        RECT 251.560000 2828.800000 253.160000 2832.160000 ;
        RECT 251.560000 2801.600000 253.160000 2804.960000 ;
        RECT 251.560000 2774.400000 253.160000 2777.760000 ;
        RECT 251.560000 2747.200000 253.160000 2750.560000 ;
        RECT 151.560000 2747.200000 153.160000 2750.560000 ;
        RECT 151.560000 2774.400000 153.160000 2777.760000 ;
        RECT 151.560000 2801.600000 153.160000 2804.960000 ;
        RECT 151.560000 2828.800000 153.160000 2832.160000 ;
        RECT 201.560000 2747.200000 203.160000 2750.560000 ;
        RECT 201.560000 2774.400000 203.160000 2777.760000 ;
        RECT 201.560000 2801.600000 203.160000 2804.960000 ;
        RECT 201.560000 2828.800000 203.160000 2832.160000 ;
        RECT 351.560000 2828.800000 353.160000 2832.160000 ;
        RECT 351.560000 2801.600000 353.160000 2804.960000 ;
        RECT 351.560000 2774.400000 353.160000 2777.760000 ;
        RECT 351.560000 2747.200000 353.160000 2750.560000 ;
        RECT 301.560000 2828.800000 303.160000 2832.160000 ;
        RECT 301.560000 2801.600000 303.160000 2804.960000 ;
        RECT 301.560000 2747.200000 303.160000 2750.560000 ;
        RECT 301.560000 2774.400000 303.160000 2777.760000 ;
        RECT 251.560000 2937.600000 253.160000 2940.960000 ;
        RECT 251.560000 2910.400000 253.160000 2913.760000 ;
        RECT 251.560000 2883.200000 253.160000 2886.560000 ;
        RECT 251.560000 2856.000000 253.160000 2859.360000 ;
        RECT 151.560000 2856.000000 153.160000 2859.360000 ;
        RECT 151.560000 2883.200000 153.160000 2886.560000 ;
        RECT 151.560000 2910.400000 153.160000 2913.760000 ;
        RECT 151.560000 2937.600000 153.160000 2940.960000 ;
        RECT 201.560000 2856.000000 203.160000 2859.360000 ;
        RECT 201.560000 2883.200000 203.160000 2886.560000 ;
        RECT 201.560000 2910.400000 203.160000 2913.760000 ;
        RECT 201.560000 2937.600000 203.160000 2940.960000 ;
        RECT 351.560000 2937.600000 353.160000 2940.960000 ;
        RECT 351.560000 2910.400000 353.160000 2913.760000 ;
        RECT 351.560000 2883.200000 353.160000 2886.560000 ;
        RECT 351.560000 2856.000000 353.160000 2859.360000 ;
        RECT 301.560000 2937.600000 303.160000 2940.960000 ;
        RECT 301.560000 2910.400000 303.160000 2913.760000 ;
        RECT 301.560000 2856.000000 303.160000 2859.360000 ;
        RECT 301.560000 2883.200000 303.160000 2886.560000 ;
        RECT 401.560000 2747.200000 403.160000 2750.560000 ;
        RECT 401.560000 2774.400000 403.160000 2777.760000 ;
        RECT 401.560000 2801.600000 403.160000 2804.960000 ;
        RECT 401.560000 2828.800000 403.160000 2832.160000 ;
        RECT 451.560000 2747.200000 453.160000 2750.560000 ;
        RECT 451.560000 2774.400000 453.160000 2777.760000 ;
        RECT 451.560000 2801.600000 453.160000 2804.960000 ;
        RECT 451.560000 2828.800000 453.160000 2832.160000 ;
        RECT 551.560000 2828.800000 553.160000 2832.160000 ;
        RECT 551.560000 2801.600000 553.160000 2804.960000 ;
        RECT 501.560000 2747.200000 503.160000 2750.560000 ;
        RECT 501.560000 2774.400000 503.160000 2777.760000 ;
        RECT 501.560000 2801.600000 503.160000 2804.960000 ;
        RECT 501.560000 2828.800000 503.160000 2832.160000 ;
        RECT 551.560000 2747.200000 553.160000 2750.560000 ;
        RECT 551.560000 2774.400000 553.160000 2777.760000 ;
        RECT 401.560000 2856.000000 403.160000 2859.360000 ;
        RECT 401.560000 2883.200000 403.160000 2886.560000 ;
        RECT 401.560000 2910.400000 403.160000 2913.760000 ;
        RECT 401.560000 2937.600000 403.160000 2940.960000 ;
        RECT 451.560000 2856.000000 453.160000 2859.360000 ;
        RECT 451.560000 2883.200000 453.160000 2886.560000 ;
        RECT 451.560000 2910.400000 453.160000 2913.760000 ;
        RECT 451.560000 2937.600000 453.160000 2940.960000 ;
        RECT 551.560000 2937.600000 553.160000 2940.960000 ;
        RECT 551.560000 2910.400000 553.160000 2913.760000 ;
        RECT 501.560000 2856.000000 503.160000 2859.360000 ;
        RECT 501.560000 2883.200000 503.160000 2886.560000 ;
        RECT 501.560000 2910.400000 503.160000 2913.760000 ;
        RECT 501.560000 2937.600000 503.160000 2940.960000 ;
        RECT 551.560000 2856.000000 553.160000 2859.360000 ;
        RECT 551.560000 2883.200000 553.160000 2886.560000 ;
        RECT 101.560000 3046.400000 103.160000 3049.760000 ;
        RECT 101.560000 3019.200000 103.160000 3022.560000 ;
        RECT 101.560000 2992.000000 103.160000 2995.360000 ;
        RECT 101.560000 2964.800000 103.160000 2968.160000 ;
        RECT 101.560000 3155.200000 103.160000 3158.560000 ;
        RECT 101.560000 3128.000000 103.160000 3131.360000 ;
        RECT 101.560000 3100.800000 103.160000 3104.160000 ;
        RECT 101.560000 3073.600000 103.160000 3076.960000 ;
        RECT 101.560000 3264.000000 103.160000 3267.360000 ;
        RECT 101.560000 3236.800000 103.160000 3240.160000 ;
        RECT 101.560000 3209.600000 103.160000 3212.960000 ;
        RECT 101.560000 3182.400000 103.160000 3185.760000 ;
        RECT 101.560000 3291.200000 103.160000 3294.560000 ;
        RECT 251.560000 3046.400000 253.160000 3049.760000 ;
        RECT 251.560000 3019.200000 253.160000 3022.560000 ;
        RECT 251.560000 2992.000000 253.160000 2995.360000 ;
        RECT 251.560000 2964.800000 253.160000 2968.160000 ;
        RECT 151.560000 2992.000000 153.160000 2995.360000 ;
        RECT 151.560000 2964.800000 153.160000 2968.160000 ;
        RECT 151.560000 3019.200000 153.160000 3022.560000 ;
        RECT 151.560000 3046.400000 153.160000 3049.760000 ;
        RECT 201.560000 2964.800000 203.160000 2968.160000 ;
        RECT 201.560000 2992.000000 203.160000 2995.360000 ;
        RECT 201.560000 3019.200000 203.160000 3022.560000 ;
        RECT 201.560000 3046.400000 203.160000 3049.760000 ;
        RECT 351.560000 3046.400000 353.160000 3049.760000 ;
        RECT 351.560000 3019.200000 353.160000 3022.560000 ;
        RECT 301.560000 2964.800000 303.160000 2968.160000 ;
        RECT 301.560000 2992.000000 303.160000 2995.360000 ;
        RECT 301.560000 3019.200000 303.160000 3022.560000 ;
        RECT 301.560000 3046.400000 303.160000 3049.760000 ;
        RECT 351.560000 2964.800000 353.160000 2968.160000 ;
        RECT 351.560000 2992.000000 353.160000 2995.360000 ;
        RECT 251.560000 3155.200000 253.160000 3158.560000 ;
        RECT 251.560000 3128.000000 253.160000 3131.360000 ;
        RECT 251.560000 3100.800000 253.160000 3104.160000 ;
        RECT 251.560000 3073.600000 253.160000 3076.960000 ;
        RECT 151.560000 3073.600000 153.160000 3076.960000 ;
        RECT 151.560000 3100.800000 153.160000 3104.160000 ;
        RECT 151.560000 3128.000000 153.160000 3131.360000 ;
        RECT 151.560000 3155.200000 153.160000 3158.560000 ;
        RECT 201.560000 3073.600000 203.160000 3076.960000 ;
        RECT 201.560000 3100.800000 203.160000 3104.160000 ;
        RECT 201.560000 3128.000000 203.160000 3131.360000 ;
        RECT 201.560000 3155.200000 203.160000 3158.560000 ;
        RECT 351.560000 3155.200000 353.160000 3158.560000 ;
        RECT 351.560000 3128.000000 353.160000 3131.360000 ;
        RECT 301.560000 3073.600000 303.160000 3076.960000 ;
        RECT 301.560000 3100.800000 303.160000 3104.160000 ;
        RECT 301.560000 3128.000000 303.160000 3131.360000 ;
        RECT 301.560000 3155.200000 303.160000 3158.560000 ;
        RECT 351.560000 3073.600000 353.160000 3076.960000 ;
        RECT 351.560000 3100.800000 353.160000 3104.160000 ;
        RECT 551.560000 3046.400000 553.160000 3049.760000 ;
        RECT 551.560000 3019.200000 553.160000 3022.560000 ;
        RECT 551.560000 2992.000000 553.160000 2995.360000 ;
        RECT 551.560000 2964.800000 553.160000 2968.160000 ;
        RECT 501.560000 3046.400000 503.160000 3049.760000 ;
        RECT 501.560000 3019.200000 503.160000 3022.560000 ;
        RECT 501.560000 2992.000000 503.160000 2995.360000 ;
        RECT 501.560000 2964.800000 503.160000 2968.160000 ;
        RECT 451.560000 3046.400000 453.160000 3049.760000 ;
        RECT 451.560000 3019.200000 453.160000 3022.560000 ;
        RECT 451.560000 2992.000000 453.160000 2995.360000 ;
        RECT 451.560000 2964.800000 453.160000 2968.160000 ;
        RECT 401.560000 3046.400000 403.160000 3049.760000 ;
        RECT 401.560000 3019.200000 403.160000 3022.560000 ;
        RECT 401.560000 2964.800000 403.160000 2968.160000 ;
        RECT 401.560000 2992.000000 403.160000 2995.360000 ;
        RECT 551.560000 3155.200000 553.160000 3158.560000 ;
        RECT 551.560000 3128.000000 553.160000 3131.360000 ;
        RECT 551.560000 3100.800000 553.160000 3104.160000 ;
        RECT 551.560000 3073.600000 553.160000 3076.960000 ;
        RECT 501.560000 3155.200000 503.160000 3158.560000 ;
        RECT 501.560000 3128.000000 503.160000 3131.360000 ;
        RECT 501.560000 3100.800000 503.160000 3104.160000 ;
        RECT 501.560000 3073.600000 503.160000 3076.960000 ;
        RECT 451.560000 3155.200000 453.160000 3158.560000 ;
        RECT 451.560000 3128.000000 453.160000 3131.360000 ;
        RECT 451.560000 3100.800000 453.160000 3104.160000 ;
        RECT 451.560000 3073.600000 453.160000 3076.960000 ;
        RECT 401.560000 3155.200000 403.160000 3158.560000 ;
        RECT 401.560000 3128.000000 403.160000 3131.360000 ;
        RECT 401.560000 3100.800000 403.160000 3104.160000 ;
        RECT 401.560000 3073.600000 403.160000 3076.960000 ;
        RECT 251.560000 3264.000000 253.160000 3267.360000 ;
        RECT 251.560000 3236.800000 253.160000 3240.160000 ;
        RECT 251.560000 3209.600000 253.160000 3212.960000 ;
        RECT 251.560000 3182.400000 253.160000 3185.760000 ;
        RECT 151.560000 3182.400000 153.160000 3185.760000 ;
        RECT 151.560000 3209.600000 153.160000 3212.960000 ;
        RECT 151.560000 3236.800000 153.160000 3240.160000 ;
        RECT 151.560000 3264.000000 153.160000 3267.360000 ;
        RECT 201.560000 3182.400000 203.160000 3185.760000 ;
        RECT 201.560000 3209.600000 203.160000 3212.960000 ;
        RECT 201.560000 3236.800000 203.160000 3240.160000 ;
        RECT 201.560000 3264.000000 203.160000 3267.360000 ;
        RECT 351.560000 3264.000000 353.160000 3267.360000 ;
        RECT 351.560000 3236.800000 353.160000 3240.160000 ;
        RECT 351.560000 3209.600000 353.160000 3212.960000 ;
        RECT 351.560000 3182.400000 353.160000 3185.760000 ;
        RECT 301.560000 3264.000000 303.160000 3267.360000 ;
        RECT 301.560000 3236.800000 303.160000 3240.160000 ;
        RECT 301.560000 3182.400000 303.160000 3185.760000 ;
        RECT 301.560000 3209.600000 303.160000 3212.960000 ;
        RECT 251.560000 3291.200000 253.160000 3294.560000 ;
        RECT 201.560000 3291.200000 203.160000 3294.560000 ;
        RECT 151.560000 3291.200000 153.160000 3294.560000 ;
        RECT 351.560000 3291.200000 353.160000 3294.560000 ;
        RECT 301.560000 3291.200000 303.160000 3294.560000 ;
        RECT 401.560000 3182.400000 403.160000 3185.760000 ;
        RECT 401.560000 3209.600000 403.160000 3212.960000 ;
        RECT 401.560000 3236.800000 403.160000 3240.160000 ;
        RECT 401.560000 3264.000000 403.160000 3267.360000 ;
        RECT 451.560000 3182.400000 453.160000 3185.760000 ;
        RECT 451.560000 3209.600000 453.160000 3212.960000 ;
        RECT 451.560000 3236.800000 453.160000 3240.160000 ;
        RECT 451.560000 3264.000000 453.160000 3267.360000 ;
        RECT 551.560000 3264.000000 553.160000 3267.360000 ;
        RECT 551.560000 3236.800000 553.160000 3240.160000 ;
        RECT 501.560000 3182.400000 503.160000 3185.760000 ;
        RECT 501.560000 3209.600000 503.160000 3212.960000 ;
        RECT 501.560000 3236.800000 503.160000 3240.160000 ;
        RECT 501.560000 3264.000000 503.160000 3267.360000 ;
        RECT 551.560000 3182.400000 553.160000 3185.760000 ;
        RECT 551.560000 3209.600000 553.160000 3212.960000 ;
        RECT 451.560000 3291.200000 453.160000 3294.560000 ;
        RECT 401.560000 3291.200000 403.160000 3294.560000 ;
        RECT 551.560000 3291.200000 553.160000 3294.560000 ;
        RECT 501.560000 3291.200000 503.160000 3294.560000 ;
        RECT 751.560000 2638.400000 753.160000 2641.760000 ;
        RECT 701.560000 2638.400000 703.160000 2641.760000 ;
        RECT 651.560000 2638.400000 653.160000 2641.760000 ;
        RECT 601.560000 2638.400000 603.160000 2641.760000 ;
        RECT 601.560000 2556.800000 603.160000 2560.160000 ;
        RECT 601.560000 2584.000000 603.160000 2587.360000 ;
        RECT 601.560000 2611.200000 603.160000 2614.560000 ;
        RECT 651.560000 2556.800000 653.160000 2560.160000 ;
        RECT 651.560000 2584.000000 653.160000 2587.360000 ;
        RECT 651.560000 2611.200000 653.160000 2614.560000 ;
        RECT 751.560000 2611.200000 753.160000 2614.560000 ;
        RECT 751.560000 2584.000000 753.160000 2587.360000 ;
        RECT 701.560000 2556.800000 703.160000 2560.160000 ;
        RECT 701.560000 2584.000000 703.160000 2587.360000 ;
        RECT 701.560000 2611.200000 703.160000 2614.560000 ;
        RECT 751.560000 2556.800000 753.160000 2560.160000 ;
        RECT 601.560000 2665.600000 603.160000 2668.960000 ;
        RECT 601.560000 2692.800000 603.160000 2696.160000 ;
        RECT 601.560000 2720.000000 603.160000 2723.360000 ;
        RECT 651.560000 2665.600000 653.160000 2668.960000 ;
        RECT 651.560000 2692.800000 653.160000 2696.160000 ;
        RECT 651.560000 2720.000000 653.160000 2723.360000 ;
        RECT 751.560000 2720.000000 753.160000 2723.360000 ;
        RECT 751.560000 2692.800000 753.160000 2696.160000 ;
        RECT 701.560000 2665.600000 703.160000 2668.960000 ;
        RECT 701.560000 2692.800000 703.160000 2696.160000 ;
        RECT 701.560000 2720.000000 703.160000 2723.360000 ;
        RECT 751.560000 2665.600000 753.160000 2668.960000 ;
        RECT 901.560000 2638.400000 903.160000 2641.760000 ;
        RECT 851.560000 2638.400000 853.160000 2641.760000 ;
        RECT 801.560000 2638.400000 803.160000 2641.760000 ;
        RECT 851.560000 2611.200000 853.160000 2614.560000 ;
        RECT 851.560000 2584.000000 853.160000 2587.360000 ;
        RECT 851.560000 2556.800000 853.160000 2560.160000 ;
        RECT 801.560000 2611.200000 803.160000 2614.560000 ;
        RECT 801.560000 2584.000000 803.160000 2587.360000 ;
        RECT 801.560000 2556.800000 803.160000 2560.160000 ;
        RECT 901.560000 2584.000000 903.160000 2587.360000 ;
        RECT 901.560000 2556.800000 903.160000 2560.160000 ;
        RECT 901.560000 2611.200000 903.160000 2614.560000 ;
        RECT 851.560000 2720.000000 853.160000 2723.360000 ;
        RECT 851.560000 2692.800000 853.160000 2696.160000 ;
        RECT 851.560000 2665.600000 853.160000 2668.960000 ;
        RECT 801.560000 2720.000000 803.160000 2723.360000 ;
        RECT 801.560000 2692.800000 803.160000 2696.160000 ;
        RECT 801.560000 2665.600000 803.160000 2668.960000 ;
        RECT 901.560000 2665.600000 903.160000 2668.960000 ;
        RECT 901.560000 2720.000000 903.160000 2723.360000 ;
        RECT 901.560000 2692.800000 903.160000 2696.160000 ;
        RECT 601.560000 2747.200000 603.160000 2750.560000 ;
        RECT 601.560000 2774.400000 603.160000 2777.760000 ;
        RECT 601.560000 2801.600000 603.160000 2804.960000 ;
        RECT 601.560000 2828.800000 603.160000 2832.160000 ;
        RECT 651.560000 2747.200000 653.160000 2750.560000 ;
        RECT 651.560000 2774.400000 653.160000 2777.760000 ;
        RECT 651.560000 2801.600000 653.160000 2804.960000 ;
        RECT 651.560000 2828.800000 653.160000 2832.160000 ;
        RECT 751.560000 2828.800000 753.160000 2832.160000 ;
        RECT 751.560000 2801.600000 753.160000 2804.960000 ;
        RECT 751.560000 2774.400000 753.160000 2777.760000 ;
        RECT 751.560000 2747.200000 753.160000 2750.560000 ;
        RECT 701.560000 2828.800000 703.160000 2832.160000 ;
        RECT 701.560000 2801.600000 703.160000 2804.960000 ;
        RECT 701.560000 2747.200000 703.160000 2750.560000 ;
        RECT 701.560000 2774.400000 703.160000 2777.760000 ;
        RECT 601.560000 2856.000000 603.160000 2859.360000 ;
        RECT 601.560000 2883.200000 603.160000 2886.560000 ;
        RECT 601.560000 2910.400000 603.160000 2913.760000 ;
        RECT 601.560000 2937.600000 603.160000 2940.960000 ;
        RECT 651.560000 2856.000000 653.160000 2859.360000 ;
        RECT 651.560000 2883.200000 653.160000 2886.560000 ;
        RECT 651.560000 2910.400000 653.160000 2913.760000 ;
        RECT 651.560000 2937.600000 653.160000 2940.960000 ;
        RECT 751.560000 2937.600000 753.160000 2940.960000 ;
        RECT 751.560000 2910.400000 753.160000 2913.760000 ;
        RECT 751.560000 2883.200000 753.160000 2886.560000 ;
        RECT 751.560000 2856.000000 753.160000 2859.360000 ;
        RECT 701.560000 2937.600000 703.160000 2940.960000 ;
        RECT 701.560000 2910.400000 703.160000 2913.760000 ;
        RECT 701.560000 2856.000000 703.160000 2859.360000 ;
        RECT 701.560000 2883.200000 703.160000 2886.560000 ;
        RECT 851.560000 2828.800000 853.160000 2832.160000 ;
        RECT 851.560000 2801.600000 853.160000 2804.960000 ;
        RECT 851.560000 2774.400000 853.160000 2777.760000 ;
        RECT 851.560000 2747.200000 853.160000 2750.560000 ;
        RECT 801.560000 2828.800000 803.160000 2832.160000 ;
        RECT 801.560000 2801.600000 803.160000 2804.960000 ;
        RECT 801.560000 2774.400000 803.160000 2777.760000 ;
        RECT 801.560000 2747.200000 803.160000 2750.560000 ;
        RECT 901.560000 2774.400000 903.160000 2777.760000 ;
        RECT 901.560000 2747.200000 903.160000 2750.560000 ;
        RECT 901.560000 2828.800000 903.160000 2832.160000 ;
        RECT 901.560000 2801.600000 903.160000 2804.960000 ;
        RECT 851.560000 2937.600000 853.160000 2940.960000 ;
        RECT 851.560000 2910.400000 853.160000 2913.760000 ;
        RECT 851.560000 2883.200000 853.160000 2886.560000 ;
        RECT 851.560000 2856.000000 853.160000 2859.360000 ;
        RECT 801.560000 2937.600000 803.160000 2940.960000 ;
        RECT 801.560000 2910.400000 803.160000 2913.760000 ;
        RECT 801.560000 2883.200000 803.160000 2886.560000 ;
        RECT 801.560000 2856.000000 803.160000 2859.360000 ;
        RECT 901.560000 2883.200000 903.160000 2886.560000 ;
        RECT 901.560000 2856.000000 903.160000 2859.360000 ;
        RECT 901.560000 2937.600000 903.160000 2940.960000 ;
        RECT 901.560000 2910.400000 903.160000 2913.760000 ;
        RECT 601.560000 2964.800000 603.160000 2968.160000 ;
        RECT 601.560000 2992.000000 603.160000 2995.360000 ;
        RECT 601.560000 3019.200000 603.160000 3022.560000 ;
        RECT 601.560000 3046.400000 603.160000 3049.760000 ;
        RECT 651.560000 2964.800000 653.160000 2968.160000 ;
        RECT 651.560000 2992.000000 653.160000 2995.360000 ;
        RECT 651.560000 3019.200000 653.160000 3022.560000 ;
        RECT 651.560000 3046.400000 653.160000 3049.760000 ;
        RECT 751.560000 3046.400000 753.160000 3049.760000 ;
        RECT 701.560000 2964.800000 703.160000 2968.160000 ;
        RECT 701.560000 2992.000000 703.160000 2995.360000 ;
        RECT 701.560000 3019.200000 703.160000 3022.560000 ;
        RECT 701.560000 3046.400000 703.160000 3049.760000 ;
        RECT 751.560000 2964.800000 753.160000 2968.160000 ;
        RECT 751.560000 2992.000000 753.160000 2995.360000 ;
        RECT 751.560000 3019.200000 753.160000 3022.560000 ;
        RECT 601.560000 3073.600000 603.160000 3076.960000 ;
        RECT 601.560000 3100.800000 603.160000 3104.160000 ;
        RECT 601.560000 3128.000000 603.160000 3131.360000 ;
        RECT 601.560000 3155.200000 603.160000 3158.560000 ;
        RECT 651.560000 3073.600000 653.160000 3076.960000 ;
        RECT 651.560000 3100.800000 653.160000 3104.160000 ;
        RECT 651.560000 3128.000000 653.160000 3131.360000 ;
        RECT 651.560000 3155.200000 653.160000 3158.560000 ;
        RECT 751.560000 3155.200000 753.160000 3158.560000 ;
        RECT 701.560000 3073.600000 703.160000 3076.960000 ;
        RECT 701.560000 3100.800000 703.160000 3104.160000 ;
        RECT 701.560000 3128.000000 703.160000 3131.360000 ;
        RECT 701.560000 3155.200000 703.160000 3158.560000 ;
        RECT 751.560000 3073.600000 753.160000 3076.960000 ;
        RECT 751.560000 3100.800000 753.160000 3104.160000 ;
        RECT 751.560000 3128.000000 753.160000 3131.360000 ;
        RECT 851.560000 3046.400000 853.160000 3049.760000 ;
        RECT 851.560000 3019.200000 853.160000 3022.560000 ;
        RECT 851.560000 2992.000000 853.160000 2995.360000 ;
        RECT 851.560000 2964.800000 853.160000 2968.160000 ;
        RECT 801.560000 3046.400000 803.160000 3049.760000 ;
        RECT 801.560000 3019.200000 803.160000 3022.560000 ;
        RECT 801.560000 2992.000000 803.160000 2995.360000 ;
        RECT 801.560000 2964.800000 803.160000 2968.160000 ;
        RECT 901.560000 2992.000000 903.160000 2995.360000 ;
        RECT 901.560000 2964.800000 903.160000 2968.160000 ;
        RECT 901.560000 3046.400000 903.160000 3049.760000 ;
        RECT 901.560000 3019.200000 903.160000 3022.560000 ;
        RECT 851.560000 3155.200000 853.160000 3158.560000 ;
        RECT 851.560000 3128.000000 853.160000 3131.360000 ;
        RECT 851.560000 3100.800000 853.160000 3104.160000 ;
        RECT 851.560000 3073.600000 853.160000 3076.960000 ;
        RECT 801.560000 3155.200000 803.160000 3158.560000 ;
        RECT 801.560000 3128.000000 803.160000 3131.360000 ;
        RECT 801.560000 3100.800000 803.160000 3104.160000 ;
        RECT 801.560000 3073.600000 803.160000 3076.960000 ;
        RECT 901.560000 3100.800000 903.160000 3104.160000 ;
        RECT 901.560000 3073.600000 903.160000 3076.960000 ;
        RECT 901.560000 3155.200000 903.160000 3158.560000 ;
        RECT 901.560000 3128.000000 903.160000 3131.360000 ;
        RECT 601.560000 3182.400000 603.160000 3185.760000 ;
        RECT 601.560000 3209.600000 603.160000 3212.960000 ;
        RECT 601.560000 3236.800000 603.160000 3240.160000 ;
        RECT 601.560000 3264.000000 603.160000 3267.360000 ;
        RECT 651.560000 3182.400000 653.160000 3185.760000 ;
        RECT 651.560000 3209.600000 653.160000 3212.960000 ;
        RECT 651.560000 3236.800000 653.160000 3240.160000 ;
        RECT 651.560000 3264.000000 653.160000 3267.360000 ;
        RECT 751.560000 3264.000000 753.160000 3267.360000 ;
        RECT 751.560000 3236.800000 753.160000 3240.160000 ;
        RECT 751.560000 3209.600000 753.160000 3212.960000 ;
        RECT 751.560000 3182.400000 753.160000 3185.760000 ;
        RECT 701.560000 3264.000000 703.160000 3267.360000 ;
        RECT 701.560000 3236.800000 703.160000 3240.160000 ;
        RECT 701.560000 3182.400000 703.160000 3185.760000 ;
        RECT 701.560000 3209.600000 703.160000 3212.960000 ;
        RECT 651.560000 3291.200000 653.160000 3294.560000 ;
        RECT 601.560000 3291.200000 603.160000 3294.560000 ;
        RECT 751.560000 3291.200000 753.160000 3294.560000 ;
        RECT 701.560000 3291.200000 703.160000 3294.560000 ;
        RECT 851.560000 3264.000000 853.160000 3267.360000 ;
        RECT 851.560000 3236.800000 853.160000 3240.160000 ;
        RECT 851.560000 3209.600000 853.160000 3212.960000 ;
        RECT 851.560000 3182.400000 853.160000 3185.760000 ;
        RECT 801.560000 3264.000000 803.160000 3267.360000 ;
        RECT 801.560000 3236.800000 803.160000 3240.160000 ;
        RECT 801.560000 3209.600000 803.160000 3212.960000 ;
        RECT 801.560000 3182.400000 803.160000 3185.760000 ;
        RECT 901.560000 3209.600000 903.160000 3212.960000 ;
        RECT 901.560000 3182.400000 903.160000 3185.760000 ;
        RECT 901.560000 3264.000000 903.160000 3267.360000 ;
        RECT 901.560000 3236.800000 903.160000 3240.160000 ;
        RECT 851.560000 3291.200000 853.160000 3294.560000 ;
        RECT 801.560000 3291.200000 803.160000 3294.560000 ;
        RECT 901.560000 3291.200000 903.160000 3294.560000 ;
      LAYER met5 ;
        RECT 16.280000 1686.400000 2810.880000 1689.760000 ;
        RECT 16.280000 843.200000 2810.880000 846.560000 ;
        RECT 0.000000 16.320000 2827.160000 24.480000 ;
        RECT 16.280000 27.200000 2810.880000 30.560000 ;
        RECT 16.280000 54.400000 2810.880000 57.760000 ;
        RECT 16.280000 81.600000 2810.880000 84.960000 ;
        RECT 16.280000 108.800000 2810.880000 112.160000 ;
        RECT 16.280000 136.000000 2810.880000 139.360000 ;
        RECT 16.280000 163.200000 2810.880000 166.560000 ;
        RECT 16.280000 190.400000 2810.880000 193.760000 ;
        RECT 16.280000 217.600000 2810.880000 220.960000 ;
        RECT 16.280000 244.800000 2810.880000 248.160000 ;
        RECT 16.280000 272.000000 2810.880000 275.360000 ;
        RECT 16.280000 299.200000 2810.880000 302.560000 ;
        RECT 16.280000 326.400000 2810.880000 329.760000 ;
        RECT 16.280000 353.600000 2810.880000 356.960000 ;
        RECT 16.280000 380.800000 2810.880000 384.160000 ;
        RECT 16.280000 408.000000 2810.880000 411.360000 ;
        RECT 16.280000 435.200000 2810.880000 438.560000 ;
        RECT 16.280000 462.400000 2810.880000 465.760000 ;
        RECT 16.280000 489.600000 2810.880000 492.960000 ;
        RECT 16.280000 516.800000 2810.880000 520.160000 ;
        RECT 16.280000 544.000000 2810.880000 547.360000 ;
        RECT 16.280000 571.200000 2810.880000 574.560000 ;
        RECT 16.280000 598.400000 2810.880000 601.760000 ;
        RECT 16.280000 625.600000 2810.880000 628.960000 ;
        RECT 16.280000 652.800000 2810.880000 656.160000 ;
        RECT 16.280000 680.000000 2810.880000 683.360000 ;
        RECT 16.280000 707.200000 2810.880000 710.560000 ;
        RECT 16.280000 734.400000 2810.880000 737.760000 ;
        RECT 16.280000 788.800000 2810.880000 792.160000 ;
        RECT 16.280000 761.600000 2810.880000 764.960000 ;
        RECT 16.280000 816.000000 2810.880000 819.360000 ;
        RECT 16.280000 870.400000 2810.880000 873.760000 ;
        RECT 16.280000 897.600000 2810.880000 900.960000 ;
        RECT 16.280000 924.800000 2810.880000 928.160000 ;
        RECT 16.280000 952.000000 2810.880000 955.360000 ;
        RECT 16.280000 979.200000 2810.880000 982.560000 ;
        RECT 16.280000 1006.400000 2810.880000 1009.760000 ;
        RECT 16.280000 1033.600000 2810.880000 1036.960000 ;
        RECT 16.280000 1060.800000 2810.880000 1064.160000 ;
        RECT 16.280000 1088.000000 2810.880000 1091.360000 ;
        RECT 16.280000 1115.200000 2810.880000 1118.560000 ;
        RECT 16.280000 1142.400000 2810.880000 1145.760000 ;
        RECT 16.280000 1169.600000 2810.880000 1172.960000 ;
        RECT 16.280000 1196.800000 2810.880000 1200.160000 ;
        RECT 16.280000 1224.000000 2810.880000 1227.360000 ;
        RECT 16.280000 1251.200000 2810.880000 1254.560000 ;
        RECT 16.280000 1278.400000 2810.880000 1281.760000 ;
        RECT 16.280000 1305.600000 2810.880000 1308.960000 ;
        RECT 16.280000 1332.800000 2810.880000 1336.160000 ;
        RECT 16.280000 1360.000000 2810.880000 1363.360000 ;
        RECT 16.280000 1387.200000 2810.880000 1390.560000 ;
        RECT 16.280000 1414.400000 2810.880000 1417.760000 ;
        RECT 16.280000 1441.600000 2810.880000 1444.960000 ;
        RECT 16.280000 1468.800000 2810.880000 1472.160000 ;
        RECT 16.280000 1496.000000 2810.880000 1499.360000 ;
        RECT 16.280000 1523.200000 2810.880000 1526.560000 ;
        RECT 16.280000 1550.400000 2810.880000 1553.760000 ;
        RECT 16.280000 1577.600000 2810.880000 1580.960000 ;
        RECT 16.280000 1604.800000 2810.880000 1608.160000 ;
        RECT 16.280000 1632.000000 2810.880000 1635.360000 ;
        RECT 16.280000 1659.200000 2810.880000 1662.560000 ;
        RECT 16.280000 2529.600000 2810.880000 2532.960000 ;
        RECT 16.280000 1740.800000 2810.880000 1744.160000 ;
        RECT 16.280000 1713.600000 2810.880000 1716.960000 ;
        RECT 16.280000 1768.000000 2810.880000 1771.360000 ;
        RECT 16.280000 1795.200000 2810.880000 1798.560000 ;
        RECT 16.280000 1822.400000 2810.880000 1825.760000 ;
        RECT 16.280000 1849.600000 2810.880000 1852.960000 ;
        RECT 16.280000 1876.800000 2810.880000 1880.160000 ;
        RECT 16.280000 1904.000000 2810.880000 1907.360000 ;
        RECT 16.280000 1931.200000 2810.880000 1934.560000 ;
        RECT 16.280000 1958.400000 2810.880000 1961.760000 ;
        RECT 16.280000 1985.600000 2810.880000 1988.960000 ;
        RECT 16.280000 2012.800000 2810.880000 2016.160000 ;
        RECT 16.280000 2040.000000 2810.880000 2043.360000 ;
        RECT 16.280000 2067.200000 2810.880000 2070.560000 ;
        RECT 16.280000 2094.400000 2810.880000 2097.760000 ;
        RECT 16.280000 2121.600000 2810.880000 2124.960000 ;
        RECT 16.280000 2148.800000 2810.880000 2152.160000 ;
        RECT 16.280000 2176.000000 2810.880000 2179.360000 ;
        RECT 16.280000 2203.200000 2810.880000 2206.560000 ;
        RECT 16.280000 2230.400000 2810.880000 2233.760000 ;
        RECT 16.280000 2257.600000 2810.880000 2260.960000 ;
        RECT 16.280000 2284.800000 2810.880000 2288.160000 ;
        RECT 16.280000 2312.000000 2810.880000 2315.360000 ;
        RECT 16.280000 2339.200000 2810.880000 2342.560000 ;
        RECT 16.280000 2366.400000 2810.880000 2369.760000 ;
        RECT 16.280000 2393.600000 2810.880000 2396.960000 ;
        RECT 16.280000 2420.800000 2810.880000 2424.160000 ;
        RECT 16.280000 2448.000000 2810.880000 2451.360000 ;
        RECT 16.280000 2475.200000 2810.880000 2478.560000 ;
        RECT 16.280000 2502.400000 2810.880000 2505.760000 ;
        RECT 16.280000 2638.400000 2810.880000 2641.760000 ;
        RECT 16.280000 2584.000000 2810.880000 2587.360000 ;
        RECT 16.280000 2556.800000 2810.880000 2560.160000 ;
        RECT 16.280000 2611.200000 2810.880000 2614.560000 ;
        RECT 16.280000 2665.600000 2810.880000 2668.960000 ;
        RECT 16.280000 2692.800000 2810.880000 2696.160000 ;
        RECT 16.280000 2720.000000 2810.880000 2723.360000 ;
        RECT 16.280000 2747.200000 2810.880000 2750.560000 ;
        RECT 16.280000 2774.400000 2810.880000 2777.760000 ;
        RECT 16.280000 2801.600000 2810.880000 2804.960000 ;
        RECT 16.280000 2828.800000 2810.880000 2832.160000 ;
        RECT 16.280000 2856.000000 2810.880000 2859.360000 ;
        RECT 16.280000 2883.200000 2810.880000 2886.560000 ;
        RECT 16.280000 2910.400000 2810.880000 2913.760000 ;
        RECT 16.280000 2937.600000 2810.880000 2940.960000 ;
        RECT 16.280000 2964.800000 2810.880000 2968.160000 ;
        RECT 16.280000 2992.000000 2810.880000 2995.360000 ;
        RECT 16.280000 3019.200000 2810.880000 3022.560000 ;
        RECT 16.280000 3046.400000 2810.880000 3049.760000 ;
        RECT 16.280000 3073.600000 2810.880000 3076.960000 ;
        RECT 16.280000 3100.800000 2810.880000 3104.160000 ;
        RECT 16.280000 3128.000000 2810.880000 3131.360000 ;
        RECT 16.280000 3155.200000 2810.880000 3158.560000 ;
        RECT 16.280000 3182.400000 2810.880000 3185.760000 ;
        RECT 16.280000 3209.600000 2810.880000 3212.960000 ;
        RECT 16.280000 3236.800000 2810.880000 3240.160000 ;
        RECT 16.280000 3264.000000 2810.880000 3267.360000 ;
        RECT 16.280000 3291.200000 2810.880000 3294.560000 ;
        RECT 16.280000 3318.400000 2810.880000 3321.760000 ;
        RECT 0.000000 3351.040000 2827.160000 3359.200000 ;
        RECT 101.560000 2420.630000 103.160000 2422.050000 ;
        RECT 251.560000 2420.630000 253.160000 2422.050000 ;
        RECT 201.560000 2420.630000 203.160000 2422.050000 ;
        RECT 151.560000 2420.630000 153.160000 2422.050000 ;
        RECT 351.560000 2420.630000 353.160000 2422.050000 ;
        RECT 301.560000 2420.630000 303.160000 2422.050000 ;
        RECT 401.560000 2420.630000 403.160000 2422.050000 ;
        RECT 451.560000 2420.630000 453.160000 2422.050000 ;
        RECT 551.560000 2420.630000 553.160000 2422.050000 ;
        RECT 501.560000 2420.630000 503.160000 2422.050000 ;
        RECT 651.560000 2420.630000 653.160000 2422.050000 ;
        RECT 601.560000 2420.630000 603.160000 2422.050000 ;
        RECT 751.560000 2420.630000 753.160000 2422.050000 ;
        RECT 701.560000 2420.630000 703.160000 2422.050000 ;
        RECT 851.560000 2420.630000 853.160000 2422.050000 ;
        RECT 801.560000 2420.630000 803.160000 2422.050000 ;
        RECT 901.560000 2420.630000 903.160000 2422.050000 ;
    END
# end of P/G power stripe data as pin

  END VDD
  OBS
    LAYER li1 ;
      RECT 0.000000 0.000000 2827.160000 3377.220000 ;
    LAYER met1 ;
      RECT 0.000000 0.000000 2827.160000 3377.220000 ;
    LAYER met2 ;
      RECT 0.000000 0.000000 2827.160000 3377.220000 ;
    LAYER met3 ;
      RECT 0.000000 0.000000 2827.160000 3377.220000 ;
    LAYER met4 ;
      RECT 0.000000 0.000000 2827.160000 3377.220000 ;
    LAYER met5 ;
      RECT 0.000000 0.000000 2827.160000 3377.220000 ;
  END
END user_proj_example

END LIBRARY
